VERSION 5.8 ;
BUSBITCHARS "[]" ;
DIVIDERCHAR "/" ;

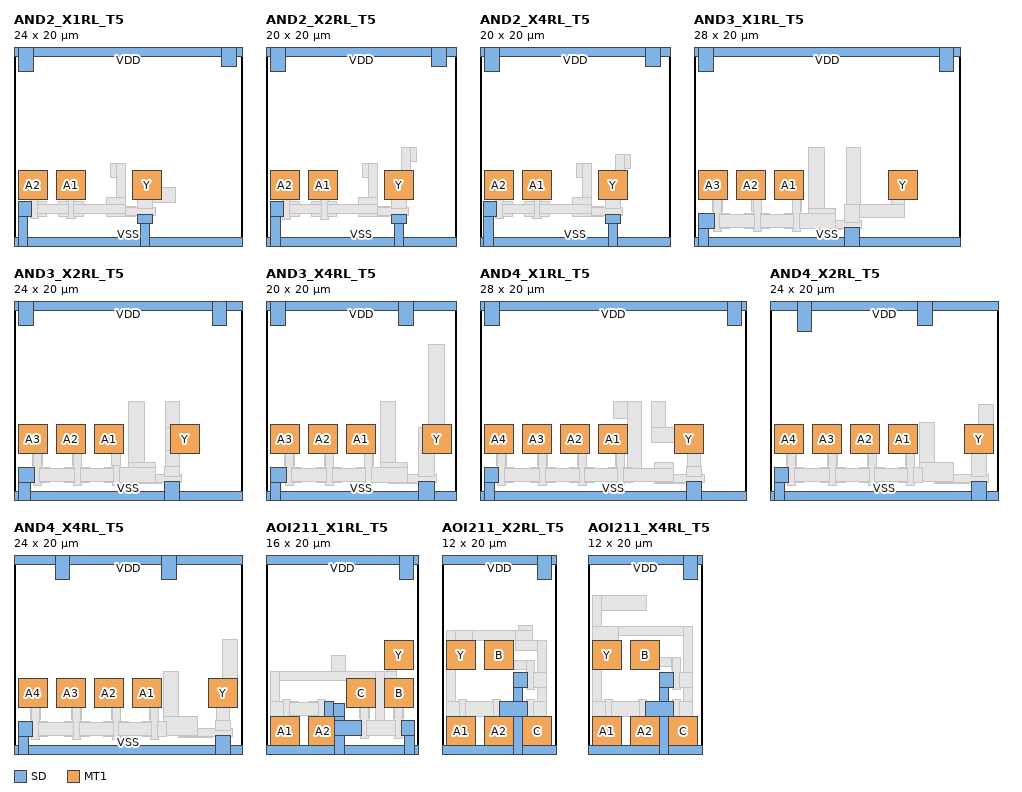
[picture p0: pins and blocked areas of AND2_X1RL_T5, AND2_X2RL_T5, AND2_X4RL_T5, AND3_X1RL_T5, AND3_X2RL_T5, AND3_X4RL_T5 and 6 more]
MACRO AND2_X1RL_T5
  CLASS CORE ;
  ORIGIN 0 0 ;
  FOREIGN AND2_X1RL_T5 0 0 ;
  SIZE 24 BY 20 ;
  SYMMETRY X Y ;
  SITE CoreSite_T5 ;
  PIN VDD
    DIRECTION INOUT ;
    USE POWER ;
    PORT
      LAYER SD ;
        RECT 0 19.5 24 20.5 ;
        RECT 21.8 18.5 23.4 20.5 ;
        RECT 0.5 17.9 2 20.5 ;
    END
  END VDD
  PIN VSS
    DIRECTION INOUT ;
    USE GROUND ;
    PORT
      LAYER SD ;
        RECT 0 -0.5 24 0.5 ;
        RECT 13 1.9 14.6 2.9 ;
        RECT 13.3 -0.5 14.3 2.9 ;
        RECT 0.45 2.7 1.825 4.3 ;
        RECT 0.45 -0.5 1.45 4.3 ;
    END
  END VSS
  PIN A1
    DIRECTION INPUT ;
    USE SIGNAL ;
    PORT
      LAYER MT1 ;
        RECT 4.5 4.5 7.5 7.5 ;
    END
  END A1
  PIN A2
    DIRECTION INPUT ;
    USE SIGNAL ;
    PORT
      LAYER MT1 ;
        RECT 0.5 4.5 3.5 7.5 ;
    END
  END A2
  PIN Y
    DIRECTION INPUT ;
    USE SIGNAL ;
    PORT
      LAYER MT1 ;
        RECT 12.5 4.5 15.5 7.5 ;
    END
  END Y
  OBS
    LAYER VIA1 ;
      RECT 13.25 5.25 14.75 6.75 ;
      RECT 5.25 5.25 6.75 6.75 ;
      RECT 1.25 5.25 2.75 6.75 ;
    LAYER GATE ;
      RECT 9.75 2.7 11.75 4.7 ;
      RECT 9.75 2.7 12.75 3.7 ;
      RECT 9.75 2.775 14.85 3.625 ;
      RECT 4.75 4.75 7.25 7.25 ;
      RECT 5.5 4.55 6.5 7.25 ;
      RECT 5.575 2.45 6.425 7.25 ;
      RECT 0.75 4.75 3.25 7.25 ;
      RECT 1.575 4.55 2.575 7.25 ;
      RECT 1.7 2.45 2.55 7.25 ;
      RECT 12.75 4.75 15.25 7.25 ;
    LAYER CONT ;
      RECT 13.5 5.5 14.5 6.5 ;
      RECT 10.25 3.2 11.25 4.2 ;
    LAYER SD ;
      RECT 12.75 4.75 15.25 7.25 ;
      RECT 13 4.2 17 5.7 ;
      RECT 13 3.5 14.6 7.25 ;
      RECT 10.15 6.75 11.75 8.25 ;
      RECT 10.75 2.7 11.75 8.25 ;
      RECT 9.75 2.7 11.75 4.7 ;
      RECT 6.3 2.7 7.3 4.3 ;
      RECT 6.3 3 11.75 4 ;
      RECT 4.7 2.7 5.7 4.3 ;
      RECT 2.425 2.7 3.425 4.3 ;
      RECT 2.425 3 5.7 4 ;
  END
END AND2_X1RL_T5

MACRO AND2_X2RL_T5
  CLASS CORE ;
  ORIGIN 0 0 ;
  FOREIGN AND2_X2RL_T5 0 0 ;
  SIZE 20 BY 20 ;
  SYMMETRY X Y ;
  SITE CoreSite_T5 ;
  PIN VDD
    DIRECTION INOUT ;
    USE POWER ;
    PORT
      LAYER SD ;
        RECT 0 19.5 20 20.5 ;
        RECT 17.45 18.5 19.05 20.5 ;
        RECT 0.5 17.9 2 20.5 ;
    END
  END VDD
  PIN VSS
    DIRECTION INOUT ;
    USE GROUND ;
    PORT
      LAYER SD ;
        RECT 0 -0.5 20 0.5 ;
        RECT 13.2 1.9 14.8 2.9 ;
        RECT 13.5 -0.5 14.5 2.9 ;
        RECT 0.5 2.65 1.875 4.25 ;
        RECT 0.5 -0.5 1.5 4.25 ;
    END
  END VSS
  PIN A1
    DIRECTION INPUT ;
    USE SIGNAL ;
    PORT
      LAYER MT1 ;
        RECT 4.5 4.5 7.5 7.5 ;
    END
  END A1
  PIN A2
    DIRECTION INPUT ;
    USE SIGNAL ;
    PORT
      LAYER MT1 ;
        RECT 0.5 4.5 3.5 7.5 ;
    END
  END A2
  PIN Y
    DIRECTION INPUT ;
    USE SIGNAL ;
    PORT
      LAYER MT1 ;
        RECT 12.5 4.5 15.5 7.5 ;
    END
  END Y
  OBS
    LAYER VIA1 ;
      RECT 13.25 5.25 14.75 6.75 ;
      RECT 5.25 5.25 6.75 6.75 ;
      RECT 1.25 5.25 2.75 6.75 ;
    LAYER GATE ;
      RECT 9.75 2.7 11.75 4.7 ;
      RECT 9.75 2.7 12.95 3.7 ;
      RECT 9.75 2.775 15.05 3.625 ;
      RECT 4.75 4.75 7.25 7.25 ;
      RECT 5.625 4.5 6.625 7.25 ;
      RECT 5.7 2.4 6.55 7.25 ;
      RECT 0.75 4.75 3.25 7.25 ;
      RECT 1.675 4.5 2.675 7.25 ;
      RECT 1.75 2.4 2.6 7.25 ;
      RECT 12.75 4.75 15.25 7.25 ;
    LAYER CONT ;
      RECT 13.5 5.5 14.5 6.5 ;
      RECT 10.25 3.2 11.25 4.2 ;
    LAYER SD ;
      RECT 14.25 8.5 15.85 10 ;
      RECT 14.25 4.75 15.25 10 ;
      RECT 12.75 4.75 15.25 7.25 ;
      RECT 13.2 3.5 14.8 7.25 ;
      RECT 10.15 6.75 11.75 8.25 ;
      RECT 10.75 2.7 11.75 8.25 ;
      RECT 9.75 2.7 11.75 4.7 ;
      RECT 6.425 2.65 7.425 4.25 ;
      RECT 6.425 3 11.75 4 ;
      RECT 4.825 2.65 5.825 4.25 ;
      RECT 2.475 2.65 3.475 4.25 ;
      RECT 2.475 2.95 5.825 3.95 ;
  END
END AND2_X2RL_T5

MACRO AND2_X4RL_T5
  CLASS CORE ;
  ORIGIN 0 0 ;
  FOREIGN AND2_X4RL_T5 0 0 ;
  SIZE 20 BY 20 ;
  SYMMETRY X Y ;
  SITE CoreSite_T5 ;
  PIN VDD
    DIRECTION INOUT ;
    USE POWER ;
    PORT
      LAYER SD ;
        RECT 0 19.5 20 20.5 ;
        RECT 17.45 18.5 19.05 20.5 ;
        RECT 0.5 17.9 2 20.5 ;
    END
  END VDD
  PIN VSS
    DIRECTION INOUT ;
    USE GROUND ;
    PORT
      LAYER SD ;
        RECT 0 -0.5 20 0.5 ;
        RECT 13.2 1.9 14.8 2.9 ;
        RECT 13.5 -0.5 14.5 2.9 ;
        RECT 0.4 2.7 1.775 4.3 ;
        RECT 0.4 -0.5 1.4 4.3 ;
    END
  END VSS
  PIN A1
    DIRECTION INPUT ;
    USE SIGNAL ;
    PORT
      LAYER MT1 ;
        RECT 4.5 4.5 7.5 7.5 ;
    END
  END A1
  PIN A2
    DIRECTION INPUT ;
    USE SIGNAL ;
    PORT
      LAYER MT1 ;
        RECT 0.5 4.5 3.5 7.5 ;
    END
  END A2
  PIN Y
    DIRECTION INPUT ;
    USE SIGNAL ;
    PORT
      LAYER MT1 ;
        RECT 12.5 4.5 15.5 7.5 ;
    END
  END Y
  OBS
    LAYER VIA1 ;
      RECT 13.25 5.25 14.75 6.75 ;
      RECT 5.25 5.25 6.75 6.75 ;
      RECT 1.25 5.25 2.75 6.75 ;
    LAYER GATE ;
      RECT 9.75 2.7 11.75 4.7 ;
      RECT 9.75 2.7 12.95 3.7 ;
      RECT 9.75 2.775 15.05 3.625 ;
      RECT 4.75 4.75 7.25 7.25 ;
      RECT 5.5 4.55 6.5 7.25 ;
      RECT 5.575 2.45 6.425 7.25 ;
      RECT 0.75 4.75 3.25 7.25 ;
      RECT 1.575 4.55 2.575 7.25 ;
      RECT 1.65 2.45 2.5 7.25 ;
      RECT 12.75 4.75 15.25 7.25 ;
    LAYER CONT ;
      RECT 13.5 5.5 14.5 6.5 ;
      RECT 10.25 3.2 11.25 4.2 ;
    LAYER SD ;
      RECT 14.25 7.75 15.85 9.25 ;
      RECT 14.25 4.75 15.25 9.25 ;
      RECT 12.75 4.75 15.25 7.25 ;
      RECT 13.2 3.5 14.8 7.25 ;
      RECT 10.15 6.75 11.75 8.25 ;
      RECT 10.75 2.7 11.75 8.25 ;
      RECT 9.75 2.7 11.75 4.7 ;
      RECT 6.3 2.7 7.3 4.3 ;
      RECT 6.3 3 11.75 4 ;
      RECT 4.7 2.7 5.7 4.3 ;
      RECT 2.375 2.7 3.375 4.3 ;
      RECT 2.375 3 5.7 4 ;
  END
END AND2_X4RL_T5

MACRO AND3_X1RL_T5
  CLASS CORE ;
  ORIGIN 0 0 ;
  FOREIGN AND3_X1RL_T5 0 0 ;
  SIZE 28 BY 20 ;
  SYMMETRY X Y ;
  SITE CoreSite_T5 ;
  PIN VDD
    DIRECTION INOUT ;
    USE POWER ;
    PORT
      LAYER SD ;
        RECT 0 19.5 28 20.5 ;
        RECT 25.85 17.9 27.35 20.5 ;
        RECT 0.5 17.9 2 20.5 ;
    END
  END VDD
  PIN VSS
    DIRECTION INOUT ;
    USE GROUND ;
    PORT
      LAYER SD ;
        RECT 0 -0.5 28 0.5 ;
        RECT 15.8 -0.5 17.4 1.5 ;
        RECT 0.5 1.4 2.125 3 ;
        RECT 0.5 -0.5 1.5 3 ;
    END
  END VSS
  PIN A1
    DIRECTION INPUT ;
    USE SIGNAL ;
    PORT
      LAYER MT1 ;
        RECT 8.5 4.5 11.5 7.5 ;
    END
  END A1
  PIN A2
    DIRECTION INPUT ;
    USE SIGNAL ;
    PORT
      LAYER MT1 ;
        RECT 4.5 4.5 7.5 7.5 ;
    END
  END A2
  PIN A3
    DIRECTION INPUT ;
    USE SIGNAL ;
    PORT
      LAYER MT1 ;
        RECT 0.5 4.5 3.5 7.5 ;
    END
  END A3
  PIN Y
    DIRECTION INPUT ;
    USE SIGNAL ;
    PORT
      LAYER MT1 ;
        RECT 20.5 4.5 23.5 7.5 ;
    END
  END Y
  OBS
    LAYER VIA1 ;
      RECT 21.25 5.25 22.75 6.75 ;
      RECT 9.25 5.25 10.75 6.75 ;
      RECT 5.25 5.25 6.75 6.75 ;
      RECT 1.25 5.25 2.75 6.75 ;
    LAYER GATE ;
      RECT 12.9 1.3 14.9 3.5 ;
      RECT 12.9 1.3 15.55 2.3 ;
      RECT 12.9 1.375 17.65 2.225 ;
      RECT 8.75 4.75 11.325 7.25 ;
      RECT 10.325 3.25 11.325 7.25 ;
      RECT 10.4 1.15 11.25 7.25 ;
      RECT 4.75 4.75 7.25 7.25 ;
      RECT 6.075 3.25 7.075 7.25 ;
      RECT 6.225 1.15 7.075 7.25 ;
      RECT 0.75 4.75 3.25 7.25 ;
      RECT 1.95 3.25 2.95 7.25 ;
      RECT 2 1.15 2.85 7.25 ;
      RECT 20.75 4.75 23.25 7.25 ;
    LAYER CONT ;
      RECT 21.5 5.5 22.5 6.5 ;
      RECT 13.4 2 14.4 3 ;
    LAYER SD ;
      RECT 16.05 2.6 17.55 9.9 ;
      RECT 20.75 4.75 23.25 7.25 ;
      RECT 20.75 2.6 22.15 7.25 ;
      RECT 15.8 2.6 22.15 4 ;
      RECT 15.8 2.1 17.4 4 ;
      RECT 12.1 1.4 13.7 9.9 ;
      RECT 12.1 1.4 14.9 3.5 ;
      RECT 11.125 1.4 14.9 3 ;
      RECT 9.525 1.4 10.525 3 ;
      RECT 6.95 1.4 7.95 3 ;
      RECT 6.95 1.5 10.525 2.9 ;
      RECT 5.35 1.4 6.35 3 ;
      RECT 2.725 1.4 3.725 3 ;
      RECT 2.725 1.5 6.35 2.9 ;
  END
END AND3_X1RL_T5

MACRO AND3_X2RL_T5
  CLASS CORE ;
  ORIGIN 0 0 ;
  FOREIGN AND3_X2RL_T5 0 0 ;
  SIZE 24 BY 20 ;
  SYMMETRY X Y ;
  SITE CoreSite_T5 ;
  PIN VDD
    DIRECTION INOUT ;
    USE POWER ;
    PORT
      LAYER SD ;
        RECT 0 19.5 24 20.5 ;
        RECT 20.9 17.9 22.4 20.5 ;
        RECT 0.5 17.9 2 20.5 ;
    END
  END VDD
  PIN VSS
    DIRECTION INOUT ;
    USE GROUND ;
    PORT
      LAYER SD ;
        RECT 0 -0.5 24 0.5 ;
        RECT 15.8 -0.5 17.4 1.5 ;
        RECT 0.45 1.4 2.125 3 ;
        RECT 0.45 -0.5 1.75 3 ;
    END
  END VSS
  PIN A1
    DIRECTION INPUT ;
    USE SIGNAL ;
    PORT
      LAYER MT1 ;
        RECT 8.5 4.5 11.5 7.5 ;
    END
  END A1
  PIN A2
    DIRECTION INPUT ;
    USE SIGNAL ;
    PORT
      LAYER MT1 ;
        RECT 4.5 4.5 7.5 7.5 ;
    END
  END A2
  PIN A3
    DIRECTION INPUT ;
    USE SIGNAL ;
    PORT
      LAYER MT1 ;
        RECT 0.5 4.5 3.5 7.5 ;
    END
  END A3
  PIN Y
    DIRECTION INPUT ;
    USE SIGNAL ;
    PORT
      LAYER MT1 ;
        RECT 16.5 4.5 19.5 7.5 ;
    END
  END Y
  OBS
    LAYER VIA1 ;
      RECT 17.25 5.25 18.75 6.75 ;
      RECT 9.25 5.25 10.75 6.75 ;
      RECT 5.25 5.25 6.75 6.75 ;
      RECT 1.25 5.25 2.75 6.75 ;
    LAYER GATE ;
      RECT 12.9 1.3 14.9 3.5 ;
      RECT 12.9 1.3 15.55 2.3 ;
      RECT 12.9 1.375 17.65 2.225 ;
      RECT 8.75 4.75 11.25 7.25 ;
      RECT 10.4 1.15 11.25 7.25 ;
      RECT 10.25 3.25 11.25 7.25 ;
      RECT 4.75 4.75 7.25 7.25 ;
      RECT 6.15 3.25 7.15 7.25 ;
      RECT 6.225 1.15 7.075 7.25 ;
      RECT 0.75 4.75 3.25 7.25 ;
      RECT 1.95 3.25 2.95 7.25 ;
      RECT 2 1.15 2.85 7.25 ;
      RECT 16.75 4.75 19.25 7.25 ;
    LAYER CONT ;
      RECT 17.5 5.5 18.5 6.5 ;
      RECT 13.4 2 14.4 3 ;
    LAYER SD ;
      RECT 15.9 2.1 17.4 9.9 ;
      RECT 15.9 4.75 19.25 7.25 ;
      RECT 15.8 2.1 17.4 3.1 ;
      RECT 12.1 1.4 13.7 9.9 ;
      RECT 12.1 1.4 14.9 3.5 ;
      RECT 11.125 1.4 14.9 3 ;
      RECT 9.525 1.4 10.525 3 ;
      RECT 6.95 1.4 7.95 3 ;
      RECT 6.95 1.5 10.525 2.9 ;
      RECT 5.35 1.4 6.35 3 ;
      RECT 2.725 1.4 3.725 3 ;
      RECT 2.725 1.5 6.35 2.9 ;
  END
END AND3_X2RL_T5

MACRO AND3_X4RL_T5
  CLASS CORE ;
  ORIGIN 0 0 ;
  FOREIGN AND3_X4RL_T5 0 0 ;
  SIZE 20 BY 20 ;
  SYMMETRY X Y ;
  SITE CoreSite_T5 ;
  PIN VDD
    DIRECTION INOUT ;
    USE POWER ;
    PORT
      LAYER SD ;
        RECT 0 19.5 20 20.5 ;
        RECT 13.95 18 15.55 20.5 ;
        RECT 0.5 17.9 2 20.5 ;
    END
  END VDD
  PIN VSS
    DIRECTION INOUT ;
    USE GROUND ;
    PORT
      LAYER SD ;
        RECT 0 -0.5 20 0.5 ;
        RECT 16.1 -0.5 17.7 1.5 ;
        RECT 0.5 1.4 2.125 3 ;
        RECT 0.5 -0.5 1.5 3 ;
    END
  END VSS
  PIN A1
    DIRECTION INPUT ;
    USE SIGNAL ;
    PORT
      LAYER MT1 ;
        RECT 8.5 4.5 11.5 7.5 ;
    END
  END A1
  PIN A2
    DIRECTION INPUT ;
    USE SIGNAL ;
    PORT
      LAYER MT1 ;
        RECT 4.5 4.5 7.5 7.5 ;
    END
  END A2
  PIN A3
    DIRECTION INPUT ;
    USE SIGNAL ;
    PORT
      LAYER MT1 ;
        RECT 0.5 4.5 3.5 7.5 ;
    END
  END A3
  PIN Y
    DIRECTION INPUT ;
    USE SIGNAL ;
    PORT
      LAYER MT1 ;
        RECT 16.5 4.5 19.5 7.5 ;
    END
  END Y
  OBS
    LAYER VIA1 ;
      RECT 17.25 5.25 18.75 6.75 ;
      RECT 9.25 5.25 10.75 6.75 ;
      RECT 5.25 5.25 6.75 6.75 ;
      RECT 1.25 5.25 2.75 6.75 ;
    LAYER GATE ;
      RECT 12.9 1.3 14.9 3.5 ;
      RECT 12.9 1.3 15.85 2.3 ;
      RECT 12.9 1.375 17.95 2.225 ;
      RECT 8.75 4.75 11.325 7.25 ;
      RECT 10.325 3.25 11.325 7.25 ;
      RECT 10.4 1.15 11.25 7.25 ;
      RECT 4.75 4.75 7.25 7.25 ;
      RECT 6.15 3.25 7.15 7.25 ;
      RECT 6.225 1.15 7.075 7.25 ;
      RECT 0.75 4.75 3.25 7.25 ;
      RECT 1.95 3.25 2.95 7.25 ;
      RECT 2 1.15 2.85 7.25 ;
      RECT 16.75 4.75 19.25 7.25 ;
    LAYER CONT ;
      RECT 17.5 5.5 18.5 6.5 ;
      RECT 13.4 2 14.4 3 ;
    LAYER SD ;
      RECT 17.15 4.75 18.75 16 ;
      RECT 16.1 4.75 19.25 7.25 ;
      RECT 16.1 2.1 17.7 7.25 ;
      RECT 12.1 1.4 13.6 9.9 ;
      RECT 12.1 1.4 14.9 3.5 ;
      RECT 11.125 1.4 14.9 3 ;
      RECT 9.525 1.4 10.525 3 ;
      RECT 6.95 1.4 7.95 3 ;
      RECT 6.95 1.5 10.525 2.9 ;
      RECT 5.35 1.4 6.35 3 ;
      RECT 2.725 1.4 3.725 3 ;
      RECT 2.725 1.5 6.35 2.9 ;
  END
END AND3_X4RL_T5

MACRO AND4_X1RL_T5
  CLASS CORE ;
  ORIGIN 0 0 ;
  FOREIGN AND4_X1RL_T5 0 0 ;
  SIZE 28 BY 20 ;
  SYMMETRY X Y ;
  SITE CoreSite_T5 ;
  PIN VDD
    DIRECTION INOUT ;
    USE POWER ;
    PORT
      LAYER SD ;
        RECT 0 19.5 28 20.5 ;
        RECT 26 17.9 27.5 20.5 ;
        RECT 0.5 17.9 2 20.5 ;
    END
  END VDD
  PIN VSS
    DIRECTION INOUT ;
    USE GROUND ;
    PORT
      LAYER SD ;
        RECT 0 -0.5 28 0.5 ;
        RECT 21.75 -0.5 23.35 1.5 ;
        RECT 0.5 1.4 1.95 3 ;
        RECT 0.5 -0.5 1.5 3 ;
    END
  END VSS
  PIN A1
    DIRECTION INPUT ;
    USE SIGNAL ;
    PORT
      LAYER MT1 ;
        RECT 12.5 4.5 15.5 7.5 ;
    END
  END A1
  PIN A2
    DIRECTION INPUT ;
    USE SIGNAL ;
    PORT
      LAYER MT1 ;
        RECT 8.5 4.5 11.5 7.5 ;
    END
  END A2
  PIN A3
    DIRECTION INPUT ;
    USE SIGNAL ;
    PORT
      LAYER MT1 ;
        RECT 4.5 4.5 7.5 7.5 ;
    END
  END A3
  PIN A4
    DIRECTION INPUT ;
    USE SIGNAL ;
    PORT
      LAYER MT1 ;
        RECT 0.5 4.5 3.5 7.5 ;
    END
  END A4
  PIN Y
    DIRECTION INPUT ;
    USE SIGNAL ;
    PORT
      LAYER MT1 ;
        RECT 20.5 4.5 23.5 7.5 ;
    END
  END Y
  OBS
    LAYER VIA1 ;
      RECT 21.25 5.25 22.75 6.75 ;
      RECT 13.25 5.25 14.75 6.75 ;
      RECT 9.25 5.25 10.75 6.75 ;
      RECT 5.25 5.25 6.75 6.75 ;
      RECT 1.25 5.25 2.75 6.75 ;
    LAYER GATE ;
      RECT 18.35 1.3 20.35 3.5 ;
      RECT 18.35 1.3 21.5 2.3 ;
      RECT 18.35 1.375 23.6 2.225 ;
      RECT 12.75 4.75 15.25 7.25 ;
      RECT 14.25 3.25 15.25 7.25 ;
      RECT 14.35 1.15 15.2 7.25 ;
      RECT 8.75 4.75 11.25 7.25 ;
      RECT 10.25 3.25 11.25 7.25 ;
      RECT 10.325 1.15 11.175 7.25 ;
      RECT 4.75 4.75 7.25 7.25 ;
      RECT 6.1 3.25 7.1 7.25 ;
      RECT 6.175 1.15 7.025 7.25 ;
      RECT 0.75 4.75 3.25 7.25 ;
      RECT 1.75 3.25 2.75 7.25 ;
      RECT 1.825 1.15 2.675 7.25 ;
      RECT 20.75 4.75 23.25 7.25 ;
    LAYER CONT ;
      RECT 21.5 5.5 22.5 6.5 ;
      RECT 18.85 2 19.85 3 ;
    LAYER SD ;
      RECT 18 5.65 19.5 9.9 ;
      RECT 18 5.65 23.25 7.25 ;
      RECT 21.85 2.1 23.25 7.25 ;
      RECT 20.75 4.75 23.25 7.25 ;
      RECT 21.75 2.1 23.35 3.1 ;
      RECT 14.1 8.15 17 9.9 ;
      RECT 15.5 1.5 17 9.9 ;
      RECT 18.35 1.5 20.35 3.5 ;
      RECT 15.075 1.4 16.075 3 ;
      RECT 15.075 1.5 20.35 2.9 ;
      RECT 13.475 1.4 14.475 3 ;
      RECT 11.05 1.4 12.05 3 ;
      RECT 11.05 1.5 14.475 2.9 ;
      RECT 9.45 1.4 10.45 3 ;
      RECT 6.9 1.4 7.9 3 ;
      RECT 6.9 1.5 10.45 2.9 ;
      RECT 5.3 1.4 6.3 3 ;
      RECT 2.55 1.4 3.55 3 ;
      RECT 2.55 1.5 6.3 2.9 ;
  END
END AND4_X1RL_T5

MACRO AND4_X2RL_T5
  CLASS CORE ;
  ORIGIN 0 0 ;
  FOREIGN AND4_X2RL_T5 0 0 ;
  SIZE 24 BY 20 ;
  SYMMETRY X Y ;
  SITE CoreSite_T5 ;
  PIN VDD
    DIRECTION INOUT ;
    USE POWER ;
    PORT
      LAYER SD ;
        RECT 0 19.5 24 20.5 ;
        RECT 15.5 18 17.1 20.5 ;
        RECT 2.85 17.35 4.35 20.5 ;
    END
  END VDD
  PIN VSS
    DIRECTION INOUT ;
    USE GROUND ;
    PORT
      LAYER SD ;
        RECT 0 -0.5 24 0.5 ;
        RECT 21.175 -0.5 22.775 1.5 ;
        RECT 0.5 1.4 1.95 3 ;
        RECT 0.5 -0.5 1.5 3 ;
    END
  END VSS
  PIN A1
    DIRECTION INPUT ;
    USE SIGNAL ;
    PORT
      LAYER MT1 ;
        RECT 12.5 4.5 15.5 7.5 ;
    END
  END A1
  PIN A2
    DIRECTION INPUT ;
    USE SIGNAL ;
    PORT
      LAYER MT1 ;
        RECT 8.5 4.5 11.5 7.5 ;
    END
  END A2
  PIN A3
    DIRECTION INPUT ;
    USE SIGNAL ;
    PORT
      LAYER MT1 ;
        RECT 4.5 4.5 7.5 7.5 ;
    END
  END A3
  PIN A4
    DIRECTION INPUT ;
    USE SIGNAL ;
    PORT
      LAYER MT1 ;
        RECT 0.5 4.5 3.5 7.5 ;
    END
  END A4
  PIN Y
    DIRECTION INPUT ;
    USE SIGNAL ;
    PORT
      LAYER MT1 ;
        RECT 20.5 4.5 23.5 7.5 ;
    END
  END Y
  OBS
    LAYER VIA1 ;
      RECT 21.25 5.25 22.75 6.75 ;
      RECT 13.25 5.25 14.75 6.75 ;
      RECT 9.25 5.25 10.75 6.75 ;
      RECT 5.25 5.25 6.75 6.75 ;
      RECT 1.25 5.25 2.75 6.75 ;
    LAYER GATE ;
      RECT 17.35 1.3 19.35 3.5 ;
      RECT 17.35 1.3 20.925 2.3 ;
      RECT 17.35 1.375 23.025 2.225 ;
      RECT 12.75 4.75 15.25 7.25 ;
      RECT 14.25 3.25 15.25 7.25 ;
      RECT 14.35 1.15 15.2 7.25 ;
      RECT 8.75 4.75 11.25 7.25 ;
      RECT 10.25 3.25 11.25 7.25 ;
      RECT 10.325 1.15 11.175 7.25 ;
      RECT 4.75 4.75 7.25 7.25 ;
      RECT 6.1 3.25 7.1 7.25 ;
      RECT 6.175 1.15 7.025 7.25 ;
      RECT 0.75 4.75 3.25 7.25 ;
      RECT 1.75 3.25 2.75 7.25 ;
      RECT 1.825 1.15 2.675 7.25 ;
      RECT 20.75 4.75 23.25 7.25 ;
    LAYER CONT ;
      RECT 21.5 5.5 22.5 6.5 ;
      RECT 17.85 2 18.85 3 ;
    LAYER SD ;
      RECT 21.9 5.3 23.5 9.6 ;
      RECT 21.175 2.1 22.775 7.25 ;
      RECT 20.75 4.75 23.25 7.25 ;
      RECT 15.75 1.5 17.35 7.75 ;
      RECT 15.75 1.5 19.35 3.5 ;
      RECT 15.075 1.4 16.075 3 ;
      RECT 13.475 1.4 14.475 3 ;
      RECT 11.05 1.4 12.05 3 ;
      RECT 11.05 1.5 14.475 2.9 ;
      RECT 9.45 1.4 10.45 3 ;
      RECT 6.9 1.4 7.9 3 ;
      RECT 6.9 1.5 10.45 2.9 ;
      RECT 5.3 1.4 6.3 3 ;
      RECT 2.55 1.4 3.55 3 ;
      RECT 2.55 1.5 6.3 2.9 ;
  END
END AND4_X2RL_T5

MACRO AND4_X4RL_T5
  CLASS CORE ;
  ORIGIN 0 0 ;
  FOREIGN AND4_X4RL_T5 0 0 ;
  SIZE 24 BY 20 ;
  SYMMETRY X Y ;
  SITE CoreSite_T5 ;
  PIN VDD
    DIRECTION INOUT ;
    USE POWER ;
    PORT
      LAYER SD ;
        RECT 0 19.5 24 20.5 ;
        RECT 15.5 18 17.1 20.5 ;
        RECT 4.35 17.9 5.85 20.5 ;
    END
  END VDD
  PIN VSS
    DIRECTION INOUT ;
    USE GROUND ;
    PORT
      LAYER SD ;
        RECT 0 -0.5 24 0.5 ;
        RECT 21.175 -0.5 22.775 1.5 ;
        RECT 0.5 1.4 1.95 3 ;
        RECT 0.5 -0.5 1.5 3 ;
    END
  END VSS
  PIN A1
    DIRECTION INPUT ;
    USE SIGNAL ;
    PORT
      LAYER MT1 ;
        RECT 12.5 4.5 15.5 7.5 ;
    END
  END A1
  PIN A2
    DIRECTION INPUT ;
    USE SIGNAL ;
    PORT
      LAYER MT1 ;
        RECT 8.5 4.5 11.5 7.5 ;
    END
  END A2
  PIN A3
    DIRECTION INPUT ;
    USE SIGNAL ;
    PORT
      LAYER MT1 ;
        RECT 4.5 4.5 7.5 7.5 ;
    END
  END A3
  PIN A4
    DIRECTION INPUT ;
    USE SIGNAL ;
    PORT
      LAYER MT1 ;
        RECT 0.5 4.5 3.5 7.5 ;
    END
  END A4
  PIN Y
    DIRECTION INPUT ;
    USE SIGNAL ;
    PORT
      LAYER MT1 ;
        RECT 20.5 4.5 23.5 7.5 ;
    END
  END Y
  OBS
    LAYER VIA1 ;
      RECT 21.25 5.25 22.75 6.75 ;
      RECT 13.25 5.25 14.75 6.75 ;
      RECT 9.25 5.25 10.75 6.75 ;
      RECT 5.25 5.25 6.75 6.75 ;
      RECT 1.25 5.25 2.75 6.75 ;
    LAYER GATE ;
      RECT 17.35 1.3 19.35 3.5 ;
      RECT 17.35 1.3 20.925 2.3 ;
      RECT 17.35 1.375 23.025 2.225 ;
      RECT 12.75 4.75 15.25 7.25 ;
      RECT 14.25 3.25 15.25 7.25 ;
      RECT 14.35 1.15 15.2 7.25 ;
      RECT 8.75 4.75 11.25 7.25 ;
      RECT 10.25 3.25 11.25 7.25 ;
      RECT 10.325 1.15 11.175 7.25 ;
      RECT 4.75 4.75 7.25 7.25 ;
      RECT 6.1 3.25 7.1 7.25 ;
      RECT 6.175 1.15 7.025 7.25 ;
      RECT 0.75 4.75 3.25 7.25 ;
      RECT 1.75 3.25 2.75 7.25 ;
      RECT 1.825 1.15 2.675 7.25 ;
      RECT 20.75 4.75 23.25 7.25 ;
    LAYER CONT ;
      RECT 21.5 5.5 22.5 6.5 ;
      RECT 17.85 2 18.85 3 ;
    LAYER SD ;
      RECT 21.9 4.75 23.5 11.6 ;
      RECT 20.75 4.75 23.5 7.25 ;
      RECT 21.275 2.1 22.675 7.25 ;
      RECT 21.175 2.1 22.775 3.1 ;
      RECT 15.75 1.5 17.35 8.3 ;
      RECT 15.75 1.5 19.35 3.5 ;
      RECT 15.075 1.4 16.075 3 ;
      RECT 13.475 1.4 14.475 3 ;
      RECT 11.05 1.4 12.05 3 ;
      RECT 11.05 1.5 14.475 2.9 ;
      RECT 9.45 1.4 10.45 3 ;
      RECT 6.9 1.4 7.9 3 ;
      RECT 6.9 1.5 10.45 2.9 ;
      RECT 5.3 1.4 6.3 3 ;
      RECT 2.55 1.4 3.55 3 ;
      RECT 2.55 1.5 6.3 2.9 ;
  END
END AND4_X4RL_T5

MACRO AOI211_X1RL_T5
  CLASS CORE ;
  ORIGIN 0 0 ;
  FOREIGN AOI211_X1RL_T5 0 0 ;
  SIZE 16 BY 20 ;
  SYMMETRY X Y ;
  SITE CoreSite_T5 ;
  PIN VDD
    DIRECTION INOUT ;
    USE POWER ;
    PORT
      LAYER SD ;
        RECT 0 19.5 16 20.5 ;
        RECT 14 17.9 15.5 20.5 ;
    END
  END VDD
  PIN VSS
    DIRECTION INOUT ;
    USE GROUND ;
    PORT
      LAYER SD ;
        RECT 0 -0.5 16 0.5 ;
        RECT 14.225 1.5 15.6 3.1 ;
        RECT 14.6 -0.5 15.6 3.1 ;
        RECT 7.25 1.5 10.025 3.1 ;
        RECT 6.125 3.5 8.25 4.9 ;
        RECT 7.25 -0.5 8.25 4.9 ;
        RECT 6.125 3.5 7.125 5.1 ;
    END
  END VSS
  PIN A1
    DIRECTION INPUT ;
    USE SIGNAL ;
    PORT
      LAYER MT1 ;
        RECT 0.5 0.5 3.5 3.5 ;
    END
  END A1
  PIN A2
    DIRECTION INPUT ;
    USE SIGNAL ;
    PORT
      LAYER MT1 ;
        RECT 4.5 0.5 7.5 3.5 ;
    END
  END A2
  PIN B
    DIRECTION INPUT ;
    USE SIGNAL ;
    PORT
      LAYER MT1 ;
        RECT 12.5 4.5 15.5 7.5 ;
    END
  END B
  PIN C
    DIRECTION INPUT ;
    USE SIGNAL ;
    PORT
      LAYER MT1 ;
        RECT 8.5 4.5 11.5 7.5 ;
    END
  END C
  PIN Y
    DIRECTION INPUT ;
    USE SIGNAL ;
    PORT
      LAYER MT1 ;
        RECT 12.5 8.5 15.5 11.5 ;
    END
  END Y
  OBS
    LAYER VIA1 ;
      RECT 13.25 5.05 14.75 6.55 ;
      RECT 13.25 9.25 14.75 10.75 ;
      RECT 9 5.05 10.5 6.55 ;
      RECT 5 1.25 6.5 2.75 ;
      RECT 1.25 1.25 2.75 2.75 ;
    LAYER GATE ;
      RECT 12.75 4.55 15.25 7.05 ;
      RECT 13.45 3.35 14.45 7.05 ;
      RECT 13.5 1.25 14.35 7.05 ;
      RECT 8.5 4.55 11 7.05 ;
      RECT 9.85 3.35 10.85 7.05 ;
      RECT 9.9 1.25 10.75 7.05 ;
      RECT 5.4 0.75 6.25 5.35 ;
      RECT 4.5 0.75 7 3.25 ;
      RECT 1.7 0.75 2.55 5.35 ;
      RECT 0.75 0.75 3.25 3.25 ;
      RECT 12.75 8.75 15.25 11.25 ;
    LAYER CONT ;
      RECT 13.5 9.5 14.5 10.5 ;
    LAYER SD ;
      RECT 12.75 8.75 15.25 11.25 ;
      RECT 6.9 7.3 8.4 9.9 ;
      RECT 12.75 7.3 13.75 11.25 ;
      RECT 0.45 7.3 13.75 8.3 ;
      RECT 11.5 1.5 12.5 8.3 ;
      RECT 0.45 3.5 1.45 8.3 ;
      RECT 0.45 3.5 1.825 5.1 ;
      RECT 10.625 1.5 13.625 3.1 ;
      RECT 4.525 3.5 5.525 5.1 ;
      RECT 2.425 3.5 3.425 5.1 ;
      RECT 2.425 3.6 5.525 5 ;
  END
END AOI211_X1RL_T5

MACRO AOI211_X2RL_T5
  CLASS CORE ;
  ORIGIN 0 0 ;
  FOREIGN AOI211_X2RL_T5 0 0 ;
  SIZE 12 BY 20 ;
  SYMMETRY X Y ;
  SITE CoreSite_T5 ;
  PIN VDD
    DIRECTION INOUT ;
    USE POWER ;
    PORT
      LAYER SD ;
        RECT 0 19.5 12 20.5 ;
        RECT 10 17.9 11.5 20.5 ;
    END
  END VDD
  PIN VSS
    DIRECTION INOUT ;
    USE GROUND ;
    PORT
      LAYER SD ;
        RECT 0 -0.5 12 0.5 ;
        RECT 6.025 3.5 9.025 5.1 ;
        RECT 7.5 6.6 9 8.2 ;
        RECT 7.5 -0.5 8.5 8.2 ;
    END
  END VSS
  PIN A1
    DIRECTION INPUT ;
    USE SIGNAL ;
    PORT
      LAYER MT1 ;
        RECT 0.5 0.5 3.5 3.5 ;
    END
  END A1
  PIN A2
    DIRECTION INPUT ;
    USE SIGNAL ;
    PORT
      LAYER MT1 ;
        RECT 4.5 0.5 7.5 3.5 ;
    END
  END A2
  PIN B
    DIRECTION INPUT ;
    USE SIGNAL ;
    PORT
      LAYER MT1 ;
        RECT 4.5 8.5 7.5 11.5 ;
    END
  END B
  PIN C
    DIRECTION INPUT ;
    USE SIGNAL ;
    PORT
      LAYER MT1 ;
        RECT 8.5 0.5 11.5 3.5 ;
    END
  END C
  PIN Y
    DIRECTION INPUT ;
    USE SIGNAL ;
    PORT
      LAYER MT1 ;
        RECT 0.5 8.5 3.5 11.5 ;
    END
  END Y
  OBS
    LAYER VIA1 ;
      RECT 9.25 1.25 10.75 2.75 ;
      RECT 5.25 1.25 6.75 2.75 ;
      RECT 5.25 9.25 6.75 10.75 ;
      RECT 1.25 1.25 2.75 2.75 ;
      RECT 1.25 9.25 2.75 10.75 ;
    LAYER GATE ;
      RECT 8.9 0.75 9.75 5.35 ;
      RECT 8.75 0.75 11.25 3.25 ;
      RECT 4.75 8.75 7.25 11.25 ;
      RECT 5.5 8.45 9.75 9.45 ;
      RECT 8.875 6.35 9.725 9.45 ;
      RECT 5.3 0.75 6.15 5.35 ;
      RECT 4.75 0.75 7.25 3.25 ;
      RECT 1.7 0.75 2.55 5.35 ;
      RECT 0.75 0.75 3.25 3.25 ;
      RECT 0.75 8.75 3.25 11.25 ;
    LAYER CONT ;
      RECT 1.5 9.5 2.5 10.5 ;
    LAYER SD ;
      RECT 8 10.5 9.5 13.1 ;
      RECT 0.45 11.55 9.5 12.55 ;
      RECT 7.75 10.5 9.5 12.55 ;
      RECT 0.45 8.75 3.25 12.55 ;
      RECT 7.75 10.5 11 11.5 ;
      RECT 10 3.5 11 11.5 ;
      RECT 0.45 3.5 1.45 12.55 ;
      RECT 9.6 6.6 11 8.2 ;
      RECT 9.625 3.5 11 5.1 ;
      RECT 0.45 3.5 1.825 5.1 ;
      RECT 2.425 3.5 5.425 5.1 ;
  END
END AOI211_X2RL_T5

MACRO AOI211_X4RL_T5
  CLASS CORE ;
  ORIGIN 0 0 ;
  FOREIGN AOI211_X4RL_T5 0 0 ;
  SIZE 12 BY 20 ;
  SYMMETRY X Y ;
  SITE CoreSite_T5 ;
  PIN VDD
    DIRECTION INOUT ;
    USE POWER ;
    PORT
      LAYER SD ;
        RECT 0 19.5 12 20.5 ;
        RECT 10 17.9 11.5 20.5 ;
    END
  END VDD
  PIN VSS
    DIRECTION INOUT ;
    USE GROUND ;
    PORT
      LAYER SD ;
        RECT 0 -0.5 12 0.5 ;
        RECT 6.025 3.5 9.025 5.1 ;
        RECT 7.5 6.6 9 8.2 ;
        RECT 7.5 -0.5 8.5 8.2 ;
    END
  END VSS
  PIN A1
    DIRECTION INPUT ;
    USE SIGNAL ;
    PORT
      LAYER MT1 ;
        RECT 0.5 0.5 3.5 3.5 ;
    END
  END A1
  PIN A2
    DIRECTION INPUT ;
    USE SIGNAL ;
    PORT
      LAYER MT1 ;
        RECT 4.5 0.5 7.5 3.5 ;
    END
  END A2
  PIN B
    DIRECTION INPUT ;
    USE SIGNAL ;
    PORT
      LAYER MT1 ;
        RECT 4.5 8.5 7.5 11.5 ;
    END
  END B
  PIN C
    DIRECTION INPUT ;
    USE SIGNAL ;
    PORT
      LAYER MT1 ;
        RECT 8.5 0.5 11.5 3.5 ;
    END
  END C
  PIN Y
    DIRECTION INPUT ;
    USE SIGNAL ;
    PORT
      LAYER MT1 ;
        RECT 0.5 8.5 3.5 11.5 ;
    END
  END Y
  OBS
    LAYER VIA1 ;
      RECT 9.25 1.25 10.75 2.75 ;
      RECT 5.25 1.25 6.75 2.75 ;
      RECT 5.25 9.25 6.75 10.75 ;
      RECT 1.25 1.25 2.75 2.75 ;
      RECT 1.25 9.25 2.75 10.75 ;
    LAYER GATE ;
      RECT 8.9 0.75 9.75 5.35 ;
      RECT 8.75 0.75 11.25 3.25 ;
      RECT 4.75 8.75 7.25 11.25 ;
      RECT 4.75 8.75 9.75 9.75 ;
      RECT 8.75 8.45 9.75 9.75 ;
      RECT 8.875 6.35 9.725 9.75 ;
      RECT 5.3 0.75 6.15 5.35 ;
      RECT 4.75 0.75 7.25 3.25 ;
      RECT 1.7 0.75 2.55 5.35 ;
      RECT 0.75 0.75 3.25 3.25 ;
      RECT 0.75 8.75 3.25 11.25 ;
    LAYER CONT ;
      RECT 1.5 9.5 2.5 10.5 ;
    LAYER SD ;
      RECT 0.45 14.7 6.15 16.3 ;
      RECT 0.45 3.5 1.45 16.3 ;
      RECT 0.45 12.05 11 13.05 ;
      RECT 10 3.5 11 13.05 ;
      RECT 0.45 8.75 3.25 13.05 ;
      RECT 9.6 6.6 11 8.2 ;
      RECT 9.625 3.5 11 5.1 ;
      RECT 0.45 3.5 1.825 5.1 ;
      RECT 2.425 3.5 5.425 5.1 ;
  END
END AOI211_X4RL_T5

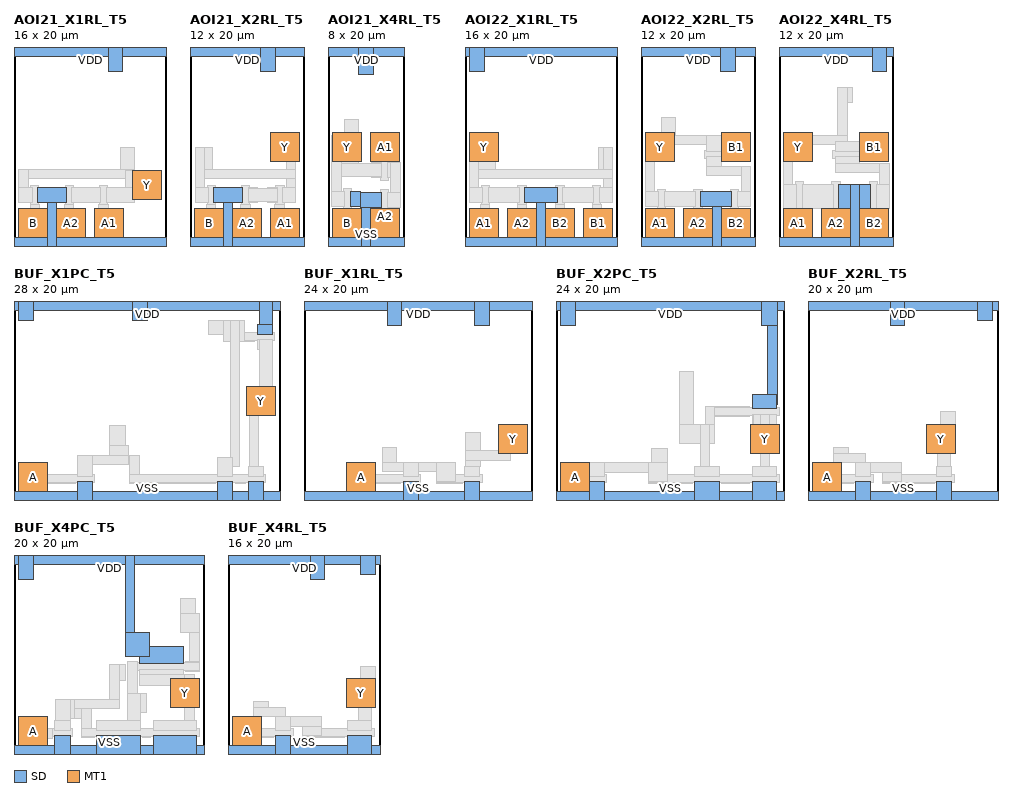
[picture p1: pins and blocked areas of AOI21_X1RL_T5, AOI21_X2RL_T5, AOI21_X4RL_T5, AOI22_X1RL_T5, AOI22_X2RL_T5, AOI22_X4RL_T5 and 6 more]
MACRO AOI21_X1RL_T5
  CLASS CORE ;
  ORIGIN 0 0 ;
  FOREIGN AOI21_X1RL_T5 0 0 ;
  SIZE 16 BY 20 ;
  SYMMETRY X Y ;
  SITE CoreSite_T5 ;
  PIN VDD
    DIRECTION INOUT ;
    USE POWER ;
    PORT
      LAYER SD ;
        RECT 0 19.5 16 20.5 ;
        RECT 9.9 17.9 11.45 20.5 ;
    END
  END VDD
  PIN VSS
    DIRECTION INOUT ;
    USE GROUND ;
    PORT
      LAYER SD ;
        RECT 0 -0.5 16 0.5 ;
        RECT 2.5 4.15 5.5 5.75 ;
        RECT 3.5 -0.5 4.5 5.75 ;
    END
  END VSS
  PIN A1
    DIRECTION INPUT ;
    USE SIGNAL ;
    PORT
      LAYER MT1 ;
        RECT 8.5 0.5 11.5 3.5 ;
    END
  END A1
  PIN A2
    DIRECTION INPUT ;
    USE SIGNAL ;
    PORT
      LAYER MT1 ;
        RECT 4.5 0.5 7.5 3.5 ;
    END
  END A2
  PIN B
    DIRECTION INPUT ;
    USE SIGNAL ;
    PORT
      LAYER MT1 ;
        RECT 0.5 0.5 3.5 3.5 ;
    END
  END B
  PIN Y
    DIRECTION INPUT ;
    USE SIGNAL ;
    PORT
      LAYER MT1 ;
        RECT 12.5 4.5 15.5 7.5 ;
    END
  END Y
  OBS
    LAYER VIA1 ;
      RECT 13.25 5.25 14.75 6.75 ;
      RECT 9.25 1.25 10.75 2.75 ;
      RECT 5.25 1.25 6.75 2.75 ;
      RECT 1.25 1.25 2.75 2.75 ;
    LAYER GATE ;
      RECT 8.975 0.75 9.825 6 ;
      RECT 8.9 0.75 9.9 3.9 ;
      RECT 8.75 0.75 11.25 3.25 ;
      RECT 5.375 0.75 6.225 6 ;
      RECT 5.3 0.75 6.3 3.9 ;
      RECT 4.75 0.75 7.25 3.25 ;
      RECT 1.775 0.75 2.625 6 ;
      RECT 1.7 0.75 2.7 3.9 ;
      RECT 0.75 0.75 3.25 3.25 ;
      RECT 12.75 4.75 15.25 7.25 ;
    LAYER CONT ;
      RECT 13.5 5.5 14.5 6.5 ;
    LAYER SD ;
      RECT 11.2 6.65 12.7 9.9 ;
      RECT 0.5 6.65 12.7 7.65 ;
      RECT 11.7 4.5 15.5 7.5 ;
      RECT 0.5 4.15 1.5 7.65 ;
      RECT 9.7 4.15 12.7 5.75 ;
      RECT 0.5 4.15 1.9 5.75 ;
      RECT 6.1 4.15 9.1 5.75 ;
  END
END AOI21_X1RL_T5

MACRO AOI21_X2RL_T5
  CLASS CORE ;
  ORIGIN 0 0 ;
  FOREIGN AOI21_X2RL_T5 0 0 ;
  SIZE 12 BY 20 ;
  SYMMETRY X Y ;
  SITE CoreSite_T5 ;
  PIN VDD
    DIRECTION INOUT ;
    USE POWER ;
    PORT
      LAYER SD ;
        RECT 0 19.5 12 20.5 ;
        RECT 7.4 17.9 8.95 20.5 ;
    END
  END VDD
  PIN VSS
    DIRECTION INOUT ;
    USE GROUND ;
    PORT
      LAYER SD ;
        RECT 0 -0.5 12 0.5 ;
        RECT 2.525 4.15 5.525 5.75 ;
        RECT 3.525 -0.5 4.525 5.75 ;
    END
  END VSS
  PIN A1
    DIRECTION INPUT ;
    USE SIGNAL ;
    PORT
      LAYER MT1 ;
        RECT 8.5 0.5 11.5 3.5 ;
    END
  END A1
  PIN A2
    DIRECTION INPUT ;
    USE SIGNAL ;
    PORT
      LAYER MT1 ;
        RECT 4.5 0.5 7.5 3.5 ;
    END
  END A2
  PIN B
    DIRECTION INPUT ;
    USE SIGNAL ;
    PORT
      LAYER MT1 ;
        RECT 0.5 0.5 3.5 3.5 ;
    END
  END B
  PIN Y
    DIRECTION INPUT ;
    USE SIGNAL ;
    PORT
      LAYER MT1 ;
        RECT 8.5 8.5 11.5 11.5 ;
    END
  END Y
  OBS
    LAYER VIA1 ;
      RECT 9.25 1.25 10.75 2.75 ;
      RECT 9.25 9.25 10.75 10.75 ;
      RECT 5.275 1.25 6.775 2.75 ;
      RECT 1.25 1.25 2.75 2.75 ;
    LAYER GATE ;
      RECT 9.05 0.75 9.9 6 ;
      RECT 8.9 0.75 9.9 3.9 ;
      RECT 8.75 0.75 11.25 3.25 ;
      RECT 5.4 0.75 6.25 6 ;
      RECT 5.325 0.75 6.325 3.9 ;
      RECT 4.775 0.75 7.275 3.25 ;
      RECT 1.8 0.75 2.65 6 ;
      RECT 1.7 0.75 2.7 3.9 ;
      RECT 0.75 0.75 3.25 3.25 ;
      RECT 8.75 8.75 11.25 11.25 ;
    LAYER CONT ;
      RECT 9.5 9.5 10.5 10.5 ;
    LAYER SD ;
      RECT 8.75 8.75 11.25 11.25 ;
      RECT 0.55 6.65 2.4 9.9 ;
      RECT 10.15 4.15 11.15 11.25 ;
      RECT 0.55 6.65 11.15 7.65 ;
      RECT 0.55 4.15 1.55 9.9 ;
      RECT 9.775 4.15 11.15 5.75 ;
      RECT 0.55 4.15 1.925 5.75 ;
      RECT 8.175 4.15 9.175 5.75 ;
      RECT 6.125 4.15 7.125 5.75 ;
      RECT 6.125 4.25 9.175 5.65 ;
  END
END AOI21_X2RL_T5

MACRO AOI21_X4RL_T5
  CLASS CORE ;
  ORIGIN 0 0 ;
  FOREIGN AOI21_X4RL_T5 0 0 ;
  SIZE 8 BY 20 ;
  SYMMETRY X Y ;
  SITE CoreSite_T5 ;
  PIN VDD
    DIRECTION INOUT ;
    USE POWER ;
    PORT
      LAYER SD ;
        RECT 0 19.5 8 20.5 ;
        RECT 3.25 17.65 4.75 20.5 ;
    END
  END VDD
  PIN VSS
    DIRECTION INOUT ;
    USE GROUND ;
    PORT
      LAYER SD ;
        RECT 0 -0.5 8 0.5 ;
        RECT 3.375 3.65 5.625 5.25 ;
        RECT 3.5 -0.5 4.5 5.25 ;
        RECT 2.375 3.75 3.375 5.35 ;
    END
  END VSS
  PIN A1
    DIRECTION INPUT ;
    USE SIGNAL ;
    PORT
      LAYER MT1 ;
        RECT 4.5 8.5 7.5 11.5 ;
    END
  END A1
  PIN A2
    DIRECTION INPUT ;
    USE SIGNAL ;
    PORT
      LAYER MT1 ;
        RECT 4.5 0.5 7.5 3.5 ;
    END
  END A2
  PIN B
    DIRECTION INPUT ;
    USE SIGNAL ;
    PORT
      LAYER MT1 ;
        RECT 0.5 0.5 3.5 3.5 ;
    END
  END B
  PIN Y
    DIRECTION INPUT ;
    USE SIGNAL ;
    PORT
      LAYER MT1 ;
        RECT 0.5 8.5 3.5 11.5 ;
    END
  END Y
  OBS
    LAYER VIA1 ;
      RECT 5.25 1.25 6.75 2.75 ;
      RECT 5.25 9.25 6.75 10.75 ;
      RECT 1.25 1.25 2.75 2.75 ;
      RECT 1.25 9.25 2.75 10.75 ;
    LAYER GATE ;
      RECT 5.5 0.75 6.35 5.5 ;
      RECT 5.425 0.75 6.425 3.4 ;
      RECT 4.75 0.75 7.25 3.25 ;
      RECT 4.75 8.75 7.25 11.25 ;
      RECT 5.425 8.6 6.425 11.25 ;
      RECT 5.5 6.5 6.35 11.25 ;
      RECT 1.65 0.75 2.5 5.6 ;
      RECT 1.65 0.75 2.65 3.5 ;
      RECT 0.75 0.75 3.25 3.25 ;
      RECT 0.75 8.75 3.25 11.25 ;
    LAYER CONT ;
      RECT 1.5 9.5 2.5 10.5 ;
    LAYER SD ;
      RECT 6.225 6.75 7.6 8.35 ;
      RECT 6.6 3.65 7.6 8.35 ;
      RECT 6.225 3.65 7.6 5.25 ;
      RECT 1.75 6.9 3.25 12.85 ;
      RECT 0.4 6.9 3.25 11.25 ;
      RECT 4.625 6.75 5.625 8.35 ;
      RECT 0.4 6.9 5.625 8.3 ;
      RECT 0.4 3.75 1.4 11.25 ;
      RECT 0.4 3.75 1.775 5.35 ;
  END
END AOI21_X4RL_T5

MACRO AOI22_X1RL_T5
  CLASS CORE ;
  ORIGIN 0 0 ;
  FOREIGN AOI22_X1RL_T5 0 0 ;
  SIZE 16 BY 20 ;
  SYMMETRY X Y ;
  SITE CoreSite_T5 ;
  PIN VDD
    DIRECTION INOUT ;
    USE POWER ;
    PORT
      LAYER SD ;
        RECT 0 19.5 16 20.5 ;
        RECT 0.5 17.9 2.05 20.5 ;
    END
  END VDD
  PIN VSS
    DIRECTION INOUT ;
    USE GROUND ;
    PORT
      LAYER SD ;
        RECT 0 -0.5 16 0.5 ;
        RECT 6.3 4.15 9.7 5.75 ;
        RECT 7.5 -0.5 8.5 5.75 ;
    END
  END VSS
  PIN A1
    DIRECTION INPUT ;
    USE SIGNAL ;
    PORT
      LAYER MT1 ;
        RECT 0.5 0.5 3.5 3.5 ;
    END
  END A1
  PIN A2
    DIRECTION INPUT ;
    USE SIGNAL ;
    PORT
      LAYER MT1 ;
        RECT 4.5 0.5 7.5 3.5 ;
    END
  END A2
  PIN B1
    DIRECTION INPUT ;
    USE SIGNAL ;
    PORT
      LAYER MT1 ;
        RECT 12.5 0.5 15.5 3.5 ;
    END
  END B1
  PIN B2
    DIRECTION INPUT ;
    USE SIGNAL ;
    PORT
      LAYER MT1 ;
        RECT 8.5 0.5 11.5 3.5 ;
    END
  END B2
  PIN Y
    DIRECTION INPUT ;
    USE SIGNAL ;
    PORT
      LAYER MT1 ;
        RECT 0.5 8.5 3.5 11.5 ;
    END
  END Y
  OBS
    LAYER VIA1 ;
      RECT 13.25 1.25 14.75 2.75 ;
      RECT 9.25 1.25 10.75 2.75 ;
      RECT 5.25 1.25 6.75 2.75 ;
      RECT 1.25 1.25 2.75 2.75 ;
      RECT 1.25 9.25 2.75 10.75 ;
    LAYER GATE ;
      RECT 13.45 0.75 14.3 6 ;
      RECT 13.375 0.75 14.375 3.9 ;
      RECT 12.75 0.75 15.25 3.25 ;
      RECT 9.575 0.75 10.425 6 ;
      RECT 9.5 0.75 10.5 3.9 ;
      RECT 8.75 0.75 11.25 3.25 ;
      RECT 5.575 0.75 6.425 6 ;
      RECT 5.5 0.75 6.5 3.9 ;
      RECT 4.75 0.75 7.25 3.25 ;
      RECT 1.7 0.75 2.55 6 ;
      RECT 1.625 0.75 2.625 3.9 ;
      RECT 0.75 0.75 3.25 3.25 ;
      RECT 0.75 8.75 3.25 11.25 ;
    LAYER CONT ;
      RECT 1.5 9.5 2.5 10.5 ;
    LAYER SD ;
      RECT 0.45 6.65 3.25 11.25 ;
      RECT 14 6.65 15.55 9.9 ;
      RECT 14.55 4.15 15.55 9.9 ;
      RECT 0.45 6.65 15.55 7.65 ;
      RECT 0.45 4.15 1.45 11.25 ;
      RECT 14.175 4.15 15.55 5.75 ;
      RECT 0.45 4.15 1.825 5.75 ;
      RECT 10.3 4.15 13.575 5.75 ;
      RECT 2.425 4.15 5.7 5.75 ;
  END
END AOI22_X1RL_T5

MACRO AOI22_X2RL_T5
  CLASS CORE ;
  ORIGIN 0 0 ;
  FOREIGN AOI22_X2RL_T5 0 0 ;
  SIZE 12 BY 20 ;
  SYMMETRY X Y ;
  SITE CoreSite_T5 ;
  PIN VDD
    DIRECTION INOUT ;
    USE POWER ;
    PORT
      LAYER SD ;
        RECT 0 19.5 12 20.5 ;
        RECT 8.35 17.9 9.9 20.5 ;
    END
  END VDD
  PIN VSS
    DIRECTION INOUT ;
    USE GROUND ;
    PORT
      LAYER SD ;
        RECT 0 -0.5 12 0.5 ;
        RECT 6.3 3.7 9.575 5.3 ;
        RECT 7.5 -0.5 8.5 5.3 ;
    END
  END VSS
  PIN A1
    DIRECTION INPUT ;
    USE SIGNAL ;
    PORT
      LAYER MT1 ;
        RECT 0.5 0.5 3.5 3.5 ;
    END
  END A1
  PIN A2
    DIRECTION INPUT ;
    USE SIGNAL ;
    PORT
      LAYER MT1 ;
        RECT 4.5 0.5 7.5 3.5 ;
    END
  END A2
  PIN B1
    DIRECTION INPUT ;
    USE SIGNAL ;
    PORT
      LAYER MT1 ;
        RECT 8.5 8.5 11.5 11.5 ;
    END
  END B1
  PIN B2
    DIRECTION INPUT ;
    USE SIGNAL ;
    PORT
      LAYER MT1 ;
        RECT 8.5 0.5 11.5 3.5 ;
    END
  END B2
  PIN Y
    DIRECTION INPUT ;
    USE SIGNAL ;
    PORT
      LAYER MT1 ;
        RECT 0.5 8.5 3.5 11.5 ;
    END
  END Y
  OBS
    LAYER VIA1 ;
      RECT 9.25 1.25 10.75 2.75 ;
      RECT 9.25 9.25 10.75 10.75 ;
      RECT 5.25 1.25 6.75 2.75 ;
      RECT 1.25 1.25 2.75 2.75 ;
      RECT 1.25 9.25 2.75 10.75 ;
    LAYER GATE ;
      RECT 9.45 0.75 10.3 5.55 ;
      RECT 9.425 0.75 10.425 3.45 ;
      RECT 8.75 0.75 11.25 3.25 ;
      RECT 8.75 8.75 11.25 11.25 ;
      RECT 6.65 8.825 11.25 9.675 ;
      RECT 5.575 0.75 6.425 5.55 ;
      RECT 5.5 0.75 6.5 3.45 ;
      RECT 4.75 0.75 7.25 3.25 ;
      RECT 1.7 0.75 2.55 5.55 ;
      RECT 1.55 0.75 2.55 3.45 ;
      RECT 0.75 0.75 3.25 3.25 ;
      RECT 0.75 8.75 3.25 11.25 ;
    LAYER CONT ;
      RECT 1.5 9.5 2.5 10.5 ;
    LAYER SD ;
      RECT 6.9 6.95 8.5 8.95 ;
      RECT 6.9 6.95 11.55 7.95 ;
      RECT 10.55 3.7 11.55 7.95 ;
      RECT 10.175 3.7 11.55 5.3 ;
      RECT 2.15 10.25 3.65 13.1 ;
      RECT 0.45 10.25 8.5 11.25 ;
      RECT 6.9 9.55 8.5 11.25 ;
      RECT 0.45 8.75 3.25 11.25 ;
      RECT 0.45 3.7 1.45 11.25 ;
      RECT 0.45 3.7 1.825 5.3 ;
      RECT 2.425 3.7 5.7 5.3 ;
  END
END AOI22_X2RL_T5

MACRO AOI22_X4RL_T5
  CLASS CORE ;
  ORIGIN 0 0 ;
  FOREIGN AOI22_X4RL_T5 0 0 ;
  SIZE 12 BY 20 ;
  SYMMETRY X Y ;
  SITE CoreSite_T5 ;
  PIN VDD
    DIRECTION INOUT ;
    USE POWER ;
    PORT
      LAYER SD ;
        RECT 0 19.5 12 20.5 ;
        RECT 9.8 17.9 11.3 20.5 ;
    END
  END VDD
  PIN VSS
    DIRECTION INOUT ;
    USE GROUND ;
    PORT
      LAYER SD ;
        RECT 0 -0.5 12 0.5 ;
        RECT 6.3 3.5 9.625 6.1 ;
        RECT 7.5 -0.5 8.5 6.1 ;
    END
  END VSS
  PIN A1
    DIRECTION INPUT ;
    USE SIGNAL ;
    PORT
      LAYER MT1 ;
        RECT 0.5 0.5 3.5 3.5 ;
    END
  END A1
  PIN A2
    DIRECTION INPUT ;
    USE SIGNAL ;
    PORT
      LAYER MT1 ;
        RECT 4.5 0.5 7.5 3.5 ;
    END
  END A2
  PIN B1
    DIRECTION INPUT ;
    USE SIGNAL ;
    PORT
      LAYER MT1 ;
        RECT 8.5 8.5 11.5 11.5 ;
    END
  END B1
  PIN B2
    DIRECTION INPUT ;
    USE SIGNAL ;
    PORT
      LAYER MT1 ;
        RECT 8.5 0.5 11.5 3.5 ;
    END
  END B2
  PIN Y
    DIRECTION INPUT ;
    USE SIGNAL ;
    PORT
      LAYER MT1 ;
        RECT 0.5 8.5 3.5 11.5 ;
    END
  END Y
  OBS
    LAYER VIA1 ;
      RECT 9.25 1.25 10.75 2.75 ;
      RECT 9.25 9.25 10.75 10.75 ;
      RECT 5.25 1.25 6.75 2.75 ;
      RECT 1.25 1.25 2.75 2.75 ;
      RECT 1.25 9.25 2.75 10.75 ;
    LAYER GATE ;
      RECT 9.5 0.75 10.35 6.35 ;
      RECT 8.75 0.75 11.25 3.25 ;
      RECT 8.75 8.75 11.25 11.25 ;
      RECT 5.65 8.825 11.25 9.675 ;
      RECT 5.575 0.75 6.425 6.35 ;
      RECT 4.75 0.75 7.25 3.25 ;
      RECT 1.7 0.75 2.55 6.35 ;
      RECT 0.75 0.75 3.25 3.25 ;
      RECT 0.75 8.75 3.25 11.25 ;
    LAYER CONT ;
      RECT 1.5 9.5 2.5 10.5 ;
    LAYER SD ;
      RECT 5.9 7.3 8.5 8.95 ;
      RECT 5.9 7.3 11.6 8.3 ;
      RECT 10.6 3.5 11.6 8.3 ;
      RECT 10.225 3.5 11.6 6.1 ;
      RECT 6.2 14.7 7.7 16.3 ;
      RECT 6.2 9.55 7.2 16.3 ;
      RECT 0.45 10.25 7.2 11.25 ;
      RECT 5.9 9.55 8.5 10.55 ;
      RECT 0.45 8.75 3.25 11.25 ;
      RECT 0.45 3.5 1.45 11.25 ;
      RECT 0.45 3.5 1.825 6.1 ;
      RECT 2.425 3.5 5.7 6.1 ;
  END
END AOI22_X4RL_T5

MACRO BUF_X1PC_T5
  CLASS CORE ;
  ORIGIN 0 0 ;
  FOREIGN BUF_X1PC_T5 0 0 ;
  SIZE 28 BY 20 ;
  SYMMETRY X Y ;
  SITE CoreSite_T5 ;
  PIN VDD
    DIRECTION INOUT ;
    USE POWER ;
    PORT
      LAYER SD ;
        RECT 0 19.5 28 20.5 ;
        RECT 25.8 17.05 27.2 20.5 ;
        RECT 25.6 17.05 27.2 18.05 ;
        RECT 12.5 18.5 14.1 20.5 ;
        RECT 0.5 18.5 2.1 20.5 ;
    END
  END VDD
  PIN VSS
    DIRECTION INOUT ;
    USE GROUND ;
    PORT
      LAYER SD ;
        RECT 0 -0.5 28 0.5 ;
        RECT 24.65 -0.5 26.25 1.5 ;
        RECT 21.45 -0.5 23.05 1.5 ;
        RECT 6.675 -0.5 8.275 1.5 ;
    END
  END VSS
  PIN A
    DIRECTION INPUT ;
    USE SIGNAL ;
    PORT
      LAYER MT1 ;
        RECT 0.5 0.5 3.5 3.5 ;
    END
  END A
  PIN Y
    DIRECTION INPUT ;
    USE SIGNAL ;
    PORT
      LAYER MT1 ;
        RECT 24.5 8.5 27.5 11.5 ;
    END
  END Y
  OBS
    LAYER VIA1 ;
      RECT 25.25 9.25 26.75 10.75 ;
      RECT 1.25 1.25 2.75 2.75 ;
    LAYER GATE ;
      RECT 22.25 16.25 24.25 18.25 ;
      RECT 22.25 16.25 25.35 17.25 ;
      RECT 22.25 16.325 27.45 17.175 ;
      RECT 10.1 3.3 12.1 5.3 ;
      RECT 10.1 3.3 13.2 4.3 ;
      RECT 12.2 1.3 13.2 4.3 ;
      RECT 23.3 1.3 24.4 2.3 ;
      RECT 12.2 1.3 21.2 2.3 ;
      RECT 12.2 1.375 26.5 2.225 ;
      RECT 0.75 0.75 3.25 3.25 ;
      RECT 0.75 1.3 6.425 2.3 ;
      RECT 0.75 1.375 8.525 2.225 ;
      RECT 24.75 8.75 27.25 11.25 ;
    LAYER CONT ;
      RECT 25.5 9.5 26.5 10.5 ;
      RECT 22.75 16.75 23.75 17.75 ;
      RECT 10.6 3.8 11.6 4.8 ;
    LAYER SD ;
      RECT 25.6 15.45 27.2 16.45 ;
      RECT 25.8 8.75 27.2 16.45 ;
      RECT 24.75 8.75 27.25 11.25 ;
      RECT 24.75 2.1 25.75 11.25 ;
      RECT 24.65 2.1 26.25 3.1 ;
      RECT 20.5 17 24.25 18.5 ;
      RECT 22.1 16.25 24.25 18.5 ;
      RECT 22.75 3.1 23.75 18.5 ;
      RECT 21.45 2.1 23.05 4.1 ;
      RECT 10.1 3.3 11.7 7.4 ;
      RECT 10.1 3.3 12.1 5.3 ;
      RECT 6.675 3.3 12.1 4.3 ;
      RECT 6.675 2.1 8.275 4.3 ;
  END
END BUF_X1PC_T5

MACRO BUF_X1RL_T5
  CLASS CORE ;
  ORIGIN 0 0 ;
  FOREIGN BUF_X1RL_T5 0 0 ;
  SIZE 24 BY 20 ;
  SYMMETRY X Y ;
  SITE CoreSite_T5 ;
  PIN VDD
    DIRECTION INOUT ;
    USE POWER ;
    PORT
      LAYER SD ;
        RECT 0 19.5 24 20.5 ;
        RECT 17.95 17.9 19.5 20.5 ;
        RECT 8.75 17.9 10.3 20.5 ;
    END
  END VDD
  PIN VSS
    DIRECTION INOUT ;
    USE GROUND ;
    PORT
      LAYER SD ;
        RECT 0 -0.5 24 0.5 ;
        RECT 16.9 -0.5 18.5 1.5 ;
        RECT 10.45 -0.5 12.05 1.5 ;
    END
  END VSS
  PIN A
    DIRECTION INPUT ;
    USE SIGNAL ;
    PORT
      LAYER MT1 ;
        RECT 4.5 0.5 7.5 3.5 ;
    END
  END A
  PIN Y
    DIRECTION INPUT ;
    USE SIGNAL ;
    PORT
      LAYER MT1 ;
        RECT 20.5 4.5 23.5 7.5 ;
    END
  END Y
  OBS
    LAYER VIA1 ;
      RECT 21.25 5.25 22.75 6.75 ;
      RECT 5.25 1.25 6.75 2.75 ;
    LAYER GATE ;
      RECT 13.95 1.3 15.95 3.5 ;
      RECT 13.95 1.3 16.65 2.3 ;
      RECT 13.95 1.375 18.75 2.225 ;
      RECT 4.75 0.75 7.25 3.25 ;
      RECT 4.75 1.3 10.2 2.3 ;
      RECT 4.75 1.375 12.3 2.225 ;
      RECT 20.75 4.75 23.25 7.25 ;
    LAYER CONT ;
      RECT 21.5 5.5 22.5 6.5 ;
      RECT 14.45 2 15.45 3 ;
    LAYER SD ;
      RECT 20.75 4.75 23.25 7.25 ;
      RECT 17 3.1 18.55 6.7 ;
      RECT 17 3.75 21.75 4.75 ;
      RECT 16.9 2.1 18.5 3.1 ;
      RECT 8.25 2.55 9.75 5.1 ;
      RECT 8.25 2.55 15.95 3.55 ;
      RECT 13.95 1.5 15.95 3.55 ;
      RECT 10.45 2.1 12.05 3.55 ;
  END
END BUF_X1RL_T5

MACRO BUF_X2PC_T5
  CLASS CORE ;
  ORIGIN 0 0 ;
  FOREIGN BUF_X2PC_T5 0 0 ;
  SIZE 24 BY 20 ;
  SYMMETRY X Y ;
  SITE CoreSite_T5 ;
  PIN VDD
    DIRECTION INOUT ;
    USE POWER ;
    PORT
      LAYER SD ;
        RECT 0 19.5 24 20.5 ;
        RECT 21.6 17.9 23.3 20.5 ;
        RECT 22.3 9.65 23.3 20.5 ;
        RECT 20.65 9.2 23.25 10.65 ;
        RECT 0.5 17.9 2.1 20.5 ;
    END
  END VDD
  PIN VSS
    DIRECTION INOUT ;
    USE GROUND ;
    PORT
      LAYER SD ;
        RECT 0 -0.5 24 0.5 ;
        RECT 20.65 -0.5 23.25 1.5 ;
        RECT 14.6 -0.5 17.2 1.5 ;
        RECT 3.5 -0.5 5.1 1.5 ;
    END
  END VSS
  PIN A
    DIRECTION INPUT ;
    USE SIGNAL ;
    PORT
      LAYER MT1 ;
        RECT 0.5 0.5 3.5 3.5 ;
    END
  END A
  PIN Y
    DIRECTION INPUT ;
    USE SIGNAL ;
    PORT
      LAYER MT1 ;
        RECT 20.5 4.5 23.5 7.5 ;
    END
  END Y
  OBS
    LAYER VIA1 ;
      RECT 21.25 5.25 22.75 6.75 ;
      RECT 1.25 1.25 2.75 2.75 ;
    LAYER GATE ;
      RECT 9.7 1.3 11.7 3.5 ;
      RECT 17.45 1.3 20.4 2.3 ;
      RECT 9.7 1.3 14.35 2.3 ;
      RECT 9.7 1.375 23.5 2.225 ;
      RECT 15.7 8.4 20.4 9.4 ;
      RECT 15.7 8.475 23.5 9.325 ;
      RECT 15.7 5.5 16.7 9.4 ;
      RECT 14.2 5.5 16.7 7.5 ;
      RECT 0.75 0.75 3.25 3.25 ;
      RECT 0.75 1.375 5.35 2.225 ;
      RECT 20.75 4.75 23.25 7.25 ;
    LAYER CONT ;
      RECT 21.5 5.5 22.5 6.5 ;
      RECT 14.7 6 15.7 7 ;
      RECT 10.2 2 11.2 3 ;
    LAYER SD ;
      RECT 20.65 7.6 23.25 8.6 ;
      RECT 20.75 4.75 23.25 8.6 ;
      RECT 21.5 2.1 22.5 8.6 ;
      RECT 20.65 2.1 23.25 3.1 ;
      RECT 13 5.5 14.5 13.1 ;
      RECT 13 5.5 16.2 7.5 ;
      RECT 15.2 2.1 16.2 7.5 ;
      RECT 14.6 2.1 17.2 3.1 ;
      RECT 10.1 1.5 11.7 5 ;
      RECT 3.5 2.5 11.7 3.5 ;
      RECT 9.7 1.5 11.7 3.5 ;
      RECT 3.5 2.1 5.1 3.5 ;
  END
END BUF_X2PC_T5

MACRO BUF_X2RL_T5
  CLASS CORE ;
  ORIGIN 0 0 ;
  FOREIGN BUF_X2RL_T5 0 0 ;
  SIZE 20 BY 20 ;
  SYMMETRY X Y ;
  SITE CoreSite_T5 ;
  PIN VDD
    DIRECTION INOUT ;
    USE POWER ;
    PORT
      LAYER SD ;
        RECT 0 19.5 20 20.5 ;
        RECT 17.85 18.5 19.45 20.5 ;
        RECT 8.7 17.9 10.2 20.5 ;
    END
  END VDD
  PIN VSS
    DIRECTION INOUT ;
    USE GROUND ;
    PORT
      LAYER SD ;
        RECT 0 -0.5 20 0.5 ;
        RECT 13.55 -0.5 15.15 1.5 ;
        RECT 5 -0.5 6.6 1.5 ;
    END
  END VSS
  PIN A
    DIRECTION INPUT ;
    USE SIGNAL ;
    PORT
      LAYER MT1 ;
        RECT 0.5 0.5 3.5 3.5 ;
    END
  END A
  PIN Y
    DIRECTION INPUT ;
    USE SIGNAL ;
    PORT
      LAYER MT1 ;
        RECT 12.5 4.5 15.5 7.5 ;
    END
  END Y
  OBS
    LAYER VIA1 ;
      RECT 13.25 5.25 14.75 6.75 ;
      RECT 1.25 1.25 2.75 2.75 ;
    LAYER GATE ;
      RECT 7.85 1.3 9.85 3.5 ;
      RECT 7.85 1.3 13.3 2.3 ;
      RECT 7.85 1.375 15.4 2.225 ;
      RECT 0.75 0.75 3.25 3.25 ;
      RECT 0.75 1.3 4.75 2.3 ;
      RECT 0.75 1.375 6.85 2.225 ;
      RECT 12.75 4.75 15.25 7.25 ;
    LAYER CONT ;
      RECT 13.5 5.5 14.5 6.5 ;
      RECT 8.35 2 9.35 3 ;
    LAYER SD ;
      RECT 13.9 7.25 15.5 8.85 ;
      RECT 13.65 2.1 15.05 7.25 ;
      RECT 12.75 4.75 15.25 7.25 ;
      RECT 13.55 2.1 15.15 3.1 ;
      RECT 2.7 3.5 4.3 5.1 ;
      RECT 2.7 3.5 6 4.5 ;
      RECT 7.85 1.5 9.85 3.5 ;
      RECT 5 2.5 9.85 3.5 ;
      RECT 5 2.1 6.6 3.5 ;
  END
END BUF_X2RL_T5

MACRO BUF_X4PC_T5
  CLASS CORE ;
  ORIGIN 0 0 ;
  FOREIGN BUF_X4PC_T5 0 0 ;
  SIZE 20 BY 20 ;
  SYMMETRY X Y ;
  SITE CoreSite_T5 ;
  PIN VDD
    DIRECTION INOUT ;
    USE POWER ;
    PORT
      LAYER SD ;
        RECT 0 19.5 20 20.5 ;
        RECT 13.25 9.1 17.85 10.85 ;
        RECT 11.7 9.85 14.3 12.4 ;
        RECT 11.7 9.85 12.7 20.5 ;
        RECT 0.5 18 2.1 20.5 ;
    END
  END VDD
  PIN VSS
    DIRECTION INOUT ;
    USE GROUND ;
    PORT
      LAYER SD ;
        RECT 0 -0.5 20 0.5 ;
        RECT 14.65 -0.5 19.25 1.5 ;
        RECT 8.7 -0.5 13.3 1.5 ;
        RECT 4.3 -0.5 5.9 1.5 ;
    END
  END VSS
  PIN A
    DIRECTION INPUT ;
    USE SIGNAL ;
    PORT
      LAYER MT1 ;
        RECT 0.5 0.5 3.5 3.5 ;
    END
  END A
  PIN Y
    DIRECTION INPUT ;
    USE SIGNAL ;
    PORT
      LAYER MT1 ;
        RECT 16.5 4.5 19.5 7.5 ;
    END
  END Y
  OBS
    LAYER VIA1 ;
      RECT 17.25 5.25 18.75 6.75 ;
      RECT 1.25 1.25 2.75 2.75 ;
    LAYER GATE ;
      RECT 4.4 3.35 8.15 5.35 ;
      RECT 7.15 1.3 8.15 5.35 ;
      RECT 13.55 1.3 14.4 2.3 ;
      RECT 7.15 1.3 8.45 2.3 ;
      RECT 7.15 1.375 19.5 2.225 ;
      RECT 17.5 12.4 19.5 14.4 ;
      RECT 18.5 8.3 19.5 14.4 ;
      RECT 18.1 8.3 19.5 9.3 ;
      RECT 11.95 8.275 13 9.275 ;
      RECT 11.95 8.375 19.5 9.225 ;
      RECT 11.95 3.9 12.95 9.275 ;
      RECT 11.9 3.9 13.9 5.9 ;
      RECT 0.75 0.75 3.25 3.25 ;
      RECT 0.75 1.375 6.15 2.225 ;
      RECT 0.75 1.225 4.05 2.225 ;
      RECT 16.75 4.75 19.25 7.25 ;
    LAYER CONT ;
      RECT 18 12.9 19 13.9 ;
      RECT 17.5 5.5 18.5 6.5 ;
      RECT 12.4 4.4 13.4 5.4 ;
      RECT 4.9 3.85 5.9 4.85 ;
    LAYER SD ;
      RECT 17.5 12.4 19.1 15.9 ;
      RECT 17.5 12.4 19.5 14.4 ;
      RECT 13.25 6.8 17.85 8.5 ;
      RECT 13.25 6.8 19 7.9 ;
      RECT 17.9 2.1 19 7.9 ;
      RECT 16.75 4.75 19.25 7.25 ;
      RECT 14.65 2.1 19.25 3.1 ;
      RECT 11.9 3.9 13.9 5.9 ;
      RECT 11.9 2.1 13.3 5.9 ;
      RECT 8.7 2.1 13.3 3.1 ;
      RECT 10.1 7.35 11.7 8.95 ;
      RECT 10.1 4.35 11.1 8.95 ;
      RECT 4.4 4.35 11.1 5.35 ;
      RECT 4.4 3.3 6.4 5.35 ;
      RECT 4.4 2.1 5.9 5.35 ;
      RECT 4.3 2.1 5.9 3.1 ;
  END
END BUF_X4PC_T5

MACRO BUF_X4RL_T5
  CLASS CORE ;
  ORIGIN 0 0 ;
  FOREIGN BUF_X4RL_T5 0 0 ;
  SIZE 16 BY 20 ;
  SYMMETRY X Y ;
  SITE CoreSite_T5 ;
  PIN VDD
    DIRECTION INOUT ;
    USE POWER ;
    PORT
      LAYER SD ;
        RECT 0 19.5 16 20.5 ;
        RECT 13.9 18.5 15.5 20.5 ;
        RECT 8.7 17.9 10.2 20.5 ;
    END
  END VDD
  PIN VSS
    DIRECTION INOUT ;
    USE GROUND ;
    PORT
      LAYER SD ;
        RECT 0 -0.5 16 0.5 ;
        RECT 12.55 -0.5 15.15 1.5 ;
        RECT 5 -0.5 6.6 1.5 ;
    END
  END VSS
  PIN A
    DIRECTION INPUT ;
    USE SIGNAL ;
    PORT
      LAYER MT1 ;
        RECT 0.5 0.5 3.5 3.5 ;
    END
  END A
  PIN Y
    DIRECTION INPUT ;
    USE SIGNAL ;
    PORT
      LAYER MT1 ;
        RECT 12.5 4.5 15.5 7.5 ;
    END
  END Y
  OBS
    LAYER VIA1 ;
      RECT 13.25 5.25 14.75 6.75 ;
      RECT 1.25 1.25 2.75 2.75 ;
    LAYER GATE ;
      RECT 7.85 1.3 9.85 3.5 ;
      RECT 7.85 1.3 12.3 2.3 ;
      RECT 7.85 1.375 15.4 2.225 ;
      RECT 0.75 0.75 3.25 3.25 ;
      RECT 0.75 1.3 4.75 2.3 ;
      RECT 0.75 1.375 6.85 2.225 ;
      RECT 12.75 4.75 15.25 7.25 ;
    LAYER CONT ;
      RECT 13.5 5.5 14.5 6.5 ;
      RECT 8.35 2 9.35 3 ;
    LAYER SD ;
      RECT 13.9 7.25 15.5 8.8 ;
      RECT 13.75 2.1 15.15 7.25 ;
      RECT 12.75 4.75 15.25 7.25 ;
      RECT 12.55 2.1 15.15 3.1 ;
      RECT 2.7 3.5 4.3 5.1 ;
      RECT 2.7 3.5 6 4.5 ;
      RECT 7.85 1.5 9.85 3.5 ;
      RECT 5 2.5 9.85 3.5 ;
      RECT 5 2.1 6.6 3.5 ;
  END
END BUF_X4RL_T5

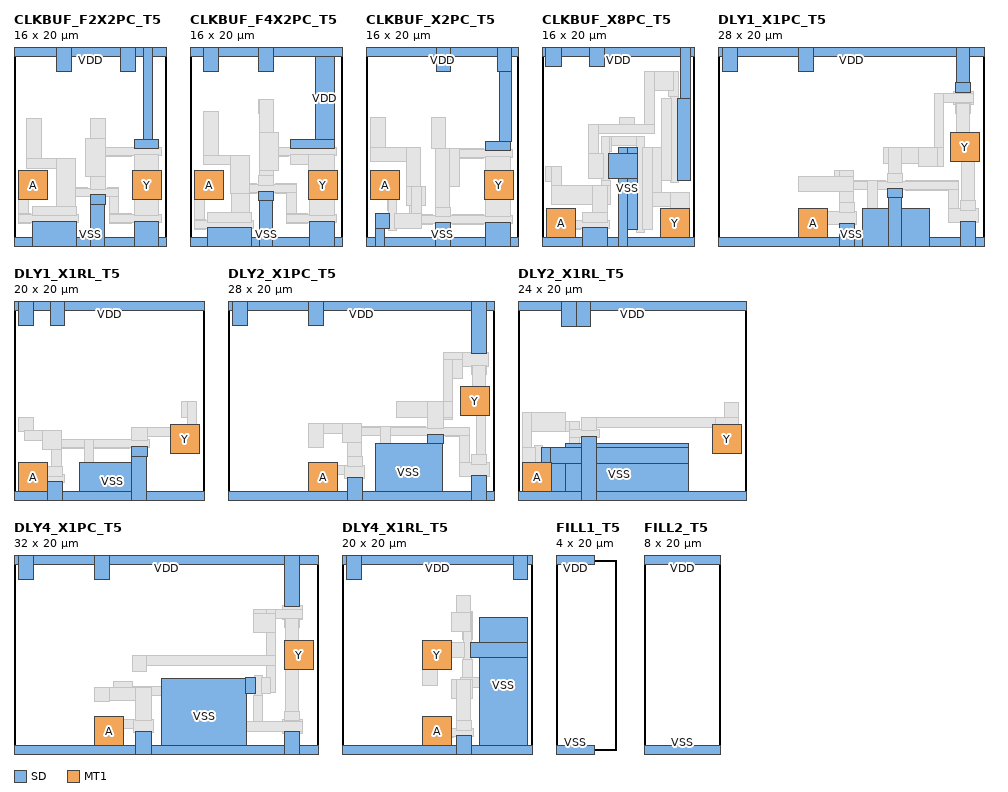
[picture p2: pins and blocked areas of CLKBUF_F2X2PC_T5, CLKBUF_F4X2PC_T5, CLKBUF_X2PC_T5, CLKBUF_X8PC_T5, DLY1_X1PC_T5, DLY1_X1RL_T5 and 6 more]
MACRO CLKBUF_F2X2PC_T5
  CLASS CORE ;
  ORIGIN 0 0 ;
  FOREIGN CLKBUF_F2X2PC_T5 0 0 ;
  SIZE 16 BY 20 ;
  SYMMETRY X Y ;
  SITE CoreSite_T5 ;
  PIN VDD
    DIRECTION INOUT ;
    USE POWER ;
    PORT
      LAYER SD ;
        RECT 0 19.5 16 20.5 ;
        RECT 12.65 9.8 15.25 10.8 ;
        RECT 13.6 9.8 14.6 20.5 ;
        RECT 11.2 18 12.8 20.5 ;
        RECT 4.5 18 6.1 20.5 ;
    END
  END VDD
  PIN VSS
    DIRECTION INOUT ;
    USE GROUND ;
    PORT
      LAYER SD ;
        RECT 0 -0.5 16 0.5 ;
        RECT 12.65 -0.5 15.25 2.2 ;
        RECT 8 3.95 9.6 4.95 ;
        RECT 8.1 -0.5 9.5 4.95 ;
        RECT 1.95 -0.5 6.55 2.15 ;
    END
  END VSS
  PIN A
    DIRECTION INPUT ;
    USE SIGNAL ;
    PORT
      LAYER MT1 ;
        RECT 0.5 4.5 3.5 7.5 ;
    END
  END A
  PIN Y
    DIRECTION INPUT ;
    USE SIGNAL ;
    PORT
      LAYER MT1 ;
        RECT 12.5 4.5 15.5 7.5 ;
    END
  END Y
  OBS
    LAYER VIA1 ;
      RECT 13.25 5.25 14.75 6.75 ;
      RECT 1.25 5.25 2.75 6.75 ;
    LAYER GATE ;
      RECT 4.45 4.75 6.45 8.75 ;
      RECT 9.85 4.75 11 5.75 ;
      RECT 10 2 11 5.75 ;
      RECT 4.45 4.75 7.75 5.75 ;
      RECT 4.45 4.825 11 5.675 ;
      RECT 10 2 12.4 3 ;
      RECT 10 2.075 15.5 2.925 ;
      RECT 7.5 6.9 9.5 10.9 ;
      RECT 7.5 9 12.4 10 ;
      RECT 7.5 9.075 15.5 9.925 ;
      RECT 0.5 4.75 3.25 7.25 ;
      RECT 0.5 1.975 1.5 7.25 ;
      RECT 0.5 1.975 1.7 2.975 ;
      RECT 0.5 2.025 6.8 2.875 ;
      RECT 12.75 4.75 15.25 7.25 ;
    LAYER CONT ;
      RECT 13.5 5.5 14.5 6.5 ;
      RECT 8 7.4 9 8.4 ;
      RECT 8 9.4 9 10.4 ;
      RECT 4.95 5.25 5.95 6.25 ;
      RECT 4.95 7.25 5.95 8.25 ;
    LAYER SD ;
      RECT 12.65 2.8 15.25 9.2 ;
      RECT 12.5 4.5 15.5 7.5 ;
      RECT 8 5.55 9.6 13 ;
      RECT 7.5 6.9 9.6 10.9 ;
      RECT 1.3 7.75 2.9 13 ;
      RECT 1.3 7.75 6.45 8.75 ;
      RECT 4.45 2.75 6.45 8.75 ;
      RECT 1.95 2.75 6.55 3.75 ;
  END
END CLKBUF_F2X2PC_T5

MACRO CLKBUF_F4X2PC_T5
  CLASS CORE ;
  ORIGIN 0 0 ;
  FOREIGN CLKBUF_F4X2PC_T5 0 0 ;
  SIZE 16 BY 20 ;
  SYMMETRY X Y ;
  SITE CoreSite_T5 ;
  PIN VDD
    DIRECTION INOUT ;
    USE POWER ;
    PORT
      LAYER SD ;
        RECT 0 19.5 16 20.5 ;
        RECT 13.2 9.8 15.2 20.5 ;
        RECT 10.6 9.8 15.2 10.8 ;
        RECT 7.2 18 8.8 20.5 ;
        RECT 1.45 18 3.05 20.5 ;
    END
  END VDD
  PIN VSS
    DIRECTION INOUT ;
    USE GROUND ;
    PORT
      LAYER SD ;
        RECT 0 -0.5 16 0.5 ;
        RECT 12.6 -0.5 15.2 2.2 ;
        RECT 7.2 4.35 8.8 5.35 ;
        RECT 7.3 -0.5 8.7 5.35 ;
        RECT 1.85 -0.5 6.45 1.5 ;
    END
  END VSS
  PIN A
    DIRECTION INPUT ;
    USE SIGNAL ;
    PORT
      LAYER MT1 ;
        RECT 0.5 4.5 3.5 7.5 ;
    END
  END A
  PIN Y
    DIRECTION INPUT ;
    USE SIGNAL ;
    PORT
      LAYER MT1 ;
        RECT 12.5 4.5 15.5 7.5 ;
    END
  END Y
  OBS
    LAYER VIA1 ;
      RECT 13.25 5.25 14.75 6.75 ;
      RECT 1.25 5.25 2.75 6.75 ;
    LAYER GATE ;
      RECT 4.3 5.15 6.3 9.15 ;
      RECT 9.05 5.15 11.2 6.15 ;
      RECT 10.2 2 11.2 6.15 ;
      RECT 4.3 5.15 6.95 6.15 ;
      RECT 4.3 5.225 11.2 6.075 ;
      RECT 10.2 2 12.35 3 ;
      RECT 10.2 2.075 15.45 2.925 ;
      RECT 7.3 7.5 9.3 11.5 ;
      RECT 7.3 9 10.35 10 ;
      RECT 7.3 9.075 15.45 9.925 ;
      RECT 0.5 4.75 3.25 7.25 ;
      RECT 0.5 1.325 1.5 7.25 ;
      RECT 0.5 1.325 1.6 2.325 ;
      RECT 0.5 1.375 6.7 2.225 ;
      RECT 12.75 4.75 15.25 7.25 ;
    LAYER CONT ;
      RECT 13.5 5.5 14.5 6.5 ;
      RECT 7.8 8 8.8 9 ;
      RECT 7.8 10 8.8 11 ;
      RECT 4.8 5.65 5.8 6.65 ;
      RECT 4.8 7.65 5.8 8.65 ;
    LAYER SD ;
      RECT 10.6 8.2 15.2 9.2 ;
      RECT 12.6 2.8 15.2 9.2 ;
      RECT 12.5 4.5 15.2 9.2 ;
      RECT 12.5 4.5 15.5 7.5 ;
      RECT 7.2 13.5 8.8 15 ;
      RECT 7.3 5.95 8.8 15 ;
      RECT 7.3 7.5 9.3 11.5 ;
      RECT 7.2 5.95 8.8 6.95 ;
      RECT 1.45 8.15 3.05 13.7 ;
      RECT 1.45 8.15 6.3 9.15 ;
      RECT 4.35 2.1 6.3 9.15 ;
      RECT 4.3 5.15 6.3 9.15 ;
      RECT 1.85 2.1 6.45 3.1 ;
  END
END CLKBUF_F4X2PC_T5

MACRO CLKBUF_X2PC_T5
  CLASS CORE ;
  ORIGIN 0 0 ;
  FOREIGN CLKBUF_X2PC_T5 0 0 ;
  SIZE 16 BY 20 ;
  SYMMETRY X Y ;
  SITE CoreSite_T5 ;
  PIN VDD
    DIRECTION INOUT ;
    USE POWER ;
    PORT
      LAYER SD ;
        RECT 0 19.5 16 20.5 ;
        RECT 13.8 17.9 15.3 20.5 ;
        RECT 14.1 10.6 15.3 20.5 ;
        RECT 12.6 9.6 15.2 10.6 ;
        RECT 7.4 17.9 8.9 20.5 ;
    END
  END VDD
  PIN VSS
    DIRECTION INOUT ;
    USE GROUND ;
    PORT
      LAYER SD ;
        RECT 0 -0.5 16 0.5 ;
        RECT 12.6 -0.5 15.2 2.05 ;
        RECT 7.3 -0.5 8.9 2.05 ;
        RECT 0.95 1.45 2.45 3.05 ;
        RECT 0.95 -0.5 1.95 3.05 ;
    END
  END VSS
  PIN A
    DIRECTION INPUT ;
    USE SIGNAL ;
    PORT
      LAYER MT1 ;
        RECT 0.5 4.5 3.5 7.5 ;
    END
  END A
  PIN Y
    DIRECTION INPUT ;
    USE SIGNAL ;
    PORT
      LAYER MT1 ;
        RECT 12.5 4.5 15.5 7.5 ;
    END
  END Y
  OBS
    LAYER VIA1 ;
      RECT 13.25 5.25 14.75 6.75 ;
      RECT 1.25 5.25 2.75 6.75 ;
    LAYER GATE ;
      RECT 4.25 3.85 6.25 5.85 ;
      RECT 4.55 1.85 5.8 5.85 ;
      RECT 9.15 1.85 12.35 2.85 ;
      RECT 4.55 1.85 7.05 2.85 ;
      RECT 4.55 1.925 15.45 2.775 ;
      RECT 7.8 8.8 12.35 9.8 ;
      RECT 7.8 8.875 15.45 9.725 ;
      RECT 7.8 5.8 9.8 9.8 ;
      RECT 0.75 4.75 3.25 7.25 ;
      RECT 2.25 3.3 3.25 7.25 ;
      RECT 2.325 1.2 3.175 7.25 ;
      RECT 12.75 4.75 15.25 7.25 ;
    LAYER CONT ;
      RECT 13.5 5.5 14.5 6.5 ;
      RECT 8.3 6.3 9.3 7.3 ;
      RECT 8.3 8.3 9.3 9.3 ;
      RECT 4.75 4.35 5.75 5.35 ;
    LAYER SD ;
      RECT 12.6 2.65 15.2 9 ;
      RECT 12.5 4.5 15.5 7.5 ;
      RECT 6.9 9.8 8.4 13.1 ;
      RECT 7.3 5.8 9.8 9.8 ;
      RECT 7.3 2.65 8.8 9.8 ;
      RECT 7.3 2.65 8.9 3.65 ;
      RECT 0.5 8.45 2 13.1 ;
      RECT 0.5 8.45 5.75 9.95 ;
      RECT 4.25 3.85 5.75 9.95 ;
      RECT 4.25 3.85 6.25 5.85 ;
      RECT 4.8 1.45 5.8 5.85 ;
      RECT 3.05 1.45 5.8 3.05 ;
  END
END CLKBUF_X2PC_T5

MACRO CLKBUF_X8PC_T5
  CLASS CORE ;
  ORIGIN 0 0 ;
  FOREIGN CLKBUF_X8PC_T5 0 0 ;
  SIZE 16 BY 20 ;
  SYMMETRY X Y ;
  SITE CoreSite_T5 ;
  PIN VDD
    DIRECTION INOUT ;
    USE POWER ;
    PORT
      LAYER SD ;
        RECT 0 19.5 16 20.5 ;
        RECT 14.6 6.5 15.6 20.5 ;
        RECT 14.225 6.5 15.6 15.1 ;
        RECT 4.95 18.5 6.55 20.5 ;
        RECT 0.4 18.5 2 20.5 ;
    END
  END VDD
  PIN VSS
    DIRECTION INOUT ;
    USE GROUND ;
    PORT
      LAYER SD ;
        RECT 0 -0.5 16 0.5 ;
        RECT 8.025 1.3 10.025 9.9 ;
        RECT 8.025 -0.5 9.025 9.9 ;
        RECT 7.025 6.7 10.025 9.3 ;
        RECT 4.25 -0.5 6.85 1.5 ;
    END
  END VSS
  PIN A
    DIRECTION INPUT ;
    USE SIGNAL ;
    PORT
      LAYER MT1 ;
        RECT 0.5 0.5 3.5 3.5 ;
    END
  END A
  PIN Y
    DIRECTION INPUT ;
    USE SIGNAL ;
    PORT
      LAYER MT1 ;
        RECT 12.5 0.5 15.5 3.5 ;
    END
  END Y
  OBS
    LAYER VIA1 ;
      RECT 13.25 1.25 14.75 2.75 ;
      RECT 1.25 1.25 2.75 2.75 ;
    LAYER GATE ;
      RECT 13.5 3.25 15.5 5.25 ;
      RECT 12.75 0.75 15.25 3.25 ;
      RECT 11.8 15.9 14.35 17.9 ;
      RECT 13.5 6.25 14.35 17.9 ;
      RECT 13.35 15.35 14.35 17.9 ;
      RECT 6.3 10.15 10.75 11.15 ;
      RECT 9.9 1.05 10.75 11.15 ;
      RECT 6.3 9.55 7.3 11.15 ;
      RECT 6.3 3.9 7.15 11.15 ;
      RECT 6.225 3.9 7.225 6.45 ;
      RECT 5.225 3.9 7.225 5.9 ;
      RECT 0.75 0.75 3.25 3.25 ;
      RECT 0.75 1.3 4 2.3 ;
      RECT 0.75 1.375 7.1 2.225 ;
    LAYER CONT ;
      RECT 14 3.75 15 4.75 ;
      RECT 12.3 16.4 13.3 17.4 ;
      RECT 5.725 4.4 6.725 5.4 ;
    LAYER SD ;
      RECT 12.625 6.5 13.625 15.1 ;
      RECT 10.625 3.75 12.625 9.9 ;
      RECT 10.625 3.75 15.5 5.25 ;
      RECT 13.5 3.25 15.5 5.25 ;
      RECT 10.625 1.3 11.625 9.9 ;
      RECT 10.825 15.9 13.8 17.9 ;
      RECT 10.825 11.4 11.825 17.9 ;
      RECT 8.15 11.4 9.75 13.1 ;
      RECT 4.9 11.4 11.825 12.4 ;
      RECT 4.9 6.7 5.9 12.4 ;
      RECT 4.9 6.7 6.425 9.3 ;
      RECT 0.4 6.4 2.025 7.9 ;
      RECT 1.025 3.9 2.025 7.9 ;
      RECT 1.025 3.9 7.225 5.9 ;
      RECT 5.325 2.1 6.85 5.9 ;
      RECT 4.25 2.1 6.85 3.1 ;
  END
END CLKBUF_X8PC_T5

MACRO DLY1_X1PC_T5
  CLASS CORE ;
  ORIGIN 0 0 ;
  FOREIGN DLY1_X1PC_T5 0 0 ;
  SIZE 28 BY 20 ;
  SYMMETRY X Y ;
  SITE CoreSite_T5 ;
  PIN VDD
    DIRECTION INOUT ;
    USE POWER ;
    PORT
      LAYER SD ;
        RECT 0 19.5 28 20.5 ;
        RECT 25 15.75 26.6 16.75 ;
        RECT 25.1 15.75 26.5 20.5 ;
        RECT 8.5 17.9 10 20.5 ;
        RECT 0.5 18 2.1 20.5 ;
    END
  END VDD
  PIN VSS
    DIRECTION INOUT ;
    USE GROUND ;
    PORT
      LAYER SD ;
        RECT 0 -0.5 28 0.5 ;
        RECT 25.525 -0.5 27.125 2.15 ;
        RECT 15.25 -0.5 22.25 3.5 ;
        RECT 17.85 4.65 19.45 5.65 ;
        RECT 17.95 -0.5 19.35 5.65 ;
        RECT 12.75 -0.5 14.35 1.925 ;
    END
  END VSS
  PIN A
    DIRECTION INPUT ;
    USE SIGNAL ;
    PORT
      LAYER MT1 ;
        RECT 8.5 0.5 11.5 3.5 ;
    END
  END A
  PIN Y
    DIRECTION INPUT ;
    USE SIGNAL ;
    PORT
      LAYER MT1 ;
        RECT 24.5 8.5 27.5 11.5 ;
    END
  END Y
  OBS
    LAYER VIA1 ;
      RECT 25.25 9.25 26.75 10.75 ;
      RECT 9.25 1.25 10.75 2.75 ;
    LAYER GATE ;
      RECT 12.25 5.5 14.25 7.5 ;
      RECT 12.25 5.5 17.6 6.5 ;
      RECT 19.7 5.45 25.275 6.45 ;
      RECT 24.275 2.025 25.275 6.45 ;
      RECT 12.25 5.525 25.275 6.375 ;
      RECT 15.75 1 16.75 6.5 ;
      RECT 24.275 2.025 27.375 3.475 ;
      RECT 15.75 1 21.75 3 ;
      RECT 24.75 14.425 26.85 15.875 ;
      RECT 22.75 14.65 26.85 15.65 ;
      RECT 22.75 7.9 23.75 15.65 ;
      RECT 21.1 7.9 23.75 9.9 ;
      RECT 8.75 1.8 14.6 3.25 ;
      RECT 8.75 0.75 11.25 3.25 ;
      RECT 24.75 8.75 27.25 11.25 ;
    LAYER CONT ;
      RECT 25.5 9.5 26.5 10.5 ;
      RECT 21.6 8.4 22.6 9.4 ;
      RECT 12.75 6 13.75 7 ;
    LAYER SD ;
      RECT 25 13.55 26.6 14.55 ;
      RECT 25.1 8.75 26.5 14.55 ;
      RECT 24.75 8.75 27.25 11.25 ;
      RECT 25.625 3.35 27.025 11.25 ;
      RECT 25.525 3.35 27.125 4.35 ;
      RECT 17.45 8.3 23.1 9.9 ;
      RECT 21.1 7.9 23.1 9.9 ;
      RECT 17.95 6.25 19.35 9.9 ;
      RECT 17.85 6.25 19.45 7.25 ;
      RECT 12.25 5.35 14.25 7.5 ;
      RECT 12.75 3.125 14.25 7.5 ;
      RECT 8.5 5.35 14.25 6.85 ;
      RECT 12.75 3.125 14.35 4.125 ;
  END
END DLY1_X1PC_T5

MACRO DLY1_X1RL_T5
  CLASS CORE ;
  ORIGIN 0 0 ;
  FOREIGN DLY1_X1RL_T5 0 0 ;
  SIZE 20 BY 20 ;
  SYMMETRY X Y ;
  SITE CoreSite_T5 ;
  PIN VDD
    DIRECTION INOUT ;
    USE POWER ;
    PORT
      LAYER SD ;
        RECT 0 19.5 20 20.5 ;
        RECT 3.8 17.9 5.3 20.5 ;
        RECT 0.5 17.9 2.1 20.5 ;
    END
  END VDD
  PIN VSS
    DIRECTION INOUT ;
    USE GROUND ;
    PORT
      LAYER SD ;
        RECT 0 -0.5 20 0.5 ;
        RECT 12.4 4.2 14 5.2 ;
        RECT 12.4 -0.5 13.9 5.2 ;
        RECT 6.9 -0.5 13.9 3.5 ;
        RECT 3.5 -0.5 5.1 1.5 ;
    END
  END VSS
  PIN A
    DIRECTION INPUT ;
    USE SIGNAL ;
    PORT
      LAYER MT1 ;
        RECT 0.5 0.5 3.5 3.5 ;
    END
  END A
  PIN Y
    DIRECTION INPUT ;
    USE SIGNAL ;
    PORT
      LAYER MT1 ;
        RECT 16.5 4.5 19.5 7.5 ;
    END
  END Y
  OBS
    LAYER VIA1 ;
      RECT 17.25 5.25 18.75 6.75 ;
      RECT 1.25 1.25 2.75 2.75 ;
    LAYER GATE ;
      RECT 2.95 4.85 4.95 6.85 ;
      RECT 2.95 5 12.15 6 ;
      RECT 2.95 5.075 14.25 5.925 ;
      RECT 7.4 1 8.4 6 ;
      RECT 7.4 1 13.4 3 ;
      RECT 0.75 0.75 3.25 3.25 ;
      RECT 0.75 1.375 5.35 2.225 ;
      RECT 16.75 4.75 19.25 7.25 ;
    LAYER CONT ;
      RECT 17.5 5.5 18.5 6.5 ;
      RECT 3.45 5.35 4.45 6.35 ;
    LAYER SD ;
      RECT 17.6 8.3 19.25 9.9 ;
      RECT 18.25 4.75 19.25 9.9 ;
      RECT 12.4 6.25 19.25 7.25 ;
      RECT 16.75 4.75 19.25 7.25 ;
      RECT 12.4 5.8 14 7.25 ;
      RECT 0.5 6.8 2.1 8.3 ;
      RECT 3.95 2.1 4.95 6.85 ;
      RECT 1.1 5.85 4.95 6.85 ;
      RECT 2.95 4.85 4.95 6.85 ;
      RECT 3.5 2.1 5.1 3.1 ;
  END
END DLY1_X1RL_T5

MACRO DLY2_X1PC_T5
  CLASS CORE ;
  ORIGIN 0 0 ;
  FOREIGN DLY2_X1PC_T5 0 0 ;
  SIZE 28 BY 20 ;
  SYMMETRY X Y ;
  SITE CoreSite_T5 ;
  PIN VDD
    DIRECTION INOUT ;
    USE POWER ;
    PORT
      LAYER SD ;
        RECT 0 19.5 28 20.5 ;
        RECT 25.6 14.975 27.2 20.5 ;
        RECT 8.5 17.9 10 20.5 ;
        RECT 0.5 18 2.1 20.5 ;
    END
  END VDD
  PIN VSS
    DIRECTION INOUT ;
    USE GROUND ;
    PORT
      LAYER SD ;
        RECT 0 -0.5 28 0.5 ;
        RECT 25.625 -0.5 27.225 2.15 ;
        RECT 21.05 5.5 22.65 6.5 ;
        RECT 15.55 -0.5 22.55 5.5 ;
        RECT 12.55 -0.5 14.15 1.925 ;
    END
  END VSS
  PIN A
    DIRECTION INPUT ;
    USE SIGNAL ;
    PORT
      LAYER MT1 ;
        RECT 8.5 0.5 11.5 3.5 ;
    END
  END A
  PIN Y
    DIRECTION INPUT ;
    USE SIGNAL ;
    PORT
      LAYER MT1 ;
        RECT 24.5 8.5 27.5 11.5 ;
    END
  END Y
  OBS
    LAYER VIA1 ;
      RECT 25.25 9.25 26.75 10.75 ;
      RECT 9.25 1.25 10.75 2.75 ;
    LAYER GATE ;
      RECT 12.05 5.6 14.05 7.6 ;
      RECT 12.05 6.35 20.8 7.35 ;
      RECT 22.9 6.25 25.375 7.25 ;
      RECT 24.375 2.025 25.375 7.25 ;
      RECT 12.05 6.375 25.375 7.225 ;
      RECT 16.1 1 17.1 7.35 ;
      RECT 16.05 1 22.05 5 ;
      RECT 24.375 2.025 27.475 3.475 ;
      RECT 22.65 13.65 27.45 15.1 ;
      RECT 22.65 12.4 24.65 15.1 ;
      RECT 8.75 2.25 14.4 3.25 ;
      RECT 12.3 1.8 14.4 3.25 ;
      RECT 8.75 0.75 11.25 3.25 ;
      RECT 24.75 8.75 27.25 11.25 ;
    LAYER CONT ;
      RECT 25.5 9.5 26.5 10.5 ;
      RECT 23.15 12.9 24.15 13.9 ;
      RECT 12.55 6.1 13.55 7.1 ;
    LAYER SD ;
      RECT 25.6 12.775 27.2 13.775 ;
      RECT 25.7 8.75 27.1 13.775 ;
      RECT 24.75 8.75 27.25 11.25 ;
      RECT 26.125 3.35 27.125 11.25 ;
      RECT 25.625 3.35 27.225 4.35 ;
      RECT 22.65 12.4 24.65 14.4 ;
      RECT 22.65 8.1 23.65 14.4 ;
      RECT 17.7 8.3 23.65 9.9 ;
      RECT 21.05 7.1 22.65 9.9 ;
      RECT 8.5 6.6 14.05 7.6 ;
      RECT 12.55 3.125 14.05 7.6 ;
      RECT 12.05 5.6 14.05 7.6 ;
      RECT 8.5 5.1 10.1 7.6 ;
      RECT 12.55 3.125 14.15 4.125 ;
  END
END DLY2_X1PC_T5

MACRO DLY2_X1RL_T5
  CLASS CORE ;
  ORIGIN 0 0 ;
  FOREIGN DLY2_X1RL_T5 0 0 ;
  SIZE 24 BY 20 ;
  SYMMETRY X Y ;
  SITE CoreSite_T5 ;
  PIN VDD
    DIRECTION INOUT ;
    USE POWER ;
    PORT
      LAYER SD ;
        RECT 0 19.5 24 20.5 ;
        RECT 4.55 17.85 7.65 20.5 ;
        RECT 4.55 17.8 6.15 20.5 ;
    END
  END VDD
  PIN VSS
    DIRECTION INOUT ;
    USE GROUND ;
    PORT
      LAYER SD ;
        RECT 0 -0.5 24 0.5 ;
        RECT 4.95 -0.5 17.95 5.5 ;
        RECT 6.7 -0.5 8.3 6.25 ;
        RECT 2.425 3.5 17.95 5.1 ;
        RECT 3.5 -0.5 17.95 5.1 ;
        RECT 3.425 3.45 17.95 5.1 ;
    END
  END VSS
  PIN A
    DIRECTION INPUT ;
    USE SIGNAL ;
    PORT
      LAYER MT1 ;
        RECT 0.5 0.5 3.5 3.5 ;
    END
  END A
  PIN Y
    DIRECTION INPUT ;
    USE SIGNAL ;
    PORT
      LAYER MT1 ;
        RECT 20.5 4.5 23.5 7.5 ;
    END
  END Y
  OBS
    LAYER VIA1 ;
      RECT 21.25 5.25 22.75 6.75 ;
      RECT 1.25 1.25 2.75 2.75 ;
    LAYER GATE ;
      RECT 2.95 6.8 4.95 8.8 ;
      RECT 2.95 6.8 6.45 7.8 ;
      RECT 5.45 1 6.45 7.8 ;
      RECT 5.45 6.125 8.55 6.975 ;
      RECT 5.45 1 17.45 5 ;
      RECT 1.7 0.75 2.55 5.35 ;
      RECT 0.75 0.75 3.25 3.25 ;
      RECT 20.75 4.75 23.25 7.25 ;
    LAYER CONT ;
      RECT 21.5 5.5 22.5 6.5 ;
      RECT 3.45 7.3 4.45 8.3 ;
    LAYER SD ;
      RECT 21.75 4.75 23.25 9.85 ;
      RECT 6.7 7.25 23.25 8.25 ;
      RECT 20.75 4.75 23.25 8.25 ;
      RECT 6.7 6.85 8.3 8.25 ;
      RECT 0.45 6.8 4.95 8.8 ;
      RECT 0.45 3.5 1.45 8.8 ;
      RECT 0.45 3.5 1.825 5.1 ;
  END
END DLY2_X1RL_T5

MACRO DLY4_X1PC_T5
  CLASS CORE ;
  ORIGIN 0 0 ;
  FOREIGN DLY4_X1PC_T5 0 0 ;
  SIZE 32 BY 20 ;
  SYMMETRY X Y ;
  SITE CoreSite_T5 ;
  PIN VDD
    DIRECTION INOUT ;
    USE POWER ;
    PORT
      LAYER SD ;
        RECT 0 19.5 32 20.5 ;
        RECT 28.475 15.075 30.075 20.5 ;
        RECT 8.5 17.9 10 20.5 ;
        RECT 0.5 18 2.1 20.5 ;
    END
  END VDD
  PIN VSS
    DIRECTION INOUT ;
    USE GROUND ;
    PORT
      LAYER SD ;
        RECT 0 -0.5 32 0.5 ;
        RECT 28.475 -0.5 30.075 1.9 ;
        RECT 24.4 6 25.4 7.6 ;
        RECT 15.5 -0.5 24.5 7.5 ;
        RECT 12.825 -0.5 14.425 1.925 ;
    END
  END VSS
  PIN A
    DIRECTION INPUT ;
    USE SIGNAL ;
    PORT
      LAYER MT1 ;
        RECT 8.5 0.5 11.5 3.5 ;
    END
  END A
  PIN Y
    DIRECTION INPUT ;
    USE SIGNAL ;
    PORT
      LAYER MT1 ;
        RECT 28.5 8.5 31.5 11.5 ;
    END
  END Y
  OBS
    LAYER VIA1 ;
      RECT 29.25 9.25 30.75 10.75 ;
      RECT 9.25 1.25 10.75 2.75 ;
    LAYER GATE ;
      RECT 25.275 2 26.125 7.85 ;
      RECT 10.45 5.2 12.45 7.2 ;
      RECT 16 1 24 7 ;
      RECT 10.45 5.7 24 6.7 ;
      RECT 25.2 2 26.2 5.75 ;
      RECT 28.225 1.775 30.325 3.225 ;
      RECT 16 2 30.325 3 ;
      RECT 28.225 13.75 30.325 15.2 ;
      RECT 25.2 13.8 30.325 14.8 ;
      RECT 25.2 12.4 27.2 14.8 ;
      RECT 8.75 2.25 14.675 3.25 ;
      RECT 12.575 1.8 14.675 3.25 ;
      RECT 8.75 0.75 11.25 3.25 ;
      RECT 28.75 8.75 31.25 11.25 ;
    LAYER CONT ;
      RECT 29.5 9.5 30.5 10.5 ;
      RECT 25.7 12.9 26.7 13.9 ;
      RECT 10.95 5.7 11.95 6.7 ;
    LAYER SD ;
      RECT 28.475 12.875 30.075 13.875 ;
      RECT 28.575 3.1 29.975 13.875 ;
      RECT 28.575 8.75 31.25 11.25 ;
      RECT 28.475 3.1 30.075 4.1 ;
      RECT 26.575 6.1 27.575 14.8 ;
      RECT 25.2 12.4 27.575 14.4 ;
      RECT 12.475 8.9 27.575 9.9 ;
      RECT 12.475 8.3 13.975 9.9 ;
      RECT 26 6 27 7.6 ;
      RECT 10.45 5.2 12.45 7.2 ;
      RECT 8.5 5.2 14.425 6.6 ;
      RECT 12.825 3.125 14.425 6.6 ;
      RECT 8.5 5.1 10.1 6.6 ;
  END
END DLY4_X1PC_T5

MACRO DLY4_X1RL_T5
  CLASS CORE ;
  ORIGIN 0 0 ;
  FOREIGN DLY4_X1RL_T5 0 0 ;
  SIZE 20 BY 20 ;
  SYMMETRY X Y ;
  SITE CoreSite_T5 ;
  PIN VDD
    DIRECTION INOUT ;
    USE POWER ;
    PORT
      LAYER SD ;
        RECT 0 19.5 20 20.5 ;
        RECT 18 17.9 19.5 20.5 ;
        RECT 0.5 18 2.1 20.5 ;
    END
  END VDD
  PIN VSS
    DIRECTION INOUT ;
    USE GROUND ;
    PORT
      LAYER SD ;
        RECT 0 -0.5 20 0.5 ;
        RECT 14.5 -0.5 19.5 13.975 ;
        RECT 13.5 9.75 19.5 11.35 ;
        RECT 12 -0.5 13.6 1.5 ;
    END
  END VSS
  PIN A
    DIRECTION INPUT ;
    USE SIGNAL ;
    PORT
      LAYER MT1 ;
        RECT 8.5 0.5 11.5 3.5 ;
    END
  END A
  PIN Y
    DIRECTION INPUT ;
    USE SIGNAL ;
    PORT
      LAYER MT1 ;
        RECT 8.5 8.5 11.5 11.5 ;
    END
  END Y
  OBS
    LAYER VIA1 ;
      RECT 9.25 1.25 10.75 2.75 ;
      RECT 9.25 9.25 10.75 10.75 ;
    LAYER GATE ;
      RECT 12.7 11.6 13.7 14.55 ;
      RECT 11.5 12.5 13.7 14.5 ;
      RECT 15 1.475 19 13.475 ;
      RECT 12.775 5.45 13.625 14.55 ;
      RECT 12.7 5.45 13.7 9.5 ;
      RECT 12.425 6.625 19 7.625 ;
      RECT 11.5 5.45 13.7 7.45 ;
      RECT 8.75 0.75 11.25 3.25 ;
      RECT 8.75 1.3 11.75 2.3 ;
      RECT 8.75 1.375 13.85 2.225 ;
      RECT 8.75 8.75 11.25 11.25 ;
    LAYER CONT ;
      RECT 12 5.95 13 6.95 ;
      RECT 12 13 13 14 ;
      RECT 9.5 9.5 10.5 10.5 ;
    LAYER SD ;
      RECT 11.5 5.45 13.5 7.45 ;
      RECT 12.1 2.1 13.5 7.45 ;
      RECT 12 2.1 13.6 3.1 ;
      RECT 12 12.5 13.5 16.3 ;
      RECT 11.5 12.5 13.5 14.5 ;
      RECT 8.5 9.75 12.9 11.35 ;
      RECT 8.5 8.75 11.25 11.35 ;
      RECT 8.5 6.8 10.1 11.35 ;
  END
END DLY4_X1RL_T5

MACRO FILL1_T5
  CLASS CORE ;
  ORIGIN 0 0 ;
  FOREIGN FILL1_T5 0 0 ;
  SIZE 4 BY 20 ;
  SYMMETRY X Y ;
  SITE CoreSite_T5 ;
  PIN VDD
    DIRECTION INOUT ;
    USE POWER ;
    PORT
      LAYER SD ;
        RECT 0 19.5 4 20.5 ;
    END
  END VDD
  PIN VSS
    DIRECTION INOUT ;
    USE GROUND ;
    PORT
      LAYER SD ;
        RECT 0 -0.5 4 0.5 ;
    END
  END VSS
END FILL1_T5

MACRO FILL2_T5
  CLASS CORE ;
  ORIGIN 0 0 ;
  FOREIGN FILL2_T5 0 0 ;
  SIZE 8 BY 20 ;
  SYMMETRY X Y ;
  SITE CoreSite_T5 ;
  PIN VDD
    DIRECTION INOUT ;
    USE POWER ;
    PORT
      LAYER SD ;
        RECT 0 19.5 8 20.5 ;
    END
  END VDD
  PIN VSS
    DIRECTION INOUT ;
    USE GROUND ;
    PORT
      LAYER SD ;
        RECT 0 -0.5 8 0.5 ;
    END
  END VSS
END FILL2_T5

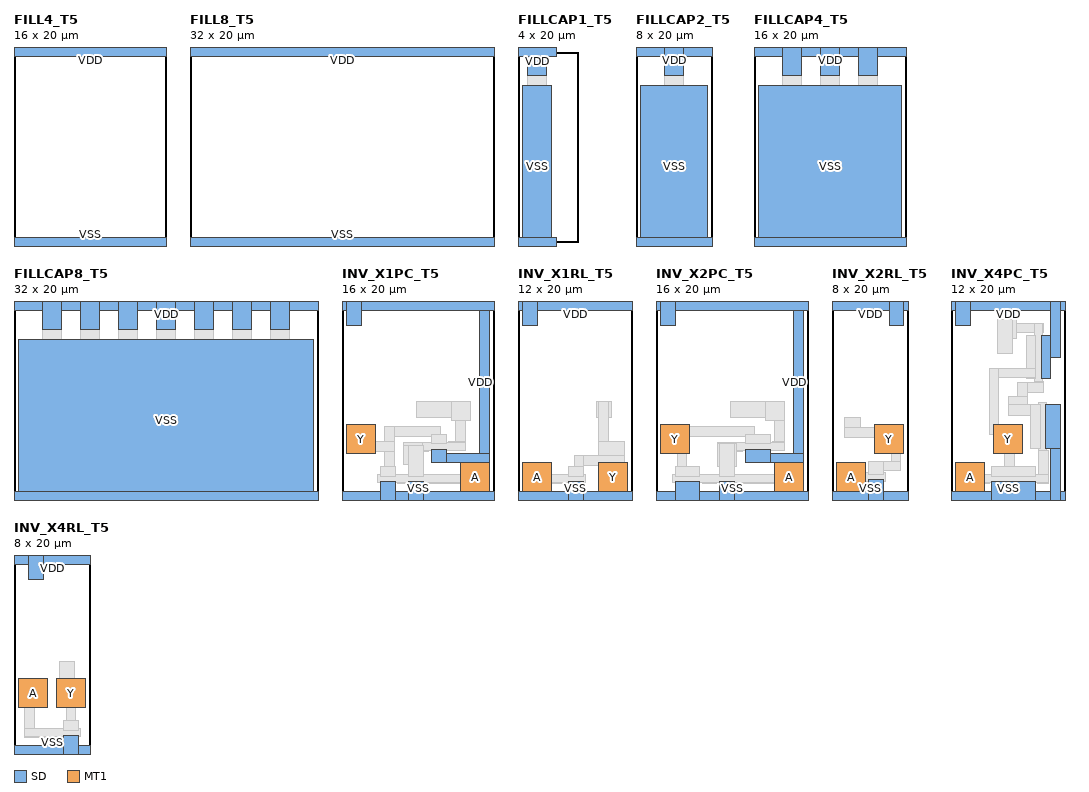
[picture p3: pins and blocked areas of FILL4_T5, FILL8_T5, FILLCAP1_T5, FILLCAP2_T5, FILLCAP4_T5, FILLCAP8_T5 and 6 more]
MACRO FILL4_T5
  CLASS CORE ;
  ORIGIN 0 0 ;
  FOREIGN FILL4_T5 0 0 ;
  SIZE 16 BY 20 ;
  SYMMETRY X Y ;
  SITE CoreSite_T5 ;
  PIN VDD
    DIRECTION INOUT ;
    USE POWER ;
    PORT
      LAYER SD ;
        RECT 0 19.5 16 20.5 ;
    END
  END VDD
  PIN VSS
    DIRECTION INOUT ;
    USE GROUND ;
    PORT
      LAYER SD ;
        RECT 0 -0.5 16 0.5 ;
    END
  END VSS
END FILL4_T5

MACRO FILL8_T5
  CLASS CORE ;
  ORIGIN 0 0 ;
  FOREIGN FILL8_T5 0 0 ;
  SIZE 32 BY 20 ;
  SYMMETRY X Y ;
  SITE CoreSite_T5 ;
  PIN VDD
    DIRECTION INOUT ;
    USE POWER ;
    PORT
      LAYER SD ;
        RECT 0 19.5 32 20.5 ;
    END
  END VDD
  PIN VSS
    DIRECTION INOUT ;
    USE GROUND ;
    PORT
      LAYER SD ;
        RECT 0 -0.5 32 0.5 ;
    END
  END VSS
END FILL8_T5

MACRO FILLCAP1_T5
  CLASS CORE ;
  ORIGIN 0 0 ;
  FOREIGN FILLCAP1_T5 0 0 ;
  SIZE 4 BY 20 ;
  SYMMETRY X Y ;
  SITE CoreSite_T5 ;
  PIN VDD
    DIRECTION INOUT ;
    USE POWER ;
    PORT
      LAYER SD ;
        RECT 0 19.5 4 20.5 ;
        RECT 1 17.5 3 20.5 ;
    END
  END VDD
  PIN VSS
    DIRECTION INOUT ;
    USE GROUND ;
    PORT
      LAYER SD ;
        RECT 0 -0.5 4 0.5 ;
        RECT 0.5 -0.5 3.5 16.5 ;
    END
  END VSS
  OBS
    LAYER GATE ;
      RECT 1 0.5 3 19.5 ;
    LAYER CONT ;
      RECT 1.5 18 2.5 19 ;
  END
END FILLCAP1_T5

MACRO FILLCAP2_T5
  CLASS CORE ;
  ORIGIN 0 0 ;
  FOREIGN FILLCAP2_T5 0 0 ;
  SIZE 8 BY 20 ;
  SYMMETRY X Y ;
  SITE CoreSite_T5 ;
  PIN VDD
    DIRECTION INOUT ;
    USE POWER ;
    PORT
      LAYER SD ;
        RECT 0 19.5 8 20.5 ;
        RECT 3 17.5 5 20.5 ;
    END
  END VDD
  PIN VSS
    DIRECTION INOUT ;
    USE GROUND ;
    PORT
      LAYER SD ;
        RECT 0 -0.5 8 0.5 ;
        RECT 0.5 -0.5 7.5 16.5 ;
    END
  END VSS
  OBS
    LAYER GATE ;
      RECT 3 0.5 5 19.5 ;
      RECT 1 0.5 7 16 ;
    LAYER CONT ;
      RECT 3.5 18 4.5 19 ;
  END
END FILLCAP2_T5

MACRO FILLCAP4_T5
  CLASS CORE ;
  ORIGIN 0 0 ;
  FOREIGN FILLCAP4_T5 0 0 ;
  SIZE 16 BY 20 ;
  SYMMETRY X Y ;
  SITE CoreSite_T5 ;
  PIN VDD
    DIRECTION INOUT ;
    USE POWER ;
    PORT
      LAYER SD ;
        RECT 0 19.5 16 20.5 ;
        RECT 11 17.5 13 20.5 ;
        RECT 7 17.5 9 20.5 ;
        RECT 3 17.5 5 20.5 ;
    END
  END VDD
  PIN VSS
    DIRECTION INOUT ;
    USE GROUND ;
    PORT
      LAYER SD ;
        RECT 0 -0.5 16 0.5 ;
        RECT 0.5 -0.5 15.5 16.5 ;
    END
  END VSS
  OBS
    LAYER GATE ;
      RECT 11 0.5 13 19.5 ;
      RECT 7 0.5 9 19.5 ;
      RECT 3 0.5 5 19.5 ;
      RECT 1 0.5 15 16 ;
    LAYER CONT ;
      RECT 11.5 18 12.5 19 ;
      RECT 7.5 18 8.5 19 ;
      RECT 3.5 18 4.5 19 ;
  END
END FILLCAP4_T5

MACRO FILLCAP8_T5
  CLASS CORE ;
  ORIGIN 0 0 ;
  FOREIGN FILLCAP8_T5 0 0 ;
  SIZE 32 BY 20 ;
  SYMMETRY X Y ;
  SITE CoreSite_T5 ;
  PIN VDD
    DIRECTION INOUT ;
    USE POWER ;
    PORT
      LAYER SD ;
        RECT 0 19.5 32 20.5 ;
        RECT 27 17.5 29 20.5 ;
        RECT 23 17.5 25 20.5 ;
        RECT 19 17.5 21 20.5 ;
        RECT 15 17.5 17 20.5 ;
        RECT 11 17.5 13 20.5 ;
        RECT 7 17.5 9 20.5 ;
        RECT 3 17.5 5 20.5 ;
    END
  END VDD
  PIN VSS
    DIRECTION INOUT ;
    USE GROUND ;
    PORT
      LAYER SD ;
        RECT 0 -0.5 32 0.5 ;
        RECT 0.5 -0.5 31.5 16.5 ;
    END
  END VSS
  OBS
    LAYER GATE ;
      RECT 27 0.5 29 19.5 ;
      RECT 23 0.5 25 19.5 ;
      RECT 19 0.5 21 19.5 ;
      RECT 15 0.5 17 19.5 ;
      RECT 11 0.5 13 19.5 ;
      RECT 7 0.5 9 19.5 ;
      RECT 3 0.5 5 19.5 ;
      RECT 1 0.5 31 16 ;
    LAYER CONT ;
      RECT 27.5 18 28.5 19 ;
      RECT 23.5 18 24.5 19 ;
      RECT 19.5 18 20.5 19 ;
      RECT 15.5 18 16.5 19 ;
      RECT 11.5 18 12.5 19 ;
      RECT 7.5 18 8.5 19 ;
      RECT 3.5 18 4.5 19 ;
  END
END FILLCAP8_T5

MACRO INV_X1PC_T5
  CLASS CORE ;
  ORIGIN 0 0 ;
  FOREIGN INV_X1PC_T5 0 0 ;
  SIZE 16 BY 20 ;
  SYMMETRY X Y ;
  SITE CoreSite_T5 ;
  PIN VDD
    DIRECTION INOUT ;
    USE POWER ;
    PORT
      LAYER SD ;
        RECT 0 19.5 16 20.5 ;
        RECT 14.5 3.5 15.5 20.5 ;
        RECT 9.4 3.5 15.5 4.5 ;
        RECT 9.4 3.5 11 4.875 ;
        RECT 0.5 17.9 2 20.5 ;
    END
  END VDD
  PIN VSS
    DIRECTION INOUT ;
    USE GROUND ;
    PORT
      LAYER SD ;
        RECT 0 -0.5 16 0.5 ;
        RECT 7 -0.5 8.6 1.5 ;
        RECT 4 -0.5 5.6 1.5 ;
    END
  END VSS
  PIN A
    DIRECTION INPUT ;
    USE SIGNAL ;
    PORT
      LAYER MT1 ;
        RECT 12.5 0.5 15.5 3.5 ;
    END
  END A
  PIN Y
    DIRECTION INPUT ;
    USE SIGNAL ;
    PORT
      LAYER MT1 ;
        RECT 0.5 4.5 3.5 7.5 ;
    END
  END Y
  OBS
    LAYER VIA1 ;
      RECT 13.25 1.25 14.75 2.75 ;
      RECT 1.25 5.25 2.75 6.75 ;
    LAYER GATE ;
      RECT 12.75 0.75 15.25 3.25 ;
      RECT 8.85 1.3 15.25 2.3 ;
      RECT 5.85 1.3 6.75 2.3 ;
      RECT 3.75 1.375 15.25 2.225 ;
      RECT 11.5 7.9 13.5 9.9 ;
      RECT 11.975 4.75 12.975 9.9 ;
      RECT 11.25 4.75 12.975 5.75 ;
      RECT 6.5 4.675 9.15 5.675 ;
      RECT 6.5 4.75 12.975 5.6 ;
      RECT 6.5 3.35 8.5 5.675 ;
      RECT 0.75 4.75 3.25 7.25 ;
    LAYER CONT ;
      RECT 12 8.4 13 9.4 ;
      RECT 7 3.85 8 4.85 ;
      RECT 1.5 5.5 2.5 6.5 ;
    LAYER SD ;
      RECT 7.8 8.3 13.5 9.9 ;
      RECT 11.5 7.9 13.5 9.9 ;
      RECT 4.5 6.3 10.4 7.3 ;
      RECT 0.75 4.7 3.25 7.25 ;
      RECT 9.4 5.475 11 6.475 ;
      RECT 4.5 2.1 5.5 7.3 ;
      RECT 0.75 4.7 5.5 5.7 ;
      RECT 4 2.1 5.6 3.1 ;
      RECT 6.5 3.35 8.6 5.35 ;
      RECT 7 2.1 8.6 5.35 ;
  END
END INV_X1PC_T5

MACRO INV_X1RL_T5
  CLASS CORE ;
  ORIGIN 0 0 ;
  FOREIGN INV_X1RL_T5 0 0 ;
  SIZE 12 BY 20 ;
  SYMMETRY X Y ;
  SITE CoreSite_T5 ;
  PIN VDD
    DIRECTION INOUT ;
    USE POWER ;
    PORT
      LAYER SD ;
        RECT 0 19.5 12 20.5 ;
        RECT 0.5 18 2.1 20.5 ;
    END
  END VDD
  PIN VSS
    DIRECTION INOUT ;
    USE GROUND ;
    PORT
      LAYER SD ;
        RECT 0 -0.5 12 0.5 ;
        RECT 5.3 -0.5 6.9 1.5 ;
    END
  END VSS
  PIN A
    DIRECTION INPUT ;
    USE SIGNAL ;
    PORT
      LAYER MT1 ;
        RECT 0.5 0.5 3.5 3.5 ;
    END
  END A
  PIN Y
    DIRECTION INPUT ;
    USE SIGNAL ;
    PORT
      LAYER MT1 ;
        RECT 8.5 0.5 11.5 3.5 ;
    END
  END Y
  OBS
    LAYER VIA1 ;
      RECT 9.25 1.25 10.75 2.75 ;
      RECT 1.25 1.25 2.75 2.75 ;
    LAYER GATE ;
      RECT 0.75 0.75 3.25 3.25 ;
      RECT 0.75 1.3 5.05 2.3 ;
      RECT 0.75 1.375 7.15 2.225 ;
      RECT 8.75 0.75 11.25 5.75 ;
    LAYER CONT ;
      RECT 9.5 4 10.5 5 ;
    LAYER SD ;
      RECT 8.3 8.3 9.8 9.9 ;
      RECT 8.525 3.25 9.525 9.9 ;
      RECT 8.525 3.25 11.25 5.75 ;
      RECT 5.9 3.25 11.25 4.25 ;
      RECT 5.9 2.1 6.9 4.25 ;
      RECT 5.3 2.1 6.9 3.1 ;
  END
END INV_X1RL_T5

MACRO INV_X2PC_T5
  CLASS CORE ;
  ORIGIN 0 0 ;
  FOREIGN INV_X2PC_T5 0 0 ;
  SIZE 16 BY 20 ;
  SYMMETRY X Y ;
  SITE CoreSite_T5 ;
  PIN VDD
    DIRECTION INOUT ;
    USE POWER ;
    PORT
      LAYER SD ;
        RECT 0 19.5 16 20.5 ;
        RECT 14.5 3.5 15.5 20.5 ;
        RECT 9.4 3.5 15.5 4.5 ;
        RECT 9.4 3.5 12 4.875 ;
        RECT 0.5 17.9 2 20.5 ;
    END
  END VDD
  PIN VSS
    DIRECTION INOUT ;
    USE GROUND ;
    PORT
      LAYER SD ;
        RECT 0 -0.5 16 0.5 ;
        RECT 6.65 -0.5 8.25 1.5 ;
        RECT 2 -0.5 4.6 1.5 ;
    END
  END VSS
  PIN A
    DIRECTION INPUT ;
    USE SIGNAL ;
    PORT
      LAYER MT1 ;
        RECT 12.5 0.5 15.5 3.5 ;
    END
  END A
  PIN Y
    DIRECTION INPUT ;
    USE SIGNAL ;
    PORT
      LAYER MT1 ;
        RECT 0.5 4.5 3.5 7.5 ;
    END
  END Y
  OBS
    LAYER VIA1 ;
      RECT 13.25 1.25 14.75 2.75 ;
      RECT 1.25 5.25 2.75 6.75 ;
    LAYER GATE ;
      RECT 12.75 0.75 15.25 3.25 ;
      RECT 8.5 1.3 15.25 2.3 ;
      RECT 4.85 1.3 6.4 2.3 ;
      RECT 1.75 1.375 15.25 2.225 ;
      RECT 11.5 7.9 13.5 9.9 ;
      RECT 12.5 4.75 13.5 9.9 ;
      RECT 12.25 4.75 13.5 5.75 ;
      RECT 6.5 4.675 9.15 5.675 ;
      RECT 6.5 4.75 13.5 5.6 ;
      RECT 6.5 3.35 8.5 5.675 ;
      RECT 0.75 4.75 3.25 7.25 ;
    LAYER CONT ;
      RECT 12 8.4 13 9.4 ;
      RECT 7 3.85 8 4.85 ;
      RECT 1.5 5.5 2.5 6.5 ;
    LAYER SD ;
      RECT 7.8 8.3 13.5 9.9 ;
      RECT 11.5 7.9 13.5 9.9 ;
      RECT 0.75 6.3 10.4 7.3 ;
      RECT 9.4 5.475 12 6.475 ;
      RECT 0.75 4.75 3.25 7.3 ;
      RECT 2.25 2.1 3.25 7.3 ;
      RECT 2 2.1 4.6 3.1 ;
      RECT 6.5 3.1 8.5 5.475 ;
      RECT 6.65 2.1 8.25 5.475 ;
  END
END INV_X2PC_T5

MACRO INV_X2RL_T5
  CLASS CORE ;
  ORIGIN 0 0 ;
  FOREIGN INV_X2RL_T5 0 0 ;
  SIZE 8 BY 20 ;
  SYMMETRY X Y ;
  SITE CoreSite_T5 ;
  PIN VDD
    DIRECTION INOUT ;
    USE POWER ;
    PORT
      LAYER SD ;
        RECT 0 19.5 8 20.5 ;
        RECT 6 17.9 7.5 20.5 ;
    END
  END VDD
  PIN VSS
    DIRECTION INOUT ;
    USE GROUND ;
    PORT
      LAYER SD ;
        RECT 0 -0.5 8 0.5 ;
        RECT 3.8 -0.5 5.4 1.7 ;
    END
  END VSS
  PIN A
    DIRECTION INPUT ;
    USE SIGNAL ;
    PORT
      LAYER MT1 ;
        RECT 0.5 0.5 3.5 3.5 ;
    END
  END A
  PIN Y
    DIRECTION INPUT ;
    USE SIGNAL ;
    PORT
      LAYER MT1 ;
        RECT 4.5 4.5 7.5 7.5 ;
    END
  END Y
  OBS
    LAYER VIA1 ;
      RECT 5.25 5.25 6.75 6.75 ;
      RECT 1.25 1.25 2.75 2.75 ;
    LAYER GATE ;
      RECT 0.75 0.75 3.25 3.25 ;
      RECT 0.75 1.5 3.55 2.5 ;
      RECT 0.75 1.575 5.65 2.425 ;
      RECT 4.75 4.75 7.25 7.25 ;
    LAYER CONT ;
      RECT 5.5 5.5 6.5 6.5 ;
    LAYER SD ;
      RECT 1.35 6.2 2.95 8.3 ;
      RECT 4.75 4.75 7.25 7.25 ;
      RECT 6.25 2.675 7.25 7.25 ;
      RECT 1.35 6.2 7.25 7.2 ;
      RECT 3.8 2.675 7.25 3.675 ;
      RECT 3.8 2.3 5.4 3.675 ;
  END
END INV_X2RL_T5

MACRO INV_X4PC_T5
  CLASS CORE ;
  ORIGIN 0 0 ;
  FOREIGN INV_X4PC_T5 0 0 ;
  SIZE 12 BY 20 ;
  SYMMETRY X Y ;
  SITE CoreSite_T5 ;
  PIN VDD
    DIRECTION INOUT ;
    USE POWER ;
    PORT
      LAYER SD ;
        RECT 0 19.5 12 20.5 ;
        RECT 10.5 14.625 11.5 20.5 ;
        RECT 9.525 12.325 10.525 16.925 ;
        RECT 0.5 17.9 2.1 20.5 ;
    END
  END VDD
  PIN VSS
    DIRECTION INOUT ;
    USE GROUND ;
    PORT
      LAYER SD ;
        RECT 0 -0.5 12 0.5 ;
        RECT 9.975 5 11.5 9.6 ;
        RECT 10.5 -0.5 11.5 9.6 ;
        RECT 4.3 -0.5 8.9 1.5 ;
    END
  END VSS
  PIN A
    DIRECTION INPUT ;
    USE SIGNAL ;
    PORT
      LAYER MT1 ;
        RECT 0.5 0.5 3.5 3.5 ;
    END
  END A
  PIN Y
    DIRECTION INPUT ;
    USE SIGNAL ;
    PORT
      LAYER MT1 ;
        RECT 4.5 4.5 7.5 7.5 ;
    END
  END Y
  OBS
    LAYER VIA1 ;
      RECT 5.25 5.25 6.75 6.75 ;
      RECT 1.25 1.25 2.75 2.75 ;
    LAYER GATE ;
      RECT 9.25 1.3 10.1 9.85 ;
      RECT 9.25 1.3 10.25 4.75 ;
      RECT 0.75 0.75 3.25 3.25 ;
      RECT 9.15 1.3 10.25 2.3 ;
      RECT 0.75 1.3 4.05 2.3 ;
      RECT 0.75 1.375 10.25 2.225 ;
      RECT 4.9 16.6 6.9 18.6 ;
      RECT 4.9 17.175 9.75 18.175 ;
      RECT 8.8 10.925 9.65 18.175 ;
      RECT 8.75 10.925 9.75 12.075 ;
      RECT 7.05 10.925 9.75 11.975 ;
      RECT 7.05 8.5 8.05 11.975 ;
      RECT 6.05 8.5 8.05 10.5 ;
      RECT 4.75 4.75 7.25 7.25 ;
    LAYER CONT ;
      RECT 6.55 9 7.55 10 ;
      RECT 5.5 5.5 6.5 6.5 ;
      RECT 5.4 17.1 6.4 18.1 ;
    LAYER SD ;
      RECT 6.05 8.5 8.05 10.5 ;
      RECT 6.05 8.5 9.375 9.6 ;
      RECT 8.375 5 9.375 9.6 ;
      RECT 7.925 12.325 8.925 16.925 ;
      RECT 4.05 12.425 8.925 13.425 ;
      RECT 4.05 6.475 5.05 13.425 ;
      RECT 4.75 4.75 7.25 7.5 ;
      RECT 5.675 2.1 6.675 7.5 ;
      RECT 4.3 2.1 8.9 3.1 ;
      RECT 4.9 16.6 6.9 18.6 ;
      RECT 4.9 15 6.5 18.6 ;
  END
END INV_X4PC_T5

MACRO INV_X4RL_T5
  CLASS CORE ;
  ORIGIN 0 0 ;
  FOREIGN INV_X4RL_T5 0 0 ;
  SIZE 8 BY 20 ;
  SYMMETRY X Y ;
  SITE CoreSite_T5 ;
  PIN VDD
    DIRECTION INOUT ;
    USE POWER ;
    PORT
      LAYER SD ;
        RECT 0 19.5 8 20.5 ;
        RECT 1.55 18 3.15 20.5 ;
    END
  END VDD
  PIN VSS
    DIRECTION INOUT ;
    USE GROUND ;
    PORT
      LAYER SD ;
        RECT 0 -0.5 8 0.5 ;
        RECT 5.2 -0.5 6.8 1.5 ;
    END
  END VSS
  PIN A
    DIRECTION INPUT ;
    USE SIGNAL ;
    PORT
      LAYER MT1 ;
        RECT 0.5 4.5 3.5 7.5 ;
    END
  END A
  PIN Y
    DIRECTION INPUT ;
    USE SIGNAL ;
    PORT
      LAYER MT1 ;
        RECT 4.5 4.5 7.5 7.5 ;
    END
  END Y
  OBS
    LAYER VIA1 ;
      RECT 5.25 5.25 6.75 6.75 ;
      RECT 1.25 5.25 2.75 6.75 ;
    LAYER GATE ;
      RECT 0.75 4.75 3.25 7.25 ;
      RECT 1.15 1.3 2.15 7.25 ;
      RECT 1.15 1.3 4.95 2.3 ;
      RECT 1.15 1.375 7.05 2.225 ;
      RECT 4.75 4.75 7.25 7.25 ;
    LAYER CONT ;
      RECT 5.5 5.5 6.5 6.5 ;
    LAYER SD ;
      RECT 4.75 4.75 6.35 9.3 ;
      RECT 4.75 4.75 7.25 7.25 ;
      RECT 5.5 2.1 6.5 7.25 ;
      RECT 5.2 2.1 6.8 3.1 ;
  END
END INV_X4RL_T5

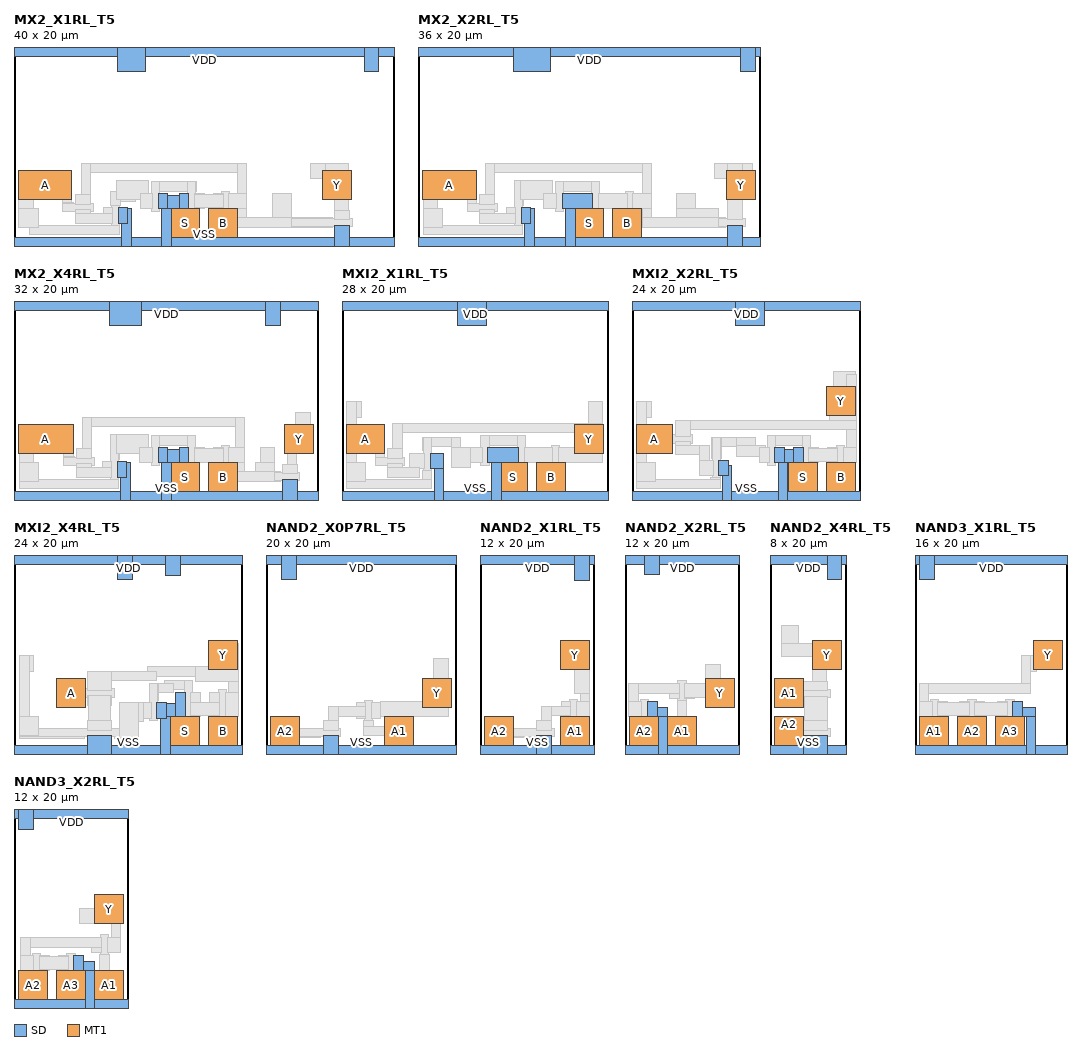
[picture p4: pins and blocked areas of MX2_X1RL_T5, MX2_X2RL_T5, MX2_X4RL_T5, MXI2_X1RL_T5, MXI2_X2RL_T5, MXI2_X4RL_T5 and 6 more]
MACRO MX2_X1RL_T5
  CLASS CORE ;
  ORIGIN 0 0 ;
  FOREIGN MX2_X1RL_T5 0 0 ;
  SIZE 40 BY 20 ;
  SYMMETRY X Y ;
  SITE CoreSite_T5 ;
  PIN VDD
    DIRECTION INOUT ;
    USE POWER ;
    PORT
      LAYER SD ;
        RECT 0 19.5 40 20.5 ;
        RECT 36.85 17.9 38.35 20.5 ;
        RECT 10.85 17.9 13.85 20.5 ;
    END
  END VDD
  PIN VSS
    DIRECTION INOUT ;
    USE GROUND ;
    PORT
      LAYER SD ;
        RECT 0 -0.5 40 0.5 ;
        RECT 33.75 -0.5 35.35 1.75 ;
        RECT 17.4 3.5 18.4 5.1 ;
        RECT 15.175 3.5 18.4 4.9 ;
        RECT 15.55 -0.5 16.55 4.9 ;
        RECT 15.175 3.5 16.175 5.1 ;
        RECT 11.35 -0.5 12.35 3.5 ;
        RECT 10.975 2 11.975 3.6 ;
    END
  END VSS
  PIN A
    DIRECTION INPUT ;
    USE SIGNAL ;
    PORT
      LAYER MT1 ;
        RECT 0.5 4.5 6.1 7.5 ;
    END
  END A
  PIN B
    DIRECTION INPUT ;
    USE SIGNAL ;
    PORT
      LAYER MT1 ;
        RECT 20.5 0.5 23.5 3.5 ;
    END
  END B
  PIN S
    DIRECTION INPUT ;
    USE SIGNAL ;
    PORT
      LAYER MT1 ;
        RECT 16.5 0.5 19.5 3.5 ;
    END
  END S
  PIN Y
    DIRECTION INPUT ;
    USE SIGNAL ;
    PORT
      LAYER MT1 ;
        RECT 32.5 4.5 35.5 7.5 ;
    END
  END Y
  OBS
    LAYER VIA1 ;
      RECT 33.25 5.25 34.75 6.75 ;
      RECT 21.25 1.25 22.75 2.75 ;
      RECT 17.5 1.25 19 2.75 ;
      RECT 4.1 5.2 5.6 6.7 ;
    LAYER GATE ;
      RECT 27.2 1.55 29.2 3.55 ;
      RECT 27.2 1.55 33.5 2.55 ;
      RECT 27.2 1.625 35.6 2.475 ;
      RECT 21.875 0.75 22.725 5.35 ;
      RECT 20.75 0.75 23.25 3.25 ;
      RECT 14.45 5.35 19.225 6.35 ;
      RECT 18.275 0.75 19.125 6.35 ;
      RECT 14.45 3.25 15.3 6.35 ;
      RECT 17 0.75 19.5 3.25 ;
      RECT 10.825 4.3 12.825 6.5 ;
      RECT 10.25 0.75 11.1 5.3 ;
      RECT 10.2 3.85 11.2 5.3 ;
      RECT 0.6 1.5 2.6 3.5 ;
      RECT 1.6 0.75 11.1 1.75 ;
      RECT 3.6 4.7 6.1 7.2 ;
      RECT 5.1 3.2 6.1 7.2 ;
      RECT 5.1 3.2 6.225 4.2 ;
      RECT 5.1 3.25 8.325 4.1 ;
      RECT 32.75 4.75 35.25 7.25 ;
    LAYER CONT ;
      RECT 33.5 5.5 34.5 6.5 ;
      RECT 27.7 2.05 28.7 3.05 ;
      RECT 11.325 5 12.325 6 ;
      RECT 1.1 2 2.1 3 ;
    LAYER SD ;
      RECT 31.2 6.7 35.25 8.3 ;
      RECT 33.75 2.35 35.25 8.3 ;
      RECT 32.75 4.75 35.25 8.3 ;
      RECT 33.75 2.35 35.35 3.35 ;
      RECT 7.075 7.3 24.5 8.3 ;
      RECT 23.5 1.55 24.5 8.3 ;
      RECT 7.075 3.975 8.075 8.3 ;
      RECT 27.2 1.55 29.2 5.15 ;
      RECT 22.6 3.5 24.5 5.1 ;
      RECT 6.475 3.975 8.075 4.975 ;
      RECT 23.5 1.55 29.2 2.55 ;
      RECT 21 3.5 22 5.1 ;
      RECT 19 3.5 20 5.1 ;
      RECT 19 3.6 22 5 ;
      RECT 10.825 4.5 14.2 6.5 ;
      RECT 13.35 3.5 14.575 5.1 ;
      RECT 9.375 2 10.375 3.6 ;
      RECT 6.475 2 8.075 3.375 ;
      RECT 6.475 2 10.375 3 ;
      RECT 0.5 1.5 2 6.7 ;
      RECT 0.5 1.5 2.6 3.5 ;
  END
END MX2_X1RL_T5

MACRO MX2_X2RL_T5
  CLASS CORE ;
  ORIGIN 0 0 ;
  FOREIGN MX2_X2RL_T5 0 0 ;
  SIZE 36 BY 20 ;
  SYMMETRY X Y ;
  SITE CoreSite_T5 ;
  PIN VDD
    DIRECTION INOUT ;
    USE POWER ;
    PORT
      LAYER SD ;
        RECT 0 19.5 36 20.5 ;
        RECT 33.95 17.9 35.5 20.5 ;
        RECT 10.1 17.9 13.9 20.5 ;
    END
  END VDD
  PIN VSS
    DIRECTION INOUT ;
    USE GROUND ;
    PORT
      LAYER SD ;
        RECT 0 -0.5 36 0.5 ;
        RECT 32.6 -0.5 34.2 1.75 ;
        RECT 15.175 3.5 18.4 5.1 ;
        RECT 15.55 -0.5 16.55 5.1 ;
        RECT 11.25 -0.5 12.25 3.5 ;
        RECT 10.875 2 11.875 3.6 ;
    END
  END VSS
  PIN A
    DIRECTION INPUT ;
    USE SIGNAL ;
    PORT
      LAYER MT1 ;
        RECT 0.5 4.5 6.2 7.5 ;
    END
  END A
  PIN B
    DIRECTION INPUT ;
    USE SIGNAL ;
    PORT
      LAYER MT1 ;
        RECT 20.5 0.5 23.5 3.5 ;
    END
  END B
  PIN S
    DIRECTION INPUT ;
    USE SIGNAL ;
    PORT
      LAYER MT1 ;
        RECT 16.5 0.5 19.5 3.5 ;
    END
  END S
  PIN Y
    DIRECTION INPUT ;
    USE SIGNAL ;
    PORT
      LAYER MT1 ;
        RECT 32.5 4.5 35.5 7.5 ;
    END
  END Y
  OBS
    LAYER VIA1 ;
      RECT 33.25 5.25 34.75 6.75 ;
      RECT 21.25 1.25 22.75 2.75 ;
      RECT 17.5 1.25 19 2.75 ;
      RECT 4.2 5.25 5.7 6.75 ;
    LAYER GATE ;
      RECT 29.6 1.55 31.6 3.55 ;
      RECT 29.6 1.55 32.35 2.55 ;
      RECT 29.6 1.625 34.45 2.475 ;
      RECT 21.875 0.75 22.725 5.35 ;
      RECT 20.75 0.75 23.25 3.25 ;
      RECT 14.45 5.35 19.125 6.35 ;
      RECT 18.275 0.75 19.125 6.35 ;
      RECT 14.45 3.25 15.3 6.35 ;
      RECT 17 0.75 19.5 3.25 ;
      RECT 10.15 4.5 12.825 6.5 ;
      RECT 10.15 3.85 11.15 6.5 ;
      RECT 10.15 0.75 11 6.5 ;
      RECT 0.6 0.75 2.6 3.5 ;
      RECT 0.6 0.75 11 1.75 ;
      RECT 3.7 4.75 6.2 7.25 ;
      RECT 5.2 3.25 6.2 7.25 ;
      RECT 5.2 3.25 8.35 4.1 ;
      RECT 32.75 4.75 35.25 7.25 ;
    LAYER CONT ;
      RECT 33.5 5.5 34.5 6.5 ;
      RECT 30.1 2.05 31.1 3.05 ;
      RECT 11.325 5 12.325 6 ;
      RECT 1.1 2 2.1 3 ;
    LAYER SD ;
      RECT 31.25 6.7 35.25 8.3 ;
      RECT 32.6 4.75 35.25 8.3 ;
      RECT 32.6 2.35 34.2 8.3 ;
      RECT 7.1 7.3 24.6 8.3 ;
      RECT 23.6 1.55 24.6 8.3 ;
      RECT 7.1 3.975 8.1 8.3 ;
      RECT 27.25 1.55 29.25 5.15 ;
      RECT 22.6 3.5 24.6 5.1 ;
      RECT 6.5 3.975 8.1 4.975 ;
      RECT 27.25 1.55 31.6 3.55 ;
      RECT 23.6 1.55 31.6 2.55 ;
      RECT 10.825 4.5 14.2 6.5 ;
      RECT 13.2 3.5 14.575 5.1 ;
      RECT 9.275 2 10.275 3.6 ;
      RECT 6.5 2 8.1 3.375 ;
      RECT 6.5 2 10.275 3 ;
      RECT 0.6 1.5 2.1 6.7 ;
      RECT 0.6 1.5 2.6 3.5 ;
      RECT 19 3.5 22 5.1 ;
  END
END MX2_X2RL_T5

MACRO MX2_X4RL_T5
  CLASS CORE ;
  ORIGIN 0 0 ;
  FOREIGN MX2_X4RL_T5 0 0 ;
  SIZE 32 BY 20 ;
  SYMMETRY X Y ;
  SITE CoreSite_T5 ;
  PIN VDD
    DIRECTION INOUT ;
    USE POWER ;
    PORT
      LAYER SD ;
        RECT 0 19.5 32 20.5 ;
        RECT 26.45 18 28.05 20.5 ;
        RECT 10.1 17.9 13.4 20.5 ;
    END
  END VDD
  PIN VSS
    DIRECTION INOUT ;
    USE GROUND ;
    PORT
      LAYER SD ;
        RECT 0 -0.5 32 0.5 ;
        RECT 28.25 -0.5 29.85 1.75 ;
        RECT 17.4 3.5 18.4 5.1 ;
        RECT 15.175 3.5 18.4 4.9 ;
        RECT 15.55 -0.5 16.55 4.9 ;
        RECT 15.175 3.5 16.175 5.1 ;
        RECT 11.25 -0.5 12.25 3.475 ;
        RECT 10.875 2 11.875 3.6 ;
    END
  END VSS
  PIN A
    DIRECTION INPUT ;
    USE SIGNAL ;
    PORT
      LAYER MT1 ;
        RECT 0.5 4.5 6.225 7.5 ;
    END
  END A
  PIN B
    DIRECTION INPUT ;
    USE SIGNAL ;
    PORT
      LAYER MT1 ;
        RECT 20.5 0.5 23.5 3.5 ;
    END
  END B
  PIN S
    DIRECTION INPUT ;
    USE SIGNAL ;
    PORT
      LAYER MT1 ;
        RECT 16.5 0.5 19.5 3.5 ;
    END
  END S
  PIN Y
    DIRECTION INPUT ;
    USE SIGNAL ;
    PORT
      LAYER MT1 ;
        RECT 28.5 4.5 31.5 7.5 ;
    END
  END Y
  OBS
    LAYER VIA1 ;
      RECT 29.25 5.25 30.75 6.75 ;
      RECT 21.05 1.25 22.55 2.75 ;
      RECT 17.5 1.25 19 2.75 ;
      RECT 4.225 5.05 5.725 6.55 ;
    LAYER GATE ;
      RECT 25.45 1.55 27.45 3.55 ;
      RECT 25.45 1.55 28 2.55 ;
      RECT 25.45 1.625 30.1 2.475 ;
      RECT 21.875 0.75 22.725 5.35 ;
      RECT 20.55 0.75 23.05 3.25 ;
      RECT 14.45 5.35 19.125 6.35 ;
      RECT 18.275 0.75 19.125 6.35 ;
      RECT 14.45 3.25 15.3 6.35 ;
      RECT 17 0.75 19.5 3.25 ;
      RECT 10.15 4.5 12.825 6.5 ;
      RECT 10.15 3.85 11.15 6.5 ;
      RECT 10.15 0.75 11 6.5 ;
      RECT 0.6 0.75 2.6 3.5 ;
      RECT 0.6 0.75 11 1.75 ;
      RECT 3.725 4.55 6.225 7.05 ;
      RECT 5.225 3.2 6.225 7.05 ;
      RECT 5.225 3.2 6.325 4.2 ;
      RECT 5.225 3.25 8.425 4.1 ;
      RECT 28.75 4.75 31.25 7.25 ;
    LAYER CONT ;
      RECT 29.5 5.5 30.5 6.5 ;
      RECT 25.95 2.05 26.95 3.05 ;
      RECT 11.325 5 12.325 6 ;
      RECT 1.1 2 2.1 3 ;
    LAYER SD ;
      RECT 29.65 4.75 31.25 8.8 ;
      RECT 28.75 2.35 29.75 7.25 ;
      RECT 28.25 2.35 29.85 3.35 ;
      RECT 7.175 7.3 24.3 8.3 ;
      RECT 23.3 1.55 24.3 8.3 ;
      RECT 7.175 3.975 8.175 8.3 ;
      RECT 25.95 1.55 27.45 5.15 ;
      RECT 22.6 3.5 24.3 5.1 ;
      RECT 6.575 3.975 8.175 4.975 ;
      RECT 25.45 1.55 27.45 3.55 ;
      RECT 23.3 1.55 27.45 2.55 ;
      RECT 21 3.5 22 5.1 ;
      RECT 19 3.5 20 5.1 ;
      RECT 19 3.55 22 4.95 ;
      RECT 10.825 4.5 14.2 6.5 ;
      RECT 13.2 3.5 14.575 5.1 ;
      RECT 9.275 2 10.275 3.6 ;
      RECT 6.575 2 8.175 3.375 ;
      RECT 6.575 2 10.275 3 ;
      RECT 0.6 1.5 2.1 6.7 ;
      RECT 0.6 1.5 2.6 3.5 ;
  END
END MX2_X4RL_T5

MACRO MXI2_X1RL_T5
  CLASS CORE ;
  ORIGIN 0 0 ;
  FOREIGN MXI2_X1RL_T5 0 0 ;
  SIZE 28 BY 20 ;
  SYMMETRY X Y ;
  SITE CoreSite_T5 ;
  PIN VDD
    DIRECTION INOUT ;
    USE POWER ;
    PORT
      LAYER SD ;
        RECT 0 19.5 28 20.5 ;
        RECT 12.2 17.9 15.2 20.5 ;
    END
  END VDD
  PIN VSS
    DIRECTION INOUT ;
    USE GROUND ;
    PORT
      LAYER SD ;
        RECT 0 -0.5 28 0.5 ;
        RECT 15.35 3.5 18.575 5.1 ;
        RECT 15.75 -0.5 16.75 5.1 ;
        RECT 9.325 2.9 10.7 4.5 ;
        RECT 9.7 -0.5 10.7 4.5 ;
    END
  END VSS
  PIN A
    DIRECTION INPUT ;
    USE SIGNAL ;
    PORT
      LAYER MT1 ;
        RECT 0.5 4.5 4.5 7.5 ;
    END
  END A
  PIN B
    DIRECTION INPUT ;
    USE SIGNAL ;
    PORT
      LAYER MT1 ;
        RECT 20.5 0.5 23.5 3.5 ;
    END
  END B
  PIN S
    DIRECTION INPUT ;
    USE SIGNAL ;
    PORT
      LAYER MT1 ;
        RECT 16.5 0.5 19.5 3.5 ;
    END
  END S
  PIN Y
    DIRECTION INPUT ;
    USE SIGNAL ;
    PORT
      LAYER MT1 ;
        RECT 24.5 4.5 27.5 7.5 ;
    END
  END Y
  OBS
    LAYER VIA1 ;
      RECT 25.25 5.25 26.75 6.75 ;
      RECT 21.25 1.25 22.75 2.75 ;
      RECT 17.5 1.25 19 2.75 ;
      RECT 2.5 5.25 4 6.75 ;
    LAYER GATE ;
      RECT 22.05 0.75 22.9 5.35 ;
      RECT 20.75 0.75 23.25 3.25 ;
      RECT 14.625 5.35 19.3 6.35 ;
      RECT 18.45 0.75 19.3 6.35 ;
      RECT 14.625 3.25 15.475 6.35 ;
      RECT 17 0.75 19.5 3.25 ;
      RECT 8.45 5.2 12.5 6.2 ;
      RECT 11.5 2.95 12.5 6.2 ;
      RECT 8.45 4.75 9.45 6.2 ;
      RECT 8.6 0.75 9.45 6.2 ;
      RECT 11.5 2.95 13.5 4.95 ;
      RECT 0.5 0.75 2.5 3.5 ;
      RECT 8.45 0.75 9.45 2.65 ;
      RECT 0.5 0.75 9.45 1.75 ;
      RECT 2 4.75 4.5 7.25 ;
      RECT 3.5 3.2 4.5 7.25 ;
      RECT 3.5 3.25 6.6 4.1 ;
      RECT 24.75 4.75 27.25 7.25 ;
    LAYER CONT ;
      RECT 25.5 5.5 26.5 6.5 ;
      RECT 12 3.45 13 4.45 ;
      RECT 1 2 2 3 ;
    LAYER SD ;
      RECT 25.9 3.5 27.4 9.9 ;
      RECT 5.35 6.65 27.4 7.65 ;
      RECT 24.75 3.5 27.4 7.65 ;
      RECT 5.35 3.975 6.35 7.65 ;
      RECT 22.775 3.5 27.4 5.1 ;
      RECT 4.75 3.975 6.35 4.975 ;
      RECT 11.5 3.5 14.75 5.1 ;
      RECT 11.5 2.95 13.5 5.1 ;
      RECT 7.15 2.9 8.725 4.5 ;
      RECT 4.75 2 6.35 3.375 ;
      RECT 4.75 2 8.15 3 ;
      RECT 0.5 8.3 2 9.9 ;
      RECT 0.5 1.5 1.5 9.9 ;
      RECT 0.5 1.5 2.5 3.5 ;
      RECT 19.175 3.5 22.175 5.1 ;
  END
END MXI2_X1RL_T5

MACRO MXI2_X2RL_T5
  CLASS CORE ;
  ORIGIN 0 0 ;
  FOREIGN MXI2_X2RL_T5 0 0 ;
  SIZE 24 BY 20 ;
  SYMMETRY X Y ;
  SITE CoreSite_T5 ;
  PIN VDD
    DIRECTION INOUT ;
    USE POWER ;
    PORT
      LAYER SD ;
        RECT 0 19.5 24 20.5 ;
        RECT 10.9 17.9 13.9 20.5 ;
    END
  END VDD
  PIN VSS
    DIRECTION INOUT ;
    USE GROUND ;
    PORT
      LAYER SD ;
        RECT 0 -0.5 24 0.5 ;
        RECT 17.025 3.5 18.025 5.1 ;
        RECT 15.025 3.5 18.025 4.9 ;
        RECT 15.4 -0.5 16.4 4.9 ;
        RECT 15.025 3.5 16.025 5.1 ;
        RECT 9.525 -0.5 10.525 3.25 ;
        RECT 9.15 2.15 10.15 3.75 ;
    END
  END VSS
  PIN A
    DIRECTION INPUT ;
    USE SIGNAL ;
    PORT
      LAYER MT1 ;
        RECT 0.5 4.5 4.25 7.5 ;
    END
  END A
  PIN B
    DIRECTION INPUT ;
    USE SIGNAL ;
    PORT
      LAYER MT1 ;
        RECT 20.5 0.5 23.5 3.5 ;
    END
  END B
  PIN S
    DIRECTION INPUT ;
    USE SIGNAL ;
    PORT
      LAYER MT1 ;
        RECT 16.5 0.5 19.5 3.5 ;
    END
  END S
  PIN Y
    DIRECTION INPUT ;
    USE SIGNAL ;
    PORT
      LAYER MT1 ;
        RECT 20.5 8.5 23.5 11.5 ;
    END
  END Y
  OBS
    LAYER VIA1 ;
      RECT 21.25 1.25 22.75 2.75 ;
      RECT 21.25 9.25 22.75 10.75 ;
      RECT 17.5 1.25 19 2.75 ;
      RECT 2.25 5.25 3.75 6.75 ;
    LAYER GATE ;
      RECT 21.5 0.75 22.35 5.35 ;
      RECT 20.75 0.75 23.25 3.25 ;
      RECT 14.3 5.35 18.75 6.35 ;
      RECT 17.9 0.75 18.75 6.35 ;
      RECT 14.3 3.25 15.15 6.35 ;
      RECT 17 0.75 19.5 3.25 ;
      RECT 8.375 5.2 12.95 6.2 ;
      RECT 10.95 4.2 12.95 6.2 ;
      RECT 8.375 4 9.375 6.2 ;
      RECT 8.425 0.75 9.275 6.2 ;
      RECT 0.5 0.75 2.5 3.5 ;
      RECT 8.275 0.75 9.275 1.9 ;
      RECT 0.5 0.75 9.275 1.75 ;
      RECT 1.75 4.75 4.25 7.25 ;
      RECT 1.75 5.575 6.4 6.425 ;
      RECT 20.75 8.75 23.25 11.25 ;
    LAYER CONT ;
      RECT 21.5 9.5 22.5 10.5 ;
      RECT 11.45 4.7 12.45 5.7 ;
      RECT 1 2 2 3 ;
    LAYER SD ;
      RECT 21.2 7 23.55 13.1 ;
      RECT 22.6 3.5 23.6 12.8 ;
      RECT 20.75 7 23.6 11.25 ;
      RECT 4.55 7 23.6 8 ;
      RECT 4.55 6.3 6.15 8 ;
      RECT 22.225 3.5 23.6 5.1 ;
      RECT 20.625 3.5 21.625 5.1 ;
      RECT 18.625 3.5 19.625 5.1 ;
      RECT 18.625 3.6 21.625 5 ;
      RECT 10.95 4.2 12.95 6.2 ;
      RECT 10.95 4.2 14.05 5.3 ;
      RECT 13.425 3.5 14.425 5.1 ;
      RECT 4.55 4.325 6.15 5.7 ;
      RECT 4.55 4.325 8.125 5.325 ;
      RECT 7.125 2.15 8.125 5.325 ;
      RECT 7.125 2.15 8.55 3.75 ;
      RECT 0.5 8.3 2 9.9 ;
      RECT 0.5 1.5 1.5 9.9 ;
      RECT 0.5 1.5 2.5 3.5 ;
  END
END MXI2_X2RL_T5

MACRO MXI2_X4RL_T5
  CLASS CORE ;
  ORIGIN 0 0 ;
  FOREIGN MXI2_X4RL_T5 0 0 ;
  SIZE 24 BY 20 ;
  SYMMETRY X Y ;
  SITE CoreSite_T5 ;
  PIN VDD
    DIRECTION INOUT ;
    USE POWER ;
    PORT
      LAYER SD ;
        RECT 0 19.5 24 20.5 ;
        RECT 15.95 18.35 17.55 20.5 ;
        RECT 10.9 17.9 12.5 20.5 ;
    END
  END VDD
  PIN VSS
    DIRECTION INOUT ;
    USE GROUND ;
    PORT
      LAYER SD ;
        RECT 0 -0.5 24 0.5 ;
        RECT 17.025 3.5 18.025 6.1 ;
        RECT 15.025 3.5 18.025 4.9 ;
        RECT 15.425 -0.5 16.425 4.9 ;
        RECT 15.025 3.35 16.025 4.95 ;
        RECT 7.7 -0.5 10.3 1.5 ;
    END
  END VSS
  PIN A
    DIRECTION INPUT ;
    USE SIGNAL ;
    PORT
      LAYER MT1 ;
        RECT 4.5 4.5 7.5 7.5 ;
    END
  END A
  PIN B
    DIRECTION INPUT ;
    USE SIGNAL ;
    PORT
      LAYER MT1 ;
        RECT 20.5 0.5 23.5 3.5 ;
    END
  END B
  PIN S
    DIRECTION INPUT ;
    USE SIGNAL ;
    PORT
      LAYER MT1 ;
        RECT 16.5 0.5 19.5 3.5 ;
    END
  END S
  PIN Y
    DIRECTION INPUT ;
    USE SIGNAL ;
    PORT
      LAYER MT1 ;
        RECT 20.5 8.5 23.5 11.5 ;
    END
  END Y
  OBS
    LAYER VIA1 ;
      RECT 21.25 1.25 22.75 2.75 ;
      RECT 21.25 9.25 22.75 10.75 ;
      RECT 17.25 1.25 18.75 2.75 ;
      RECT 5.25 5.25 6.75 6.75 ;
    LAYER GATE ;
      RECT 21.5 0.75 22.35 6.35 ;
      RECT 20.75 0.75 23.25 3.25 ;
      RECT 15.85 6.35 18.75 7.35 ;
      RECT 17.9 0.75 18.75 7.35 ;
      RECT 14.25 6.05 16.75 7.05 ;
      RECT 14.25 5.2 15.25 7.05 ;
      RECT 14.3 3.1 15.15 7.05 ;
      RECT 16.75 0.75 19.25 3.25 ;
      RECT 0.6 1.25 2.6 3.5 ;
      RECT 11.1 1.25 13.1 3.3 ;
      RECT 10.55 1.25 13.1 2.25 ;
      RECT 0.6 1.25 7.45 2.25 ;
      RECT 0.6 1.375 13.1 2.225 ;
      RECT 4.75 4.75 7.25 7.25 ;
      RECT 4.75 5.5 7.45 6.5 ;
      RECT 4.75 5.575 10.55 6.425 ;
      RECT 20.75 8.75 23.25 11.25 ;
    LAYER CONT ;
      RECT 21.5 9.5 22.5 10.5 ;
      RECT 11.6 1.8 12.6 2.8 ;
      RECT 1.1 2 2.1 3 ;
    LAYER SD ;
      RECT 20.75 7.25 23.6 11.25 ;
      RECT 22.6 3.5 23.6 11.25 ;
      RECT 14.05 7.75 23.6 8.75 ;
      RECT 19.15 7.25 23.6 8.75 ;
      RECT 7.7 7.3 15.05 8.3 ;
      RECT 7.7 6.3 10.3 8.3 ;
      RECT 22.225 3.5 23.6 6.1 ;
      RECT 20.625 3.5 21.625 6.1 ;
      RECT 18.625 3.5 19.625 6.1 ;
      RECT 18.625 3.6 21.625 5 ;
      RECT 11.1 3.35 14.425 4.95 ;
      RECT 11.1 3.05 13.625 4.95 ;
      RECT 11.1 1.3 13.1 4.95 ;
      RECT 7.7 4.7 10.3 5.7 ;
      RECT 7.8 2.1 10.2 5.7 ;
      RECT 7.7 2.1 10.3 3.1 ;
      RECT 0.6 8.3 2.1 9.9 ;
      RECT 0.6 1.5 1.6 9.9 ;
      RECT 0.6 1.5 2.6 3.5 ;
  END
END MXI2_X4RL_T5

MACRO NAND2_X0P7RL_T5
  CLASS CORE ;
  ORIGIN 0 0 ;
  FOREIGN NAND2_X0P7RL_T5 0 0 ;
  SIZE 20 BY 20 ;
  SYMMETRY X Y ;
  SITE CoreSite_T5 ;
  PIN VDD
    DIRECTION INOUT ;
    USE POWER ;
    PORT
      LAYER SD ;
        RECT 0 19.5 20 20.5 ;
        RECT 1.65 18 3.25 20.5 ;
    END
  END VDD
  PIN VSS
    DIRECTION INOUT ;
    USE GROUND ;
    PORT
      LAYER SD ;
        RECT 0 -0.5 20 0.5 ;
        RECT 6.025 -0.5 7.625 1.5 ;
    END
  END VSS
  PIN A1
    DIRECTION INPUT ;
    USE SIGNAL ;
    PORT
      LAYER MT1 ;
        RECT 12.5 0.5 15.5 3.5 ;
    END
  END A1
  PIN A2
    DIRECTION INPUT ;
    USE SIGNAL ;
    PORT
      LAYER MT1 ;
        RECT 0.5 0.5 3.5 3.5 ;
    END
  END A2
  PIN Y
    DIRECTION INPUT ;
    USE SIGNAL ;
    PORT
      LAYER MT1 ;
        RECT 16.5 4.5 19.5 7.5 ;
    END
  END Y
  OBS
    LAYER VIA1 ;
      RECT 17.25 5.25 18.75 6.75 ;
      RECT 13.25 1.25 14.75 2.75 ;
      RECT 1.25 1.25 2.75 2.75 ;
    LAYER GATE ;
      RECT 10.375 1.475 11.225 5.2 ;
      RECT 12.75 0.75 15.25 3.25 ;
      RECT 10.275 1.475 11.275 3.1 ;
      RECT 10.275 1.475 15.25 2.475 ;
      RECT 0.75 0.75 3.25 3.25 ;
      RECT 0.75 1.3 5.775 2.3 ;
      RECT 0.75 1.375 7.875 2.225 ;
      RECT 16.75 4.75 19.25 7.25 ;
    LAYER CONT ;
      RECT 17.5 5.5 18.5 6.5 ;
    LAYER SD ;
      RECT 17.65 3.5 19.25 9.6 ;
      RECT 16.75 3.5 19.25 7.25 ;
      RECT 12.1 3.5 19.25 5.1 ;
      RECT 11.1 3.35 12.1 4.95 ;
      RECT 9.5 3.35 10.5 4.95 ;
      RECT 6.575 3.575 10.5 4.575 ;
      RECT 6.575 2.1 7.625 4.575 ;
      RECT 6.025 2.1 7.625 3.1 ;
  END
END NAND2_X0P7RL_T5

MACRO NAND2_X1RL_T5
  CLASS CORE ;
  ORIGIN 0 0 ;
  FOREIGN NAND2_X1RL_T5 0 0 ;
  SIZE 12 BY 20 ;
  SYMMETRY X Y ;
  SITE CoreSite_T5 ;
  PIN VDD
    DIRECTION INOUT ;
    USE POWER ;
    PORT
      LAYER SD ;
        RECT 0 19.5 12 20.5 ;
        RECT 9.9 17.85 11.5 20.5 ;
    END
  END VDD
  PIN VSS
    DIRECTION INOUT ;
    USE GROUND ;
    PORT
      LAYER SD ;
        RECT 0 -0.5 12 0.5 ;
        RECT 5.95 -0.5 7.55 1.5 ;
    END
  END VSS
  PIN A1
    DIRECTION INPUT ;
    USE SIGNAL ;
    PORT
      LAYER MT1 ;
        RECT 8.5 0.5 11.5 3.5 ;
    END
  END A1
  PIN A2
    DIRECTION INPUT ;
    USE SIGNAL ;
    PORT
      LAYER MT1 ;
        RECT 0.5 0.5 3.5 3.5 ;
    END
  END A2
  PIN Y
    DIRECTION INPUT ;
    USE SIGNAL ;
    PORT
      LAYER MT1 ;
        RECT 8.5 8.5 11.5 11.5 ;
    END
  END Y
  OBS
    LAYER VIA1 ;
      RECT 9.3 1.25 10.8 2.75 ;
      RECT 9.25 9.25 10.75 10.75 ;
      RECT 1.25 1.25 2.75 2.75 ;
    LAYER GATE ;
      RECT 9.45 0.75 10.3 5.35 ;
      RECT 8.8 0.75 11.3 3.25 ;
      RECT 0.75 0.75 3.25 3.25 ;
      RECT 0.75 1.3 5.7 2.3 ;
      RECT 0.75 1.375 7.8 2.225 ;
      RECT 8.75 8.75 11.25 11.25 ;
    LAYER CONT ;
      RECT 9.5 9.5 10.5 10.5 ;
    LAYER SD ;
      RECT 8.75 8.75 11.55 11.25 ;
      RECT 10.55 3.5 11.55 11.25 ;
      RECT 9.95 5.95 11.55 11.25 ;
      RECT 10.175 3.5 11.55 5.1 ;
      RECT 8.575 3.5 9.575 5.1 ;
      RECT 6.825 3.6 9.575 4.6 ;
      RECT 6.5 2.1 7.55 4.55 ;
      RECT 5.95 2.1 7.55 3.1 ;
  END
END NAND2_X1RL_T5

MACRO NAND2_X2RL_T5
  CLASS CORE ;
  ORIGIN 0 0 ;
  FOREIGN NAND2_X2RL_T5 0 0 ;
  SIZE 12 BY 20 ;
  SYMMETRY X Y ;
  SITE CoreSite_T5 ;
  PIN VDD
    DIRECTION INOUT ;
    USE POWER ;
    PORT
      LAYER SD ;
        RECT 0 19.5 12 20.5 ;
        RECT 2.05 18.5 3.65 20.5 ;
    END
  END VDD
  PIN VSS
    DIRECTION INOUT ;
    USE GROUND ;
    PORT
      LAYER SD ;
        RECT 0 -0.5 12 0.5 ;
        RECT 2.375 3.5 4.5 4.5 ;
        RECT 3.5 -0.5 4.5 4.5 ;
        RECT 2.375 3.5 3.375 5.1 ;
    END
  END VSS
  PIN A1
    DIRECTION INPUT ;
    USE SIGNAL ;
    PORT
      LAYER MT1 ;
        RECT 4.5 0.5 7.5 3.5 ;
    END
  END A1
  PIN A2
    DIRECTION INPUT ;
    USE SIGNAL ;
    PORT
      LAYER MT1 ;
        RECT 0.5 0.5 3.5 3.5 ;
    END
  END A2
  PIN Y
    DIRECTION INPUT ;
    USE SIGNAL ;
    PORT
      LAYER MT1 ;
        RECT 8.5 4.5 11.5 7.5 ;
    END
  END Y
  OBS
    LAYER VIA1 ;
      RECT 9.25 5.25 10.75 6.75 ;
      RECT 5.25 1.25 6.75 2.75 ;
      RECT 1.25 1.25 2.75 2.75 ;
    LAYER GATE ;
      RECT 5.575 0.75 6.425 7.3 ;
      RECT 5.5 0.75 6.5 5.2 ;
      RECT 4.75 0.75 7.25 3.25 ;
      RECT 1.65 0.75 2.5 5.35 ;
      RECT 0.75 0.75 3.25 3.25 ;
      RECT 8.75 4.75 11.25 7.25 ;
    LAYER CONT ;
      RECT 9.5 5.5 10.5 6.5 ;
    LAYER SD ;
      RECT 8.45 5.55 10.05 9 ;
      RECT 8.75 4.75 11.25 7.25 ;
      RECT 6.3 5.45 7.3 7.05 ;
      RECT 6.3 5.55 11.25 6.95 ;
      RECT 4.7 5.45 5.7 7.05 ;
      RECT 0.4 5.95 5.7 6.95 ;
      RECT 0.4 3.5 1.4 6.95 ;
      RECT 0.4 3.5 1.775 5.1 ;
  END
END NAND2_X2RL_T5

MACRO NAND2_X4RL_T5
  CLASS CORE ;
  ORIGIN 0 0 ;
  FOREIGN NAND2_X4RL_T5 0 0 ;
  SIZE 8 BY 20 ;
  SYMMETRY X Y ;
  SITE CoreSite_T5 ;
  PIN VDD
    DIRECTION INOUT ;
    USE POWER ;
    PORT
      LAYER SD ;
        RECT 0 19.5 8 20.5 ;
        RECT 6 17.9 7.5 20.5 ;
    END
  END VDD
  PIN VSS
    DIRECTION INOUT ;
    USE GROUND ;
    PORT
      LAYER SD ;
        RECT 0 -0.5 8 0.5 ;
        RECT 3.5 -0.5 6.1 1.5 ;
    END
  END VSS
  PIN A1
    DIRECTION INPUT ;
    USE SIGNAL ;
    PORT
      LAYER MT1 ;
        RECT 0.5 4.5 3.5 7.5 ;
    END
  END A1
  PIN A2
    DIRECTION INPUT ;
    USE SIGNAL ;
    PORT
      LAYER MT1 ;
        RECT 0.5 0.5 3.5 3.5 ;
    END
  END A2
  PIN Y
    DIRECTION INPUT ;
    USE SIGNAL ;
    PORT
      LAYER MT1 ;
        RECT 4.5 8.5 7.5 11.5 ;
    END
  END Y
  OBS
    LAYER VIA1 ;
      RECT 5.25 9.25 6.75 10.75 ;
      RECT 1.25 1.25 2.75 2.75 ;
      RECT 1.25 5.25 2.75 6.75 ;
    LAYER GATE ;
      RECT 0.75 0.75 3.25 3.25 ;
      RECT 0.75 1.375 6.35 2.225 ;
      RECT 0.75 4.75 3.25 7.25 ;
      RECT 0.75 5.525 6.35 6.375 ;
      RECT 4.75 8.75 7.25 11.25 ;
    LAYER CONT ;
      RECT 5.5 9.5 6.5 10.5 ;
    LAYER SD ;
      RECT 1.25 9.8 3 13.1 ;
      RECT 1.25 9.8 7.25 11.25 ;
      RECT 4.5 8.75 7.25 11.25 ;
      RECT 4.5 6.25 5.95 11.25 ;
      RECT 3.5 6.25 6.1 7.25 ;
      RECT 3.5 4.65 6.1 5.65 ;
      RECT 3.6 2.1 6 5.65 ;
      RECT 3.5 2.1 6.1 3.1 ;
  END
END NAND2_X4RL_T5

MACRO NAND3_X1RL_T5
  CLASS CORE ;
  ORIGIN 0 0 ;
  FOREIGN NAND3_X1RL_T5 0 0 ;
  SIZE 16 BY 20 ;
  SYMMETRY X Y ;
  SITE CoreSite_T5 ;
  PIN VDD
    DIRECTION INOUT ;
    USE POWER ;
    PORT
      LAYER SD ;
        RECT 0 19.5 16 20.5 ;
        RECT 0.5 17.9 2 20.5 ;
    END
  END VDD
  PIN VSS
    DIRECTION INOUT ;
    USE GROUND ;
    PORT
      LAYER SD ;
        RECT 0 -0.5 16 0.5 ;
        RECT 10.3 3.5 12.7 4.5 ;
        RECT 11.7 -0.5 12.7 4.5 ;
        RECT 10.3 3.5 11.3 5.1 ;
    END
  END VSS
  PIN A1
    DIRECTION INPUT ;
    USE SIGNAL ;
    PORT
      LAYER MT1 ;
        RECT 0.5 0.5 3.5 3.5 ;
    END
  END A1
  PIN A2
    DIRECTION INPUT ;
    USE SIGNAL ;
    PORT
      LAYER MT1 ;
        RECT 4.5 0.5 7.5 3.5 ;
    END
  END A2
  PIN A3
    DIRECTION INPUT ;
    USE SIGNAL ;
    PORT
      LAYER MT1 ;
        RECT 8.5 0.5 11.5 3.5 ;
    END
  END A3
  PIN Y
    DIRECTION INPUT ;
    USE SIGNAL ;
    PORT
      LAYER MT1 ;
        RECT 12.5 8.5 15.5 11.5 ;
    END
  END Y
  OBS
    LAYER VIA1 ;
      RECT 13.25 9.25 14.75 10.75 ;
      RECT 9.25 1.25 10.75 2.75 ;
      RECT 5.25 1.25 6.75 2.75 ;
      RECT 1.25 1.25 2.75 2.75 ;
    LAYER GATE ;
      RECT 9.575 0.75 10.425 5.35 ;
      RECT 8.75 0.75 11.25 3.25 ;
      RECT 5.575 0.75 6.425 5.35 ;
      RECT 4.75 0.75 7.25 3.25 ;
      RECT 1.675 0.75 2.525 5.35 ;
      RECT 0.75 0.75 3.25 3.25 ;
      RECT 12.75 8.75 15.25 11.25 ;
    LAYER CONT ;
      RECT 13.5 9.5 14.5 10.5 ;
    LAYER SD ;
      RECT 12.75 8.75 15.25 11.25 ;
      RECT 11.2 8.3 12.75 9.9 ;
      RECT 11.2 5.95 12.2 9.9 ;
      RECT 0.425 5.95 12.2 6.95 ;
      RECT 0.425 3.5 1.425 6.95 ;
      RECT 0.425 3.5 1.8 5.1 ;
      RECT 8.7 3.5 9.7 5.1 ;
      RECT 6.3 3.5 7.3 5.1 ;
      RECT 6.3 3.6 9.7 5 ;
      RECT 4.7 3.5 5.7 5.1 ;
      RECT 2.4 3.5 3.4 5.1 ;
      RECT 2.4 3.6 5.7 5 ;
  END
END NAND3_X1RL_T5

MACRO NAND3_X2RL_T5
  CLASS CORE ;
  ORIGIN 0 0 ;
  FOREIGN NAND3_X2RL_T5 0 0 ;
  SIZE 12 BY 20 ;
  SYMMETRY X Y ;
  SITE CoreSite_T5 ;
  PIN VDD
    DIRECTION INOUT ;
    USE POWER ;
    PORT
      LAYER SD ;
        RECT 0 19.5 12 20.5 ;
        RECT 0.5 18.35 2.1 20.5 ;
    END
  END VDD
  PIN VSS
    DIRECTION INOUT ;
    USE GROUND ;
    PORT
      LAYER SD ;
        RECT 0 -0.5 12 0.5 ;
        RECT 6.3 3.5 8.5 4.5 ;
        RECT 7.5 -0.5 8.5 4.5 ;
        RECT 6.3 3.5 7.3 5.1 ;
    END
  END VSS
  PIN A1
    DIRECTION INPUT ;
    USE SIGNAL ;
    PORT
      LAYER MT1 ;
        RECT 8.5 0.5 11.5 3.5 ;
    END
  END A1
  PIN A2
    DIRECTION INPUT ;
    USE SIGNAL ;
    PORT
      LAYER MT1 ;
        RECT 0.5 0.5 3.5 3.5 ;
    END
  END A2
  PIN A3
    DIRECTION INPUT ;
    USE SIGNAL ;
    PORT
      LAYER MT1 ;
        RECT 4.5 0.5 7.5 3.5 ;
    END
  END A3
  PIN Y
    DIRECTION INPUT ;
    USE SIGNAL ;
    PORT
      LAYER MT1 ;
        RECT 8.5 8.5 11.5 11.5 ;
    END
  END Y
  OBS
    LAYER VIA1 ;
      RECT 9.25 1.25 10.75 2.75 ;
      RECT 9.25 9.25 10.75 10.75 ;
      RECT 5.25 1.25 6.75 2.75 ;
      RECT 1.25 1.25 2.75 2.75 ;
    LAYER GATE ;
      RECT 9.075 0.75 9.925 7.3 ;
      RECT 9 0.75 10 5.2 ;
      RECT 8.75 0.75 11.25 3.25 ;
      RECT 5.575 0.75 6.425 5.35 ;
      RECT 4.75 0.75 7.25 3.25 ;
      RECT 1.975 0.75 2.825 5.35 ;
      RECT 0.75 0.75 3.25 3.25 ;
      RECT 8.75 8.75 11.25 11.25 ;
    LAYER CONT ;
      RECT 9.5 9.5 10.5 10.5 ;
    LAYER SD ;
      RECT 8.75 8.5 11.25 11.25 ;
      RECT 10.25 5.45 11.25 11.25 ;
      RECT 6.9 8.5 11.25 10.05 ;
      RECT 9.8 5.45 11.25 7.05 ;
      RECT 8.2 5.45 9.2 7.05 ;
      RECT 0.7 5.95 9.2 6.95 ;
      RECT 0.7 3.5 1.7 6.95 ;
      RECT 0.7 3.5 2.1 5.1 ;
      RECT 4.7 3.5 5.7 5.1 ;
      RECT 2.7 3.5 3.7 5.1 ;
      RECT 2.7 3.6 5.7 5 ;
  END
END NAND3_X2RL_T5

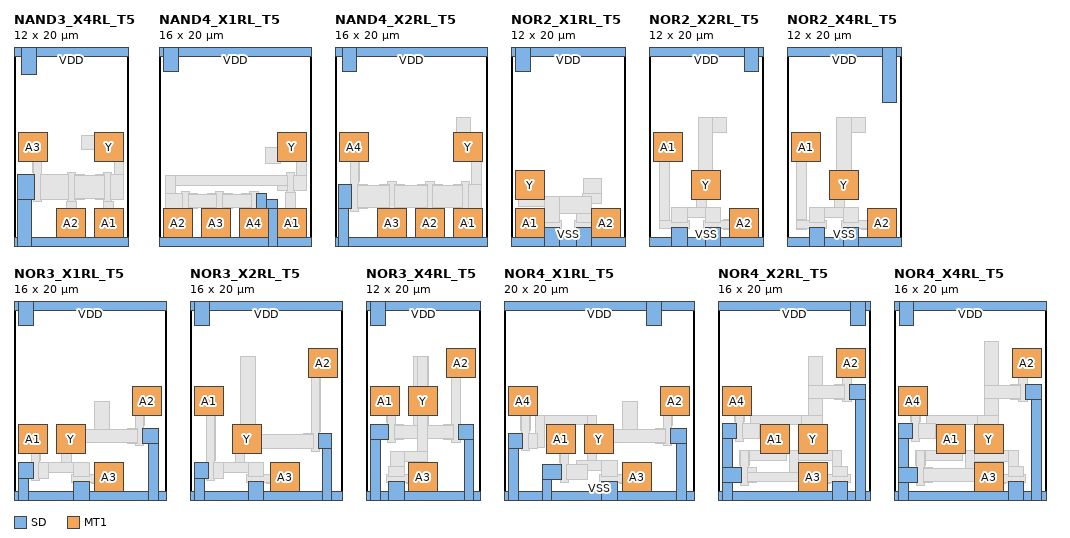
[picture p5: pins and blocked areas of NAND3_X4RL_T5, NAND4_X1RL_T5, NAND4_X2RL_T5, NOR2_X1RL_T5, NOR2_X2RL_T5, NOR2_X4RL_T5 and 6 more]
MACRO NAND3_X4RL_T5
  CLASS CORE ;
  ORIGIN 0 0 ;
  FOREIGN NAND3_X4RL_T5 0 0 ;
  SIZE 12 BY 20 ;
  SYMMETRY X Y ;
  SITE CoreSite_T5 ;
  PIN VDD
    DIRECTION INOUT ;
    USE POWER ;
    PORT
      LAYER SD ;
        RECT 0 19.5 12 20.5 ;
        RECT 0.75 17.65 2.35 20.5 ;
    END
  END VDD
  PIN VSS
    DIRECTION INOUT ;
    USE GROUND ;
    PORT
      LAYER SD ;
        RECT 0 -0.5 12 0.5 ;
        RECT 0.4 4.5 2.175 7.1 ;
        RECT 0.4 -0.5 1.8 7.1 ;
    END
  END VSS
  PIN A1
    DIRECTION INPUT ;
    USE SIGNAL ;
    PORT
      LAYER MT1 ;
        RECT 8.5 0.5 11.5 3.5 ;
    END
  END A1
  PIN A2
    DIRECTION INPUT ;
    USE SIGNAL ;
    PORT
      LAYER MT1 ;
        RECT 4.5 0.5 7.5 3.5 ;
    END
  END A2
  PIN A3
    DIRECTION INPUT ;
    USE SIGNAL ;
    PORT
      LAYER MT1 ;
        RECT 0.5 8.5 3.5 11.5 ;
    END
  END A3
  PIN Y
    DIRECTION INPUT ;
    USE SIGNAL ;
    PORT
      LAYER MT1 ;
        RECT 8.5 8.5 11.5 11.5 ;
    END
  END Y
  OBS
    LAYER VIA1 ;
      RECT 9.25 1.25 10.75 2.75 ;
      RECT 9.25 9.25 10.75 10.75 ;
      RECT 5.25 1.25 6.75 2.75 ;
      RECT 1.25 9.25 2.75 10.75 ;
    LAYER GATE ;
      RECT 9.45 0.75 10.3 7.35 ;
      RECT 9.425 0.75 10.425 4.25 ;
      RECT 8.75 0.75 11.25 3.25 ;
      RECT 5.65 0.75 6.5 7.35 ;
      RECT 5.575 0.75 6.575 4.25 ;
      RECT 4.75 0.75 7.25 3.25 ;
      RECT 0.75 8.75 3.25 11.25 ;
      RECT 1.9 7.35 2.9 11.25 ;
      RECT 2.05 4.25 2.9 11.25 ;
      RECT 8.75 8.75 11.25 11.25 ;
    LAYER CONT ;
      RECT 9.5 9.5 10.5 10.5 ;
    LAYER SD ;
      RECT 7.15 9.75 11.55 11.25 ;
      RECT 10.55 4.5 11.55 11.25 ;
      RECT 8.75 8.75 11.55 11.25 ;
      RECT 10.175 4.5 11.55 7.1 ;
      RECT 8.575 4.5 9.575 7.1 ;
      RECT 6.375 4.5 7.375 7.1 ;
      RECT 6.375 4.6 9.575 7 ;
      RECT 2.775 4.5 5.775 7.1 ;
  END
END NAND3_X4RL_T5

MACRO NAND4_X1RL_T5
  CLASS CORE ;
  ORIGIN 0 0 ;
  FOREIGN NAND4_X1RL_T5 0 0 ;
  SIZE 16 BY 20 ;
  SYMMETRY X Y ;
  SITE CoreSite_T5 ;
  PIN VDD
    DIRECTION INOUT ;
    USE POWER ;
    PORT
      LAYER SD ;
        RECT 0 19.5 16 20.5 ;
        RECT 0.5 17.9 2 20.5 ;
    END
  END VDD
  PIN VSS
    DIRECTION INOUT ;
    USE GROUND ;
    PORT
      LAYER SD ;
        RECT 0 -0.5 16 0.5 ;
        RECT 10.3 3.5 12.5 4.5 ;
        RECT 11.5 -0.5 12.5 4.5 ;
        RECT 10.3 3.5 11.3 5.1 ;
    END
  END VSS
  PIN A1
    DIRECTION INPUT ;
    USE SIGNAL ;
    PORT
      LAYER MT1 ;
        RECT 12.5 0.5 15.5 3.5 ;
    END
  END A1
  PIN A2
    DIRECTION INPUT ;
    USE SIGNAL ;
    PORT
      LAYER MT1 ;
        RECT 0.5 0.5 3.5 3.5 ;
    END
  END A2
  PIN A3
    DIRECTION INPUT ;
    USE SIGNAL ;
    PORT
      LAYER MT1 ;
        RECT 4.5 0.5 7.5 3.5 ;
    END
  END A3
  PIN A4
    DIRECTION INPUT ;
    USE SIGNAL ;
    PORT
      LAYER MT1 ;
        RECT 8.5 0.5 11.5 3.5 ;
    END
  END A4
  PIN Y
    DIRECTION INPUT ;
    USE SIGNAL ;
    PORT
      LAYER MT1 ;
        RECT 12.5 8.5 15.5 11.5 ;
    END
  END Y
  OBS
    LAYER VIA1 ;
      RECT 13.25 1.25 14.75 2.75 ;
      RECT 13.25 9.25 14.75 10.75 ;
      RECT 9.25 1.25 10.75 2.75 ;
      RECT 5.25 1.25 6.75 2.75 ;
      RECT 1.25 1.25 2.75 2.75 ;
    LAYER GATE ;
      RECT 13.4 0.75 14.25 7.3 ;
      RECT 13.325 0.75 14.325 5.2 ;
      RECT 12.75 0.75 15.25 3.25 ;
      RECT 9.575 0.75 10.425 5.35 ;
      RECT 8.75 0.75 11.25 3.25 ;
      RECT 5.975 0.75 6.825 5.35 ;
      RECT 4.75 0.75 7.25 3.25 ;
      RECT 2.375 0.75 3.225 5.35 ;
      RECT 0.75 0.75 3.25 3.25 ;
      RECT 12.75 8.75 15.25 11.25 ;
    LAYER CONT ;
      RECT 13.5 9.5 14.5 10.5 ;
    LAYER SD ;
      RECT 12.75 8.75 15.5 11.25 ;
      RECT 14.5 5.45 15.5 11.25 ;
      RECT 11.2 8.3 12.75 9.9 ;
      RECT 14.125 5.45 15.5 7.05 ;
      RECT 12.525 5.45 13.525 7.05 ;
      RECT 0.7 5.95 13.525 6.95 ;
      RECT 0.7 3.5 1.7 6.95 ;
      RECT 0.7 3.5 2.5 5.1 ;
      RECT 8.7 3.5 9.7 5.1 ;
      RECT 6.7 3.5 7.7 5.1 ;
      RECT 6.7 3.6 9.7 5 ;
      RECT 5.1 3.5 6.1 5.1 ;
      RECT 3.1 3.5 4.1 5.1 ;
      RECT 3.1 3.6 6.1 5 ;
  END
END NAND4_X1RL_T5

MACRO NAND4_X2RL_T5
  CLASS CORE ;
  ORIGIN 0 0 ;
  FOREIGN NAND4_X2RL_T5 0 0 ;
  SIZE 16 BY 20 ;
  SYMMETRY X Y ;
  SITE CoreSite_T5 ;
  PIN VDD
    DIRECTION INOUT ;
    USE POWER ;
    PORT
      LAYER SD ;
        RECT 0 19.5 16 20.5 ;
        RECT 0.75 17.9 2.25 20.5 ;
    END
  END VDD
  PIN VSS
    DIRECTION INOUT ;
    USE GROUND ;
    PORT
      LAYER SD ;
        RECT 0 -0.5 16 0.5 ;
        RECT 0.4 3.5 1.775 6.1 ;
        RECT 0.4 -0.5 1.4 6.1 ;
    END
  END VSS
  PIN A1
    DIRECTION INPUT ;
    USE SIGNAL ;
    PORT
      LAYER MT1 ;
        RECT 12.5 0.5 15.5 3.5 ;
    END
  END A1
  PIN A2
    DIRECTION INPUT ;
    USE SIGNAL ;
    PORT
      LAYER MT1 ;
        RECT 8.5 0.5 11.5 3.5 ;
    END
  END A2
  PIN A3
    DIRECTION INPUT ;
    USE SIGNAL ;
    PORT
      LAYER MT1 ;
        RECT 4.5 0.5 7.5 3.5 ;
    END
  END A3
  PIN A4
    DIRECTION INPUT ;
    USE SIGNAL ;
    PORT
      LAYER MT1 ;
        RECT 0.5 8.5 3.5 11.5 ;
    END
  END A4
  PIN Y
    DIRECTION INPUT ;
    USE SIGNAL ;
    PORT
      LAYER MT1 ;
        RECT 12.5 8.5 15.5 11.5 ;
    END
  END Y
  OBS
    LAYER VIA1 ;
      RECT 13.25 1.25 14.75 2.75 ;
      RECT 13.25 9.25 14.75 10.75 ;
      RECT 9.25 1.25 10.75 2.75 ;
      RECT 5.25 1.25 6.75 2.75 ;
      RECT 1.25 9.25 2.75 10.75 ;
    LAYER GATE ;
      RECT 13.3 0.75 14.15 6.35 ;
      RECT 12.75 0.75 15.25 3.25 ;
      RECT 9.575 0.75 10.425 6.35 ;
      RECT 8.75 0.75 11.25 3.25 ;
      RECT 5.575 0.75 6.425 6.35 ;
      RECT 4.75 0.75 7.25 3.25 ;
      RECT 0.75 8.75 3.25 11.25 ;
      RECT 1.6 6.35 2.6 11.25 ;
      RECT 1.65 3.25 2.5 11.25 ;
      RECT 12.75 8.75 15.25 11.25 ;
    LAYER CONT ;
      RECT 13.5 9.5 14.5 10.5 ;
    LAYER SD ;
      RECT 12.75 8.75 14.25 13.1 ;
      RECT 12.75 8.75 15.4 11.5 ;
      RECT 14.4 3.5 15.4 11.5 ;
      RECT 14.025 3.5 15.4 6.1 ;
      RECT 12.425 3.5 13.425 6.1 ;
      RECT 10.3 3.5 11.3 6.1 ;
      RECT 10.3 3.6 13.425 6 ;
      RECT 8.7 3.5 9.7 6.1 ;
      RECT 6.3 3.5 7.3 6.1 ;
      RECT 6.3 3.6 9.7 6 ;
      RECT 4.7 3.5 5.7 6.1 ;
      RECT 2.375 3.5 3.375 6.1 ;
      RECT 2.375 3.6 5.7 6 ;
  END
END NAND4_X2RL_T5

MACRO NOR2_X1RL_T5
  CLASS CORE ;
  ORIGIN 0 0 ;
  FOREIGN NOR2_X1RL_T5 0 0 ;
  SIZE 12 BY 20 ;
  SYMMETRY X Y ;
  SITE CoreSite_T5 ;
  PIN VDD
    DIRECTION INOUT ;
    USE POWER ;
    PORT
      LAYER SD ;
        RECT 0 19.5 12 20.5 ;
        RECT 0.5 17.9 2.1 20.5 ;
    END
  END VDD
  PIN VSS
    DIRECTION INOUT ;
    USE GROUND ;
    PORT
      LAYER SD ;
        RECT 0 -0.5 12 0.5 ;
        RECT 6.9 -0.5 8.5 1.5 ;
        RECT 3.5 -0.5 5.1 1.5 ;
    END
  END VSS
  PIN A1
    DIRECTION INPUT ;
    USE SIGNAL ;
    PORT
      LAYER MT1 ;
        RECT 0.5 0.5 3.5 3.5 ;
    END
  END A1
  PIN A2
    DIRECTION INPUT ;
    USE SIGNAL ;
    PORT
      LAYER MT1 ;
        RECT 8.5 0.5 11.5 3.5 ;
    END
  END A2
  PIN Y
    DIRECTION INPUT ;
    USE SIGNAL ;
    PORT
      LAYER MT1 ;
        RECT 0.5 4.5 3.5 7.5 ;
    END
  END Y
  OBS
    LAYER VIA1 ;
      RECT 9.25 1.25 10.75 2.75 ;
      RECT 1.25 1.25 2.75 2.75 ;
      RECT 1.25 5.25 2.75 6.75 ;
    LAYER GATE ;
      RECT 8.75 0.75 11.25 3.25 ;
      RECT 6.65 1.375 11.25 2.225 ;
      RECT 0.75 0.75 3.25 3.25 ;
      RECT 0.75 1.375 5.35 2.225 ;
      RECT 0.75 4.75 3.25 7.25 ;
    LAYER CONT ;
      RECT 1.5 5.5 2.5 6.5 ;
    LAYER SD ;
      RECT 0.75 3.75 3.25 7.25 ;
      RECT 7.6 4.1 9.55 6.7 ;
      RECT 7.5 4.1 9.55 5.1 ;
      RECT 6.9 2.1 8.5 4.75 ;
      RECT 0.75 3.75 8.5 4.75 ;
      RECT 3.5 3 8.5 4.75 ;
      RECT 3.5 2.1 5.1 4.75 ;
  END
END NOR2_X1RL_T5

MACRO NOR2_X2RL_T5
  CLASS CORE ;
  ORIGIN 0 0 ;
  FOREIGN NOR2_X2RL_T5 0 0 ;
  SIZE 12 BY 20 ;
  SYMMETRY X Y ;
  SITE CoreSite_T5 ;
  PIN VDD
    DIRECTION INOUT ;
    USE POWER ;
    PORT
      LAYER SD ;
        RECT 0 19.5 12 20.5 ;
        RECT 10 17.9 11.5 20.5 ;
    END
  END VDD
  PIN VSS
    DIRECTION INOUT ;
    USE GROUND ;
    PORT
      LAYER SD ;
        RECT 0 -0.5 12 0.5 ;
        RECT 5.95 -0.5 7.55 1.5 ;
        RECT 2.4 -0.5 4 1.5 ;
    END
  END VSS
  PIN A1
    DIRECTION INPUT ;
    USE SIGNAL ;
    PORT
      LAYER MT1 ;
        RECT 0.5 8.5 3.5 11.5 ;
    END
  END A1
  PIN A2
    DIRECTION INPUT ;
    USE SIGNAL ;
    PORT
      LAYER MT1 ;
        RECT 8.5 0.5 11.5 3.5 ;
    END
  END A2
  PIN Y
    DIRECTION INPUT ;
    USE SIGNAL ;
    PORT
      LAYER MT1 ;
        RECT 4.5 4.5 7.5 7.5 ;
    END
  END Y
  OBS
    LAYER VIA1 ;
      RECT 9.25 1.25 10.75 2.75 ;
      RECT 5.25 5.25 6.75 6.75 ;
      RECT 1.25 9.25 2.75 10.75 ;
    LAYER GATE ;
      RECT 8.75 0.75 11.25 3.25 ;
      RECT 7.8 1.325 11.25 2.325 ;
      RECT 5.7 1.375 11.25 2.225 ;
      RECT 0.75 8.75 3.25 11.25 ;
      RECT 1.15 1.375 2.15 11.25 ;
      RECT 1.15 1.375 4.25 2.225 ;
      RECT 4.75 4.75 7.25 7.25 ;
    LAYER CONT ;
      RECT 5.5 5.5 6.5 6.5 ;
    LAYER SD ;
      RECT 5.2 11.5 8.2 13.1 ;
      RECT 5.2 4.75 6.7 13.1 ;
      RECT 4.75 4.75 7.25 7.25 ;
      RECT 5.05 2.6 6.05 7.25 ;
      RECT 2.4 2.6 7.55 3.6 ;
      RECT 5.95 2.1 7.55 3.6 ;
      RECT 2.4 2.1 4 3.6 ;
  END
END NOR2_X2RL_T5

MACRO NOR2_X4RL_T5
  CLASS CORE ;
  ORIGIN 0 0 ;
  FOREIGN NOR2_X4RL_T5 0 0 ;
  SIZE 12 BY 20 ;
  SYMMETRY X Y ;
  SITE CoreSite_T5 ;
  PIN VDD
    DIRECTION INOUT ;
    USE POWER ;
    PORT
      LAYER SD ;
        RECT 0 19.5 12 20.5 ;
        RECT 10 14.7 11.5 20.5 ;
    END
  END VDD
  PIN VSS
    DIRECTION INOUT ;
    USE GROUND ;
    PORT
      LAYER SD ;
        RECT 0 -0.5 12 0.5 ;
        RECT 5.95 -0.5 7.55 1.5 ;
        RECT 2.35 -0.5 3.95 1.5 ;
    END
  END VSS
  PIN A1
    DIRECTION INPUT ;
    USE SIGNAL ;
    PORT
      LAYER MT1 ;
        RECT 0.5 8.5 3.5 11.5 ;
    END
  END A1
  PIN A2
    DIRECTION INPUT ;
    USE SIGNAL ;
    PORT
      LAYER MT1 ;
        RECT 8.5 0.5 11.5 3.5 ;
    END
  END A2
  PIN Y
    DIRECTION INPUT ;
    USE SIGNAL ;
    PORT
      LAYER MT1 ;
        RECT 4.5 4.5 7.5 7.5 ;
    END
  END Y
  OBS
    LAYER VIA1 ;
      RECT 9.25 1.25 10.75 2.75 ;
      RECT 5.25 5.25 6.75 6.75 ;
      RECT 1.25 9.25 2.75 10.75 ;
    LAYER GATE ;
      RECT 8.75 0.75 11.25 3.25 ;
      RECT 7.8 1.3 11.25 2.3 ;
      RECT 5.7 1.375 11.25 2.225 ;
      RECT 0.75 8.75 3.25 11.25 ;
      RECT 1 1.325 2 11.25 ;
      RECT 1 1.325 2.1 2.325 ;
      RECT 1 1.375 4.2 2.225 ;
      RECT 4.75 4.75 7.25 7.25 ;
    LAYER CONT ;
      RECT 5.5 5.5 6.5 6.5 ;
    LAYER SD ;
      RECT 5.2 11.5 8.25 13.1 ;
      RECT 5.2 4.75 6.75 13.1 ;
      RECT 4.75 4.75 7.25 7.25 ;
      RECT 5.05 2.6 6.05 7.25 ;
      RECT 2.35 2.6 7.55 3.6 ;
      RECT 5.95 2.1 7.55 3.6 ;
      RECT 2.35 2.1 3.95 3.6 ;
  END
END NOR2_X4RL_T5

MACRO NOR3_X1RL_T5
  CLASS CORE ;
  ORIGIN 0 0 ;
  FOREIGN NOR3_X1RL_T5 0 0 ;
  SIZE 16 BY 20 ;
  SYMMETRY X Y ;
  SITE CoreSite_T5 ;
  PIN VDD
    DIRECTION INOUT ;
    USE POWER ;
    PORT
      LAYER SD ;
        RECT 0 19.5 16 20.5 ;
        RECT 0.5 17.9 2.1 20.5 ;
    END
  END VDD
  PIN VSS
    DIRECTION INOUT ;
    USE GROUND ;
    PORT
      LAYER SD ;
        RECT 0 -0.5 16 0.5 ;
        RECT 13.55 5.55 15.175 7.15 ;
        RECT 14.175 -0.5 15.175 7.15 ;
        RECT 6.3 -0.5 7.9 1.5 ;
        RECT 0.5 1.875 2 3.475 ;
        RECT 0.5 -0.5 1.5 3.475 ;
    END
  END VSS
  PIN A1
    DIRECTION INPUT ;
    USE SIGNAL ;
    PORT
      LAYER MT1 ;
        RECT 0.5 4.5 3.5 7.5 ;
    END
  END A1
  PIN A2
    DIRECTION INPUT ;
    USE SIGNAL ;
    PORT
      LAYER MT1 ;
        RECT 12.5 8.5 15.5 11.5 ;
    END
  END A2
  PIN A3
    DIRECTION INPUT ;
    USE SIGNAL ;
    PORT
      LAYER MT1 ;
        RECT 8.5 0.5 11.5 3.5 ;
    END
  END A3
  PIN Y
    DIRECTION INPUT ;
    USE SIGNAL ;
    PORT
      LAYER MT1 ;
        RECT 4.5 4.5 7.5 7.5 ;
    END
  END Y
  OBS
    LAYER VIA1 ;
      RECT 13.25 9.25 14.75 10.75 ;
      RECT 9.25 1.25 10.75 2.75 ;
      RECT 5.25 5.25 6.75 6.75 ;
      RECT 1.25 5.25 2.75 6.75 ;
    LAYER GATE ;
      RECT 12.75 8.75 15.25 11.25 ;
      RECT 12.75 7.4 13.75 11.25 ;
      RECT 12.825 5.3 13.675 11.25 ;
      RECT 8.75 0.75 11.25 3.25 ;
      RECT 8.15 1.3 11.25 2.3 ;
      RECT 6.05 1.375 11.25 2.225 ;
      RECT 0.75 4.75 3.25 7.25 ;
      RECT 1.8 3.725 2.8 7.25 ;
      RECT 1.875 1.625 2.725 7.25 ;
      RECT 4.75 4.75 7.25 7.25 ;
    LAYER CONT ;
      RECT 5.5 5.5 6.5 6.5 ;
    LAYER SD ;
      RECT 8.475 5.65 10.075 9.9 ;
      RECT 4.75 4.75 7.25 7.25 ;
      RECT 11.95 5.55 12.95 7.15 ;
      RECT 4.75 5.65 12.95 7.05 ;
      RECT 5.025 2.475 6.025 7.25 ;
      RECT 2.6 2.475 7.9 3.475 ;
      RECT 6.3 2.1 7.9 3.475 ;
      RECT 2.6 1.875 3.6 3.475 ;
  END
END NOR3_X1RL_T5

MACRO NOR3_X2RL_T5
  CLASS CORE ;
  ORIGIN 0 0 ;
  FOREIGN NOR3_X2RL_T5 0 0 ;
  SIZE 16 BY 20 ;
  SYMMETRY X Y ;
  SITE CoreSite_T5 ;
  PIN VDD
    DIRECTION INOUT ;
    USE POWER ;
    PORT
      LAYER SD ;
        RECT 0 19.5 16 20.5 ;
        RECT 0.5 17.9 2.1 20.5 ;
    END
  END VDD
  PIN VSS
    DIRECTION INOUT ;
    USE GROUND ;
    PORT
      LAYER SD ;
        RECT 0 -0.5 16 0.5 ;
        RECT 13.55 4.95 14.925 6.55 ;
        RECT 13.925 -0.5 14.925 6.55 ;
        RECT 6.15 -0.5 7.75 1.5 ;
        RECT 0.5 1.875 1.9 3.475 ;
        RECT 0.5 -0.5 1.5 3.475 ;
    END
  END VSS
  PIN A1
    DIRECTION INPUT ;
    USE SIGNAL ;
    PORT
      LAYER MT1 ;
        RECT 0.5 8.5 3.5 11.5 ;
    END
  END A1
  PIN A2
    DIRECTION INPUT ;
    USE SIGNAL ;
    PORT
      LAYER MT1 ;
        RECT 12.5 12.5 15.5 15.5 ;
    END
  END A2
  PIN A3
    DIRECTION INPUT ;
    USE SIGNAL ;
    PORT
      LAYER MT1 ;
        RECT 8.5 0.5 11.5 3.5 ;
    END
  END A3
  PIN Y
    DIRECTION INPUT ;
    USE SIGNAL ;
    PORT
      LAYER MT1 ;
        RECT 4.5 4.5 7.5 7.5 ;
    END
  END Y
  OBS
    LAYER VIA1 ;
      RECT 13.25 13.25 14.75 14.75 ;
      RECT 9.25 1.25 10.75 2.75 ;
      RECT 5.25 5.25 6.75 6.75 ;
      RECT 1.25 9.25 2.75 10.75 ;
    LAYER GATE ;
      RECT 12.75 12.75 15.25 15.25 ;
      RECT 12.775 6.8 13.775 15.25 ;
      RECT 12.825 4.7 13.675 15.25 ;
      RECT 8.75 0.75 11.25 3.25 ;
      RECT 8 1.3 11.25 2.3 ;
      RECT 5.9 1.375 11.25 2.225 ;
      RECT 0.75 8.75 3.25 11.25 ;
      RECT 1.7 3.725 2.7 11.25 ;
      RECT 1.775 1.625 2.625 11.25 ;
      RECT 4.75 4.75 7.25 7.25 ;
    LAYER CONT ;
      RECT 5.5 5.5 6.5 6.5 ;
    LAYER SD ;
      RECT 5.275 4.75 6.875 14.7 ;
      RECT 4.75 4.75 7.25 7.25 ;
      RECT 11.95 4.95 12.95 6.55 ;
      RECT 4.75 5.05 12.95 6.45 ;
      RECT 4.775 2.475 5.775 7.25 ;
      RECT 2.5 2.475 7.75 3.475 ;
      RECT 6.15 2.1 7.75 3.475 ;
      RECT 2.5 1.875 3.5 3.475 ;
  END
END NOR3_X2RL_T5

MACRO NOR3_X4RL_T5
  CLASS CORE ;
  ORIGIN 0 0 ;
  FOREIGN NOR3_X4RL_T5 0 0 ;
  SIZE 12 BY 20 ;
  SYMMETRY X Y ;
  SITE CoreSite_T5 ;
  PIN VDD
    DIRECTION INOUT ;
    USE POWER ;
    PORT
      LAYER SD ;
        RECT 0 19.5 12 20.5 ;
        RECT 0.5 17.9 2.1 20.5 ;
    END
  END VDD
  PIN VSS
    DIRECTION INOUT ;
    USE GROUND ;
    PORT
      LAYER SD ;
        RECT 0 -0.5 12 0.5 ;
        RECT 9.775 5.925 11.325 7.525 ;
        RECT 10.325 -0.5 11.325 7.525 ;
        RECT 2.4 -0.5 4 1.5 ;
        RECT 0.5 5.925 2.35 7.525 ;
        RECT 0.5 -0.5 1.5 7.525 ;
    END
  END VSS
  PIN A1
    DIRECTION INPUT ;
    USE SIGNAL ;
    PORT
      LAYER MT1 ;
        RECT 0.5 8.5 3.5 11.5 ;
    END
  END A1
  PIN A2
    DIRECTION INPUT ;
    USE SIGNAL ;
    PORT
      LAYER MT1 ;
        RECT 8.5 12.5 11.5 15.5 ;
    END
  END A2
  PIN A3
    DIRECTION INPUT ;
    USE SIGNAL ;
    PORT
      LAYER MT1 ;
        RECT 4.5 0.5 7.5 3.5 ;
    END
  END A3
  PIN Y
    DIRECTION INPUT ;
    USE SIGNAL ;
    PORT
      LAYER MT1 ;
        RECT 4.5 8.5 7.5 11.5 ;
    END
  END Y
  OBS
    LAYER VIA1 ;
      RECT 9.25 13.25 10.75 14.75 ;
      RECT 5.25 1.25 6.75 2.75 ;
      RECT 5.25 9.25 6.75 10.75 ;
      RECT 1.25 9.25 2.75 10.75 ;
    LAYER GATE ;
      RECT 8.75 12.75 11.25 15.25 ;
      RECT 8.975 7.775 9.975 15.25 ;
      RECT 9.05 5.675 9.9 15.25 ;
      RECT 4.75 0.75 7.25 3.25 ;
      RECT 4.25 1.275 7.25 2.275 ;
      RECT 2.15 1.375 7.25 2.225 ;
      RECT 0.75 8.75 3.25 11.25 ;
      RECT 2.125 7.775 3.125 11.25 ;
      RECT 2.225 5.675 3.075 11.25 ;
      RECT 4.75 8.75 7.25 11.25 ;
    LAYER CONT ;
      RECT 5.5 9.5 6.5 10.5 ;
    LAYER SD ;
      RECT 5.025 6.025 6.625 14.7 ;
      RECT 4.75 8.75 7.25 11.25 ;
      RECT 8.175 5.925 9.175 7.525 ;
      RECT 2.95 5.925 3.95 7.525 ;
      RECT 2.95 6.025 9.175 7.425 ;
      RECT 5.425 3.625 6.425 14.7 ;
      RECT 2.6 3.625 6.425 4.7 ;
      RECT 2.6 2.1 4 4.7 ;
      RECT 2.4 2.1 4 3.1 ;
  END
END NOR3_X4RL_T5

MACRO NOR4_X1RL_T5
  CLASS CORE ;
  ORIGIN 0 0 ;
  FOREIGN NOR4_X1RL_T5 0 0 ;
  SIZE 20 BY 20 ;
  SYMMETRY X Y ;
  SITE CoreSite_T5 ;
  PIN VDD
    DIRECTION INOUT ;
    USE POWER ;
    PORT
      LAYER SD ;
        RECT 0 19.5 20 20.5 ;
        RECT 14.95 17.9 16.55 20.5 ;
    END
  END VDD
  PIN VSS
    DIRECTION INOUT ;
    USE GROUND ;
    PORT
      LAYER SD ;
        RECT 0 -0.5 20 0.5 ;
        RECT 17.55 5.55 19.175 7.15 ;
        RECT 18.175 -0.5 19.175 7.15 ;
        RECT 10.3 -0.5 11.9 1.5 ;
        RECT 4.025 1.7 6.025 3.3 ;
        RECT 4.025 -0.5 5.025 3.3 ;
        RECT 0.5 5 1.975 6.6 ;
        RECT 0.5 -0.5 1.5 6.6 ;
    END
  END VSS
  PIN A1
    DIRECTION INPUT ;
    USE SIGNAL ;
    PORT
      LAYER MT1 ;
        RECT 4.5 4.5 7.5 7.5 ;
    END
  END A1
  PIN A2
    DIRECTION INPUT ;
    USE SIGNAL ;
    PORT
      LAYER MT1 ;
        RECT 16.5 8.5 19.5 11.5 ;
    END
  END A2
  PIN A3
    DIRECTION INPUT ;
    USE SIGNAL ;
    PORT
      LAYER MT1 ;
        RECT 12.5 0.5 15.5 3.5 ;
    END
  END A3
  PIN A4
    DIRECTION INPUT ;
    USE SIGNAL ;
    PORT
      LAYER MT1 ;
        RECT 0.5 8.5 3.5 11.5 ;
    END
  END A4
  PIN Y
    DIRECTION INPUT ;
    USE SIGNAL ;
    PORT
      LAYER MT1 ;
        RECT 8.5 4.5 11.5 7.5 ;
    END
  END Y
  OBS
    LAYER VIA1 ;
      RECT 17.25 9.25 18.75 10.75 ;
      RECT 13.25 1.25 14.75 2.75 ;
      RECT 9.25 5.25 10.75 6.75 ;
      RECT 5.25 5.25 6.75 6.75 ;
      RECT 1.25 9.25 2.75 10.75 ;
    LAYER GATE ;
      RECT 16.75 8.75 19.25 11.25 ;
      RECT 16.75 7.4 17.75 11.25 ;
      RECT 16.825 5.3 17.675 11.25 ;
      RECT 12.75 0.75 15.25 3.25 ;
      RECT 12.15 1.275 15.25 2.275 ;
      RECT 10.05 1.375 15.25 2.225 ;
      RECT 4.75 4.75 7.25 7.25 ;
      RECT 5.8 3.55 6.8 7.25 ;
      RECT 5.9 1.45 6.75 7.25 ;
      RECT 0.75 8.75 3.25 11.25 ;
      RECT 1.775 6.85 2.775 11.25 ;
      RECT 1.85 4.75 2.7 11.25 ;
      RECT 8.75 4.75 11.25 7.25 ;
    LAYER CONT ;
      RECT 9.5 5.5 10.5 6.5 ;
    LAYER SD ;
      RECT 12.475 5.65 14.075 9.9 ;
      RECT 3.275 7.5 9.75 8.5 ;
      RECT 8.75 2.725 9.75 8.5 ;
      RECT 3.275 5.1 4.275 8.5 ;
      RECT 8.75 4.75 11.25 7.25 ;
      RECT 15.95 5.55 16.95 7.15 ;
      RECT 8.75 5.65 16.95 7.05 ;
      RECT 2.575 5 3.575 6.6 ;
      RECT 7.625 2.725 11.9 3.725 ;
      RECT 10.3 2.1 11.9 3.725 ;
      RECT 6.625 1.7 8.75 3.3 ;
  END
END NOR4_X1RL_T5

MACRO NOR4_X2RL_T5
  CLASS CORE ;
  ORIGIN 0 0 ;
  FOREIGN NOR4_X2RL_T5 0 0 ;
  SIZE 16 BY 20 ;
  SYMMETRY X Y ;
  SITE CoreSite_T5 ;
  PIN VDD
    DIRECTION INOUT ;
    USE POWER ;
    PORT
      LAYER SD ;
        RECT 0 19.5 16 20.5 ;
        RECT 13.9 17.9 15.5 20.5 ;
    END
  END VDD
  PIN VSS
    DIRECTION INOUT ;
    USE GROUND ;
    PORT
      LAYER SD ;
        RECT 0 -0.5 16 0.5 ;
        RECT 13.875 10.15 15.5 11.75 ;
        RECT 14.5 -0.5 15.5 11.75 ;
        RECT 12.05 -0.5 13.65 1.5 ;
        RECT 0.5 1.4 2.5 3 ;
        RECT 0.5 6.025 1.975 7.625 ;
        RECT 0.5 -0.5 1.5 7.625 ;
    END
  END VSS
  PIN A1
    DIRECTION INPUT ;
    USE SIGNAL ;
    PORT
      LAYER MT1 ;
        RECT 4.5 4.5 7.5 7.5 ;
    END
  END A1
  PIN A2
    DIRECTION INPUT ;
    USE SIGNAL ;
    PORT
      LAYER MT1 ;
        RECT 12.5 12.5 15.5 15.5 ;
    END
  END A2
  PIN A3
    DIRECTION INPUT ;
    USE SIGNAL ;
    PORT
      LAYER MT1 ;
        RECT 8.5 0.5 11.5 3.5 ;
    END
  END A3
  PIN A4
    DIRECTION INPUT ;
    USE SIGNAL ;
    PORT
      LAYER MT1 ;
        RECT 0.5 8.5 3.5 11.5 ;
    END
  END A4
  PIN Y
    DIRECTION INPUT ;
    USE SIGNAL ;
    PORT
      LAYER MT1 ;
        RECT 8.5 4.5 11.5 7.5 ;
    END
  END Y
  OBS
    LAYER VIA1 ;
      RECT 13.25 13.25 14.75 14.75 ;
      RECT 9.25 1.25 10.75 2.75 ;
      RECT 9.25 5.25 10.75 6.75 ;
      RECT 5.25 5.25 6.75 6.75 ;
      RECT 1.25 9.25 2.75 10.75 ;
    LAYER GATE ;
      RECT 12.75 12.75 15.25 15.25 ;
      RECT 13.075 12 14.075 15.25 ;
      RECT 13.15 9.9 14 15.25 ;
      RECT 8.75 0.75 11.25 3.25 ;
      RECT 8.75 1.3 11.8 2.3 ;
      RECT 8.75 1.375 13.9 2.225 ;
      RECT 4.75 3.775 7.25 7.25 ;
      RECT 2.3 3.775 7.25 4.775 ;
      RECT 2.3 3.25 3.3 4.775 ;
      RECT 2.375 1.15 3.225 4.775 ;
      RECT 0.75 8.75 3.25 11.25 ;
      RECT 1.775 7.875 2.775 11.25 ;
      RECT 1.85 5.775 2.7 11.25 ;
      RECT 8.75 4.75 11.25 7.25 ;
    LAYER CONT ;
      RECT 9.5 5.5 10.5 6.5 ;
    LAYER SD ;
      RECT 9.5 3.75 11 14.7 ;
      RECT 12.275 10.15 13.275 11.75 ;
      RECT 9.5 10.25 13.275 11.65 ;
      RECT 3.4 7.5 11 8.5 ;
      RECT 8.75 3.75 11 8.5 ;
      RECT 2.575 6.025 4.4 7.625 ;
      RECT 8.75 3.75 11.25 7.25 ;
      RECT 7.5 3.75 13.05 4.75 ;
      RECT 12.05 2.1 13.05 4.75 ;
      RECT 7.5 1.5 8.5 4.75 ;
      RECT 12.05 2.1 13.65 3.1 ;
      RECT 3.1 1.4 4.1 3 ;
      RECT 3.1 1.5 8.5 2.5 ;
  END
END NOR4_X2RL_T5

MACRO NOR4_X4RL_T5
  CLASS CORE ;
  ORIGIN 0 0 ;
  FOREIGN NOR4_X4RL_T5 0 0 ;
  SIZE 16 BY 20 ;
  SYMMETRY X Y ;
  SITE CoreSite_T5 ;
  PIN VDD
    DIRECTION INOUT ;
    USE POWER ;
    PORT
      LAYER SD ;
        RECT 0 19.5 16 20.5 ;
        RECT 0.6 17.9 2.1 20.5 ;
    END
  END VDD
  PIN VSS
    DIRECTION INOUT ;
    USE GROUND ;
    PORT
      LAYER SD ;
        RECT 0 -0.5 16 0.5 ;
        RECT 13.875 10.15 15.5 11.75 ;
        RECT 14.5 -0.5 15.5 11.75 ;
        RECT 12 -0.5 13.6 1.5 ;
        RECT 0.5 1.4 2.5 3 ;
        RECT 0.5 6.025 1.975 7.625 ;
        RECT 0.5 -0.5 1.5 7.625 ;
    END
  END VSS
  PIN A1
    DIRECTION INPUT ;
    USE SIGNAL ;
    PORT
      LAYER MT1 ;
        RECT 4.5 4.5 7.5 7.5 ;
    END
  END A1
  PIN A2
    DIRECTION INPUT ;
    USE SIGNAL ;
    PORT
      LAYER MT1 ;
        RECT 12.5 12.5 15.5 15.5 ;
    END
  END A2
  PIN A3
    DIRECTION INPUT ;
    USE SIGNAL ;
    PORT
      LAYER MT1 ;
        RECT 8.5 0.5 11.5 3.5 ;
    END
  END A3
  PIN A4
    DIRECTION INPUT ;
    USE SIGNAL ;
    PORT
      LAYER MT1 ;
        RECT 0.5 8.5 3.5 11.5 ;
    END
  END A4
  PIN Y
    DIRECTION INPUT ;
    USE SIGNAL ;
    PORT
      LAYER MT1 ;
        RECT 8.5 4.5 11.5 7.5 ;
    END
  END Y
  OBS
    LAYER VIA1 ;
      RECT 13.25 13.25 14.75 14.75 ;
      RECT 9.25 1.25 10.75 2.75 ;
      RECT 9.25 5.25 10.75 6.75 ;
      RECT 5.25 5.25 6.75 6.75 ;
      RECT 1.25 9.25 2.75 10.75 ;
    LAYER GATE ;
      RECT 12.75 12.75 15.25 15.25 ;
      RECT 13.075 12 14.075 15.25 ;
      RECT 13.15 9.9 14 15.25 ;
      RECT 8.75 0.75 11.25 3.25 ;
      RECT 8.75 1.3 11.75 2.3 ;
      RECT 8.75 1.375 13.85 2.225 ;
      RECT 4.75 3.775 7.25 7.25 ;
      RECT 2.3 3.775 7.25 4.775 ;
      RECT 2.3 3.25 3.3 4.775 ;
      RECT 2.375 1.15 3.225 4.775 ;
      RECT 0.75 8.75 3.25 11.25 ;
      RECT 1.775 7.875 2.775 11.25 ;
      RECT 1.85 5.775 2.7 11.25 ;
      RECT 8.75 4.75 11.25 7.25 ;
    LAYER CONT ;
      RECT 9.5 5.5 10.5 6.5 ;
    LAYER SD ;
      RECT 9.5 3.625 11 16.3 ;
      RECT 12.275 10.15 13.275 11.75 ;
      RECT 9.5 10.25 13.275 11.65 ;
      RECT 3.4 7.5 11 8.5 ;
      RECT 8.75 3.625 11 8.5 ;
      RECT 2.575 6.025 4.4 7.625 ;
      RECT 8.75 3.625 11.25 7.25 ;
      RECT 7.5 3.625 13.1 4.75 ;
      RECT 12 2.1 13.1 4.75 ;
      RECT 7.5 1.5 8.5 4.75 ;
      RECT 12 2.1 13.6 3.1 ;
      RECT 3.1 1.4 4.1 3 ;
      RECT 3.1 1.5 8.5 2.9 ;
  END
END NOR4_X4RL_T5

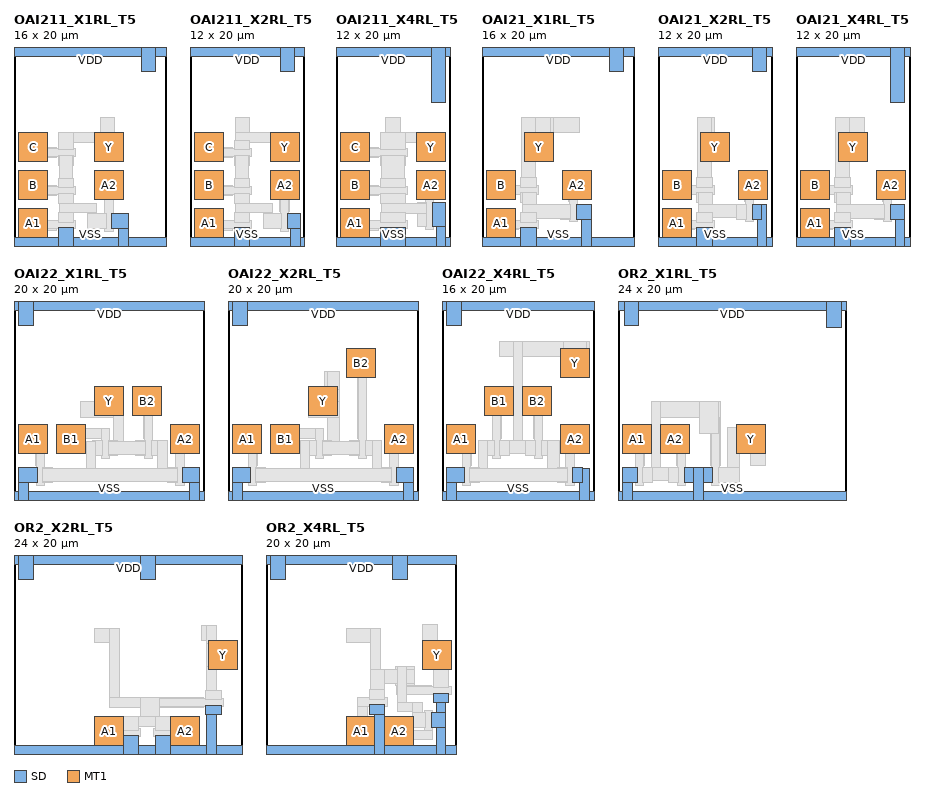
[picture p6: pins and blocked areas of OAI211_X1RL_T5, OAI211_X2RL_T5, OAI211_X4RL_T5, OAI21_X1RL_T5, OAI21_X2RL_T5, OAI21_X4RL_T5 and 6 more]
MACRO OAI211_X1RL_T5
  CLASS CORE ;
  ORIGIN 0 0 ;
  FOREIGN OAI211_X1RL_T5 0 0 ;
  SIZE 16 BY 20 ;
  SYMMETRY X Y ;
  SITE CoreSite_T5 ;
  PIN VDD
    DIRECTION INOUT ;
    USE POWER ;
    PORT
      LAYER SD ;
        RECT 0 19.5 16 20.5 ;
        RECT 13.425 17.9 14.925 20.5 ;
    END
  END VDD
  PIN VSS
    DIRECTION INOUT ;
    USE GROUND ;
    PORT
      LAYER SD ;
        RECT 0 -0.5 16 0.5 ;
        RECT 10.3 1.4 12.05 3 ;
        RECT 11.05 -0.5 12.05 3 ;
        RECT 4.675 -0.5 6.275 1.5 ;
    END
  END VSS
  PIN A1
    DIRECTION INPUT ;
    USE SIGNAL ;
    PORT
      LAYER MT1 ;
        RECT 0.5 0.5 3.5 3.5 ;
    END
  END A1
  PIN A2
    DIRECTION INPUT ;
    USE SIGNAL ;
    PORT
      LAYER MT1 ;
        RECT 8.5 4.5 11.5 7.5 ;
    END
  END A2
  PIN B
    DIRECTION INPUT ;
    USE SIGNAL ;
    PORT
      LAYER MT1 ;
        RECT 0.5 4.5 3.5 7.5 ;
    END
  END B
  PIN C
    DIRECTION INPUT ;
    USE SIGNAL ;
    PORT
      LAYER MT1 ;
        RECT 0.5 8.5 3.5 11.5 ;
    END
  END C
  PIN Y
    DIRECTION INPUT ;
    USE SIGNAL ;
    PORT
      LAYER MT1 ;
        RECT 8.5 8.5 11.5 11.5 ;
    END
  END Y
  OBS
    LAYER VIA1 ;
      RECT 9.25 5.25 10.75 6.75 ;
      RECT 9.25 9.25 10.75 10.75 ;
      RECT 1.25 1.25 2.75 2.75 ;
      RECT 1.25 5.25 2.75 6.75 ;
      RECT 1.25 9.25 2.75 10.75 ;
    LAYER GATE ;
      RECT 8.75 4.75 11.25 7.25 ;
      RECT 9.5 3.25 10.5 7.25 ;
      RECT 9.575 1.15 10.425 7.25 ;
      RECT 0.75 0.75 3.25 3.25 ;
      RECT 0.75 1.25 4.425 2.25 ;
      RECT 0.75 1.375 6.525 2.225 ;
      RECT 0.75 4.75 3.25 7.25 ;
      RECT 0.75 4.9 4.425 5.9 ;
      RECT 0.75 4.975 6.525 5.825 ;
      RECT 0.75 8.75 3.25 11.25 ;
      RECT 0.75 8.9 4.425 9.9 ;
      RECT 0.75 8.975 6.525 9.825 ;
      RECT 8.75 8.75 11.25 11.25 ;
    LAYER CONT ;
      RECT 9.5 9.5 10.5 10.5 ;
    LAYER SD ;
      RECT 9.1 8.75 10.6 13.1 ;
      RECT 4.675 10.5 10.6 11.5 ;
      RECT 8.75 8.75 11.25 11.25 ;
      RECT 4.675 9.7 6.275 11.5 ;
      RECT 4.675 4.1 6.275 5.1 ;
      RECT 7.7 1.4 8.7 4.1 ;
      RECT 4.775 3.1 8.7 4.1 ;
      RECT 4.675 2.1 6.275 3.1 ;
      RECT 7.7 1.4 9.7 3 ;
      RECT 4.675 8.1 6.275 9.1 ;
      RECT 4.775 5.7 6.175 9.1 ;
      RECT 4.675 5.7 6.275 6.7 ;
  END
END OAI211_X1RL_T5

MACRO OAI211_X2RL_T5
  CLASS CORE ;
  ORIGIN 0 0 ;
  FOREIGN OAI211_X2RL_T5 0 0 ;
  SIZE 12 BY 20 ;
  SYMMETRY X Y ;
  SITE CoreSite_T5 ;
  PIN VDD
    DIRECTION INOUT ;
    USE POWER ;
    PORT
      LAYER SD ;
        RECT 0 19.5 12 20.5 ;
        RECT 9.475 17.9 10.975 20.5 ;
    END
  END VDD
  PIN VSS
    DIRECTION INOUT ;
    USE GROUND ;
    PORT
      LAYER SD ;
        RECT 0 -0.5 12 0.5 ;
        RECT 10.225 1.4 11.6 3 ;
        RECT 10.6 -0.5 11.6 3 ;
        RECT 4.675 -0.5 6.275 1.5 ;
    END
  END VSS
  PIN A1
    DIRECTION INPUT ;
    USE SIGNAL ;
    PORT
      LAYER MT1 ;
        RECT 0.5 0.5 3.5 3.5 ;
    END
  END A1
  PIN A2
    DIRECTION INPUT ;
    USE SIGNAL ;
    PORT
      LAYER MT1 ;
        RECT 8.5 4.5 11.5 7.5 ;
    END
  END A2
  PIN B
    DIRECTION INPUT ;
    USE SIGNAL ;
    PORT
      LAYER MT1 ;
        RECT 0.5 4.5 3.5 7.5 ;
    END
  END B
  PIN C
    DIRECTION INPUT ;
    USE SIGNAL ;
    PORT
      LAYER MT1 ;
        RECT 0.5 8.5 3.5 11.5 ;
    END
  END C
  PIN Y
    DIRECTION INPUT ;
    USE SIGNAL ;
    PORT
      LAYER MT1 ;
        RECT 8.5 8.5 11.5 11.5 ;
    END
  END Y
  OBS
    LAYER VIA1 ;
      RECT 9.25 5.25 10.75 6.75 ;
      RECT 9.25 9.25 10.75 10.75 ;
      RECT 1.25 1.25 2.75 2.75 ;
      RECT 1.25 5.25 2.75 6.75 ;
      RECT 1.25 9.25 2.75 10.75 ;
    LAYER GATE ;
      RECT 8.75 4.75 11.25 7.25 ;
      RECT 9.425 3.25 10.425 7.25 ;
      RECT 9.5 1.15 10.35 7.25 ;
      RECT 0.75 0.75 3.25 3.25 ;
      RECT 0.75 1.25 4.425 2.25 ;
      RECT 0.75 1.375 6.525 2.225 ;
      RECT 0.75 4.75 3.25 7.25 ;
      RECT 0.75 4.9 4.425 5.9 ;
      RECT 0.75 4.975 6.525 5.825 ;
      RECT 0.75 8.75 3.25 11.25 ;
      RECT 0.75 8.9 4.425 9.9 ;
      RECT 0.75 8.975 6.525 9.825 ;
      RECT 8.75 8.75 11.25 11.25 ;
    LAYER CONT ;
      RECT 9.5 9.5 10.5 10.5 ;
    LAYER SD ;
      RECT 4.775 9.7 6.275 13.1 ;
      RECT 4.775 10.5 11.25 11.5 ;
      RECT 8.75 8.75 11.25 11.5 ;
      RECT 4.675 9.7 6.275 10.7 ;
      RECT 4.675 4.1 6.275 5.1 ;
      RECT 7.7 1.4 8.7 4.1 ;
      RECT 4.775 3.1 8.7 4.1 ;
      RECT 4.675 2.1 6.275 3.1 ;
      RECT 7.7 1.4 9.625 3 ;
      RECT 4.675 8.1 6.275 9.1 ;
      RECT 4.775 5.7 6.175 9.1 ;
      RECT 4.675 5.7 6.275 6.7 ;
  END
END OAI211_X2RL_T5

MACRO OAI211_X4RL_T5
  CLASS CORE ;
  ORIGIN 0 0 ;
  FOREIGN OAI211_X4RL_T5 0 0 ;
  SIZE 12 BY 20 ;
  SYMMETRY X Y ;
  SITE CoreSite_T5 ;
  PIN VDD
    DIRECTION INOUT ;
    USE POWER ;
    PORT
      LAYER SD ;
        RECT 0 19.5 12 20.5 ;
        RECT 10 14.7 11.5 20.5 ;
    END
  END VDD
  PIN VSS
    DIRECTION INOUT ;
    USE GROUND ;
    PORT
      LAYER SD ;
        RECT 0 -0.5 12 0.5 ;
        RECT 10.175 1.6 11.55 4.2 ;
        RECT 10.55 -0.5 11.55 4.2 ;
        RECT 4.675 -0.5 7.275 1.5 ;
    END
  END VSS
  PIN A1
    DIRECTION INPUT ;
    USE SIGNAL ;
    PORT
      LAYER MT1 ;
        RECT 0.5 0.5 3.5 3.5 ;
    END
  END A1
  PIN A2
    DIRECTION INPUT ;
    USE SIGNAL ;
    PORT
      LAYER MT1 ;
        RECT 8.5 4.5 11.5 7.5 ;
    END
  END A2
  PIN B
    DIRECTION INPUT ;
    USE SIGNAL ;
    PORT
      LAYER MT1 ;
        RECT 0.5 4.5 3.5 7.5 ;
    END
  END B
  PIN C
    DIRECTION INPUT ;
    USE SIGNAL ;
    PORT
      LAYER MT1 ;
        RECT 0.5 8.5 3.5 11.5 ;
    END
  END C
  PIN Y
    DIRECTION INPUT ;
    USE SIGNAL ;
    PORT
      LAYER MT1 ;
        RECT 8.5 8.5 11.5 11.5 ;
    END
  END Y
  OBS
    LAYER VIA1 ;
      RECT 9.25 5.25 10.75 6.75 ;
      RECT 9.25 9.25 10.75 10.75 ;
      RECT 1.25 1.25 2.75 2.75 ;
      RECT 1.25 5.25 2.75 6.75 ;
      RECT 1.25 9.25 2.75 10.75 ;
    LAYER GATE ;
      RECT 8.75 4.75 11.25 7.25 ;
      RECT 9.375 4.45 10.375 7.25 ;
      RECT 9.45 1.35 10.3 7.25 ;
      RECT 0.75 0.75 3.25 3.25 ;
      RECT 0.75 1.25 4.425 2.25 ;
      RECT 0.75 1.375 7.525 2.225 ;
      RECT 0.75 4.75 3.25 7.25 ;
      RECT 0.75 4.9 4.425 5.9 ;
      RECT 0.75 4.975 7.525 5.825 ;
      RECT 0.75 8.75 3.25 11.25 ;
      RECT 0.75 8.9 4.425 9.9 ;
      RECT 0.75 8.975 7.525 9.825 ;
      RECT 8.75 8.75 11.25 11.25 ;
    LAYER CONT ;
      RECT 9.5 9.5 10.5 10.5 ;
    LAYER SD ;
      RECT 5.25 9.7 6.75 13.1 ;
      RECT 4.675 10.5 10.6 11.5 ;
      RECT 8.75 8.75 11.25 11.25 ;
      RECT 4.675 9.7 7.275 11.5 ;
      RECT 4.675 4.1 7.275 5.1 ;
      RECT 8.575 1.6 9.575 4.2 ;
      RECT 4.775 3.05 9.575 4.1 ;
      RECT 4.675 2.1 7.275 3.1 ;
      RECT 4.675 8.1 7.275 9.1 ;
      RECT 4.775 5.7 7.175 9.1 ;
      RECT 4.675 5.7 7.275 6.7 ;
  END
END OAI211_X4RL_T5

MACRO OAI21_X1RL_T5
  CLASS CORE ;
  ORIGIN 0 0 ;
  FOREIGN OAI21_X1RL_T5 0 0 ;
  SIZE 16 BY 20 ;
  SYMMETRY X Y ;
  SITE CoreSite_T5 ;
  PIN VDD
    DIRECTION INOUT ;
    USE POWER ;
    PORT
      LAYER SD ;
        RECT 0 19.5 16 20.5 ;
        RECT 13.425 17.9 14.925 20.5 ;
    END
  END VDD
  PIN VSS
    DIRECTION INOUT ;
    USE GROUND ;
    PORT
      LAYER SD ;
        RECT 0 -0.5 16 0.5 ;
        RECT 9.9 2.4 11.525 4 ;
        RECT 10.525 -0.5 11.525 4 ;
        RECT 4.1 -0.5 5.7 1.5 ;
    END
  END VSS
  PIN A1
    DIRECTION INPUT ;
    USE SIGNAL ;
    PORT
      LAYER MT1 ;
        RECT 0.5 0.5 3.5 3.5 ;
    END
  END A1
  PIN A2
    DIRECTION INPUT ;
    USE SIGNAL ;
    PORT
      LAYER MT1 ;
        RECT 8.5 4.5 11.5 7.5 ;
    END
  END A2
  PIN B
    DIRECTION INPUT ;
    USE SIGNAL ;
    PORT
      LAYER MT1 ;
        RECT 0.5 4.5 3.5 7.5 ;
    END
  END B
  PIN Y
    DIRECTION INPUT ;
    USE SIGNAL ;
    PORT
      LAYER MT1 ;
        RECT 4.5 8.5 7.5 11.5 ;
    END
  END Y
  OBS
    LAYER VIA1 ;
      RECT 9.25 5.25 10.75 6.75 ;
      RECT 5.25 9.25 6.75 10.75 ;
      RECT 1.25 1.25 2.75 2.75 ;
      RECT 1.25 5.25 2.75 6.75 ;
    LAYER GATE ;
      RECT 8.75 4.75 11.25 7.25 ;
      RECT 9.1 4.25 10.1 7.25 ;
      RECT 9.175 2.15 10.025 7.25 ;
      RECT 0.75 0.75 3.25 3.25 ;
      RECT 0.75 1.3 3.85 2.3 ;
      RECT 0.75 1.375 5.95 2.225 ;
      RECT 0.75 4.75 3.25 7.25 ;
      RECT 0.75 4.975 3.85 5.975 ;
      RECT 0.75 5.05 5.95 5.9 ;
      RECT 4.75 8.75 7.25 11.25 ;
    LAYER CONT ;
      RECT 5.5 9.5 6.5 10.5 ;
    LAYER SD ;
      RECT 4.2 11.5 10.3 13.1 ;
      RECT 4.2 9.9 7.5 13.1 ;
      RECT 4.2 8.75 7.25 13.1 ;
      RECT 4.2 5.775 5.6 13.1 ;
      RECT 4.1 5.775 5.7 6.775 ;
      RECT 4.1 4.175 5.7 5.175 ;
      RECT 4.3 2.1 5.7 5.175 ;
      RECT 8.3 2.4 9.3 4 ;
      RECT 4.3 2.5 9.3 3.9 ;
      RECT 4.1 2.1 5.7 3.1 ;
  END
END OAI21_X1RL_T5

MACRO OAI21_X2RL_T5
  CLASS CORE ;
  ORIGIN 0 0 ;
  FOREIGN OAI21_X2RL_T5 0 0 ;
  SIZE 12 BY 20 ;
  SYMMETRY X Y ;
  SITE CoreSite_T5 ;
  PIN VDD
    DIRECTION INOUT ;
    USE POWER ;
    PORT
      LAYER SD ;
        RECT 0 19.5 12 20.5 ;
        RECT 9.95 17.9 11.45 20.5 ;
    END
  END VDD
  PIN VSS
    DIRECTION INOUT ;
    USE GROUND ;
    PORT
      LAYER SD ;
        RECT 0 -0.5 12 0.5 ;
        RECT 10.45 -0.5 11.45 3.9 ;
        RECT 9.9 2.4 10.9 4 ;
        RECT 4.1 -0.5 5.7 1.5 ;
    END
  END VSS
  PIN A1
    DIRECTION INPUT ;
    USE SIGNAL ;
    PORT
      LAYER MT1 ;
        RECT 0.5 0.5 3.5 3.5 ;
    END
  END A1
  PIN A2
    DIRECTION INPUT ;
    USE SIGNAL ;
    PORT
      LAYER MT1 ;
        RECT 8.5 4.5 11.5 7.5 ;
    END
  END A2
  PIN B
    DIRECTION INPUT ;
    USE SIGNAL ;
    PORT
      LAYER MT1 ;
        RECT 0.5 4.5 3.5 7.5 ;
    END
  END B
  PIN Y
    DIRECTION INPUT ;
    USE SIGNAL ;
    PORT
      LAYER MT1 ;
        RECT 4.5 8.5 7.5 11.5 ;
    END
  END Y
  OBS
    LAYER VIA1 ;
      RECT 9.25 5.25 10.75 6.75 ;
      RECT 5.25 9.25 6.75 10.75 ;
      RECT 1.25 1.25 2.75 2.75 ;
      RECT 1.25 5.25 2.75 6.75 ;
    LAYER GATE ;
      RECT 8.75 4.75 11.25 7.25 ;
      RECT 9.1 4.25 10.1 7.25 ;
      RECT 9.175 2.15 10.025 7.25 ;
      RECT 0.75 0.75 3.25 3.25 ;
      RECT 0.75 1.3 3.85 2.3 ;
      RECT 0.75 1.375 5.95 2.225 ;
      RECT 0.75 4.75 3.25 7.25 ;
      RECT 0.75 4.975 3.85 5.975 ;
      RECT 0.75 5.05 5.95 5.9 ;
      RECT 4.75 8.75 7.25 11.25 ;
    LAYER CONT ;
      RECT 5.5 9.5 6.5 10.5 ;
    LAYER SD ;
      RECT 4.1 4.175 5.7 5.175 ;
      RECT 4.3 2.1 5.7 5.175 ;
      RECT 4.3 2.6 9.3 4 ;
      RECT 8.3 2.4 9.3 4 ;
      RECT 4.1 2.1 5.7 3.1 ;
      RECT 4.2 8.75 5.95 13.1 ;
      RECT 4.2 8.75 7.25 11.25 ;
      RECT 4.2 5.775 5.6 13.1 ;
      RECT 4.1 5.775 5.7 6.775 ;
  END
END OAI21_X2RL_T5

MACRO OAI21_X4RL_T5
  CLASS CORE ;
  ORIGIN 0 0 ;
  FOREIGN OAI21_X4RL_T5 0 0 ;
  SIZE 12 BY 20 ;
  SYMMETRY X Y ;
  SITE CoreSite_T5 ;
  PIN VDD
    DIRECTION INOUT ;
    USE POWER ;
    PORT
      LAYER SD ;
        RECT 0 19.5 12 20.5 ;
        RECT 9.95 14.7 11.45 20.5 ;
    END
  END VDD
  PIN VSS
    DIRECTION INOUT ;
    USE GROUND ;
    PORT
      LAYER SD ;
        RECT 0 -0.5 12 0.5 ;
        RECT 9.9 2.4 11.45 4 ;
        RECT 10.45 -0.5 11.45 4 ;
        RECT 4.1 -0.5 5.7 1.5 ;
    END
  END VSS
  PIN A1
    DIRECTION INPUT ;
    USE SIGNAL ;
    PORT
      LAYER MT1 ;
        RECT 0.5 0.5 3.5 3.5 ;
    END
  END A1
  PIN A2
    DIRECTION INPUT ;
    USE SIGNAL ;
    PORT
      LAYER MT1 ;
        RECT 8.5 4.5 11.5 7.5 ;
    END
  END A2
  PIN B
    DIRECTION INPUT ;
    USE SIGNAL ;
    PORT
      LAYER MT1 ;
        RECT 0.5 4.5 3.5 7.5 ;
    END
  END B
  PIN Y
    DIRECTION INPUT ;
    USE SIGNAL ;
    PORT
      LAYER MT1 ;
        RECT 4.5 8.5 7.5 11.5 ;
    END
  END Y
  OBS
    LAYER VIA1 ;
      RECT 9.25 5.25 10.75 6.75 ;
      RECT 5.25 9.25 6.75 10.75 ;
      RECT 1.25 1.25 2.75 2.75 ;
      RECT 1.25 5.25 2.75 6.75 ;
    LAYER GATE ;
      RECT 8.75 4.75 11.25 7.25 ;
      RECT 9.1 4.25 10.1 7.25 ;
      RECT 9.175 2.15 10.025 7.25 ;
      RECT 0.75 0.75 3.25 3.25 ;
      RECT 0.75 1.3 3.85 2.3 ;
      RECT 0.75 1.375 5.95 2.225 ;
      RECT 0.75 4.75 3.25 7.25 ;
      RECT 0.75 4.975 3.85 5.975 ;
      RECT 0.75 5.05 5.95 5.9 ;
      RECT 4.75 8.75 7.25 11.25 ;
    LAYER CONT ;
      RECT 5.5 9.5 6.5 10.5 ;
    LAYER SD ;
      RECT 4.1 4.175 5.7 5.175 ;
      RECT 4.3 2.1 5.7 5.175 ;
      RECT 8.3 2.4 9.3 4 ;
      RECT 4.3 2.5 9.3 3.9 ;
      RECT 4.1 2.1 5.7 3.1 ;
      RECT 4.2 8.75 7.25 13.1 ;
      RECT 4.2 5.775 5.6 13.1 ;
      RECT 4.1 5.775 5.7 6.775 ;
  END
END OAI21_X4RL_T5

MACRO OAI22_X1RL_T5
  CLASS CORE ;
  ORIGIN 0 0 ;
  FOREIGN OAI22_X1RL_T5 0 0 ;
  SIZE 20 BY 20 ;
  SYMMETRY X Y ;
  SITE CoreSite_T5 ;
  PIN VDD
    DIRECTION INOUT ;
    USE POWER ;
    PORT
      LAYER SD ;
        RECT 0 19.5 20 20.5 ;
        RECT 0.5 17.9 2 20.5 ;
    END
  END VDD
  PIN VSS
    DIRECTION INOUT ;
    USE GROUND ;
    PORT
      LAYER SD ;
        RECT 0 -0.5 20 0.5 ;
        RECT 17.775 1.4 19.5 3 ;
        RECT 18.5 -0.5 19.5 3 ;
        RECT 0.5 1.4 2.45 3 ;
        RECT 0.5 -0.5 1.5 3 ;
    END
  END VSS
  PIN A1
    DIRECTION INPUT ;
    USE SIGNAL ;
    PORT
      LAYER MT1 ;
        RECT 0.5 4.5 3.5 7.5 ;
    END
  END A1
  PIN A2
    DIRECTION INPUT ;
    USE SIGNAL ;
    PORT
      LAYER MT1 ;
        RECT 16.5 4.5 19.5 7.5 ;
    END
  END A2
  PIN B1
    DIRECTION INPUT ;
    USE SIGNAL ;
    PORT
      LAYER MT1 ;
        RECT 4.5 4.5 7.5 7.5 ;
    END
  END B1
  PIN B2
    DIRECTION INPUT ;
    USE SIGNAL ;
    PORT
      LAYER MT1 ;
        RECT 12.5 8.5 15.5 11.5 ;
    END
  END B2
  PIN Y
    DIRECTION INPUT ;
    USE SIGNAL ;
    PORT
      LAYER MT1 ;
        RECT 8.5 8.5 11.5 11.5 ;
    END
  END Y
  OBS
    LAYER VIA1 ;
      RECT 17.25 5.25 18.75 6.75 ;
      RECT 13.25 9.25 14.75 10.75 ;
      RECT 9.25 9.25 10.75 10.75 ;
      RECT 5.25 5.25 6.75 6.75 ;
      RECT 1.25 5.25 2.75 6.75 ;
    LAYER GATE ;
      RECT 16.75 4.75 19.25 7.25 ;
      RECT 16.975 3.25 17.975 7.25 ;
      RECT 17.05 1.15 17.9 7.25 ;
      RECT 12.75 8.75 15.25 11.25 ;
      RECT 13.625 6.075 14.625 11.25 ;
      RECT 13.7 3.975 14.55 11.25 ;
      RECT 4.75 4.75 7.25 7.25 ;
      RECT 4.75 6.075 10.025 7.075 ;
      RECT 9.175 3.975 10.025 7.075 ;
      RECT 0.75 4.75 3.25 7.25 ;
      RECT 2.25 3.25 3.25 7.25 ;
      RECT 2.325 1.15 3.175 7.25 ;
      RECT 8.75 8.75 11.25 11.25 ;
    LAYER CONT ;
      RECT 9.5 9.5 10.5 10.5 ;
    LAYER SD ;
      RECT 14.425 4.225 16.175 5.825 ;
      RECT 8.3 4.225 9.3 5.825 ;
      RECT 7.625 1.5 8.625 5.725 ;
      RECT 15.15 1.5 16.175 5.825 ;
      RECT 16.175 1.4 17.175 3 ;
      RECT 3.05 1.4 4.05 3 ;
      RECT 3.05 1.5 17.175 2.9 ;
      RECT 8.75 8.3 11.25 11.25 ;
      RECT 7 8.3 11.5 9.9 ;
      RECT 10.5 4.325 11.5 9.9 ;
      RECT 12.825 4.225 13.825 5.825 ;
      RECT 9.9 4.225 10.9 5.825 ;
      RECT 9.9 4.325 13.825 5.725 ;
  END
END OAI22_X1RL_T5

MACRO OAI22_X2RL_T5
  CLASS CORE ;
  ORIGIN 0 0 ;
  FOREIGN OAI22_X2RL_T5 0 0 ;
  SIZE 20 BY 20 ;
  SYMMETRY X Y ;
  SITE CoreSite_T5 ;
  PIN VDD
    DIRECTION INOUT ;
    USE POWER ;
    PORT
      LAYER SD ;
        RECT 0 19.5 20 20.5 ;
        RECT 0.5 17.9 2 20.5 ;
    END
  END VDD
  PIN VSS
    DIRECTION INOUT ;
    USE GROUND ;
    PORT
      LAYER SD ;
        RECT 0 -0.5 20 0.5 ;
        RECT 17.775 1.4 19.5 3 ;
        RECT 18.5 -0.5 19.5 3 ;
        RECT 0.5 1.4 2.325 3 ;
        RECT 0.5 -0.5 1.5 3 ;
    END
  END VSS
  PIN A1
    DIRECTION INPUT ;
    USE SIGNAL ;
    PORT
      LAYER MT1 ;
        RECT 0.5 4.5 3.5 7.5 ;
    END
  END A1
  PIN A2
    DIRECTION INPUT ;
    USE SIGNAL ;
    PORT
      LAYER MT1 ;
        RECT 16.5 4.5 19.5 7.5 ;
    END
  END A2
  PIN B1
    DIRECTION INPUT ;
    USE SIGNAL ;
    PORT
      LAYER MT1 ;
        RECT 4.5 4.5 7.5 7.5 ;
    END
  END B1
  PIN B2
    DIRECTION INPUT ;
    USE SIGNAL ;
    PORT
      LAYER MT1 ;
        RECT 12.5 12.5 15.5 15.5 ;
    END
  END B2
  PIN Y
    DIRECTION INPUT ;
    USE SIGNAL ;
    PORT
      LAYER MT1 ;
        RECT 8.5 8.5 11.5 11.5 ;
    END
  END Y
  OBS
    LAYER VIA1 ;
      RECT 17.25 5.25 18.75 6.75 ;
      RECT 13.25 13.25 14.75 14.75 ;
      RECT 9.25 9.25 10.75 10.75 ;
      RECT 5.25 5.25 6.75 6.75 ;
      RECT 1.25 5.25 2.75 6.75 ;
    LAYER GATE ;
      RECT 16.75 4.75 19.25 7.25 ;
      RECT 16.975 3.25 17.975 7.25 ;
      RECT 17.05 1.15 17.9 7.25 ;
      RECT 12.75 12.75 15.25 15.25 ;
      RECT 13.625 6.075 14.625 15.25 ;
      RECT 13.7 3.975 14.55 15.25 ;
      RECT 4.75 4.75 7.25 7.25 ;
      RECT 4.75 6.075 10.025 7.075 ;
      RECT 9.175 3.975 10.025 7.075 ;
      RECT 0.75 4.75 3.25 7.25 ;
      RECT 2.125 3.25 3.125 7.25 ;
      RECT 2.2 1.15 3.05 7.25 ;
      RECT 8.75 8.75 11.25 11.25 ;
    LAYER CONT ;
      RECT 9.5 9.5 10.5 10.5 ;
    LAYER SD ;
      RECT 14.425 4.225 16.175 5.825 ;
      RECT 7.625 4.225 9.3 5.825 ;
      RECT 15.175 1.5 16.175 5.825 ;
      RECT 7.625 1.5 8.625 5.825 ;
      RECT 16.175 1.4 17.175 3 ;
      RECT 2.925 1.4 3.925 3 ;
      RECT 2.925 1.5 17.175 2.9 ;
      RECT 10.2 8.3 11.7 13.1 ;
      RECT 10.5 4.325 11.7 13.1 ;
      RECT 8.75 8.3 11.7 11.25 ;
      RECT 8.5 8.3 11.7 9.9 ;
      RECT 12.825 4.225 13.825 5.825 ;
      RECT 9.9 4.225 10.9 5.825 ;
      RECT 9.9 4.325 13.825 5.725 ;
  END
END OAI22_X2RL_T5

MACRO OAI22_X4RL_T5
  CLASS CORE ;
  ORIGIN 0 0 ;
  FOREIGN OAI22_X4RL_T5 0 0 ;
  SIZE 16 BY 20 ;
  SYMMETRY X Y ;
  SITE CoreSite_T5 ;
  PIN VDD
    DIRECTION INOUT ;
    USE POWER ;
    PORT
      LAYER SD ;
        RECT 0 19.5 16 20.5 ;
        RECT 0.5 17.9 2 20.5 ;
    END
  END VDD
  PIN VSS
    DIRECTION INOUT ;
    USE GROUND ;
    PORT
      LAYER SD ;
        RECT 0 -0.5 16 0.5 ;
        RECT 14.5 -0.5 15.5 2.9 ;
        RECT 13.775 1.4 14.775 3 ;
        RECT 0.5 1.4 2.325 3 ;
        RECT 0.5 -0.5 1.5 3 ;
    END
  END VSS
  PIN A1
    DIRECTION INPUT ;
    USE SIGNAL ;
    PORT
      LAYER MT1 ;
        RECT 0.5 4.5 3.5 7.5 ;
    END
  END A1
  PIN A2
    DIRECTION INPUT ;
    USE SIGNAL ;
    PORT
      LAYER MT1 ;
        RECT 12.5 4.5 15.5 7.5 ;
    END
  END A2
  PIN B1
    DIRECTION INPUT ;
    USE SIGNAL ;
    PORT
      LAYER MT1 ;
        RECT 4.5 8.5 7.5 11.5 ;
    END
  END B1
  PIN B2
    DIRECTION INPUT ;
    USE SIGNAL ;
    PORT
      LAYER MT1 ;
        RECT 8.5 8.5 11.5 11.5 ;
    END
  END B2
  PIN Y
    DIRECTION INPUT ;
    USE SIGNAL ;
    PORT
      LAYER MT1 ;
        RECT 12.5 12.5 15.5 15.5 ;
    END
  END Y
  OBS
    LAYER VIA1 ;
      RECT 13.25 5.25 14.75 6.75 ;
      RECT 13.25 13.25 14.75 14.75 ;
      RECT 9.25 9.25 10.75 10.75 ;
      RECT 5.25 9.25 6.75 10.75 ;
      RECT 1.25 5.25 2.75 6.75 ;
    LAYER GATE ;
      RECT 12.75 4.75 15.25 7.25 ;
      RECT 12.975 3.25 13.975 7.25 ;
      RECT 13.05 1.15 13.9 7.25 ;
      RECT 8.75 8.75 11.25 11.25 ;
      RECT 9.625 6.075 10.625 11.25 ;
      RECT 9.7 3.975 10.55 11.25 ;
      RECT 4.75 8.75 7.25 11.25 ;
      RECT 5.275 6.075 6.275 11.25 ;
      RECT 5.35 3.975 6.2 11.25 ;
      RECT 0.75 4.75 3.25 7.25 ;
      RECT 2.125 3.25 3.125 7.25 ;
      RECT 2.2 1.15 3.05 7.25 ;
      RECT 12.75 12.75 15.25 15.25 ;
    LAYER CONT ;
      RECT 13.5 13.5 14.5 14.5 ;
    LAYER SD ;
      RECT 6 14.7 15.5 16.3 ;
      RECT 12.75 12.75 15.25 16.3 ;
      RECT 7.5 4.425 8.5 16.3 ;
      RECT 6.075 4.425 9.825 5.825 ;
      RECT 8.825 4.225 9.825 5.825 ;
      RECT 6.075 4.225 7.075 5.825 ;
      RECT 10.425 4.225 12.325 5.825 ;
      RECT 3.8 4.225 5.475 5.825 ;
      RECT 11.15 1.5 12.325 5.825 ;
      RECT 3.8 1.5 4.8 5.825 ;
      RECT 12.175 1.4 13.175 3 ;
      RECT 2.925 1.4 3.925 3 ;
      RECT 2.925 1.5 13.175 2.9 ;
  END
END OAI22_X4RL_T5

MACRO OR2_X1RL_T5
  CLASS CORE ;
  ORIGIN 0 0 ;
  FOREIGN OR2_X1RL_T5 0 0 ;
  SIZE 24 BY 20 ;
  SYMMETRY X Y ;
  SITE CoreSite_T5 ;
  PIN VDD
    DIRECTION INOUT ;
    USE POWER ;
    PORT
      LAYER SD ;
        RECT 0 19.5 24 20.5 ;
        RECT 21.9 17.75 23.5 20.5 ;
        RECT 0.65 17.9 2.15 20.5 ;
    END
  END VDD
  PIN VSS
    DIRECTION INOUT ;
    USE GROUND ;
    PORT
      LAYER SD ;
        RECT 0 -0.5 24 0.5 ;
        RECT 6.95 1.4 9.95 3 ;
        RECT 7.95 -0.5 8.95 3 ;
        RECT 0.5 1.4 2 3 ;
        RECT 0.5 -0.5 1.5 3 ;
    END
  END VSS
  PIN A1
    DIRECTION INPUT ;
    USE SIGNAL ;
    PORT
      LAYER MT1 ;
        RECT 0.5 4.5 3.5 7.5 ;
    END
  END A1
  PIN A2
    DIRECTION INPUT ;
    USE SIGNAL ;
    PORT
      LAYER MT1 ;
        RECT 4.5 4.5 7.5 7.5 ;
    END
  END A2
  PIN Y
    DIRECTION INPUT ;
    USE SIGNAL ;
    PORT
      LAYER MT1 ;
        RECT 12.5 4.5 15.5 7.5 ;
    END
  END Y
  OBS
    LAYER VIA1 ;
      RECT 13.25 5.25 14.75 6.75 ;
      RECT 5.25 5.25 6.75 6.75 ;
      RECT 1.25 5.25 2.75 6.75 ;
    LAYER GATE ;
      RECT 8.55 6.575 10.75 8.575 ;
      RECT 9.75 3.25 10.75 8.575 ;
      RECT 9.825 1.15 10.675 8.575 ;
      RECT 4.75 4.75 7.25 7.25 ;
      RECT 6.15 3.25 7.15 7.25 ;
      RECT 6.225 1.15 7.075 7.25 ;
      RECT 0.75 4.75 3.25 7.25 ;
      RECT 1.8 3.25 2.8 7.25 ;
      RECT 1.875 1.15 2.725 7.25 ;
      RECT 12.75 4.75 15.25 7.25 ;
    LAYER CONT ;
      RECT 13.5 5.5 14.5 6.5 ;
      RECT 9.05 7.075 10.05 8.075 ;
    LAYER SD ;
      RECT 11.55 4.75 15.5 7.25 ;
      RECT 13.9 3.25 15.5 7.25 ;
      RECT 11.55 1.4 12.825 7.25 ;
      RECT 10.55 1.4 12.825 3 ;
      RECT 3.5 8.3 10.75 9.9 ;
      RECT 8.55 6.575 10.55 9.9 ;
      RECT 3.5 1.6 4.5 9.9 ;
      RECT 2.6 1.6 6.35 3 ;
      RECT 5.35 1.4 6.35 3 ;
      RECT 2.6 1.4 3.6 3 ;
  END
END OR2_X1RL_T5

MACRO OR2_X2RL_T5
  CLASS CORE ;
  ORIGIN 0 0 ;
  FOREIGN OR2_X2RL_T5 0 0 ;
  SIZE 24 BY 20 ;
  SYMMETRY X Y ;
  SITE CoreSite_T5 ;
  PIN VDD
    DIRECTION INOUT ;
    USE POWER ;
    PORT
      LAYER SD ;
        RECT 0 19.5 24 20.5 ;
        RECT 13.3 18 14.9 20.5 ;
        RECT 0.5 18 2.1 20.5 ;
    END
  END VDD
  PIN VSS
    DIRECTION INOUT ;
    USE GROUND ;
    PORT
      LAYER SD ;
        RECT 0 -0.5 24 0.5 ;
        RECT 20.2 3.7 21.8 4.7 ;
        RECT 20.3 -0.5 21.3 4.7 ;
        RECT 14.9 -0.5 16.5 1.5 ;
        RECT 11.5 -0.5 13.1 1.5 ;
    END
  END VSS
  PIN A1
    DIRECTION INPUT ;
    USE SIGNAL ;
    PORT
      LAYER MT1 ;
        RECT 8.5 0.5 11.5 3.5 ;
    END
  END A1
  PIN A2
    DIRECTION INPUT ;
    USE SIGNAL ;
    PORT
      LAYER MT1 ;
        RECT 16.5 0.5 19.5 3.5 ;
    END
  END A2
  PIN Y
    DIRECTION INPUT ;
    USE SIGNAL ;
    PORT
      LAYER MT1 ;
        RECT 20.5 8.5 23.5 11.5 ;
    END
  END Y
  OBS
    LAYER VIA1 ;
      RECT 21.25 9.25 22.75 10.75 ;
      RECT 17.25 1.25 18.75 2.75 ;
      RECT 9.25 1.25 10.75 2.75 ;
    LAYER GATE ;
      RECT 13.3 4.5 19.95 5.5 ;
      RECT 13.3 4.575 22.05 5.425 ;
      RECT 13.3 3.5 15.3 5.5 ;
      RECT 16.75 0.75 19.25 3.25 ;
      RECT 14.65 1.375 19.25 2.225 ;
      RECT 8.75 0.75 11.25 3.25 ;
      RECT 8.75 1.375 13.35 2.225 ;
      RECT 20.75 8.75 23.25 11.25 ;
    LAYER CONT ;
      RECT 21.5 9.5 22.5 10.5 ;
      RECT 13.8 4 14.8 5 ;
    LAYER SD ;
      RECT 19.7 11.55 21.3 13.1 ;
      RECT 20.3 5.3 21.3 13.1 ;
      RECT 20.3 8.75 23.25 11.25 ;
      RECT 20.2 5.3 21.8 6.3 ;
      RECT 8.5 11.3 11.1 12.8 ;
      RECT 10.1 4.5 11.1 12.8 ;
      RECT 10.1 4.5 15.3 5.5 ;
      RECT 13.3 2.5 15.3 5.5 ;
      RECT 11.5 2.5 16.5 3.5 ;
      RECT 14.9 2.1 16.5 3.5 ;
      RECT 11.5 2.1 13.1 3.5 ;
  END
END OR2_X2RL_T5

MACRO OR2_X4RL_T5
  CLASS CORE ;
  ORIGIN 0 0 ;
  FOREIGN OR2_X4RL_T5 0 0 ;
  SIZE 20 BY 20 ;
  SYMMETRY X Y ;
  SITE CoreSite_T5 ;
  PIN VDD
    DIRECTION INOUT ;
    USE POWER ;
    PORT
      LAYER SD ;
        RECT 0 19.5 20 20.5 ;
        RECT 13.3 18 14.9 20.5 ;
        RECT 0.5 18 2.1 20.5 ;
    END
  END VDD
  PIN VSS
    DIRECTION INOUT ;
    USE GROUND ;
    PORT
      LAYER SD ;
        RECT 0 -0.5 20 0.5 ;
        RECT 17.65 5 19.25 6 ;
        RECT 17.9 -0.5 18.9 6 ;
        RECT 17.425 2.35 18.9 3.95 ;
        RECT 10.9 3.75 12.5 4.75 ;
        RECT 11.45 -0.5 12.45 4.75 ;
    END
  END VSS
  PIN A1
    DIRECTION INPUT ;
    USE SIGNAL ;
    PORT
      LAYER MT1 ;
        RECT 8.5 0.5 11.5 3.5 ;
    END
  END A1
  PIN A2
    DIRECTION INPUT ;
    USE SIGNAL ;
    PORT
      LAYER MT1 ;
        RECT 12.5 0.5 15.5 3.5 ;
    END
  END A2
  PIN Y
    DIRECTION INPUT ;
    USE SIGNAL ;
    PORT
      LAYER MT1 ;
        RECT 16.5 8.5 19.5 11.5 ;
    END
  END Y
  OBS
    LAYER VIA1 ;
      RECT 17.25 9.25 18.75 10.75 ;
      RECT 13.2 1.25 14.7 2.75 ;
      RECT 9.2 1.25 10.7 2.75 ;
    LAYER GATE ;
      RECT 13.65 6.75 15.65 8.75 ;
      RECT 13.75 5.8 17.4 6.8 ;
      RECT 13.75 5.875 19.5 6.725 ;
      RECT 16.7 1.1 17.55 4.2 ;
      RECT 12.7 0.75 15.2 3.25 ;
      RECT 12.7 1.1 17.55 2.1 ;
      RECT 9.65 0.75 10.65 5.55 ;
      RECT 9.65 4.625 12.75 5.475 ;
      RECT 8.7 0.75 11.2 3.25 ;
      RECT 16.75 8.75 19.25 11.25 ;
    LAYER CONT ;
      RECT 17.5 9.5 18.5 10.5 ;
      RECT 14.15 7.25 15.15 8.25 ;
    LAYER SD ;
      RECT 16.5 8.75 18.1 13.2 ;
      RECT 17.65 6.6 19.25 11.25 ;
      RECT 8.5 11.3 12 12.8 ;
      RECT 11 5.35 12 12.8 ;
      RECT 13.65 6.75 15.65 8.75 ;
      RECT 11 6.95 15.65 8.45 ;
      RECT 11 5.35 12.5 8.45 ;
      RECT 13.8 4.05 14.8 8.75 ;
      RECT 10.9 5.35 12.5 6.35 ;
      RECT 13.8 4.05 16.45 5.05 ;
      RECT 15.45 2.35 16.45 5.05 ;
      RECT 15.45 2.35 16.825 3.95 ;
  END
END OR2_X4RL_T5

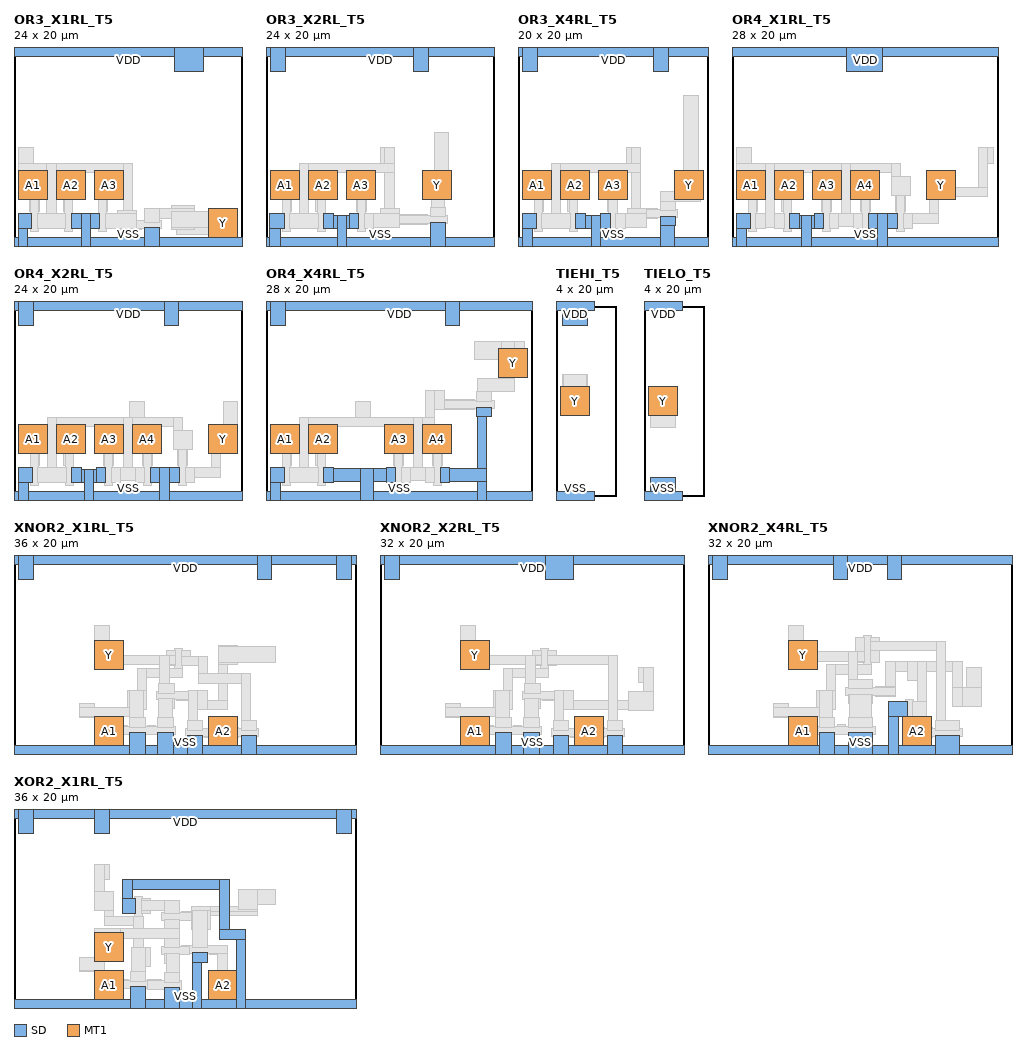
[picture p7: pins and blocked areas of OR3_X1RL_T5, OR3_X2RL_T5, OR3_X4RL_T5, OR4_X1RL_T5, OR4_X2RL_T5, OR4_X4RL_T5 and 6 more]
MACRO OR3_X1RL_T5
  CLASS CORE ;
  ORIGIN 0 0 ;
  FOREIGN OR3_X1RL_T5 0 0 ;
  SIZE 24 BY 20 ;
  SYMMETRY X Y ;
  SITE CoreSite_T5 ;
  PIN VDD
    DIRECTION INOUT ;
    USE POWER ;
    PORT
      LAYER SD ;
        RECT 0 19.5 24 20.5 ;
        RECT 16.9 17.9 19.9 20.5 ;
    END
  END VDD
  PIN VSS
    DIRECTION INOUT ;
    USE GROUND ;
    PORT
      LAYER SD ;
        RECT 0 -0.5 24 0.5 ;
        RECT 13.7 -0.5 15.3 1.5 ;
        RECT 6.05 1.4 9.05 3 ;
        RECT 7.1 -0.5 8.1 3 ;
        RECT 0.45 1.4 1.85 3 ;
        RECT 0.45 -0.5 1.45 3 ;
    END
  END VSS
  PIN A1
    DIRECTION INPUT ;
    USE SIGNAL ;
    PORT
      LAYER MT1 ;
        RECT 0.5 4.5 3.5 7.5 ;
    END
  END A1
  PIN A2
    DIRECTION INPUT ;
    USE SIGNAL ;
    PORT
      LAYER MT1 ;
        RECT 4.5 4.5 7.5 7.5 ;
    END
  END A2
  PIN A3
    DIRECTION INPUT ;
    USE SIGNAL ;
    PORT
      LAYER MT1 ;
        RECT 8.5 4.5 11.5 7.5 ;
    END
  END A3
  PIN Y
    DIRECTION INPUT ;
    USE SIGNAL ;
    PORT
      LAYER MT1 ;
        RECT 20.5 0.5 23.5 3.5 ;
    END
  END Y
  OBS
    LAYER VIA1 ;
      RECT 21.4 1.25 22.9 2.75 ;
      RECT 9.25 5.05 10.75 6.55 ;
      RECT 5.25 5.05 6.75 6.55 ;
      RECT 1.2 5.05 2.7 6.55 ;
    LAYER GATE ;
      RECT 16.55 1.3 19.05 3.8 ;
      RECT 20.9 0.75 23.4 3.25 ;
      RECT 17.1 0.75 23.4 1.75 ;
      RECT 10.9 1.3 12.9 3.3 ;
      RECT 10.9 1.3 13.45 2.3 ;
      RECT 10.9 1.375 15.55 2.225 ;
      RECT 8.75 4.55 11.25 7.05 ;
      RECT 8.85 3.25 9.85 7.05 ;
      RECT 8.925 1.15 9.775 7.05 ;
      RECT 4.75 4.55 7.25 7.05 ;
      RECT 5.2 3.25 6.2 7.05 ;
      RECT 5.325 1.15 6.175 7.05 ;
      RECT 0.7 4.55 3.2 7.05 ;
      RECT 1.65 3.25 2.65 7.05 ;
      RECT 1.725 1.15 2.575 7.05 ;
    LAYER CONT ;
      RECT 17.3 2.05 18.3 3.05 ;
      RECT 11.4 1.8 12.4 2.8 ;
    LAYER SD ;
      RECT 16.55 1.3 19.05 3.8 ;
      RECT 13.7 2.475 19.05 3.475 ;
      RECT 16.55 1.5 20.65 3.25 ;
      RECT 13.7 2.1 15.3 3.475 ;
      RECT 0.5 7.3 2 9.9 ;
      RECT 0.5 7.3 12.5 8.3 ;
      RECT 11.5 1.3 12.5 8.3 ;
      RECT 3.45 1.4 4.45 8.3 ;
      RECT 10.9 1.3 12.9 3.3 ;
      RECT 9.65 1.4 12.9 3 ;
      RECT 2.45 1.4 5.45 3 ;
  END
END OR3_X1RL_T5

MACRO OR3_X2RL_T5
  CLASS CORE ;
  ORIGIN 0 0 ;
  FOREIGN OR3_X2RL_T5 0 0 ;
  SIZE 24 BY 20 ;
  SYMMETRY X Y ;
  SITE CoreSite_T5 ;
  PIN VDD
    DIRECTION INOUT ;
    USE POWER ;
    PORT
      LAYER SD ;
        RECT 0 19.5 24 20.5 ;
        RECT 15.55 17.9 17.15 20.5 ;
        RECT 0.5 17.9 2 20.5 ;
    END
  END VDD
  PIN VSS
    DIRECTION INOUT ;
    USE GROUND ;
    PORT
      LAYER SD ;
        RECT 0 -0.5 24 0.5 ;
        RECT 17.3 -0.5 18.9 2.05 ;
        RECT 8.75 1.4 9.75 3 ;
        RECT 6.1 1.4 9.75 2.8 ;
        RECT 7.5 -0.5 8.5 2.8 ;
        RECT 6.1 1.4 7.1 3 ;
        RECT 0.4 1.4 1.9 3 ;
        RECT 0.4 -0.5 1.5 3 ;
    END
  END VSS
  PIN A1
    DIRECTION INPUT ;
    USE SIGNAL ;
    PORT
      LAYER MT1 ;
        RECT 0.5 4.5 3.5 7.5 ;
    END
  END A1
  PIN A2
    DIRECTION INPUT ;
    USE SIGNAL ;
    PORT
      LAYER MT1 ;
        RECT 4.5 4.5 7.5 7.5 ;
    END
  END A2
  PIN A3
    DIRECTION INPUT ;
    USE SIGNAL ;
    PORT
      LAYER MT1 ;
        RECT 8.5 4.5 11.5 7.5 ;
    END
  END A3
  PIN Y
    DIRECTION INPUT ;
    USE SIGNAL ;
    PORT
      LAYER MT1 ;
        RECT 16.5 4.5 19.5 7.5 ;
    END
  END Y
  OBS
    LAYER VIA1 ;
      RECT 17.25 5.25 18.75 6.75 ;
      RECT 9.25 5.05 10.75 6.55 ;
      RECT 5.25 5.05 6.75 6.55 ;
      RECT 1.25 5.25 2.75 6.75 ;
    LAYER GATE ;
      RECT 12 1.5 14 3.5 ;
      RECT 12 1.85 17.05 2.85 ;
      RECT 12 1.925 19.15 2.775 ;
      RECT 8.75 4.55 11.25 7.05 ;
      RECT 9.55 3.25 10.55 7.05 ;
      RECT 9.625 1.15 10.475 7.05 ;
      RECT 4.75 4.55 7.25 7.05 ;
      RECT 5.25 3.25 6.25 7.05 ;
      RECT 5.375 1.15 6.225 7.05 ;
      RECT 0.75 4.75 3.25 7.25 ;
      RECT 1.7 3.25 2.7 7.25 ;
      RECT 1.775 1.15 2.625 7.25 ;
      RECT 16.75 4.75 19.25 7.25 ;
    LAYER CONT ;
      RECT 17.5 5.5 18.5 6.5 ;
      RECT 12.5 2 13.5 3 ;
    LAYER SD ;
      RECT 17.75 4.75 19.25 11.5 ;
      RECT 16.75 4.75 19.25 7.25 ;
      RECT 17.4 2.65 18.8 7.25 ;
      RECT 17.3 2.65 18.9 3.65 ;
      RECT 12 7.3 13.5 9.9 ;
      RECT 12.5 1.5 13.5 9.9 ;
      RECT 3.5 7.3 13.5 8.3 ;
      RECT 3.5 1.4 4.5 8.3 ;
      RECT 12 1.5 14 3.5 ;
      RECT 10.35 1.5 14 3 ;
      RECT 2.5 1.4 5.5 3 ;
      RECT 10.35 1.4 11.35 3 ;
  END
END OR3_X2RL_T5

MACRO OR3_X4RL_T5
  CLASS CORE ;
  ORIGIN 0 0 ;
  FOREIGN OR3_X4RL_T5 0 0 ;
  SIZE 20 BY 20 ;
  SYMMETRY X Y ;
  SITE CoreSite_T5 ;
  PIN VDD
    DIRECTION INOUT ;
    USE POWER ;
    PORT
      LAYER SD ;
        RECT 0 19.5 20 20.5 ;
        RECT 14.25 18 15.85 20.5 ;
        RECT 0.5 17.9 2 20.5 ;
    END
  END VDD
  PIN VSS
    DIRECTION INOUT ;
    USE GROUND ;
    PORT
      LAYER SD ;
        RECT 0 -0.5 20 0.5 ;
        RECT 14.95 1.7 16.55 2.7 ;
        RECT 15.05 -0.5 16.45 2.7 ;
        RECT 8.7 1.4 9.7 3 ;
        RECT 7.7 -0.5 8.7 2.8 ;
        RECT 6.1 1.4 9.7 2.8 ;
        RECT 6.1 1.4 7.1 3 ;
        RECT 0.5 1.4 1.9 3 ;
        RECT 0.5 -0.5 1.5 3 ;
    END
  END VSS
  PIN A1
    DIRECTION INPUT ;
    USE SIGNAL ;
    PORT
      LAYER MT1 ;
        RECT 0.5 4.5 3.5 7.5 ;
    END
  END A1
  PIN A2
    DIRECTION INPUT ;
    USE SIGNAL ;
    PORT
      LAYER MT1 ;
        RECT 4.5 4.5 7.5 7.5 ;
    END
  END A2
  PIN A3
    DIRECTION INPUT ;
    USE SIGNAL ;
    PORT
      LAYER MT1 ;
        RECT 8.5 4.5 11.5 7.5 ;
    END
  END A3
  PIN Y
    DIRECTION INPUT ;
    USE SIGNAL ;
    PORT
      LAYER MT1 ;
        RECT 16.5 4.5 19.5 7.5 ;
    END
  END Y
  OBS
    LAYER VIA1 ;
      RECT 17.25 5.25 18.75 6.75 ;
      RECT 9.25 5.05 10.75 6.55 ;
      RECT 5.25 5.05 6.75 6.55 ;
      RECT 1.25 5.25 2.75 6.75 ;
    LAYER GATE ;
      RECT 11.55 2.5 14.7 3.5 ;
      RECT 11.55 2.575 16.8 3.425 ;
      RECT 11.55 1.5 13.55 3.5 ;
      RECT 8.75 4.55 11.25 7.05 ;
      RECT 9.45 3.25 10.45 7.05 ;
      RECT 9.575 1.15 10.425 7.05 ;
      RECT 4.75 4.55 7.25 7.05 ;
      RECT 5.25 3.25 6.25 7.05 ;
      RECT 5.375 1.15 6.225 7.05 ;
      RECT 0.75 4.75 3.25 7.25 ;
      RECT 1.7 3.25 2.7 7.25 ;
      RECT 1.775 1.15 2.625 7.25 ;
      RECT 16.75 4.75 19.25 7.25 ;
    LAYER CONT ;
      RECT 17.5 5.5 18.5 6.5 ;
      RECT 12.05 2 13.05 3 ;
    LAYER SD ;
      RECT 17.45 4.3 19.05 15.4 ;
      RECT 16.75 4.3 19.25 7.25 ;
      RECT 15.05 4.3 19.25 5.3 ;
      RECT 14.95 3.3 16.55 4.3 ;
      RECT 11.4 7.3 12.9 9.9 ;
      RECT 11.9 1.5 12.9 9.9 ;
      RECT 3.5 7.3 12.9 8.3 ;
      RECT 3.5 1.4 4.5 8.3 ;
      RECT 11.55 1.5 13.55 3.5 ;
      RECT 10.3 1.5 13.55 3 ;
      RECT 2.5 1.4 5.5 3 ;
      RECT 10.3 1.4 11.3 3 ;
  END
END OR3_X4RL_T5

MACRO OR4_X1RL_T5
  CLASS CORE ;
  ORIGIN 0 0 ;
  FOREIGN OR4_X1RL_T5 0 0 ;
  SIZE 28 BY 20 ;
  SYMMETRY X Y ;
  SITE CoreSite_T5 ;
  PIN VDD
    DIRECTION INOUT ;
    USE POWER ;
    PORT
      LAYER SD ;
        RECT 0 19.5 28 20.5 ;
        RECT 12.1 17.9 15.8 20.5 ;
    END
  END VDD
  PIN VSS
    DIRECTION INOUT ;
    USE GROUND ;
    PORT
      LAYER SD ;
        RECT 0 -0.5 28 0.5 ;
        RECT 14.35 1.4 17.4 3 ;
        RECT 15.35 -0.5 16.4 3 ;
        RECT 8.65 1.4 9.65 3 ;
        RECT 6.1 1.4 9.65 2.8 ;
        RECT 7.35 -0.5 8.35 2.8 ;
        RECT 6.1 1.4 7.1 3 ;
        RECT 0.5 1.4 1.9 3 ;
        RECT 0.5 -0.5 1.5 3 ;
    END
  END VSS
  PIN A1
    DIRECTION INPUT ;
    USE SIGNAL ;
    PORT
      LAYER MT1 ;
        RECT 0.5 4.5 3.5 7.5 ;
    END
  END A1
  PIN A2
    DIRECTION INPUT ;
    USE SIGNAL ;
    PORT
      LAYER MT1 ;
        RECT 4.5 4.5 7.5 7.5 ;
    END
  END A2
  PIN A3
    DIRECTION INPUT ;
    USE SIGNAL ;
    PORT
      LAYER MT1 ;
        RECT 8.5 4.5 11.5 7.5 ;
    END
  END A3
  PIN A4
    DIRECTION INPUT ;
    USE SIGNAL ;
    PORT
      LAYER MT1 ;
        RECT 12.5 4.5 15.5 7.5 ;
    END
  END A4
  PIN Y
    DIRECTION INPUT ;
    USE SIGNAL ;
    PORT
      LAYER MT1 ;
        RECT 20.5 4.5 23.5 7.5 ;
    END
  END Y
  OBS
    LAYER VIA1 ;
      RECT 21.25 5.25 22.75 6.75 ;
      RECT 13.25 5.05 14.75 6.55 ;
      RECT 9.25 5.05 10.75 6.55 ;
      RECT 5.25 5.05 6.75 6.55 ;
      RECT 1.25 5.05 2.75 6.55 ;
    LAYER GATE ;
      RECT 16.75 4.85 18.75 6.85 ;
      RECT 17.25 3.25 18.25 6.85 ;
      RECT 17.275 1.15 18.125 6.85 ;
      RECT 12.75 4.55 15.25 7.05 ;
      RECT 13.55 3.25 14.55 7.05 ;
      RECT 13.625 1.15 14.475 7.05 ;
      RECT 8.75 4.55 11.25 7.05 ;
      RECT 9.45 3.25 10.45 7.05 ;
      RECT 9.525 1.15 10.375 7.05 ;
      RECT 4.75 4.55 7.25 7.05 ;
      RECT 5.25 3.25 6.25 7.05 ;
      RECT 5.375 1.15 6.225 7.05 ;
      RECT 0.75 4.55 3.25 7.05 ;
      RECT 1.7 3.25 2.7 7.05 ;
      RECT 1.775 1.15 2.625 7.05 ;
      RECT 20.75 4.75 23.25 7.25 ;
    LAYER CONT ;
      RECT 21.5 5.5 22.5 6.5 ;
      RECT 17.25 5.35 18.25 6.35 ;
    LAYER SD ;
      RECT 25.9 8.3 27.5 9.9 ;
      RECT 25.9 4.75 26.9 9.9 ;
      RECT 20.75 4.75 23.25 7.25 ;
      RECT 20.75 4.75 26.9 5.75 ;
      RECT 20.75 2 21.75 7.25 ;
      RECT 18 2 21.75 3 ;
      RECT 18 1.4 19 3 ;
      RECT 0.5 7.3 2 9.9 ;
      RECT 0.5 7.3 17.75 8.3 ;
      RECT 16.75 4.85 17.75 8.3 ;
      RECT 11.5 1.6 12.5 8.3 ;
      RECT 3.5 1.5 4.5 8.3 ;
      RECT 16.75 4.85 18.75 6.85 ;
      RECT 10.25 1.6 13.75 3 ;
      RECT 12.75 1.4 13.75 3 ;
      RECT 4.5 1.4 5.5 3 ;
      RECT 10.25 1.4 11.25 3 ;
      RECT 2.5 1.4 3.5 3 ;
  END
END OR4_X1RL_T5

MACRO OR4_X2RL_T5
  CLASS CORE ;
  ORIGIN 0 0 ;
  FOREIGN OR4_X2RL_T5 0 0 ;
  SIZE 24 BY 20 ;
  SYMMETRY X Y ;
  SITE CoreSite_T5 ;
  PIN VDD
    DIRECTION INOUT ;
    USE POWER ;
    PORT
      LAYER SD ;
        RECT 0 19.5 24 20.5 ;
        RECT 15.85 17.9 17.35 20.5 ;
        RECT 0.5 17.9 2 20.5 ;
    END
  END VDD
  PIN VSS
    DIRECTION INOUT ;
    USE GROUND ;
    PORT
      LAYER SD ;
        RECT 0 -0.5 24 0.5 ;
        RECT 14.35 1.4 17.4 3 ;
        RECT 15.35 -0.5 16.4 3 ;
        RECT 8.65 1.4 9.65 3 ;
        RECT 6.1 1.4 9.65 2.8 ;
        RECT 7.4 -0.5 8.4 2.8 ;
        RECT 6.1 1.4 7.1 3 ;
        RECT 0.5 1.4 1.9 3 ;
        RECT 0.5 -0.5 1.5 3 ;
    END
  END VSS
  PIN A1
    DIRECTION INPUT ;
    USE SIGNAL ;
    PORT
      LAYER MT1 ;
        RECT 0.5 4.5 3.5 7.5 ;
    END
  END A1
  PIN A2
    DIRECTION INPUT ;
    USE SIGNAL ;
    PORT
      LAYER MT1 ;
        RECT 4.5 4.5 7.5 7.5 ;
    END
  END A2
  PIN A3
    DIRECTION INPUT ;
    USE SIGNAL ;
    PORT
      LAYER MT1 ;
        RECT 8.5 4.5 11.5 7.5 ;
    END
  END A3
  PIN A4
    DIRECTION INPUT ;
    USE SIGNAL ;
    PORT
      LAYER MT1 ;
        RECT 12.5 4.5 15.5 7.5 ;
    END
  END A4
  PIN Y
    DIRECTION INPUT ;
    USE SIGNAL ;
    PORT
      LAYER MT1 ;
        RECT 20.5 4.5 23.5 7.5 ;
    END
  END Y
  OBS
    LAYER VIA1 ;
      RECT 21.25 5.25 22.75 6.75 ;
      RECT 13.25 5.05 14.75 6.55 ;
      RECT 9.25 5.05 10.75 6.55 ;
      RECT 5.25 5.05 6.75 6.55 ;
      RECT 1.25 5.25 2.75 6.75 ;
    LAYER GATE ;
      RECT 16.75 4.85 18.75 6.85 ;
      RECT 17.25 3.25 18.25 6.85 ;
      RECT 17.275 1.15 18.125 6.85 ;
      RECT 12.75 4.55 15.25 7.05 ;
      RECT 13.55 3.25 14.55 7.05 ;
      RECT 13.625 1.15 14.475 7.05 ;
      RECT 8.75 4.55 11.25 7.05 ;
      RECT 9.45 3.25 10.45 7.05 ;
      RECT 9.525 1.15 10.375 7.05 ;
      RECT 4.75 4.55 7.25 7.05 ;
      RECT 5.25 3.25 6.25 7.05 ;
      RECT 5.375 1.15 6.225 7.05 ;
      RECT 0.75 4.75 3.25 7.25 ;
      RECT 1.7 3.25 2.7 7.25 ;
      RECT 1.775 1.15 2.625 7.25 ;
      RECT 20.75 4.75 23.25 7.25 ;
    LAYER CONT ;
      RECT 21.5 5.5 22.5 6.5 ;
      RECT 17.25 5.35 18.25 6.35 ;
    LAYER SD ;
      RECT 22 4.75 23.5 9.9 ;
      RECT 20.75 4.75 23.5 7.25 ;
      RECT 20.75 2 21.75 7.25 ;
      RECT 18 2 21.75 3 ;
      RECT 18 1.4 19 3 ;
      RECT 12.2 7.3 13.7 9.9 ;
      RECT 3.5 7.3 17.75 8.3 ;
      RECT 16.75 4.85 17.75 8.3 ;
      RECT 11.5 1.6 12.5 8.3 ;
      RECT 3.5 1.4 4.5 8.3 ;
      RECT 16.75 4.85 18.75 6.85 ;
      RECT 10.25 1.6 13.75 3 ;
      RECT 12.75 1.4 13.75 3 ;
      RECT 2.5 1.4 5.5 3 ;
      RECT 10.25 1.4 11.25 3 ;
  END
END OR4_X2RL_T5

MACRO OR4_X4RL_T5
  CLASS CORE ;
  ORIGIN 0 0 ;
  FOREIGN OR4_X4RL_T5 0 0 ;
  SIZE 28 BY 20 ;
  SYMMETRY X Y ;
  SITE CoreSite_T5 ;
  PIN VDD
    DIRECTION INOUT ;
    USE POWER ;
    PORT
      LAYER SD ;
        RECT 0 19.5 28 20.5 ;
        RECT 18.85 17.9 20.35 20.5 ;
        RECT 0.5 17.9 2 20.5 ;
    END
  END VDD
  PIN VSS
    DIRECTION INOUT ;
    USE GROUND ;
    PORT
      LAYER SD ;
        RECT 0 -0.5 28 0.5 ;
        RECT 22.15 8.35 23.75 9.35 ;
        RECT 22.25 -0.5 23.25 9.35 ;
        RECT 18.35 1.5 23.25 2.9 ;
        RECT 18.35 1.4 19.35 3 ;
        RECT 12.65 1.4 13.65 3 ;
        RECT 6.1 1.5 13.65 2.9 ;
        RECT 9.9 -0.5 11.3 2.9 ;
        RECT 6.1 1.4 7.1 3 ;
        RECT 0.5 1.4 1.9 3 ;
        RECT 0.5 -0.5 1.5 3 ;
    END
  END VSS
  PIN A1
    DIRECTION INPUT ;
    USE SIGNAL ;
    PORT
      LAYER MT1 ;
        RECT 0.5 4.5 3.5 7.5 ;
    END
  END A1
  PIN A2
    DIRECTION INPUT ;
    USE SIGNAL ;
    PORT
      LAYER MT1 ;
        RECT 4.5 4.5 7.5 7.5 ;
    END
  END A2
  PIN A3
    DIRECTION INPUT ;
    USE SIGNAL ;
    PORT
      LAYER MT1 ;
        RECT 12.5 4.5 15.5 7.5 ;
    END
  END A3
  PIN A4
    DIRECTION INPUT ;
    USE SIGNAL ;
    PORT
      LAYER MT1 ;
        RECT 16.5 4.5 19.5 7.5 ;
    END
  END A4
  PIN Y
    DIRECTION INPUT ;
    USE SIGNAL ;
    PORT
      LAYER MT1 ;
        RECT 24.5 12.5 27.5 15.5 ;
    END
  END Y
  OBS
    LAYER VIA1 ;
      RECT 25.25 13.25 26.75 14.75 ;
      RECT 17.25 5.05 18.75 6.55 ;
      RECT 13.25 5.05 14.75 6.55 ;
      RECT 5.25 5.05 6.75 6.55 ;
      RECT 1.25 5.25 2.75 6.75 ;
    LAYER GATE ;
      RECT 16.75 9.15 18.75 11.15 ;
      RECT 16.75 9.15 21.9 10.15 ;
      RECT 16.75 9.225 24 10.075 ;
      RECT 16.75 4.55 19.25 7.05 ;
      RECT 17.55 3.25 18.55 7.05 ;
      RECT 17.625 1.15 18.475 7.05 ;
      RECT 12.75 4.55 15.25 7.05 ;
      RECT 13.45 3.25 14.45 7.05 ;
      RECT 13.525 1.15 14.375 7.05 ;
      RECT 4.75 4.55 7.25 7.05 ;
      RECT 5.25 3.25 6.25 7.05 ;
      RECT 5.375 1.15 6.225 7.05 ;
      RECT 0.75 4.75 3.25 7.25 ;
      RECT 1.7 3.25 2.7 7.25 ;
      RECT 1.775 1.15 2.625 7.25 ;
      RECT 24.75 12.75 27.25 15.25 ;
    LAYER CONT ;
      RECT 25.5 13.5 26.5 14.5 ;
      RECT 17.25 9.65 18.25 10.65 ;
    LAYER SD ;
      RECT 21.95 14.4 27.25 16.3 ;
      RECT 24.75 12.75 27.25 16.3 ;
      RECT 24.75 10.95 26.15 16.3 ;
      RECT 22.25 10.95 26.15 12.35 ;
      RECT 22.15 9.95 23.75 10.95 ;
      RECT 16.75 9.15 18.75 11.15 ;
      RECT 9.45 7.3 10.95 9.9 ;
      RECT 16.75 7.3 17.75 11.15 ;
      RECT 3.5 7.3 17.75 8.3 ;
      RECT 15.5 1.6 16.5 8.3 ;
      RECT 3.5 1.4 4.5 8.3 ;
      RECT 14.25 1.6 17.75 3 ;
      RECT 16.75 1.4 17.75 3 ;
      RECT 2.5 1.4 5.5 3 ;
      RECT 14.25 1.4 15.25 3 ;
  END
END OR4_X4RL_T5

MACRO TIEHI_T5
  CLASS CORE ;
  ORIGIN 0 0 ;
  FOREIGN TIEHI_T5 0 0 ;
  SIZE 4 BY 20 ;
  SYMMETRY X Y ;
  SITE CoreSite_T5 ;
  PIN VDD
    DIRECTION INOUT ;
    USE POWER ;
    PORT
      LAYER SD ;
        RECT 0 19.5 4 20.5 ;
        RECT 0.7 18 3.3 20.5 ;
    END
  END VDD
  PIN VSS
    DIRECTION INOUT ;
    USE GROUND ;
    PORT
      LAYER SD ;
        RECT 0 -0.5 4 0.5 ;
    END
  END VSS
  PIN Y
    DIRECTION INPUT ;
    USE SIGNAL ;
    PORT
      LAYER MT1 ;
        RECT 0.5 8.5 3.5 11.5 ;
    END
  END Y
  OBS
    LAYER VIA1 ;
      RECT 1.25 9.25 2.75 10.75 ;
    LAYER GATE ;
      RECT 0.75 8.75 3.25 11.25 ;
    LAYER CONT ;
      RECT 1.5 9.5 2.5 10.5 ;
    LAYER SD ;
      RECT 0.7 11.3 3.3 12.8 ;
      RECT 0.75 8.75 3.25 12.8 ;
  END
END TIEHI_T5

MACRO TIELO_T5
  CLASS CORE ;
  ORIGIN 0 0 ;
  FOREIGN TIELO_T5 0 0 ;
  SIZE 4 BY 20 ;
  SYMMETRY X Y ;
  SITE CoreSite_T5 ;
  PIN VDD
    DIRECTION INOUT ;
    USE POWER ;
    PORT
      LAYER SD ;
        RECT 0 19.5 4 20.5 ;
    END
  END VDD
  PIN VSS
    DIRECTION INOUT ;
    USE GROUND ;
    PORT
      LAYER SD ;
        RECT 0 -0.5 4 0.5 ;
        RECT 0.7 -0.5 3.3 2 ;
    END
  END VSS
  PIN Y
    DIRECTION INPUT ;
    USE SIGNAL ;
    PORT
      LAYER MT1 ;
        RECT 0.5 8.5 3.5 11.5 ;
    END
  END Y
  OBS
    LAYER VIA1 ;
      RECT 1.25 9.25 2.75 10.75 ;
    LAYER GATE ;
      RECT 0.75 8.75 3.25 11.25 ;
    LAYER CONT ;
      RECT 1.5 9.5 2.5 10.5 ;
    LAYER SD ;
      RECT 0.75 7.2 3.25 11.25 ;
      RECT 0.7 7.2 3.3 8.7 ;
  END
END TIELO_T5

MACRO XNOR2_X1RL_T5
  CLASS CORE ;
  ORIGIN 0 0 ;
  FOREIGN XNOR2_X1RL_T5 0 0 ;
  SIZE 36 BY 20 ;
  SYMMETRY X Y ;
  SITE CoreSite_T5 ;
  PIN VDD
    DIRECTION INOUT ;
    USE POWER ;
    PORT
      LAYER SD ;
        RECT 0 19.5 36 20.5 ;
        RECT 33.9 17.9 35.5 20.5 ;
        RECT 25.6 17.9 27.1 20.5 ;
        RECT 0.5 17.9 2.1 20.5 ;
    END
  END VDD
  PIN VSS
    DIRECTION INOUT ;
    USE GROUND ;
    PORT
      LAYER SD ;
        RECT 0 -0.5 36 0.5 ;
        RECT 23.9 -0.5 25.5 1.5 ;
        RECT 18.25 -0.5 19.85 1.5 ;
        RECT 15.15 -0.5 16.75 1.8 ;
        RECT 12.2 -0.5 13.8 1.8 ;
    END
  END VSS
  PIN A1
    DIRECTION INPUT ;
    USE SIGNAL ;
    PORT
      LAYER MT1 ;
        RECT 8.5 0.5 11.5 3.5 ;
    END
  END A1
  PIN A2
    DIRECTION INPUT ;
    USE SIGNAL ;
    PORT
      LAYER MT1 ;
        RECT 20.5 0.5 23.5 3.5 ;
    END
  END A2
  PIN Y
    DIRECTION INPUT ;
    USE SIGNAL ;
    PORT
      LAYER MT1 ;
        RECT 8.5 8.5 11.5 11.5 ;
    END
  END Y
  OBS
    LAYER VIA1 ;
      RECT 21.25 1.25 22.75 2.75 ;
      RECT 9.25 1.25 10.75 2.75 ;
      RECT 9.25 9.25 10.75 10.75 ;
    LAYER GATE ;
      RECT 20.75 0.75 23.25 3.25 ;
      RECT 20.75 1.35 23.65 2.35 ;
      RECT 20.1 1.3 23.25 2.3 ;
      RECT 18 1.375 25.75 2.225 ;
      RECT 21.5 9.05 23.5 11.05 ;
      RECT 21.5 4.25 22.5 11.05 ;
      RECT 18.35 4.25 20.35 6.25 ;
      RECT 17.1 5.2 20.35 6.2 ;
      RECT 15 5.275 20.35 6.125 ;
      RECT 18.35 4.25 22.5 5.25 ;
      RECT 16.875 7.6 17.725 10.7 ;
      RECT 12.95 7.6 17.725 8.6 ;
      RECT 12.95 4.25 13.95 8.6 ;
      RECT 11.95 4.25 13.95 6.25 ;
      RECT 8.75 0.75 11.25 3.25 ;
      RECT 14.05 1.6 14.9 2.6 ;
      RECT 8.75 1.6 11.95 2.6 ;
      RECT 8.75 1.675 17 2.525 ;
      RECT 8.75 8.75 11.25 11.25 ;
    LAYER CONT ;
      RECT 22 9.55 23 10.55 ;
      RECT 18.85 4.75 19.85 5.75 ;
      RECT 12.45 4.75 13.45 5.75 ;
      RECT 9.5 9.5 10.5 10.5 ;
    LAYER SD ;
      RECT 21.5 9.05 23.5 11.05 ;
      RECT 21.5 9.25 27.5 10.85 ;
      RECT 17.6 8.85 18.6 10.45 ;
      RECT 17.6 8.85 20.4 9.85 ;
      RECT 19.4 7.05 20.4 9.85 ;
      RECT 19.4 7.05 24.9 8.05 ;
      RECT 23.9 2.1 24.9 8.05 ;
      RECT 23.9 2.1 25.5 3.1 ;
      RECT 18.35 4.25 20.35 6.25 ;
      RECT 18.35 2.1 19.35 6.25 ;
      RECT 18.25 2.1 19.85 3.1 ;
      RECT 8.5 8.5 10 13.1 ;
      RECT 8.5 8.5 11.5 11.5 ;
      RECT 16 8.85 17 10.45 ;
      RECT 8.5 8.95 17 9.95 ;
      RECT 15.35 6 16.35 9.95 ;
      RECT 15.25 6 16.85 7 ;
      RECT 15.25 4.4 16.85 5.4 ;
      RECT 15.25 2.4 16.65 5.4 ;
      RECT 15.15 2.4 16.75 3.4 ;
      RECT 11.95 4.25 13.95 6.25 ;
      RECT 6.9 3.4 8.5 4.9 ;
      RECT 6.9 3.5 13.6 4.5 ;
      RECT 12.2 2.4 13.6 6.25 ;
      RECT 12.2 2.4 13.8 3.4 ;
  END
END XNOR2_X1RL_T5

MACRO XNOR2_X2RL_T5
  CLASS CORE ;
  ORIGIN 0 0 ;
  FOREIGN XNOR2_X2RL_T5 0 0 ;
  SIZE 32 BY 20 ;
  SYMMETRY X Y ;
  SITE CoreSite_T5 ;
  PIN VDD
    DIRECTION INOUT ;
    USE POWER ;
    PORT
      LAYER SD ;
        RECT 0 19.5 32 20.5 ;
        RECT 17.4 17.9 20.4 20.5 ;
        RECT 0.5 17.9 2.1 20.5 ;
    END
  END VDD
  PIN VSS
    DIRECTION INOUT ;
    USE GROUND ;
    PORT
      LAYER SD ;
        RECT 0 -0.5 32 0.5 ;
        RECT 23.9 -0.5 25.5 1.5 ;
        RECT 18.25 -0.5 19.85 1.5 ;
        RECT 15.15 -0.5 16.75 1.8 ;
        RECT 12.2 -0.5 13.8 1.8 ;
    END
  END VSS
  PIN A1
    DIRECTION INPUT ;
    USE SIGNAL ;
    PORT
      LAYER MT1 ;
        RECT 8.5 0.5 11.5 3.5 ;
    END
  END A1
  PIN A2
    DIRECTION INPUT ;
    USE SIGNAL ;
    PORT
      LAYER MT1 ;
        RECT 20.5 0.5 23.5 3.5 ;
    END
  END A2
  PIN Y
    DIRECTION INPUT ;
    USE SIGNAL ;
    PORT
      LAYER MT1 ;
        RECT 8.5 8.5 11.5 11.5 ;
    END
  END Y
  OBS
    LAYER VIA1 ;
      RECT 21.25 1.25 22.75 2.75 ;
      RECT 9.25 1.25 10.75 2.75 ;
      RECT 9.25 9.25 10.75 10.75 ;
    LAYER GATE ;
      RECT 18.35 4.25 20.35 6.25 ;
      RECT 26.15 4.2 28.15 6.2 ;
      RECT 17.1 5.2 20.35 6.2 ;
      RECT 15 5.275 20.35 6.125 ;
      RECT 18.35 4.25 28.15 5.25 ;
      RECT 20.75 0.75 23.25 3.25 ;
      RECT 20.75 1.35 23.65 2.35 ;
      RECT 20.1 1.3 23.25 2.3 ;
      RECT 18 1.375 25.75 2.225 ;
      RECT 16.875 7.6 17.725 10.7 ;
      RECT 12.95 7.6 17.725 8.6 ;
      RECT 12.95 4.25 13.95 8.6 ;
      RECT 11.95 4.25 13.95 6.25 ;
      RECT 8.75 0.75 11.25 3.25 ;
      RECT 14.05 1.6 14.9 2.6 ;
      RECT 8.75 1.6 11.95 2.6 ;
      RECT 8.75 1.675 17 2.525 ;
      RECT 8.75 8.75 11.25 11.25 ;
    LAYER CONT ;
      RECT 26.65 4.7 27.65 5.7 ;
      RECT 18.85 4.75 19.85 5.75 ;
      RECT 12.45 4.75 13.45 5.75 ;
      RECT 9.5 9.5 10.5 10.5 ;
    LAYER SD ;
      RECT 27.2 7.15 28.8 8.65 ;
      RECT 27.75 4.2 28.8 8.65 ;
      RECT 26.15 4.2 28.8 6.2 ;
      RECT 17.6 8.85 18.6 10.45 ;
      RECT 17.6 8.95 25 9.95 ;
      RECT 24 2.1 25 9.95 ;
      RECT 23.9 2.1 25.5 3.1 ;
      RECT 18.35 4.25 20.35 6.25 ;
      RECT 18.35 2.1 19.35 6.25 ;
      RECT 18.25 2.1 19.85 3.1 ;
      RECT 8.5 8.5 10 13.1 ;
      RECT 8.5 8.5 11.5 11.5 ;
      RECT 16 8.85 17 10.45 ;
      RECT 8.5 8.95 17 9.95 ;
      RECT 15.35 6 16.35 9.95 ;
      RECT 15.25 6 16.85 7 ;
      RECT 15.25 4.4 16.85 5.4 ;
      RECT 15.25 2.4 16.65 5.4 ;
      RECT 15.15 2.4 16.75 3.4 ;
      RECT 11.95 4.25 13.95 6.25 ;
      RECT 6.9 3.4 8.5 4.9 ;
      RECT 6.9 3.5 13.6 4.5 ;
      RECT 12.2 2.4 13.6 6.25 ;
      RECT 12.2 2.4 13.8 3.4 ;
  END
END XNOR2_X2RL_T5

MACRO XNOR2_X4RL_T5
  CLASS CORE ;
  ORIGIN 0 0 ;
  FOREIGN XNOR2_X4RL_T5 0 0 ;
  SIZE 32 BY 20 ;
  SYMMETRY X Y ;
  SITE CoreSite_T5 ;
  PIN VDD
    DIRECTION INOUT ;
    USE POWER ;
    PORT
      LAYER SD ;
        RECT 0 19.5 32 20.5 ;
        RECT 18.9 17.9 20.4 20.5 ;
        RECT 13.2 17.9 14.7 20.5 ;
        RECT 0.5 17.9 2.1 20.5 ;
    END
  END VDD
  PIN VSS
    DIRECTION INOUT ;
    USE GROUND ;
    PORT
      LAYER SD ;
        RECT 0 -0.5 32 0.5 ;
        RECT 23.9 -0.5 26.5 1.5 ;
        RECT 19.05 3.5 20.95 5.1 ;
        RECT 19.05 -0.5 20.05 5.1 ;
        RECT 14.75 -0.5 17.35 1.8 ;
        RECT 11.75 -0.5 13.35 1.8 ;
    END
  END VSS
  PIN A1
    DIRECTION INPUT ;
    USE SIGNAL ;
    PORT
      LAYER MT1 ;
        RECT 8.5 0.5 11.5 3.5 ;
    END
  END A1
  PIN A2
    DIRECTION INPUT ;
    USE SIGNAL ;
    PORT
      LAYER MT1 ;
        RECT 20.5 0.5 23.5 3.5 ;
    END
  END A2
  PIN Y
    DIRECTION INPUT ;
    USE SIGNAL ;
    PORT
      LAYER MT1 ;
        RECT 8.5 8.5 11.5 11.5 ;
    END
  END Y
  OBS
    LAYER VIA1 ;
      RECT 21.25 1.25 22.75 2.75 ;
      RECT 9.25 1.25 10.75 2.75 ;
      RECT 9.25 9.25 10.75 10.75 ;
    LAYER GATE ;
      RECT 18.7 8.275 26.75 9.275 ;
      RECT 25.75 4.6 26.75 9.275 ;
      RECT 21 7.275 23 9.275 ;
      RECT 18.7 5.65 19.7 9.275 ;
      RECT 17.6 5.65 19.7 6.65 ;
      RECT 25.75 4.6 28.75 6.6 ;
      RECT 14.5 5.725 19.7 6.575 ;
      RECT 20.825 0.75 21.675 5.35 ;
      RECT 20.75 0.75 23.25 3.25 ;
      RECT 20.75 1.35 23.65 2.35 ;
      RECT 20.75 1.375 26.75 2.225 ;
      RECT 8.75 0.75 11.25 3.25 ;
      RECT 13.6 1.65 14.5 2.65 ;
      RECT 8.75 1.65 11.5 2.65 ;
      RECT 8.75 1.675 17.6 2.525 ;
      RECT 16.375 8 17.225 12.1 ;
      RECT 12.45 8 17.225 9 ;
      RECT 12.45 4.3 13.45 9 ;
      RECT 11.45 4.3 13.45 6.3 ;
      RECT 8.75 8.75 11.25 11.25 ;
    LAYER CONT ;
      RECT 27.25 5.1 28.25 6.1 ;
      RECT 21.5 7.775 22.5 8.775 ;
      RECT 11.95 4.8 12.95 5.8 ;
      RECT 9.5 9.5 10.5 10.5 ;
    LAYER SD ;
      RECT 27.2 4.6 28.8 8.7 ;
      RECT 26.75 4.6 28.8 6.6 ;
      RECT 17.1 9.25 18.1 11.85 ;
      RECT 17.1 10.425 25 11.425 ;
      RECT 24 2.1 25 11.425 ;
      RECT 23.9 2.1 26.5 3.1 ;
      RECT 21 7.275 23 9.275 ;
      RECT 22 3.5 23 9.275 ;
      RECT 21.55 3.5 23 5.1 ;
      RECT 14.75 4.85 17.35 5.85 ;
      RECT 14.85 2.4 17.25 5.85 ;
      RECT 14.75 2.4 17.35 3.4 ;
      RECT 8.5 8.5 10 13.1 ;
      RECT 15.5 9.25 16.5 11.85 ;
      RECT 8.5 8.5 11.5 11.5 ;
      RECT 8.5 9.35 16.5 10.35 ;
      RECT 14.75 6.45 15.75 10.35 ;
      RECT 14.75 6.45 17.35 7.45 ;
      RECT 11.45 4.3 13.45 6.3 ;
      RECT 6.9 3.4 8.5 4.9 ;
      RECT 6.9 3.5 13.15 4.5 ;
      RECT 11.75 2.4 13.15 6.3 ;
      RECT 11.75 2.4 13.35 3.4 ;
  END
END XNOR2_X4RL_T5

MACRO XOR2_X1RL_T5
  CLASS CORE ;
  ORIGIN 0 0 ;
  FOREIGN XOR2_X1RL_T5 0 0 ;
  SIZE 36 BY 20 ;
  SYMMETRY X Y ;
  SITE CoreSite_T5 ;
  PIN VDD
    DIRECTION INOUT ;
    USE POWER ;
    PORT
      LAYER SD ;
        RECT 0 19.5 36 20.5 ;
        RECT 33.9 17.9 35.5 20.5 ;
        RECT 8.5 17.9 10 20.5 ;
        RECT 0.5 17.9 2.1 20.5 ;
    END
  END VDD
  PIN VSS
    DIRECTION INOUT ;
    USE GROUND ;
    PORT
      LAYER SD ;
        RECT 0 -0.5 36 0.5 ;
        RECT 21.65 6.8 24.4 7.8 ;
        RECT 23.4 -0.5 24.4 7.8 ;
        RECT 11.425 12.1 22.65 13.1 ;
        RECT 21.65 6.8 22.65 13.1 ;
        RECT 18.775 4.4 20.375 5.4 ;
        RECT 18.775 -0.5 19.775 5.4 ;
        RECT 15.825 -0.5 17.425 1.7 ;
        RECT 12.25 -0.5 13.85 1.8 ;
        RECT 11.425 9.5 12.8 11.1 ;
        RECT 11.425 9.5 12.425 13.1 ;
    END
  END VSS
  PIN A1
    DIRECTION INPUT ;
    USE SIGNAL ;
    PORT
      LAYER MT1 ;
        RECT 8.5 0.5 11.5 3.5 ;
    END
  END A1
  PIN A2
    DIRECTION INPUT ;
    USE SIGNAL ;
    PORT
      LAYER MT1 ;
        RECT 20.5 0.5 23.5 3.5 ;
    END
  END A2
  PIN Y
    DIRECTION INPUT ;
    USE SIGNAL ;
    PORT
      LAYER MT1 ;
        RECT 8.5 4.5 11.5 7.5 ;
    END
  END Y
  OBS
    LAYER VIA1 ;
      RECT 21.15 1.25 22.65 2.75 ;
      RECT 9.25 1.25 10.75 2.75 ;
      RECT 9.25 5.25 10.75 6.75 ;
    LAYER GATE ;
      RECT 23.65 9.3 25.65 11.95 ;
      RECT 18.65 9.3 25.65 10.3 ;
      RECT 17.675 9.3 25.65 9.775 ;
      RECT 15.575 8.775 20.65 9.625 ;
      RECT 18.65 7.8 20.65 10.3 ;
      RECT 20.625 5.2 22.45 6.2 ;
      RECT 21.45 0.75 22.45 6.2 ;
      RECT 17.675 5.175 18.525 6.175 ;
      RECT 17.675 5.275 22.45 6.125 ;
      RECT 15.575 5.175 18.525 6.025 ;
      RECT 20.65 0.75 23.15 3.25 ;
      RECT 8.75 0.75 11.25 3.25 ;
      RECT 8.75 1.6 12 2.6 ;
      RECT 14.1 1.575 15.575 2.575 ;
      RECT 8.75 1.675 15.575 2.525 ;
      RECT 14.1 1.575 17.675 2.425 ;
      RECT 8.5 9.8 10.5 11.8 ;
      RECT 9.5 8.25 10.5 11.8 ;
      RECT 12.675 4 13.525 11.35 ;
      RECT 9.5 8.25 13.6 9.25 ;
      RECT 12.6 4 13.6 9.25 ;
      RECT 12.35 4 14.35 6 ;
      RECT 8.75 4.75 11.25 7.25 ;
    LAYER CONT ;
      RECT 24.15 10.45 25.15 11.45 ;
      RECT 19.15 8.3 20.15 9.3 ;
      RECT 12.85 4.5 13.85 5.5 ;
      RECT 9.5 5.5 10.5 6.5 ;
      RECT 9 10.3 10 11.3 ;
    LAYER SD ;
      RECT 23.65 10.5 27.5 12.1 ;
      RECT 23.65 9.95 25.65 12.1 ;
      RECT 18.65 7.8 20.65 9.8 ;
      RECT 18.775 6 20.375 9.8 ;
      RECT 15.825 4.3 17.425 5.3 ;
      RECT 16.025 2.3 17.425 5.3 ;
      RECT 15.825 2.3 17.425 3.3 ;
      RECT 15.825 5.9 17.425 8.9 ;
      RECT 8.5 6.9 17.425 7.9 ;
      RECT 8.5 4.75 11.25 7.9 ;
      RECT 6.9 3.4 8.5 4.9 ;
      RECT 6.9 3.5 9.5 4.9 ;
      RECT 13.4 9.5 14.4 11.1 ;
      RECT 13.4 9.875 17.425 10.875 ;
      RECT 15.825 9.5 17.425 10.875 ;
      RECT 12.35 4 14.35 6 ;
      RECT 12.35 2.4 13.85 6 ;
      RECT 12.25 2.4 13.85 3.4 ;
      RECT 8.5 13.1 10 14.7 ;
      RECT 8.5 9.8 9.5 14.7 ;
      RECT 8.5 9.8 10.5 11.8 ;
  END
END XOR2_X1RL_T5

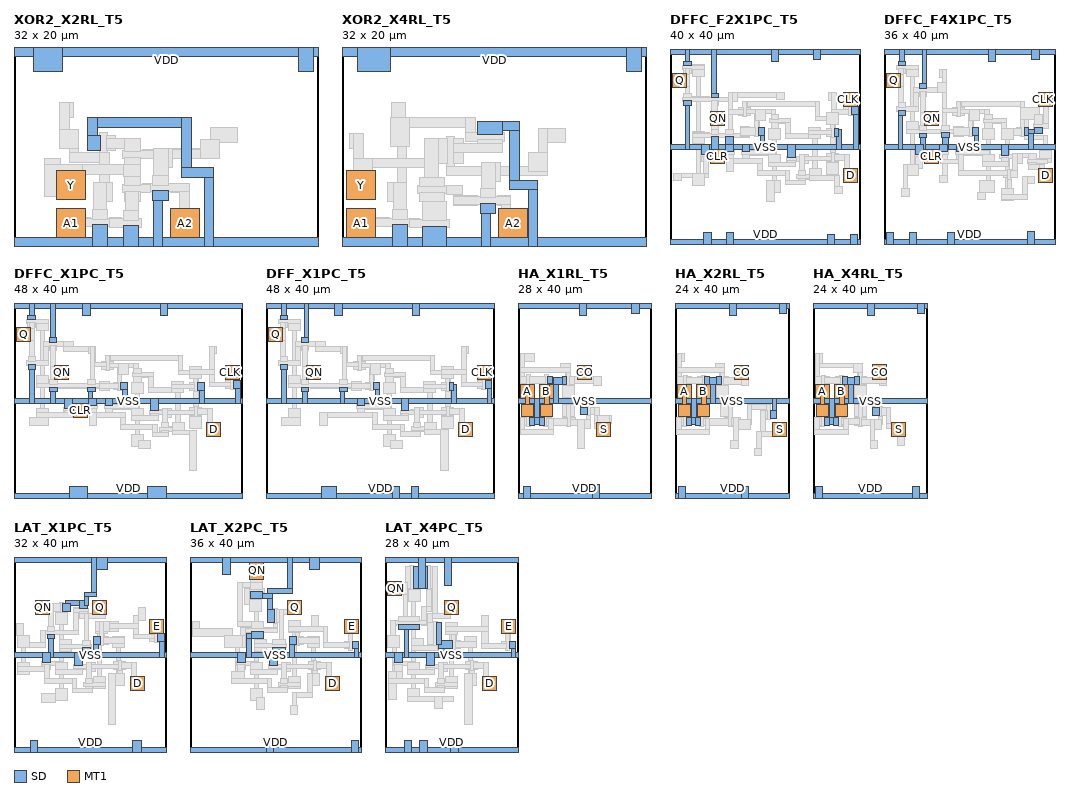
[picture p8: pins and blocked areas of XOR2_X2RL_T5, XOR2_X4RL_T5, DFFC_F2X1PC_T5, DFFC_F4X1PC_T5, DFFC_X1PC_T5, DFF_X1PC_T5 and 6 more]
MACRO XOR2_X2RL_T5
  CLASS CORE ;
  ORIGIN 0 0 ;
  FOREIGN XOR2_X2RL_T5 0 0 ;
  SIZE 32 BY 20 ;
  SYMMETRY X Y ;
  SITE CoreSite_T5 ;
  PIN VDD
    DIRECTION INOUT ;
    USE POWER ;
    PORT
      LAYER SD ;
        RECT 0 19.5 32 20.5 ;
        RECT 29.9 17.9 31.5 20.5 ;
        RECT 2.05 17.9 5.1 20.5 ;
    END
  END VDD
  PIN VSS
    DIRECTION INOUT ;
    USE GROUND ;
    PORT
      LAYER SD ;
        RECT 0 -0.5 32 0.5 ;
        RECT 17.65 6.8 21.025 7.8 ;
        RECT 20.025 -0.5 21.025 7.8 ;
        RECT 7.75 12.1 18.65 13.1 ;
        RECT 17.65 6.8 18.65 13.1 ;
        RECT 14.625 4.4 16.225 5.4 ;
        RECT 14.65 -0.5 15.65 5.4 ;
        RECT 11.55 -0.5 13.15 1.7 ;
        RECT 8.25 -0.5 9.85 1.8 ;
        RECT 7.75 9.65 9.125 11.25 ;
        RECT 7.75 9.65 8.75 13.1 ;
    END
  END VSS
  PIN A1
    DIRECTION INPUT ;
    USE SIGNAL ;
    PORT
      LAYER MT1 ;
        RECT 4.5 0.5 7.5 3.5 ;
    END
  END A1
  PIN A2
    DIRECTION INPUT ;
    USE SIGNAL ;
    PORT
      LAYER MT1 ;
        RECT 16.5 0.5 19.5 3.5 ;
    END
  END A2
  PIN Y
    DIRECTION INPUT ;
    USE SIGNAL ;
    PORT
      LAYER MT1 ;
        RECT 4.5 4.5 7.5 7.5 ;
    END
  END Y
  OBS
    LAYER VIA1 ;
      RECT 17.25 1.25 18.75 2.75 ;
      RECT 5.25 1.25 6.75 2.75 ;
      RECT 5.25 5.25 6.75 6.75 ;
    LAYER GATE ;
      RECT 19.65 8.8 21.65 10.8 ;
      RECT 14.65 8.8 21.65 9.8 ;
      RECT 13.525 8.8 21.65 9.775 ;
      RECT 11.425 8.775 16.65 9.625 ;
      RECT 14.65 7.8 16.65 9.8 ;
      RECT 16.475 5.2 18.45 6.2 ;
      RECT 17.45 0.75 18.45 6.2 ;
      RECT 13.525 5.175 14.375 6.175 ;
      RECT 13.525 5.275 18.45 6.125 ;
      RECT 11.425 5.175 14.375 6.025 ;
      RECT 16.75 0.75 19.25 3.25 ;
      RECT 4.75 0.75 7.25 3.25 ;
      RECT 4.75 1.6 8 2.6 ;
      RECT 10.1 1.575 11.3 2.575 ;
      RECT 4.75 1.675 11.3 2.525 ;
      RECT 10.1 1.575 13.4 2.425 ;
      RECT 4.8 9.8 6.8 11.8 ;
      RECT 5.8 8.4 6.8 11.8 ;
      RECT 9 8.4 9.85 11.5 ;
      RECT 5.8 8.4 10.025 9.4 ;
      RECT 9.025 4.25 10.025 9.4 ;
      RECT 8.35 4.25 10.35 6.25 ;
      RECT 4.75 4.75 7.25 7.25 ;
    LAYER CONT ;
      RECT 20.15 9.3 21.15 10.3 ;
      RECT 15.15 8.3 16.15 9.3 ;
      RECT 8.85 4.75 9.85 5.75 ;
      RECT 5.5 5.5 6.5 6.5 ;
      RECT 5.3 10.3 6.3 11.3 ;
    LAYER SD ;
      RECT 20.65 10.5 23.5 12.1 ;
      RECT 19.65 8.8 21.65 10.8 ;
      RECT 14.65 7.8 16.65 9.8 ;
      RECT 14.725 6 16.225 9.8 ;
      RECT 14.625 6 16.225 7 ;
      RECT 11.675 4.3 13.275 5.3 ;
      RECT 11.75 2.3 13.15 5.3 ;
      RECT 11.55 2.3 13.15 3.3 ;
      RECT 11.675 5.9 13.275 8.9 ;
      RECT 3.2 4.75 4.85 8.75 ;
      RECT 3.2 7.15 13.275 8.15 ;
      RECT 11.55 6.9 13.275 8.15 ;
      RECT 3.2 4.75 7.25 8.15 ;
      RECT 9.725 9.65 10.725 11.25 ;
      RECT 9.725 9.875 13.275 10.875 ;
      RECT 11.675 9.5 13.275 10.875 ;
      RECT 8.35 4.25 10.35 6.25 ;
      RECT 8.35 2.4 9.75 6.25 ;
      RECT 8.25 2.4 9.85 3.4 ;
      RECT 4.8 13.1 6.3 14.7 ;
      RECT 4.8 9.8 5.8 14.7 ;
      RECT 4.8 9.8 6.8 11.8 ;
  END
END XOR2_X2RL_T5

MACRO XOR2_X4RL_T5
  CLASS CORE ;
  ORIGIN 0 0 ;
  FOREIGN XOR2_X4RL_T5 0 0 ;
  SIZE 32 BY 20 ;
  SYMMETRY X Y ;
  SITE CoreSite_T5 ;
  PIN VDD
    DIRECTION INOUT ;
    USE POWER ;
    PORT
      LAYER SD ;
        RECT 0 19.5 32 20.5 ;
        RECT 29.9 17.9 31.5 20.5 ;
        RECT 1.6 17.9 5.1 20.5 ;
    END
  END VDD
  PIN VSS
    DIRECTION INOUT ;
    USE GROUND ;
    PORT
      LAYER SD ;
        RECT 0 -0.5 32 0.5 ;
        RECT 17.65 5.525 20.6 6.525 ;
        RECT 19.6 -0.5 20.6 6.525 ;
        RECT 14.25 11.725 18.65 12.725 ;
        RECT 17.65 5.525 18.65 12.725 ;
        RECT 14.25 11.35 16.85 12.725 ;
        RECT 14.55 3.05 16.15 4.05 ;
        RECT 14.65 -0.5 15.65 4.05 ;
        RECT 8.45 -0.5 11.05 1.625 ;
        RECT 5.3 -0.5 6.9 1.8 ;
    END
  END VSS
  PIN A1
    DIRECTION INPUT ;
    USE SIGNAL ;
    PORT
      LAYER MT1 ;
        RECT 0.5 0.5 3.5 3.5 ;
    END
  END A1
  PIN A2
    DIRECTION INPUT ;
    USE SIGNAL ;
    PORT
      LAYER MT1 ;
        RECT 16.5 0.5 19.5 3.5 ;
    END
  END A2
  PIN Y
    DIRECTION INPUT ;
    USE SIGNAL ;
    PORT
      LAYER MT1 ;
        RECT 0.5 4.5 3.5 7.5 ;
    END
  END Y
  OBS
    LAYER VIA1 ;
      RECT 17.25 1.25 18.75 2.75 ;
      RECT 1.25 1.25 2.75 2.75 ;
      RECT 1.25 5.25 2.75 6.75 ;
    LAYER GATE ;
      RECT 11.025 7 11.875 11.1 ;
      RECT 19.65 7 21.65 9.4 ;
      RECT 14.65 6.4 16.65 8.4 ;
      RECT 11.025 7 21.65 8 ;
      RECT 7.9 5.1 12.7 5.95 ;
      RECT 11.7 3.85 12.7 5.95 ;
      RECT 11 4.95 12.7 5.95 ;
      RECT 16.4 3.85 17.75 4.85 ;
      RECT 16.75 0.75 17.75 4.85 ;
      RECT 11.7 3.85 14.3 4.85 ;
      RECT 11.7 3.925 17.75 4.775 ;
      RECT 16.75 0.75 19.25 3.25 ;
      RECT 5.6 12.1 14 13.1 ;
      RECT 13 10.625 14 13.1 ;
      RECT 5.1 10.1 7.1 12.1 ;
      RECT 13 10.625 17.1 11.475 ;
      RECT 5.8 4.25 6.8 13.1 ;
      RECT 4.8 4.25 6.8 6.25 ;
      RECT 0.75 0.75 3.25 3.25 ;
      RECT 0.75 1.6 5.05 2.6 ;
      RECT 0.75 1.675 8.2 2.525 ;
      RECT 7.15 1.5 11.3 2.35 ;
      RECT 0.75 4.75 3.25 7.25 ;
    LAYER CONT ;
      RECT 20.15 7.9 21.15 8.9 ;
      RECT 15.15 6.9 16.15 7.9 ;
      RECT 5.6 10.6 6.6 11.6 ;
      RECT 5.3 4.75 6.3 5.75 ;
      RECT 1.5 5.5 2.5 6.5 ;
    LAYER SD ;
      RECT 20.65 10.5 23.5 12 ;
      RECT 20.65 7.4 21.65 12 ;
      RECT 19.65 7.4 21.65 9.4 ;
      RECT 11.75 8.25 12.75 10.85 ;
      RECT 14.25 9.375 16.85 10.75 ;
      RECT 11.75 9.375 16.85 10.375 ;
      RECT 14.65 6.4 16.65 8.4 ;
      RECT 14.65 4.65 16.15 8.4 ;
      RECT 14.55 4.65 16.15 5.65 ;
      RECT 0.75 9.85 2.25 11.45 ;
      RECT 1.25 4.75 2.25 11.45 ;
      RECT 8.65 8.25 11.15 10.85 ;
      RECT 1.25 7.825 10.15 8.825 ;
      RECT 8.65 5.825 10.15 10.85 ;
      RECT 1.25 4.75 3.25 8.825 ;
      RECT 0.75 4.75 3.25 7.25 ;
      RECT 8.15 5.825 10.75 6.825 ;
      RECT 8.15 4.225 10.75 5.225 ;
      RECT 8.45 2.225 11.05 4.225 ;
      RECT 5.2 10.1 6.7 14.7 ;
      RECT 5.1 10.1 7.1 13.1 ;
      RECT 4.8 4.25 6.8 6.25 ;
      RECT 5.4 2.4 6.8 6.25 ;
      RECT 5.3 2.4 6.9 3.4 ;
  END
END XOR2_X4RL_T5

MACRO DFFC_F2X1PC_T5
  CLASS CORE ;
  ORIGIN 0 0 ;
  FOREIGN DFFC_F2X1PC_T5 0 0 ;
  SIZE 40 BY 40 ;
  SYMMETRY X Y ;
  SITE DoubleHeightCoreSite_T5 ;
  PIN VDD
    DIRECTION INOUT ;
    USE POWER ;
    PORT
      LAYER SD ;
        RECT 0 -0.5 40 0.5 ;
        RECT 37.9 -0.5 39.5 1.6 ;
        RECT 33.1 -0.5 34.7 1.5 ;
        RECT 11.9 -0.5 13.4 2.1 ;
        RECT 7.15 -0.5 8.75 2.1 ;
        RECT 0 39.5 40 40.5 ;
        RECT 30.15 38.35 31.75 40.5 ;
        RECT 21.4 37.9 22.9 40.5 ;
        RECT 8.65 30.35 10.25 31.35 ;
        RECT 8.75 30.35 9.75 40.5 ;
        RECT 2.9 37.1 4.5 38.1 ;
        RECT 3.2 37.1 4.2 40.5 ;
    END
  END VDD
  PIN VSS
    DIRECTION INOUT ;
    USE GROUND ;
    PORT
      LAYER SD ;
        RECT 0 19.5 40 20.5 ;
        RECT 38.225 26.9 39.6 28.5 ;
        RECT 38.6 19.5 39.6 28.5 ;
        RECT 35 19.5 36 23.75 ;
        RECT 34.55 22.25 35.55 23.85 ;
        RECT 24.75 17.775 26.35 20.5 ;
        RECT 18.6 22.45 19.975 24.05 ;
        RECT 18.975 19.5 19.975 24.05 ;
        RECT 15.2 19.05 16.8 20.5 ;
        RECT 11.75 19.5 13.35 22.125 ;
        RECT 11.7 19.05 13.3 20.5 ;
        RECT 8.65 19.5 10.25 22.125 ;
        RECT 6.7 18.5 8.3 20.5 ;
        RECT 2.9 28.75 4.5 29.75 ;
        RECT 3.2 19.5 4.2 29.75 ;
    END
  END VSS
  PIN CLK
    DIRECTION INPUT ;
    USE SIGNAL ;
    PORT
      LAYER MT1 ;
        RECT 36.5 28.5 39.5 31.5 ;
    END
  END CLK
  PIN CLR
    DIRECTION INPUT ;
    USE SIGNAL ;
    PORT
      LAYER MT1 ;
        RECT 8.5 16.5 11.5 19.5 ;
    END
  END CLR
  PIN D
    DIRECTION INPUT ;
    USE SIGNAL ;
    PORT
      LAYER MT1 ;
        RECT 36.5 12.5 39.5 15.5 ;
    END
  END D
  PIN Q
    DIRECTION INPUT ;
    USE SIGNAL ;
    PORT
      LAYER MT1 ;
        RECT 0.5 32.5 3.5 35.5 ;
    END
  END Q
  PIN QN
    DIRECTION INPUT ;
    USE SIGNAL ;
    PORT
      LAYER MT1 ;
        RECT 8.5 24.5 11.5 27.5 ;
    END
  END QN
  OBS
    LAYER MT1 ;
      RECT 33 24.75 35.5 27.25 ;
      RECT 33.75 14.25 34.75 27.25 ;
      RECT 33 14.25 35.5 16.75 ;
      RECT 29.2 21.7 31.7 24.2 ;
      RECT 29.95 12.95 30.95 24.2 ;
      RECT 29.45 12.95 31.95 15.45 ;
      RECT 20.775 21.5 23.275 24 ;
      RECT 21.5 10.5 22.5 24 ;
      RECT 20.75 16 23.25 18.5 ;
      RECT 20.75 10.5 23.25 13 ;
      RECT 4.75 34.775 7.25 37.275 ;
      RECT 5.5 12 6.5 37.275 ;
      RECT 4.75 20.75 7.25 23.25 ;
      RECT 4.75 12 7.25 14.5 ;
    LAYER VIA1 ;
      RECT 37.25 13.25 38.75 14.75 ;
      RECT 37.25 29.25 38.75 30.75 ;
      RECT 33.5 14.75 35 16.25 ;
      RECT 33.5 25.25 35 26.75 ;
      RECT 29.95 13.45 31.45 14.95 ;
      RECT 29.7 22.2 31.2 23.7 ;
      RECT 21.275 22 22.775 23.5 ;
      RECT 21.25 11 22.75 12.5 ;
      RECT 21.25 16.5 22.75 18 ;
      RECT 9.25 17.25 10.75 18.75 ;
      RECT 9.25 25.25 10.75 26.75 ;
      RECT 5.25 12.5 6.75 14 ;
      RECT 5.25 21.25 6.75 22.75 ;
      RECT 5.25 35.275 6.75 36.775 ;
      RECT 1.25 33.25 2.75 34.75 ;
    LAYER GATE ;
      RECT 36.75 28.75 39.25 31.25 ;
      RECT 37.5 26.65 38.35 31.25 ;
      RECT 33.825 14.25 34.675 18.85 ;
      RECT 33 14.25 35.5 16.75 ;
      RECT 15.3 28.6 31.55 29.6 ;
      RECT 30.55 25.5 31.55 29.6 ;
      RECT 15.3 28.55 16.3 29.6 ;
      RECT 15.325 26.45 16.175 29.6 ;
      RECT 33 24.75 35.5 27.25 ;
      RECT 30.55 25.5 35.5 26.5 ;
      RECT 33.75 24.1 34.75 27.25 ;
      RECT 33.825 22 34.675 27.25 ;
      RECT 29.45 12.95 31.95 15.45 ;
      RECT 28.8 13.2 31.95 14.2 ;
      RECT 26.7 13.275 31.95 14.125 ;
      RECT 23.15 25.05 25.4 26.05 ;
      RECT 24.4 21.85 25.4 26.05 ;
      RECT 21.05 25.125 25.4 25.975 ;
      RECT 29.2 21.7 31.7 24.2 ;
      RECT 24.4 21.85 31.7 22.85 ;
      RECT 27.25 16.5 29.25 18.5 ;
      RECT 24.5 17.05 29.25 17.9 ;
      RECT 26.6 16.9 29.25 17.9 ;
      RECT 17.05 18.25 22.25 19.25 ;
      RECT 14.95 18.325 22.25 19.175 ;
      RECT 20.75 16 23.25 18.5 ;
      RECT 17.8 25.5 20.05 27.5 ;
      RECT 17.8 24.3 18.8 27.5 ;
      RECT 17.875 22.2 18.725 27.5 ;
      RECT 14.75 21.925 16.75 24.25 ;
      RECT 4.75 20.75 7.25 23.25 ;
      RECT 4.75 21.95 8.4 22.95 ;
      RECT 13.6 21.925 16.75 22.925 ;
      RECT 10.5 21.925 11.5 22.925 ;
      RECT 4.75 22 16.75 22.85 ;
      RECT 12.25 29.5 14.25 31.5 ;
      RECT 4.75 29.55 8.4 30.55 ;
      RECT 10.5 29.5 14.25 30.5 ;
      RECT 2.65 29.625 14.25 30.475 ;
      RECT 8.75 18.25 11.45 19.25 ;
      RECT 8.75 18.325 13.55 19.175 ;
      RECT 8.55 17.7 11.25 18.7 ;
      RECT 6.45 17.775 11.25 18.625 ;
      RECT 8.75 16.75 11.25 19.25 ;
      RECT 4.75 34.775 7.25 37.275 ;
      RECT 2.65 36.375 7.25 37.225 ;
      RECT 36.75 12.75 39.25 15.25 ;
      RECT 20.775 21.5 23.275 24 ;
      RECT 20.75 10.5 23.25 13 ;
      RECT 8.75 24.75 11.25 27.25 ;
      RECT 4.75 12 7.25 14.5 ;
      RECT 0.75 32.75 3.25 35.25 ;
    LAYER CONT ;
      RECT 37.5 13.5 38.5 14.5 ;
      RECT 33.75 25.5 34.75 26.5 ;
      RECT 30.2 13.7 31.2 14.7 ;
      RECT 29.95 22.45 30.95 23.45 ;
      RECT 27.75 17 28.75 18 ;
      RECT 21.525 22.25 22.525 23.25 ;
      RECT 21.5 11.25 22.5 12.25 ;
      RECT 21.5 16.75 22.5 17.75 ;
      RECT 18.55 26 19.55 27 ;
      RECT 15.25 22.75 16.25 23.75 ;
      RECT 12.75 30 13.75 31 ;
      RECT 9.5 25.5 10.5 26.5 ;
      RECT 5.5 12.75 6.5 13.75 ;
      RECT 1.5 33.5 2.5 34.5 ;
    LAYER SD ;
      RECT 34.55 17 35.55 18.6 ;
      RECT 34.55 17.1 37.75 18.5 ;
      RECT 36.75 12.75 37.75 18.5 ;
      RECT 36.75 12.75 39.25 15.25 ;
      RECT 33.35 29.85 34.95 31.45 ;
      RECT 33.95 24.75 34.95 31.45 ;
      RECT 36.625 26.9 37.625 28.5 ;
      RECT 33.95 26.9 37.625 27.9 ;
      RECT 33 24.75 35.5 27.25 ;
      RECT 29.45 12.95 31.95 15.45 ;
      RECT 29.45 12.95 35.7 13.95 ;
      RECT 34.7 10.2 35.7 13.95 ;
      RECT 34.7 10.2 36.3 11.75 ;
      RECT 32.95 17 33.95 18.6 ;
      RECT 27.25 16.5 29.25 18.5 ;
      RECT 27.25 17.1 33.95 18.1 ;
      RECT 27.25 14 28.25 18.5 ;
      RECT 26.95 14 28.55 15 ;
      RECT 29.2 21.7 31.7 24.2 ;
      RECT 32.95 22.25 33.95 23.85 ;
      RECT 29.2 22.55 33.95 23.55 ;
      RECT 15.2 16.5 16.8 18.45 ;
      RECT 11.7 17.45 13.3 18.45 ;
      RECT 18.5 14 19.5 17.5 ;
      RECT 11.8 16.5 19.5 17.5 ;
      RECT 11.8 14.9 13.4 17.5 ;
      RECT 18.5 14 25.25 15 ;
      RECT 24.25 12.025 25.25 15 ;
      RECT 26.95 12.4 28.55 13.4 ;
      RECT 24.25 12.025 28.45 13.025 ;
      RECT 20.75 15.8 23.25 18.5 ;
      RECT 24.75 15.8 26.35 17.175 ;
      RECT 20.75 15.8 26.35 16.8 ;
      RECT 12.25 30.5 24 31.5 ;
      RECT 22.5 29.9 24 31.5 ;
      RECT 12.25 29.5 14.25 31.5 ;
      RECT 12.25 22.725 13.25 31.5 ;
      RECT 14.45 26.7 15.45 28.3 ;
      RECT 12.25 26.8 15.45 27.8 ;
      RECT 11.75 22.725 13.35 23.725 ;
      RECT 21.3 21.5 22.9 25.25 ;
      RECT 20.775 21.5 23.275 24 ;
      RECT 20.3 10.5 23.25 13 ;
      RECT 20.3 8.6 21.9 13 ;
      RECT 16.05 26.7 17.05 28.3 ;
      RECT 16.05 27 22.3 28 ;
      RECT 21.3 25.85 22.3 28 ;
      RECT 18.05 25.5 20.05 28 ;
      RECT 21.3 25.85 22.9 26.85 ;
      RECT 14.75 22.25 16.75 24.25 ;
      RECT 14.75 22.45 18 24.05 ;
      RECT 8.65 28.75 10.25 29.75 ;
      RECT 8.75 22.725 9.9 29.75 ;
      RECT 8.75 24.75 11.25 27.25 ;
      RECT 8.75 22.725 10.25 27.25 ;
      RECT 8.65 22.725 10.25 23.725 ;
      RECT 6.7 16.9 8.3 17.9 ;
      RECT 7 13.5 8 17.9 ;
      RECT 0.75 13.5 8 14.5 ;
      RECT 4.75 12 7.25 14.5 ;
      RECT 0.75 12.9 2.35 14.5 ;
      RECT 2.9 35.5 4.5 36.5 ;
      RECT 2.9 32.75 4.2 36.5 ;
      RECT 3.2 30.35 4.2 36.5 ;
      RECT 0.75 32.75 4.2 35.25 ;
      RECT 2.9 30.35 4.5 31.35 ;
  END
END DFFC_F2X1PC_T5

MACRO DFFC_F4X1PC_T5
  CLASS CORE ;
  ORIGIN 0 0 ;
  FOREIGN DFFC_F4X1PC_T5 0 0 ;
  SIZE 36 BY 40 ;
  SYMMETRY X Y ;
  SITE DoubleHeightCoreSite_T5 ;
  PIN VDD
    DIRECTION INOUT ;
    USE POWER ;
    PORT
      LAYER SD ;
        RECT 0 -0.5 36 0.5 ;
        RECT 30.15 -0.5 31.75 2.25 ;
        RECT 13.3 -0.5 14.9 2 ;
        RECT 5.3 -0.5 6.9 2 ;
        RECT 0.5 -0.5 2.1 2.1 ;
        RECT 0 39.5 36 40.5 ;
        RECT 31.15 38.5 32.75 40.5 ;
        RECT 21.95 37.9 23.45 40.5 ;
        RECT 8.05 32.3 9.05 40.5 ;
        RECT 7.45 32.3 9.05 33.3 ;
        RECT 2.95 37.1 4.55 38.1 ;
        RECT 3.25 37.1 4.25 40.5 ;
    END
  END VDD
  PIN VSS
    DIRECTION INOUT ;
    USE GROUND ;
    PORT
      LAYER SD ;
        RECT 0 19.5 36 20.5 ;
        RECT 31.7 22.75 33.3 24.125 ;
        RECT 29.5 22.75 33.3 23.75 ;
        RECT 30.5 19.5 31.5 23.75 ;
        RECT 29.5 22.5 30.5 24.1 ;
        RECT 24.65 18.3 26.25 20.5 ;
        RECT 18.575 22.45 19.95 24.05 ;
        RECT 18.95 19.5 19.95 24.05 ;
        RECT 15.2 19.05 16.8 20.5 ;
        RECT 12.15 21.95 13.75 22.95 ;
        RECT 12.25 19.5 13.65 22.95 ;
        RECT 11.7 19.05 13.3 20.5 ;
        RECT 7.45 21.9 9.05 22.9 ;
        RECT 7.75 19.5 8.75 22.9 ;
        RECT 6.7 18.5 8.3 20.5 ;
        RECT 2.95 26.7 4.55 27.7 ;
        RECT 2.95 19.5 3.95 27.7 ;
    END
  END VSS
  PIN CLK
    DIRECTION INPUT ;
    USE SIGNAL ;
    PORT
      LAYER MT1 ;
        RECT 32.5 28.5 35.5 31.5 ;
    END
  END CLK
  PIN CLR
    DIRECTION INPUT ;
    USE SIGNAL ;
    PORT
      LAYER MT1 ;
        RECT 8.5 16.5 11.5 19.5 ;
    END
  END CLR
  PIN D
    DIRECTION INPUT ;
    USE SIGNAL ;
    PORT
      LAYER MT1 ;
        RECT 32.5 12.5 35.5 15.5 ;
    END
  END D
  PIN Q
    DIRECTION INPUT ;
    USE SIGNAL ;
    PORT
      LAYER MT1 ;
        RECT 0.5 32.5 3.5 35.5 ;
    END
  END Q
  PIN QN
    DIRECTION INPUT ;
    USE SIGNAL ;
    PORT
      LAYER MT1 ;
        RECT 8.5 24.5 11.5 27.5 ;
    END
  END QN
  OBS
    LAYER MT1 ;
      RECT 28.65 25.85 31.15 28.35 ;
      RECT 29.5 21.5 30.5 28.35 ;
      RECT 29.5 21.5 34.5 22.5 ;
      RECT 33.5 16.75 34.5 22.5 ;
      RECT 32.75 16.75 35.25 19.25 ;
      RECT 24.75 21.5 27.25 24 ;
      RECT 25.5 8.75 26.5 24 ;
      RECT 24.75 8.75 27.25 11.25 ;
      RECT 20.75 21.5 23.25 24 ;
      RECT 21.5 10.5 22.5 24 ;
      RECT 20.75 16 23.25 18.5 ;
      RECT 20.75 10.5 23.25 13 ;
      RECT 4.8 34.75 7.3 37.25 ;
      RECT 5.5 13.9 6.5 37.25 ;
      RECT 4.7 22.775 7.2 25.275 ;
      RECT 4.75 13.9 7.25 16.4 ;
    LAYER VIA1 ;
      RECT 33.25 13.25 34.75 14.75 ;
      RECT 33.25 17.25 34.75 18.75 ;
      RECT 33.25 29.25 34.75 30.75 ;
      RECT 29.15 26.35 30.65 27.85 ;
      RECT 25.25 9.25 26.75 10.75 ;
      RECT 25.25 22 26.75 23.5 ;
      RECT 21.25 11 22.75 12.5 ;
      RECT 21.25 16.5 22.75 18 ;
      RECT 21.25 22 22.75 23.5 ;
      RECT 9.25 17.25 10.75 18.75 ;
      RECT 9.25 25.25 10.75 26.75 ;
      RECT 5.3 35.25 6.8 36.75 ;
      RECT 5.25 14.4 6.75 15.9 ;
      RECT 5.2 23.275 6.7 24.775 ;
      RECT 1.25 33.25 2.75 34.75 ;
    LAYER GATE ;
      RECT 32.75 16.75 35.25 19.25 ;
      RECT 32.3 16.75 35.25 17.6 ;
      RECT 30.2 16.6 34.5 17.45 ;
      RECT 32.75 28.75 35.25 31.25 ;
      RECT 33.55 24 34.55 31.25 ;
      RECT 31.45 24 34.55 24.85 ;
      RECT 15.275 28.6 29.65 29.6 ;
      RECT 28.65 24.35 29.65 29.6 ;
      RECT 15.275 28.55 16.275 29.6 ;
      RECT 15.325 26.45 16.175 29.6 ;
      RECT 28.65 25.85 31.15 28.35 ;
      RECT 28.775 22.25 29.625 29.6 ;
      RECT 26.5 17.5 29.15 18.5 ;
      RECT 27.15 16.5 29.15 18.5 ;
      RECT 24.4 17.575 29.15 18.425 ;
      RECT 25.975 8.75 26.825 15.35 ;
      RECT 25.9 8.75 26.9 13.25 ;
      RECT 24.75 8.75 27.25 11.25 ;
      RECT 23.1 25.05 25.75 26.05 ;
      RECT 24.75 21.5 25.75 26.05 ;
      RECT 21 25.125 25.75 25.975 ;
      RECT 24.75 21.5 27.25 24 ;
      RECT 17.05 18.25 22.25 19.25 ;
      RECT 14.95 18.325 22.25 19.175 ;
      RECT 20.75 16 23.25 18.5 ;
      RECT 17.775 25.5 20 27.5 ;
      RECT 17.775 24.3 18.775 27.5 ;
      RECT 17.85 22.2 18.7 27.5 ;
      RECT 4.7 22.775 7.2 25.275 ;
      RECT 14.725 22.25 16.725 24.25 ;
      RECT 14 22.75 16.725 23.75 ;
      RECT 9.3 22.75 11.9 23.75 ;
      RECT 9.3 22.825 16.725 23.675 ;
      RECT 4.7 22.775 11.9 23.625 ;
      RECT 8.75 18.25 11.45 19.25 ;
      RECT 8.75 18.325 13.55 19.175 ;
      RECT 8.55 17.7 11.25 18.7 ;
      RECT 6.45 17.775 11.25 18.625 ;
      RECT 8.75 16.75 11.25 19.25 ;
      RECT 11.25 31.5 13.25 33.5 ;
      RECT 9.3 31.525 13.25 32.5 ;
      RECT 9.4 31.5 13.25 32.5 ;
      RECT 6.2 27.475 7.2 32.5 ;
      RECT 6.2 31.575 13.25 32.425 ;
      RECT 4.8 27.475 7.2 28.475 ;
      RECT 2.7 27.575 7.2 28.425 ;
      RECT 4.8 34.75 7.3 37.25 ;
      RECT 2.7 36.375 7.3 37.225 ;
      RECT 32.75 12.75 35.25 15.25 ;
      RECT 20.75 10.5 23.25 13 ;
      RECT 20.75 21.5 23.25 24 ;
      RECT 8.75 24.75 11.25 27.25 ;
      RECT 4.75 13.9 7.25 16.4 ;
      RECT 0.75 32.75 3.25 35.25 ;
    LAYER CONT ;
      RECT 33.5 13.5 34.5 14.5 ;
      RECT 29.4 26.6 30.4 27.6 ;
      RECT 27.65 17 28.65 18 ;
      RECT 25.5 9.5 26.5 10.5 ;
      RECT 25.5 22.25 26.5 23.25 ;
      RECT 21.5 11.25 22.5 12.25 ;
      RECT 21.5 16.75 22.5 17.75 ;
      RECT 21.5 22.25 22.5 23.25 ;
      RECT 18.5 26 19.5 27 ;
      RECT 15.225 22.75 16.225 23.75 ;
      RECT 11.75 32 12.75 33 ;
      RECT 9.5 25.5 10.5 26.5 ;
      RECT 5.5 14.65 6.5 15.65 ;
      RECT 1.5 33.5 2.5 34.5 ;
    LAYER SD ;
      RECT 30.45 15.35 32.05 16.725 ;
      RECT 30.45 15.35 33.75 16.35 ;
      RECT 32.75 12.75 33.75 16.35 ;
      RECT 32.75 12.75 35.25 15.25 ;
      RECT 31.15 25.85 32.75 28.4 ;
      RECT 28.65 25.85 32.75 28.35 ;
      RECT 31.7 24.725 33.3 26.85 ;
      RECT 27.15 17.7 32.05 18.7 ;
      RECT 30.45 17.325 32.05 18.7 ;
      RECT 27.15 16.5 29.15 18.7 ;
      RECT 27.15 13.5 28.15 18.7 ;
      RECT 26.7 13.5 28.15 15.1 ;
      RECT 29.15 12.35 31.75 13.85 ;
      RECT 29.15 8.95 30.15 13.85 ;
      RECT 24.75 8.75 27.25 11.25 ;
      RECT 24.75 8.95 30.15 9.95 ;
      RECT 27.9 22.5 28.9 24.1 ;
      RECT 24.75 22.5 28.9 24 ;
      RECT 24.75 21.5 27.25 24 ;
      RECT 20.75 16 23.25 18.5 ;
      RECT 24.65 16.7 26.25 17.7 ;
      RECT 20.75 16 26.15 17 ;
      RECT 15.2 17.45 16.8 18.45 ;
      RECT 11.7 17.45 13.3 18.45 ;
      RECT 12.3 12.5 13.3 18.45 ;
      RECT 11.8 16.45 16.7 17.45 ;
      RECT 15.7 14 16.7 18.45 ;
      RECT 25.1 13.5 26.1 15.1 ;
      RECT 15.7 14 26.1 15 ;
      RECT 11.7 12.5 13.3 14 ;
      RECT 20.1 10.5 23.25 13 ;
      RECT 19.7 9 21.3 10.5 ;
      RECT 21.25 21.5 22.85 25.25 ;
      RECT 20.75 21.5 23.25 24 ;
      RECT 16.05 26.7 17.05 28.3 ;
      RECT 16.05 27 22.25 28 ;
      RECT 21.25 25.85 22.25 28 ;
      RECT 18 25.5 20 28 ;
      RECT 21.25 25.85 22.85 26.85 ;
      RECT 14.725 22.25 16.725 24.25 ;
      RECT 14.725 22.45 17.975 24.05 ;
      RECT 11.75 34.7 13.25 36.3 ;
      RECT 12.25 23.55 13.25 36.3 ;
      RECT 11.25 31.5 13.25 33.5 ;
      RECT 14.45 26.7 15.45 28.3 ;
      RECT 12.25 27.2 15.45 28.2 ;
      RECT 12.15 23.55 13.75 24.55 ;
      RECT 7.45 30.7 9.05 31.7 ;
      RECT 7.75 23.5 8.75 31.7 ;
      RECT 7.75 24.75 11.25 27.25 ;
      RECT 7.75 23.5 9.05 27.25 ;
      RECT 7.45 23.5 9.05 24.5 ;
      RECT 6.7 16.9 8.3 17.9 ;
      RECT 6.7 15.4 8.2 17.9 ;
      RECT 4 13.9 7.25 16.4 ;
      RECT 4 9.5 5 16.4 ;
      RECT 3.7 9.5 5.3 11.3 ;
      RECT 2.95 35.5 4.55 36.5 ;
      RECT 2.95 32.75 4.15 36.5 ;
      RECT 3.15 28.3 4.15 36.5 ;
      RECT 0.75 32.75 4.15 35.25 ;
      RECT 2.95 28.3 4.55 29.3 ;
  END
END DFFC_F4X1PC_T5

MACRO DFFC_X1PC_T5
  CLASS CORE ;
  ORIGIN 0 0 ;
  FOREIGN DFFC_X1PC_T5 0 0 ;
  SIZE 48 BY 40 ;
  SYMMETRY X Y ;
  SITE DoubleHeightCoreSite_T5 ;
  PIN VDD
    DIRECTION INOUT ;
    USE POWER ;
    PORT
      LAYER SD ;
        RECT 0 -0.5 48 0.5 ;
        RECT 28.05 -0.5 32.2 2.1 ;
        RECT 11.75 -0.5 15.4 2.1 ;
        RECT 0 39.5 48 40.5 ;
        RECT 30.9 37.9 32.4 40.5 ;
        RECT 14.5 37.9 16 40.5 ;
        RECT 7.45 32.3 9.05 33.3 ;
        RECT 7.75 32.3 8.75 40.5 ;
        RECT 2.9 37.1 4.5 38.1 ;
        RECT 3.25 37.1 4.25 40.5 ;
    END
  END VDD
  PIN VSS
    DIRECTION INOUT ;
    USE GROUND ;
    PORT
      LAYER SD ;
        RECT 0 19.5 48 20.5 ;
        RECT 46.225 22.7 47.6 24.3 ;
        RECT 46.6 19.5 47.6 24.3 ;
        RECT 38.55 22.25 40 23.85 ;
        RECT 39 19.5 40 23.85 ;
        RECT 28.75 17.925 30.35 20.5 ;
        RECT 22.525 22.4 23.9 24 ;
        RECT 22.9 19.5 23.9 24 ;
        RECT 19.2 19.05 20.8 20.5 ;
        RECT 15.7 19.05 17.3 20.5 ;
        RECT 15.5 21.9 17.1 22.9 ;
        RECT 15.6 19.5 16.6 22.9 ;
        RECT 10.7 18.5 12.3 20.5 ;
        RECT 7.5 21.9 9.1 22.9 ;
        RECT 7.75 19.5 8.75 22.9 ;
        RECT 2.95 26.7 4.55 27.7 ;
        RECT 3.25 19.5 4.25 27.7 ;
    END
  END VSS
  PIN CLK
    DIRECTION INPUT ;
    USE SIGNAL ;
    PORT
      LAYER MT1 ;
        RECT 44.5 24.5 47.5 27.5 ;
    END
  END CLK
  PIN CLR
    DIRECTION INPUT ;
    USE SIGNAL ;
    PORT
      LAYER MT1 ;
        RECT 12.5 16.5 15.5 19.5 ;
    END
  END CLR
  PIN D
    DIRECTION INPUT ;
    USE SIGNAL ;
    PORT
      LAYER MT1 ;
        RECT 40.5 12.5 43.5 15.5 ;
    END
  END D
  PIN Q
    DIRECTION INPUT ;
    USE SIGNAL ;
    PORT
      LAYER MT1 ;
        RECT 0.5 32.5 3.5 35.5 ;
    END
  END Q
  PIN QN
    DIRECTION INPUT ;
    USE SIGNAL ;
    PORT
      LAYER MT1 ;
        RECT 8.5 24.5 11.5 27.5 ;
    END
  END QN
  OBS
    LAYER MT1 ;
      RECT 37 24.75 39.5 27.25 ;
      RECT 37.75 14.25 38.75 27.25 ;
      RECT 37 14.25 39.5 16.75 ;
      RECT 33.2 21.7 35.7 24.2 ;
      RECT 33.95 12.95 34.95 24.2 ;
      RECT 33.45 12.95 35.95 15.45 ;
      RECT 24.75 21.5 27.25 24 ;
      RECT 25.5 10.5 26.5 24 ;
      RECT 24.75 16 27.25 18.5 ;
      RECT 24.75 10.5 27.25 13 ;
      RECT 4.75 34.75 7.25 37.25 ;
      RECT 5.5 16 6.5 37.25 ;
      RECT 4.75 22.775 7.25 25.275 ;
      RECT 4.75 16 7.25 18.5 ;
    LAYER VIA1 ;
      RECT 45.25 25.25 46.75 26.75 ;
      RECT 41.25 13.25 42.75 14.75 ;
      RECT 37.5 14.75 39 16.25 ;
      RECT 37.5 25.25 39 26.75 ;
      RECT 33.95 13.45 35.45 14.95 ;
      RECT 33.7 22.2 35.2 23.7 ;
      RECT 25.25 11 26.75 12.5 ;
      RECT 25.25 16.5 26.75 18 ;
      RECT 25.25 22 26.75 23.5 ;
      RECT 13.25 17.25 14.75 18.75 ;
      RECT 9.25 25.25 10.75 26.75 ;
      RECT 5.25 16.5 6.75 18 ;
      RECT 5.25 23.275 6.75 24.775 ;
      RECT 5.25 35.25 6.75 36.75 ;
      RECT 1.25 33.25 2.75 34.75 ;
    LAYER GATE ;
      RECT 44.75 24.75 47.25 27.25 ;
      RECT 45.425 24.55 46.425 27.25 ;
      RECT 45.5 22.45 46.35 27.25 ;
      RECT 37.825 14.25 38.675 18.85 ;
      RECT 37 14.25 39.5 16.75 ;
      RECT 19.25 28.6 35.55 29.6 ;
      RECT 34.55 25.5 35.55 29.6 ;
      RECT 19.25 28.55 20.25 29.6 ;
      RECT 19.325 26.45 20.175 29.6 ;
      RECT 37 24.75 39.5 27.25 ;
      RECT 34.55 25.5 39.5 26.5 ;
      RECT 37.75 24.1 38.75 27.25 ;
      RECT 37.825 22 38.675 27.25 ;
      RECT 33.45 12.95 35.95 15.45 ;
      RECT 32.8 13.6 35.95 14.6 ;
      RECT 30.7 13.675 35.95 14.525 ;
      RECT 27.1 25.05 29.4 26.05 ;
      RECT 28.4 21.85 29.4 26.05 ;
      RECT 25 25.125 29.4 25.975 ;
      RECT 33.2 21.7 35.7 24.2 ;
      RECT 28.4 21.85 35.7 22.85 ;
      RECT 31.25 16.5 33.25 18.5 ;
      RECT 30.6 17.125 33.25 18.125 ;
      RECT 28.5 17.2 33.25 18.05 ;
      RECT 21.05 18.25 26.25 19.25 ;
      RECT 18.95 18.325 26.25 19.175 ;
      RECT 24.75 16 27.25 18.5 ;
      RECT 21.725 25.5 24 27.5 ;
      RECT 21.725 24.25 22.725 27.5 ;
      RECT 21.8 22.15 22.65 27.5 ;
      RECT 4.75 22.775 7.25 25.275 ;
      RECT 18 22.2 20 24.2 ;
      RECT 17.35 22.7 20 23.7 ;
      RECT 9.35 22.7 15.25 23.7 ;
      RECT 4.75 22.775 20 23.625 ;
      RECT 12.75 18.25 15.45 19.25 ;
      RECT 12.75 18.325 17.55 19.175 ;
      RECT 12.55 17.7 15.25 18.7 ;
      RECT 10.45 17.775 15.25 18.625 ;
      RECT 12.75 16.75 15.25 19.25 ;
      RECT 9.3 31.5 12.5 32.5 ;
      RECT 10.5 30.5 12.5 32.5 ;
      RECT 6.2 27.5 7.2 32.5 ;
      RECT 6.2 31.575 12.5 32.425 ;
      RECT 4.8 27.5 7.2 28.5 ;
      RECT 2.7 27.575 7.2 28.425 ;
      RECT 4.75 34.75 7.25 37.25 ;
      RECT 2.65 36.375 7.25 37.225 ;
      RECT 40.75 12.75 43.25 15.25 ;
      RECT 24.75 10.5 27.25 13 ;
      RECT 24.75 21.5 27.25 24 ;
      RECT 8.75 24.75 11.25 27.25 ;
      RECT 4.75 16 7.25 18.5 ;
      RECT 0.75 32.75 3.25 35.25 ;
    LAYER CONT ;
      RECT 41.5 13.5 42.5 14.5 ;
      RECT 37.75 25.5 38.75 26.5 ;
      RECT 34.2 13.7 35.2 14.7 ;
      RECT 33.95 22.45 34.95 23.45 ;
      RECT 31.75 17 32.75 18 ;
      RECT 25.5 11.25 26.5 12.25 ;
      RECT 25.5 16.75 26.5 17.75 ;
      RECT 25.5 22.25 26.5 23.25 ;
      RECT 22.5 26 23.5 27 ;
      RECT 18.5 22.7 19.5 23.7 ;
      RECT 11 31 12 32 ;
      RECT 9.5 25.5 10.5 26.5 ;
      RECT 5.5 16.75 6.5 17.75 ;
      RECT 1.5 33.5 2.5 34.5 ;
    LAYER SD ;
      RECT 41.15 29.9 42.65 31.5 ;
      RECT 41.25 23 42.25 31.5 ;
      RECT 37 24.75 39.5 27.25 ;
      RECT 37 25.6 42.25 26.6 ;
      RECT 44.625 22.7 45.625 24.3 ;
      RECT 41.25 23 45.625 24 ;
      RECT 38.55 17 39.55 18.6 ;
      RECT 38.55 17.1 41.75 18.5 ;
      RECT 40.75 12.75 41.75 18.5 ;
      RECT 40.75 12.75 43.25 15.25 ;
      RECT 33.45 12.85 35.95 15.45 ;
      RECT 33.45 12.85 38.4 13.85 ;
      RECT 36.9 5.3 38.4 13.85 ;
      RECT 36.95 17 37.95 18.6 ;
      RECT 31.25 16.5 33.25 18.5 ;
      RECT 31.25 17.1 37.95 18.1 ;
      RECT 31.25 14.4 32.25 18.5 ;
      RECT 30.95 14.4 32.55 15.4 ;
      RECT 33.2 21.7 35.7 24.2 ;
      RECT 36.95 22.25 37.95 23.85 ;
      RECT 33.2 22.55 37.95 23.55 ;
      RECT 19.2 16.5 20.8 18.45 ;
      RECT 15.7 17.45 17.3 18.45 ;
      RECT 22.5 14 23.5 17.5 ;
      RECT 15.8 16.5 23.5 17.5 ;
      RECT 15.8 14.9 17.4 17.5 ;
      RECT 22.5 14 30.15 15 ;
      RECT 29.15 12.425 30.15 15 ;
      RECT 30.95 12.425 32.55 13.8 ;
      RECT 29.15 12.425 32.55 13.425 ;
      RECT 24.75 15.95 27.25 18.5 ;
      RECT 28.75 15.95 30.35 17.325 ;
      RECT 24.75 15.95 30.35 16.95 ;
      RECT 24.75 10.5 27.25 13 ;
      RECT 26.25 10.1 28.75 11.7 ;
      RECT 25.25 21.5 26.85 25.25 ;
      RECT 24.75 21.5 27.25 24 ;
      RECT 20.05 26.7 21.05 28.3 ;
      RECT 20.05 27 26.25 28 ;
      RECT 25.25 25.85 26.25 28 ;
      RECT 22 25.5 24 28 ;
      RECT 25.25 25.85 26.85 26.85 ;
      RECT 18 22.2 20 24.2 ;
      RECT 20.925 22.4 21.925 24 ;
      RECT 18 22.7 21.925 23.7 ;
      RECT 10.5 30.5 12.5 32.5 ;
      RECT 10.5 30.5 17.1 31.5 ;
      RECT 16 27.2 17.1 31.5 ;
      RECT 15.6 29.9 17.1 31.5 ;
      RECT 18.45 26.7 19.45 28.3 ;
      RECT 16 27.2 19.45 28.2 ;
      RECT 16 23.5 17 31.5 ;
      RECT 15.5 23.5 17.1 24.5 ;
      RECT 4.75 14.9 7.25 18.5 ;
      RECT 10.7 16.525 12.3 17.9 ;
      RECT 4.75 16.525 12.3 17.525 ;
      RECT 3.25 14.9 7.25 16.5 ;
      RECT 7.45 30.7 9.05 31.7 ;
      RECT 7.75 23.5 8.75 31.7 ;
      RECT 7.75 24.75 11.25 27.25 ;
      RECT 7.75 23.5 9.1 27.25 ;
      RECT 7.5 23.5 9.1 24.5 ;
      RECT 2.9 35.5 4.5 36.5 ;
      RECT 2.9 32.75 4.25 36.5 ;
      RECT 3.2 28.3 4.25 36.5 ;
      RECT 0.75 32.75 4.25 35.25 ;
      RECT 2.95 28.3 4.55 29.3 ;
  END
END DFFC_X1PC_T5

MACRO DFF_X1PC_T5
  CLASS CORE ;
  ORIGIN 0 0 ;
  FOREIGN DFF_X1PC_T5 0 0 ;
  SIZE 48 BY 40 ;
  SYMMETRY X Y ;
  SITE DoubleHeightCoreSite_T5 ;
  PIN VDD
    DIRECTION INOUT ;
    USE POWER ;
    PORT
      LAYER SD ;
        RECT 0 -0.5 48 0.5 ;
        RECT 30.6 -0.5 32.2 2.1 ;
        RECT 26.55 -0.5 28.05 2.1 ;
        RECT 11.75 -0.5 14.85 2.1 ;
        RECT 0 39.5 48 40.5 ;
        RECT 30.9 37.9 32.4 40.5 ;
        RECT 14.5 37.9 16 40.5 ;
        RECT 8.05 32.3 9.05 40.5 ;
        RECT 7.45 32.3 9.05 33.3 ;
        RECT 2.95 37.1 4.55 38.1 ;
        RECT 3.25 37.1 4.25 40.5 ;
    END
  END VDD
  PIN VSS
    DIRECTION INOUT ;
    USE GROUND ;
    PORT
      LAYER SD ;
        RECT 0 19.5 48 20.5 ;
        RECT 46.175 22.7 47.55 24.3 ;
        RECT 46.55 19.5 47.55 24.3 ;
        RECT 39 19.5 40 23.55 ;
        RECT 38.55 22.25 39.55 23.85 ;
        RECT 28.5 17.925 30.1 20.5 ;
        RECT 22.6 22.4 23.975 24 ;
        RECT 22.975 19.5 23.975 24 ;
        RECT 19.2 19.05 20.8 20.5 ;
        RECT 15.5 21.9 17.1 22.9 ;
        RECT 15.6 19.5 16.6 22.9 ;
        RECT 7.45 21.9 9.05 22.9 ;
        RECT 7.75 19.5 8.75 22.9 ;
        RECT 2.95 26.7 4.55 27.7 ;
        RECT 3.25 19.5 4.25 27.7 ;
    END
  END VSS
  PIN CLK
    DIRECTION INPUT ;
    USE SIGNAL ;
    PORT
      LAYER MT1 ;
        RECT 44.5 24.5 47.5 27.5 ;
    END
  END CLK
  PIN D
    DIRECTION INPUT ;
    USE SIGNAL ;
    PORT
      LAYER MT1 ;
        RECT 40.5 12.5 43.5 15.5 ;
    END
  END D
  PIN Q
    DIRECTION INPUT ;
    USE SIGNAL ;
    PORT
      LAYER MT1 ;
        RECT 0.5 32.5 3.5 35.5 ;
    END
  END Q
  PIN QN
    DIRECTION INPUT ;
    USE SIGNAL ;
    PORT
      LAYER MT1 ;
        RECT 8.5 24.5 11.5 27.5 ;
    END
  END QN
  OBS
    LAYER MT1 ;
      RECT 37 24.75 39.5 27.25 ;
      RECT 37.75 14.25 38.75 27.25 ;
      RECT 37 14.25 39.5 16.75 ;
      RECT 33.2 21.7 35.7 24.2 ;
      RECT 33.95 12.95 34.95 24.2 ;
      RECT 33.45 12.95 35.95 15.45 ;
      RECT 24.8 21.5 27.3 24 ;
      RECT 25.5 10.5 26.5 24 ;
      RECT 24.75 16 27.25 18.5 ;
      RECT 24.75 10.5 27.25 13 ;
      RECT 4.8 34.75 7.3 37.25 ;
      RECT 5.5 16 6.5 37.25 ;
      RECT 4.7 22.775 7.2 25.275 ;
      RECT 4.75 16 7.25 18.5 ;
    LAYER VIA1 ;
      RECT 45.25 25.25 46.75 26.75 ;
      RECT 41.25 13.25 42.75 14.75 ;
      RECT 37.5 14.75 39 16.25 ;
      RECT 37.5 25.25 39 26.75 ;
      RECT 33.95 13.45 35.45 14.95 ;
      RECT 33.7 22.2 35.2 23.7 ;
      RECT 25.3 22 26.8 23.5 ;
      RECT 25.25 11 26.75 12.5 ;
      RECT 25.25 16.5 26.75 18 ;
      RECT 9.25 25.25 10.75 26.75 ;
      RECT 5.3 35.25 6.8 36.75 ;
      RECT 5.25 16.5 6.75 18 ;
      RECT 5.2 23.275 6.7 24.775 ;
      RECT 1.25 33.25 2.75 34.75 ;
    LAYER GATE ;
      RECT 44.75 24.75 47.25 27.25 ;
      RECT 45.375 24.55 46.375 27.25 ;
      RECT 45.45 22.45 46.3 27.25 ;
      RECT 37.825 14.25 38.675 18.85 ;
      RECT 37 14.25 39.5 16.75 ;
      RECT 19.25 28.6 35.55 29.6 ;
      RECT 34.55 25.5 35.55 29.6 ;
      RECT 19.25 28.55 20.25 29.6 ;
      RECT 19.325 26.45 20.175 29.6 ;
      RECT 37 24.75 39.5 27.25 ;
      RECT 34.55 25.5 39.5 26.5 ;
      RECT 37.75 24.1 38.75 27.25 ;
      RECT 37.825 22 38.675 27.25 ;
      RECT 33.45 12.95 35.95 15.45 ;
      RECT 32.8 13.625 35.95 14.625 ;
      RECT 30.7 13.75 35.95 14.6 ;
      RECT 27.1 25.05 29.4 26.05 ;
      RECT 28.4 21.85 29.4 26.05 ;
      RECT 25 25.125 29.4 25.975 ;
      RECT 33.2 21.7 35.7 24.2 ;
      RECT 28.4 21.85 35.7 22.85 ;
      RECT 31.25 16.575 33.25 18.575 ;
      RECT 30.35 17.125 33.25 18.125 ;
      RECT 28.25 17.2 33.25 18.05 ;
      RECT 21.05 18.25 26.25 19.25 ;
      RECT 18.95 18.325 26.25 19.175 ;
      RECT 24.75 16 27.25 18.5 ;
      RECT 21.8 25.5 24 27.5 ;
      RECT 21.8 24.25 22.8 27.5 ;
      RECT 21.875 22.15 22.725 27.5 ;
      RECT 4.7 22.775 7.2 25.275 ;
      RECT 18 22.2 20 24.2 ;
      RECT 17.35 22.7 20 23.7 ;
      RECT 9.3 22.7 15.25 23.7 ;
      RECT 4.7 22.775 20 23.625 ;
      RECT 6.2 27.5 7.2 32.525 ;
      RECT 9.3 31.5 12.5 32.5 ;
      RECT 10.5 30.5 12.5 32.5 ;
      RECT 6.2 31.575 12.5 32.425 ;
      RECT 4.8 27.5 7.2 28.5 ;
      RECT 2.7 27.575 7.2 28.425 ;
      RECT 4.8 34.75 7.3 37.25 ;
      RECT 2.7 36.375 7.3 37.225 ;
      RECT 40.75 12.75 43.25 15.25 ;
      RECT 24.8 21.5 27.3 24 ;
      RECT 24.75 10.5 27.25 13 ;
      RECT 8.75 24.75 11.25 27.25 ;
      RECT 4.75 16 7.25 18.5 ;
      RECT 0.75 32.75 3.25 35.25 ;
    LAYER CONT ;
      RECT 41.5 13.5 42.5 14.5 ;
      RECT 37.75 25.5 38.75 26.5 ;
      RECT 34.2 13.7 35.2 14.7 ;
      RECT 33.95 22.45 34.95 23.45 ;
      RECT 31.75 17.075 32.75 18.075 ;
      RECT 25.55 22.25 26.55 23.25 ;
      RECT 25.5 11.25 26.5 12.25 ;
      RECT 25.5 16.75 26.5 17.75 ;
      RECT 22.5 26 23.5 27 ;
      RECT 18.5 22.7 19.5 23.7 ;
      RECT 11 31 12 32 ;
      RECT 9.5 25.5 10.5 26.5 ;
      RECT 5.5 16.75 6.5 17.75 ;
      RECT 1.5 33.5 2.5 34.5 ;
    LAYER SD ;
      RECT 41.2 29.9 42.7 31.5 ;
      RECT 41.2 23 42.2 31.5 ;
      RECT 37 24.75 39.5 27.25 ;
      RECT 37 25.6 42.2 26.6 ;
      RECT 44.575 22.7 45.575 24.3 ;
      RECT 41.2 23 45.575 24 ;
      RECT 38.55 17 39.55 18.6 ;
      RECT 38.55 17.1 41.75 18.5 ;
      RECT 40.75 12.75 41.75 18.5 ;
      RECT 40.75 12.75 43.25 15.25 ;
      RECT 33.45 12.95 35.95 15.45 ;
      RECT 33.45 12.95 38.4 13.95 ;
      RECT 36.8 5.3 38.4 13.95 ;
      RECT 36.95 17 37.95 18.6 ;
      RECT 31.25 16.575 33.25 18.575 ;
      RECT 31.25 17.1 37.95 18.1 ;
      RECT 31.25 14.475 32.25 18.575 ;
      RECT 30.95 14.475 32.55 15.475 ;
      RECT 33.2 21.7 35.7 24.2 ;
      RECT 36.95 22.25 37.95 23.85 ;
      RECT 33.2 22.55 37.95 23.55 ;
      RECT 19.2 16.5 20.8 18.45 ;
      RECT 11.35 16.5 23.5 17.5 ;
      RECT 22.5 14 23.5 17.5 ;
      RECT 11.35 14.9 12.95 17.5 ;
      RECT 22.5 14 29.25 15 ;
      RECT 28.25 12.5 29.25 15 ;
      RECT 30.95 12.5 32.55 13.875 ;
      RECT 28.25 12.5 32.55 13.5 ;
      RECT 24.75 15.95 27.25 18.5 ;
      RECT 28.5 15.95 30.1 17.325 ;
      RECT 24.75 15.95 30.1 16.95 ;
      RECT 24.75 10.5 27.25 13 ;
      RECT 26.25 10.1 28.75 11.7 ;
      RECT 25.25 21.5 26.85 25.25 ;
      RECT 24.8 21.5 27.3 24 ;
      RECT 20.05 26.7 21.05 28.3 ;
      RECT 20.05 27 26.25 28 ;
      RECT 25.25 25.85 26.25 28 ;
      RECT 22 25.5 24 28 ;
      RECT 25.25 25.85 26.85 26.85 ;
      RECT 18 22.2 20 24.2 ;
      RECT 21 22.4 22 24 ;
      RECT 18 22.7 22 23.7 ;
      RECT 10.5 30.5 12.5 32.5 ;
      RECT 10.5 30.5 17.1 31.5 ;
      RECT 16 27.2 17.1 31.5 ;
      RECT 15.6 29.9 17.1 31.5 ;
      RECT 18.45 26.7 19.45 28.3 ;
      RECT 16 27.2 19.45 28.2 ;
      RECT 16 23.5 17 31.5 ;
      RECT 15.5 23.5 17.1 24.5 ;
      RECT 7.45 30.7 9.05 31.7 ;
      RECT 7.75 23.5 8.75 31.7 ;
      RECT 7.75 24.75 11.25 27.25 ;
      RECT 7.75 23.5 9.05 27.25 ;
      RECT 7.45 23.5 9.05 24.5 ;
      RECT 4.75 14.9 7.25 18.5 ;
      RECT 3.25 14.9 7.25 16.5 ;
      RECT 2.95 35.5 4.55 36.5 ;
      RECT 2.95 32.75 4.15 36.5 ;
      RECT 3.15 28.3 4.15 36.5 ;
      RECT 0.75 32.75 4.15 35.25 ;
      RECT 2.95 28.3 4.55 29.3 ;
  END
END DFF_X1PC_T5

MACRO HA_X1RL_T5
  CLASS CORE ;
  ORIGIN 0 0 ;
  FOREIGN HA_X1RL_T5 0 0 ;
  SIZE 28 BY 40 ;
  SYMMETRY X Y ;
  SITE DoubleHeightCoreSite_T5 ;
  PIN VDD
    DIRECTION INOUT ;
    USE POWER ;
    PORT
      LAYER SD ;
        RECT 0 -0.5 28 0.5 ;
        RECT 15.75 -0.5 17.25 2.45 ;
        RECT 1.1 -0.5 2.6 2.1 ;
        RECT 0 39.5 28 40.5 ;
        RECT 23.9 38.5 25.5 40.5 ;
        RECT 12.925 37.9 14.425 40.5 ;
    END
  END VDD
  PIN VSS
    DIRECTION INOUT ;
    USE GROUND ;
    PORT
      LAYER SD ;
        RECT 0 19.5 28 20.5 ;
        RECT 13.225 17.1 14.6 18.7 ;
        RECT 13.225 17.1 14.225 20.5 ;
        RECT 9.3 23.5 10.3 25.1 ;
        RECT 6.3 23.65 10.3 25.05 ;
        RECT 7.5 23.5 10.3 25.05 ;
        RECT 7.5 19.5 8.5 25.05 ;
        RECT 6.3 23.65 7.3 25.25 ;
        RECT 2.425 15.1 5.5 16.5 ;
        RECT 4.5 14.9 5.5 16.5 ;
        RECT 3.5 15.1 4.5 20.5 ;
        RECT 2.425 14.9 3.425 16.5 ;
    END
  END VSS
  PIN A
    DIRECTION INPUT ;
    USE SIGNAL ;
    PORT
      LAYER MT1 ;
        RECT 0.5 20.5 3.5 23.5 ;
        RECT 0.75 16.75 3.25 19.25 ;
        RECT 1.5 16.75 2.5 23.5 ;
    END
  END A
  PIN B
    DIRECTION INPUT ;
    USE SIGNAL ;
    PORT
      LAYER MT1 ;
        RECT 4.5 20.5 7.5 23.5 ;
        RECT 4.75 16.75 7.25 19.25 ;
        RECT 5.55 16.75 6.55 23.5 ;
    END
  END B
  PIN CO
    DIRECTION INPUT ;
    USE SIGNAL ;
    PORT
      LAYER MT1 ;
        RECT 12.5 24.5 15.5 27.5 ;
    END
  END CO
  PIN S
    DIRECTION INPUT ;
    USE SIGNAL ;
    PORT
      LAYER MT1 ;
        RECT 16.5 12.5 19.5 15.5 ;
    END
  END S
  OBS
    LAYER MT1 ;
      RECT 9.45 20.75 11.95 23.25 ;
      RECT 10.2 16.75 11.2 23.25 ;
      RECT 9.45 16.75 11.95 19.25 ;
    LAYER VIA1 ;
      RECT 17.25 13.25 18.75 14.75 ;
      RECT 13.25 25.25 14.75 26.75 ;
      RECT 9.95 17.25 11.45 18.75 ;
      RECT 9.95 21.25 11.45 22.75 ;
      RECT 5.25 17.25 6.75 18.75 ;
      RECT 5.25 21.25 6.75 22.75 ;
      RECT 1.25 17.25 2.75 18.75 ;
      RECT 1.25 21.25 2.75 22.75 ;
    LAYER GATE ;
      RECT 14.475 14.2 15.325 18.95 ;
      RECT 14.35 14.2 15.35 16.85 ;
      RECT 13.35 14.2 15.35 16.2 ;
      RECT 9.45 16.75 11.95 19.25 ;
      RECT 10.275 14.65 11.125 19.25 ;
      RECT 9.05 25.95 11.05 27.95 ;
      RECT 10.05 25.35 11.05 27.95 ;
      RECT 10.175 20.75 11.025 27.95 ;
      RECT 9.45 20.75 11.95 23.25 ;
      RECT 4.75 16.75 7.25 19.25 ;
      RECT 5.375 14.65 6.225 19.25 ;
      RECT 5.575 20.75 6.425 25.5 ;
      RECT 5.475 20.75 6.475 23.4 ;
      RECT 4.75 20.75 7.25 23.25 ;
      RECT 0.75 16.75 3.25 19.25 ;
      RECT 1.7 14.65 2.55 19.25 ;
      RECT 1.7 20.75 2.55 25.5 ;
      RECT 1.6 20.75 2.6 23.4 ;
      RECT 0.75 20.75 3.25 23.25 ;
      RECT 16.75 12.75 19.25 15.25 ;
      RECT 12.75 24.75 15.25 27.25 ;
    LAYER CONT ;
      RECT 17.5 13.5 18.5 14.5 ;
      RECT 13.85 14.7 14.85 15.7 ;
      RECT 13.5 25.5 14.5 26.5 ;
      RECT 9.55 26.45 10.55 27.45 ;
    LAYER SD ;
      RECT 15.2 17.1 17.15 18.7 ;
      RECT 16.15 14.25 17.15 18.7 ;
      RECT 16.15 15.25 19.75 16.85 ;
      RECT 16.75 12.75 19.25 16.85 ;
      RECT 12.75 23.7 15.25 27.25 ;
      RECT 10.9 23.7 17.5 25.1 ;
      RECT 15.9 23.25 17.5 25.1 ;
      RECT 10.9 23.5 11.9 25.1 ;
      RECT 11 14.9 12 16.5 ;
      RECT 11 14.9 15.35 16.2 ;
      RECT 12.6 14.2 15.35 16.2 ;
      RECT 12.6 10.1 14.1 16.2 ;
      RECT 0.45 28.3 3.425 29.9 ;
      RECT 0.45 23.65 1.45 29.9 ;
      RECT 9.05 25.95 11.05 27.95 ;
      RECT 0.45 26.05 11.05 27.05 ;
      RECT 0.45 23.65 1.825 25.25 ;
      RECT 9.4 14.9 10.4 16.5 ;
      RECT 6.1 14.9 7.1 16.5 ;
      RECT 0.45 14.9 1.825 16.5 ;
      RECT 6.1 14.9 10.4 16.3 ;
      RECT 6.475 12.9 7.475 16.3 ;
      RECT 0.45 12.9 1.45 16.5 ;
      RECT 0.45 12.9 7.475 13.9 ;
      RECT 4.7 23.65 5.7 25.25 ;
      RECT 2.425 23.65 3.425 25.25 ;
      RECT 2.425 23.75 5.7 25.15 ;
  END
END HA_X1RL_T5

MACRO HA_X2RL_T5
  CLASS CORE ;
  ORIGIN 0 0 ;
  FOREIGN HA_X2RL_T5 0 0 ;
  SIZE 24 BY 40 ;
  SYMMETRY X Y ;
  SITE DoubleHeightCoreSite_T5 ;
  PIN VDD
    DIRECTION INOUT ;
    USE POWER ;
    PORT
      LAYER SD ;
        RECT 0 -0.5 24 0.5 ;
        RECT 13.9 -0.5 15.4 2.1 ;
        RECT 0.7 -0.5 2.2 2.1 ;
        RECT 0 39.5 24 40.5 ;
        RECT 21.9 38.5 23.5 40.5 ;
        RECT 11.5 37.9 13 40.5 ;
    END
  END VDD
  PIN VSS
    DIRECTION INOUT ;
    USE GROUND ;
    PORT
      LAYER SD ;
        RECT 0 19.5 24 20.5 ;
        RECT 20.45 16.4 21.45 20.5 ;
        RECT 20.075 16.4 21.45 18 ;
        RECT 8.7 23.5 9.7 25.1 ;
        RECT 6.3 23.5 9.7 24.9 ;
        RECT 7.5 19.5 8.5 24.9 ;
        RECT 6.3 23.5 7.3 25.1 ;
        RECT 2.375 15.1 5.375 16.5 ;
        RECT 4.375 14.9 5.375 16.5 ;
        RECT 3.5 15.1 4.5 20.5 ;
        RECT 2.375 14.9 3.375 16.5 ;
    END
  END VSS
  PIN A
    DIRECTION INPUT ;
    USE SIGNAL ;
    PORT
      LAYER MT1 ;
        RECT 0.5 20.5 3.5 23.5 ;
        RECT 0.75 16.75 3.25 19.25 ;
        RECT 1.5 16.75 2.5 23.5 ;
    END
  END A
  PIN B
    DIRECTION INPUT ;
    USE SIGNAL ;
    PORT
      LAYER MT1 ;
        RECT 4.5 20.5 7.5 23.5 ;
        RECT 4.75 16.75 7.25 19.25 ;
        RECT 5.55 16.75 6.55 23.5 ;
    END
  END B
  PIN CO
    DIRECTION INPUT ;
    USE SIGNAL ;
    PORT
      LAYER MT1 ;
        RECT 12.5 24.5 15.5 27.5 ;
    END
  END CO
  PIN S
    DIRECTION INPUT ;
    USE SIGNAL ;
    PORT
      LAYER MT1 ;
        RECT 20.5 12.5 23.5 15.5 ;
    END
  END S
  OBS
    LAYER MT1 ;
      RECT 8.75 20.75 11.25 23.25 ;
      RECT 9.5 16.75 10.5 23.25 ;
      RECT 9.5 16.75 12 19.25 ;
    LAYER VIA1 ;
      RECT 21.25 13.25 22.75 14.75 ;
      RECT 13.25 25.25 14.75 26.75 ;
      RECT 10 17.25 11.5 18.75 ;
      RECT 9.25 21.25 10.75 22.75 ;
      RECT 5.25 17.25 6.75 18.75 ;
      RECT 5.25 21.25 6.75 22.75 ;
      RECT 1.25 17.25 2.75 18.75 ;
      RECT 1.25 21.25 2.75 22.75 ;
    LAYER GATE ;
      RECT 15.175 18.25 20.2 19.25 ;
      RECT 19.35 16.15 20.2 19.25 ;
      RECT 15.175 15.05 16.175 19.25 ;
      RECT 13.85 14.1 15.85 16.1 ;
      RECT 9.5 16.75 12.05 19.25 ;
      RECT 11.2 14.65 12.05 19.25 ;
      RECT 8.45 25.95 10.45 27.95 ;
      RECT 9.45 25.35 10.45 27.95 ;
      RECT 9.575 20.75 10.425 27.95 ;
      RECT 8.75 20.75 11.25 23.25 ;
      RECT 4.75 16.75 7.25 19.25 ;
      RECT 5.25 14.65 6.1 19.25 ;
      RECT 5.575 20.75 6.425 25.35 ;
      RECT 4.75 20.75 7.25 23.25 ;
      RECT 0.75 16.75 3.25 19.25 ;
      RECT 1.65 14.65 2.5 19.25 ;
      RECT 1.7 20.75 2.55 25.35 ;
      RECT 0.75 20.75 3.25 23.25 ;
      RECT 20.75 12.75 23.25 15.25 ;
      RECT 12.75 24.75 15.25 27.25 ;
    LAYER CONT ;
      RECT 21.5 13.5 22.5 14.5 ;
      RECT 14.35 14.6 15.35 15.6 ;
      RECT 13.5 25.5 14.5 26.5 ;
      RECT 8.95 26.45 9.95 27.45 ;
    LAYER SD ;
      RECT 18.1 16.4 19.475 18 ;
      RECT 18.1 12.55 19.1 18 ;
      RECT 20.75 12.55 23.25 15.25 ;
      RECT 17.2 12.55 23.25 13.55 ;
      RECT 17.2 8.5 18.2 13.55 ;
      RECT 16.7 8.5 18.2 10.1 ;
      RECT 11.925 14.9 13.85 16.5 ;
      RECT 12.4 14.1 15.85 16.1 ;
      RECT 12.4 10.1 13.4 16.5 ;
      RECT 11.65 10.1 13.4 11.7 ;
      RECT 12.75 23.55 15.25 27.25 ;
      RECT 10.3 23.5 11.3 25.1 ;
      RECT 10.3 23.55 15.5 24.95 ;
      RECT 13.9 23.2 15.5 24.95 ;
      RECT 10.325 14.9 11.325 16.5 ;
      RECT 5.975 14.9 6.975 16.5 ;
      RECT 0.4 14.9 1.775 16.5 ;
      RECT 5.975 14.9 11.325 16.3 ;
      RECT 6.35 13 7.35 16.3 ;
      RECT 0.4 13 1.4 16.5 ;
      RECT 0.4 13 7.35 14 ;
      RECT 0.45 28.3 2 29.9 ;
      RECT 0.45 23.5 1.45 29.9 ;
      RECT 8.45 25.95 10.45 27.95 ;
      RECT 0.45 25.95 10.45 26.95 ;
      RECT 0.45 23.5 1.825 25.1 ;
      RECT 4.7 23.5 5.7 25.1 ;
      RECT 2.425 23.5 3.425 25.1 ;
      RECT 2.425 23.6 5.7 25 ;
  END
END HA_X2RL_T5

MACRO HA_X4RL_T5
  CLASS CORE ;
  ORIGIN 0 0 ;
  FOREIGN HA_X4RL_T5 0 0 ;
  SIZE 24 BY 40 ;
  SYMMETRY X Y ;
  SITE DoubleHeightCoreSite_T5 ;
  PIN VDD
    DIRECTION INOUT ;
    USE POWER ;
    PORT
      LAYER SD ;
        RECT 0 -0.5 24 0.5 ;
        RECT 20.9 -0.5 22.5 2 ;
        RECT 0.5 -0.5 2 2.1 ;
        RECT 0 39.5 24 40.5 ;
        RECT 21.9 38.5 23.5 40.5 ;
        RECT 11.5 37.9 13 40.5 ;
    END
  END VDD
  PIN VSS
    DIRECTION INOUT ;
    USE GROUND ;
    PORT
      LAYER SD ;
        RECT 0 19.5 24 20.5 ;
        RECT 12.525 17 13.9 18.6 ;
        RECT 12.525 17 13.525 20.5 ;
        RECT 8.7 23.5 9.7 25.1 ;
        RECT 6.3 23.5 9.7 24.9 ;
        RECT 7.5 19.5 8.5 24.9 ;
        RECT 6.3 23.5 7.3 25.1 ;
        RECT 2.375 15.1 5.4 16.5 ;
        RECT 4.4 14.9 5.4 16.5 ;
        RECT 3.5 15.1 4.5 20.5 ;
        RECT 2.375 14.9 3.375 16.5 ;
    END
  END VSS
  PIN A
    DIRECTION INPUT ;
    USE SIGNAL ;
    PORT
      LAYER MT1 ;
        RECT 0.5 20.5 3.5 23.5 ;
        RECT 0.75 16.75 3.25 19.25 ;
        RECT 1.5 16.75 2.5 23.5 ;
    END
  END A
  PIN B
    DIRECTION INPUT ;
    USE SIGNAL ;
    PORT
      LAYER MT1 ;
        RECT 4.5 20.5 7.5 23.5 ;
        RECT 4.75 16.75 7.25 19.25 ;
        RECT 5.55 16.75 6.55 23.5 ;
    END
  END B
  PIN CO
    DIRECTION INPUT ;
    USE SIGNAL ;
    PORT
      LAYER MT1 ;
        RECT 12.5 24.5 15.5 27.6 ;
    END
  END CO
  PIN S
    DIRECTION INPUT ;
    USE SIGNAL ;
    PORT
      LAYER MT1 ;
        RECT 16.5 12.5 19.5 15.5 ;
    END
  END S
  OBS
    LAYER MT1 ;
      RECT 8.75 20.75 11.25 23.25 ;
      RECT 9.5 16.75 10.5 23.25 ;
      RECT 8.75 16.75 11.25 19.25 ;
    LAYER VIA1 ;
      RECT 17.25 13.25 18.75 14.75 ;
      RECT 13.25 25.6 14.75 27.1 ;
      RECT 9.25 17.25 10.75 18.75 ;
      RECT 9.25 21.25 10.75 22.75 ;
      RECT 5.25 17.25 6.75 18.75 ;
      RECT 5.25 21.25 6.75 22.75 ;
      RECT 1.25 17.25 2.75 18.75 ;
      RECT 1.25 21.25 2.75 22.75 ;
    LAYER GATE ;
      RECT 13.775 15.05 14.625 18.85 ;
      RECT 13.7 15.05 14.7 16.75 ;
      RECT 12.4 14.1 14.4 16.1 ;
      RECT 8.75 16.75 11.25 19.25 ;
      RECT 9.575 14.65 10.425 19.25 ;
      RECT 8.45 25.95 10.45 27.95 ;
      RECT 9.45 25.35 10.45 27.95 ;
      RECT 9.575 20.75 10.425 27.95 ;
      RECT 8.75 20.75 11.25 23.25 ;
      RECT 4.75 16.75 7.25 19.25 ;
      RECT 5.275 14.65 6.125 19.25 ;
      RECT 5.575 20.75 6.425 25.35 ;
      RECT 4.75 20.75 7.25 23.25 ;
      RECT 0.75 16.75 3.25 19.25 ;
      RECT 1.65 14.65 2.5 19.25 ;
      RECT 1.7 20.75 2.55 25.35 ;
      RECT 0.75 20.75 3.25 23.25 ;
      RECT 16.75 12.75 19.25 15.25 ;
      RECT 12.75 25.1 15.25 27.6 ;
    LAYER CONT ;
      RECT 17.5 13.5 18.5 14.5 ;
      RECT 13.5 25.85 14.5 26.85 ;
      RECT 12.9 14.6 13.9 15.6 ;
      RECT 8.95 26.45 9.95 27.45 ;
    LAYER SD ;
      RECT 14.5 17 16.4 18.6 ;
      RECT 15.4 14.25 16.4 18.6 ;
      RECT 15.4 14.25 19.25 15.25 ;
      RECT 16.75 12.75 19.25 15.25 ;
      RECT 17.7 10.7 19.3 12.75 ;
      RECT 12.75 23.6 15.25 27.6 ;
      RECT 10.3 23.5 11.3 25.1 ;
      RECT 13.9 23.2 15.5 25.05 ;
      RECT 10.3 23.6 15.5 25 ;
      RECT 10.3 14.9 11.3 16.5 ;
      RECT 10.3 14.9 14.4 16.1 ;
      RECT 12 14.1 14.4 16.1 ;
      RECT 12 10.1 13 16.1 ;
      RECT 12 10.1 13.5 11.7 ;
      RECT 0.45 26.95 2 29.9 ;
      RECT 0.45 26.95 10.45 27.95 ;
      RECT 8.45 25.95 10.45 27.95 ;
      RECT 0.45 23.5 1.45 29.9 ;
      RECT 0.45 23.5 1.825 25.1 ;
      RECT 8.7 14.9 9.7 16.5 ;
      RECT 6 14.9 7 16.5 ;
      RECT 0.4 14.9 1.775 16.5 ;
      RECT 6 15 9.7 16.4 ;
      RECT 6.375 13 7.375 16.4 ;
      RECT 0.4 13 1.4 16.5 ;
      RECT 0.4 13 7.375 14 ;
      RECT 4.7 23.5 5.7 25.1 ;
      RECT 2.425 23.5 3.425 25.1 ;
      RECT 2.425 23.6 5.7 25 ;
  END
END HA_X4RL_T5

MACRO LAT_X1PC_T5
  CLASS CORE ;
  ORIGIN 0 0 ;
  FOREIGN LAT_X1PC_T5 0 0 ;
  SIZE 32 BY 40 ;
  SYMMETRY X Y ;
  SITE DoubleHeightCoreSite_T5 ;
  PIN VDD
    DIRECTION INOUT ;
    USE POWER ;
    PORT
      LAYER SD ;
        RECT 0 -0.5 32 0.5 ;
        RECT 24.95 -0.5 26.75 2.1 ;
        RECT 3.55 -0.5 5.05 2.1 ;
        RECT 0 39.5 32 40.5 ;
        RECT 16.35 37.9 19.7 40.5 ;
        RECT 16.35 32.25 17.35 40.5 ;
        RECT 14.75 32.25 17.35 33.25 ;
        RECT 14.75 30.5 15.75 33.25 ;
        RECT 13.85 29.75 15.45 31.5 ;
        RECT 10.85 30.5 15.75 31.5 ;
        RECT 10.3 29.15 11.85 30.75 ;
    END
  END VDD
  PIN VSS
    DIRECTION INOUT ;
    USE GROUND ;
    PORT
      LAYER SD ;
        RECT 0 19.5 32 20.5 ;
        RECT 30.225 22.9 31.6 24.5 ;
        RECT 30.6 19.5 31.6 24.5 ;
        RECT 16.825 22.25 18.2 23.85 ;
        RECT 16.825 19.5 17.825 23.85 ;
        RECT 14.4 19.5 16 21.5 ;
        RECT 12.75 17.85 14.35 20.5 ;
        RECT 6.975 23.375 8.575 24.375 ;
        RECT 7.25 19.5 8.25 24.375 ;
        RECT 6 18.5 7.6 20.5 ;
    END
  END VSS
  PIN D
    DIRECTION INPUT ;
    USE SIGNAL ;
    PORT
      LAYER MT1 ;
        RECT 24.5 12.5 27.5 15.5 ;
    END
  END D
  PIN E
    DIRECTION INPUT ;
    USE SIGNAL ;
    PORT
      LAYER MT1 ;
        RECT 28.5 24.5 31.5 27.5 ;
    END
  END E
  PIN Q
    DIRECTION INPUT ;
    USE SIGNAL ;
    PORT
      LAYER MT1 ;
        RECT 16.5 28.5 19.5 31.5 ;
    END
  END Q
  PIN QN
    DIRECTION INPUT ;
    USE SIGNAL ;
    PORT
      LAYER MT1 ;
        RECT 4.5 28.5 7.5 31.5 ;
    END
  END QN
  OBS
    LAYER MT1 ;
      RECT 20.75 21.5 23.25 24 ;
      RECT 21.5 13.6 22.5 24 ;
      RECT 20.75 13.6 23.25 16.1 ;
      RECT 17.25 24.575 19.75 27.075 ;
      RECT 17.5 13 18.5 27.075 ;
      RECT 16.8 13 19.3 15.5 ;
      RECT 8.75 26.4 11.25 28.9 ;
      RECT 9.5 10.5 10.5 28.9 ;
      RECT 9.5 20.75 12 23.25 ;
      RECT 8.75 16 11.25 18.5 ;
      RECT 8.75 10.5 11.25 13 ;
      RECT 0.75 21.55 3.25 24.05 ;
      RECT 1.5 16 2.5 24.05 ;
      RECT 0.75 16 3.25 18.5 ;
    LAYER VIA1 ;
      RECT 29.25 25.25 30.75 26.75 ;
      RECT 25.25 13.25 26.75 14.75 ;
      RECT 21.25 14.1 22.75 15.6 ;
      RECT 21.25 22 22.75 23.5 ;
      RECT 17.75 25.075 19.25 26.575 ;
      RECT 17.3 13.5 18.8 15 ;
      RECT 17.25 29.25 18.75 30.75 ;
      RECT 10 21.25 11.5 22.75 ;
      RECT 9.25 11 10.75 12.5 ;
      RECT 9.25 16.5 10.75 18 ;
      RECT 9.25 26.9 10.75 28.4 ;
      RECT 5.25 29.25 6.75 30.75 ;
      RECT 1.25 16.5 2.75 18 ;
      RECT 1.25 22.05 2.75 23.55 ;
    LAYER GATE ;
      RECT 28.75 24.75 31.25 27.25 ;
      RECT 29.5 22.65 30.35 27.25 ;
      RECT 21.825 13.6 22.675 18.85 ;
      RECT 21.75 13.6 22.75 16.75 ;
      RECT 20.75 13.6 23.25 16.1 ;
      RECT 18 24.1 19 27.1 ;
      RECT 17.25 24.575 19.75 27.075 ;
      RECT 17.25 25 22.025 27 ;
      RECT 18.075 22 18.925 27.1 ;
      RECT 16.8 13 19.3 15.5 ;
      RECT 14.7 13.275 19.3 14.125 ;
      RECT 15.25 16.5 17.25 18.5 ;
      RECT 14.6 17.05 17.25 18.05 ;
      RECT 12.5 17.125 17.25 17.975 ;
      RECT 9.5 20.75 12 23.25 ;
      RECT 9.5 21.3 14.15 22.3 ;
      RECT 9.5 21.375 16.25 22.225 ;
      RECT 12.6 24.25 13.6 29.95 ;
      RECT 12.6 29.025 15.7 29.875 ;
      RECT 8.825 24.25 13.6 25.25 ;
      RECT 5.625 24.25 13.6 25.1 ;
      RECT 5.625 24.1 6.725 25.1 ;
      RECT 5.625 21.55 6.625 25.1 ;
      RECT 0.75 21.55 3.25 24.05 ;
      RECT 0.75 21.55 6.625 22.55 ;
      RECT 7.85 17.7 10.5 18.7 ;
      RECT 5.75 17.775 10.5 18.625 ;
      RECT 8.75 16 11.25 18.5 ;
      RECT 9.575 26.4 10.425 31 ;
      RECT 8.75 26.4 11.25 28.9 ;
      RECT 24.75 12.75 27.25 15.25 ;
      RECT 20.75 21.5 23.25 24 ;
      RECT 16.75 28.75 19.25 31.25 ;
      RECT 8.75 10.5 11.25 13 ;
      RECT 4.75 28.75 7.25 31.25 ;
      RECT 0.75 16 3.25 18.5 ;
    LAYER CONT ;
      RECT 25.5 13.5 26.5 14.5 ;
      RECT 21.5 14.35 22.5 15.35 ;
      RECT 21.5 22.25 22.5 23.25 ;
      RECT 20.525 25.5 21.525 26.5 ;
      RECT 17.5 29.5 18.5 30.5 ;
      RECT 15.75 17 16.75 18 ;
      RECT 9.5 11.25 10.5 12.25 ;
      RECT 9.5 16.75 10.5 17.75 ;
      RECT 5.5 29.5 6.5 30.5 ;
      RECT 1.5 16.75 2.5 17.75 ;
      RECT 1.5 22.3 2.5 23.3 ;
    LAYER SD ;
      RECT 26.2 27.3 27.7 29.9 ;
      RECT 25.25 23.4 26.25 28.3 ;
      RECT 20.025 25 22.025 27 ;
      RECT 20.025 25.6 26.25 26.6 ;
      RECT 28.625 22.9 29.625 24.5 ;
      RECT 25.25 23.4 29.625 24.4 ;
      RECT 22.55 17 23.55 18.6 ;
      RECT 22.55 17.1 25.75 18.5 ;
      RECT 24.75 12.75 25.75 18.5 ;
      RECT 24.75 12.75 27.25 15.25 ;
      RECT 19.8 13.6 23.25 16.1 ;
      RECT 19.8 5.3 21.4 16.1 ;
      RECT 20.75 21.5 23.25 24 ;
      RECT 18.8 22.25 19.8 23.85 ;
      RECT 18.8 22.35 23.25 23.75 ;
      RECT 20.95 17 21.95 18.6 ;
      RECT 15.25 16.5 17.25 18.5 ;
      RECT 15.25 17.1 21.95 18.1 ;
      RECT 15.25 14 16.25 18.5 ;
      RECT 14.95 14 16.55 15 ;
      RECT 16.75 27.775 19.25 31.25 ;
      RECT 13.85 27.775 15.45 29.15 ;
      RECT 13.85 27.775 19.25 28.775 ;
      RECT 14.75 22.1 15.75 28.775 ;
      RECT 14.4 22.1 16 23.1 ;
      RECT 0.75 16 3.25 18.5 ;
      RECT 6 16.9 7.6 17.9 ;
      RECT 0.75 16.5 7.5 17.5 ;
      RECT 6.5 14 7.5 17.9 ;
      RECT 6.5 14 13.25 15 ;
      RECT 12.25 12.025 13.25 15 ;
      RECT 14.95 12.025 16.55 13.4 ;
      RECT 12.25 12.025 16.55 13.025 ;
      RECT 8.75 15.875 11.25 18.5 ;
      RECT 12.75 15.875 14.35 17.25 ;
      RECT 8.75 15.875 14.35 16.875 ;
      RECT 8.75 10.5 11.25 13 ;
      RECT 5.85 10.1 8.75 11.925 ;
      RECT 4.75 28.75 7.25 31.25 ;
      RECT 4.75 29.15 9.7 30.75 ;
      RECT 7.25 24.975 8.275 30.75 ;
      RECT 6.975 24.975 8.575 25.975 ;
      RECT 0.5 24.05 2 26.7 ;
      RECT 0.75 21.55 3.25 24.05 ;
  END
END LAT_X1PC_T5

MACRO LAT_X2PC_T5
  CLASS CORE ;
  ORIGIN 0 0 ;
  FOREIGN LAT_X2PC_T5 0 0 ;
  SIZE 36 BY 40 ;
  SYMMETRY X Y ;
  SITE DoubleHeightCoreSite_T5 ;
  PIN VDD
    DIRECTION INOUT ;
    USE POWER ;
    PORT
      LAYER SD ;
        RECT 0 -0.5 36 0.5 ;
        RECT 33.9 -0.5 35.5 2.1 ;
        RECT 16.1 -0.5 17.6 2.1 ;
        RECT 0 39.5 36 40.5 ;
        RECT 25.15 37.9 27.35 40.5 ;
        RECT 20.5 32.9 21.5 40.5 ;
        RECT 16.325 32.9 21.5 33.9 ;
        RECT 16.325 26.9 17.7 29.5 ;
        RECT 12.75 31.9 17.375 32.9 ;
        RECT 16.325 26.9 17.325 33.9 ;
        RECT 12.75 31.9 15.35 33.275 ;
        RECT 6.9 36.95 8.5 40.5 ;
    END
  END VDD
  PIN VSS
    DIRECTION INOUT ;
    USE GROUND ;
    PORT
      LAYER SD ;
        RECT 0 19.5 36 20.5 ;
        RECT 34.175 21.3 35.55 22.9 ;
        RECT 34.55 19.5 35.55 22.9 ;
        RECT 20.95 22.25 22.325 23.85 ;
        RECT 20.95 19.5 21.95 23.85 ;
        RECT 17.4 19.5 20 21.625 ;
        RECT 16.75 17.825 18.35 20.5 ;
        RECT 12.9 23.5 15.5 24.9 ;
        RECT 11.85 23.5 15.5 24.5 ;
        RECT 11.85 19.5 12.85 24.5 ;
        RECT 10 18.5 11.6 20.5 ;
    END
  END VSS
  PIN D
    DIRECTION INPUT ;
    USE SIGNAL ;
    PORT
      LAYER MT1 ;
        RECT 28.5 12.5 31.5 15.5 ;
    END
  END D
  PIN E
    DIRECTION INPUT ;
    USE SIGNAL ;
    PORT
      LAYER MT1 ;
        RECT 32.5 24.5 35.5 27.5 ;
    END
  END E
  PIN Q
    DIRECTION INPUT ;
    USE SIGNAL ;
    PORT
      LAYER MT1 ;
        RECT 20.5 28.5 23.5 31.5 ;
    END
  END Q
  PIN QN
    DIRECTION INPUT ;
    USE SIGNAL ;
    PORT
      LAYER MT1 ;
        RECT 12.5 36 15.5 39.5 ;
    END
  END QN
  OBS
    LAYER MT1 ;
      RECT 24.75 21.5 27.25 24 ;
      RECT 25.5 13.6 26.5 24 ;
      RECT 24.75 13.6 27.25 16.1 ;
      RECT 20.75 24.75 23.25 27.25 ;
      RECT 21.5 13 22.5 27.25 ;
      RECT 20.8 13 23.3 15.5 ;
      RECT 12.5 29.15 15 31.65 ;
      RECT 13.5 10.5 14.5 31.65 ;
      RECT 13.5 20.75 16 23.25 ;
      RECT 12.75 16 15.25 18.5 ;
      RECT 12.75 10.5 15.25 13 ;
      RECT 8.5 21.55 11 24.05 ;
      RECT 9.5 14 10.5 24.05 ;
      RECT 8.75 14 11.25 16.5 ;
    LAYER VIA1 ;
      RECT 33.25 25.25 34.75 26.75 ;
      RECT 29.25 13.25 30.75 14.75 ;
      RECT 25.25 14.1 26.75 15.6 ;
      RECT 25.25 22 26.75 23.5 ;
      RECT 21.3 13.5 22.8 15 ;
      RECT 21.25 25.25 22.75 26.75 ;
      RECT 21.25 29.25 22.75 30.75 ;
      RECT 14 21.25 15.5 22.75 ;
      RECT 13.25 11 14.75 12.5 ;
      RECT 13.25 16.5 14.75 18 ;
      RECT 13.25 36.5 14.75 38 ;
      RECT 13 29.65 14.5 31.15 ;
      RECT 9.25 14.5 10.75 16 ;
      RECT 9 22.05 10.5 23.55 ;
    LAYER GATE ;
      RECT 32.75 24.75 35.25 27.25 ;
      RECT 33.3 23.15 34.3 27.25 ;
      RECT 33.45 21.05 34.3 27.25 ;
      RECT 25.825 13.6 26.675 18.85 ;
      RECT 25.75 13.6 26.75 16.75 ;
      RECT 24.75 13.6 27.25 16.1 ;
      RECT 20.8 13 23.3 15.5 ;
      RECT 18.7 13.35 23.3 14.2 ;
      RECT 20.75 24.75 23.25 27.25 ;
      RECT 22.125 24.1 23.125 27.25 ;
      RECT 22.2 22 23.05 27.25 ;
      RECT 19.25 16.5 21.25 18.5 ;
      RECT 18.6 17.025 21.25 18.025 ;
      RECT 16.5 17.1 21.25 17.95 ;
      RECT 13.5 20.75 16 23.25 ;
      RECT 13.5 21.5 17.15 22.5 ;
      RECT 13.5 21.5 20.25 22.35 ;
      RECT 17.575 24.75 18.425 29.75 ;
      RECT 17.5 24.75 18.5 26.65 ;
      RECT 15.75 24.75 18.5 25.75 ;
      RECT 10.6 24.75 12.65 25.75 ;
      RECT 10.6 24.775 18.5 25.625 ;
      RECT 10.6 21.55 11.6 25.75 ;
      RECT 8.5 21.55 11.6 24.05 ;
      RECT 11.5 33.15 15.6 34 ;
      RECT 11.5 30.65 12.5 34 ;
      RECT 12.5 29.15 15 31.65 ;
      RECT 11.85 17.7 14.5 18.7 ;
      RECT 9.75 17.775 14.5 18.625 ;
      RECT 12.75 16 15.25 18.5 ;
      RECT 28.75 12.75 31.25 15.25 ;
      RECT 24.75 21.5 27.25 24 ;
      RECT 20.75 28.75 23.25 31.25 ;
      RECT 12.75 10.5 15.25 13 ;
      RECT 12.75 36 15.25 38.5 ;
      RECT 8.75 14 11.25 16.5 ;
    LAYER CONT ;
      RECT 29.5 13.5 30.5 14.5 ;
      RECT 25.5 14.35 26.5 15.35 ;
      RECT 25.5 22.25 26.5 23.25 ;
      RECT 21.5 25.5 22.5 26.5 ;
      RECT 21.5 29.5 22.5 30.5 ;
      RECT 19.75 17 20.75 18 ;
      RECT 13.5 11.25 14.5 12.25 ;
      RECT 13.5 16.75 14.5 17.75 ;
      RECT 13.5 36.75 14.5 37.75 ;
      RECT 9.5 14.75 10.5 15.75 ;
      RECT 9.25 22.3 10.25 23.3 ;
    LAYER SD ;
      RECT 25.55 25 27.05 28.3 ;
      RECT 20.75 24.75 23.25 27.25 ;
      RECT 20.75 25 29.05 26 ;
      RECT 28.05 21.6 29.05 26 ;
      RECT 32.575 21.3 33.575 22.9 ;
      RECT 28.05 21.6 33.575 22.7 ;
      RECT 26.55 17 27.55 18.6 ;
      RECT 26.55 17.1 29.75 18.5 ;
      RECT 28.75 12.75 29.75 18.5 ;
      RECT 28.75 12.75 31.25 15.25 ;
      RECT 24.75 13.6 27.25 16.1 ;
      RECT 24.75 11.15 25.75 16.1 ;
      RECT 21.475 11.15 25.75 12.15 ;
      RECT 21.475 7.4 22.475 12.15 ;
      RECT 21.1 7.4 22.7 9.3 ;
      RECT 24.75 21.5 27.25 24 ;
      RECT 22.925 22.25 23.925 23.85 ;
      RECT 22.925 22.35 27.25 23.75 ;
      RECT 24.95 17 25.95 18.6 ;
      RECT 19.25 16.5 21.25 18.5 ;
      RECT 19.25 17.1 25.95 18.1 ;
      RECT 19.25 14.075 20.25 18.5 ;
      RECT 18.95 14.075 20.55 15.075 ;
      RECT 20.75 28.75 23.25 31.25 ;
      RECT 18.3 28.5 22.5 29.5 ;
      RECT 18.3 26.9 19.75 29.5 ;
      RECT 18.75 22.225 19.75 29.5 ;
      RECT 17.4 22.225 20 23.225 ;
      RECT 10 16.9 11.6 17.9 ;
      RECT 10 14 11.5 17.9 ;
      RECT 8.75 14 11.5 16.5 ;
      RECT 8.75 14 17.25 15 ;
      RECT 16.25 12.1 17.25 15 ;
      RECT 18.95 12.1 20.55 13.475 ;
      RECT 16.25 12.1 20.55 13.1 ;
      RECT 12.75 15.85 15.25 18.5 ;
      RECT 16.75 15.85 18.35 17.225 ;
      RECT 12.75 15.85 18.35 16.85 ;
      RECT 12.75 10.5 15.25 13 ;
      RECT 14.1 8.5 15.6 11.15 ;
      RECT 12.75 33.875 15.25 38.5 ;
      RECT 9.975 34.25 15.35 35.25 ;
      RECT 12.75 33.875 15.35 35.25 ;
      RECT 9.975 26 10.975 35.25 ;
      RECT 9.975 26 15.5 27 ;
      RECT 12.9 25.5 15.5 27 ;
      RECT 0.5 23.95 2.1 26.95 ;
      RECT 0.5 23.95 8.85 25.55 ;
      RECT 7.25 21.55 11 24.05 ;
  END
END LAT_X2PC_T5

MACRO LAT_X4PC_T5
  CLASS CORE ;
  ORIGIN 0 0 ;
  FOREIGN LAT_X4PC_T5 0 0 ;
  SIZE 28 BY 40 ;
  SYMMETRY X Y ;
  SITE DoubleHeightCoreSite_T5 ;
  PIN VDD
    DIRECTION INOUT ;
    USE POWER ;
    PORT
      LAYER SD ;
        RECT 0 -0.5 28 0.5 ;
        RECT 13.8 -0.5 15.4 2.1 ;
        RECT 7.3 -0.5 8.9 2 ;
        RECT 4 -0.5 5.6 2 ;
        RECT 0 39.5 28 40.5 ;
        RECT 12.45 34.7 13.95 40.5 ;
        RECT 5.95 34 8.95 38.6 ;
        RECT 6.95 34 8.45 40.5 ;
    END
  END VDD
  PIN VSS
    DIRECTION INOUT ;
    USE GROUND ;
    PORT
      LAYER SD ;
        RECT 0 19.5 28 20.5 ;
        RECT 26.175 21.3 27.55 22.9 ;
        RECT 26.55 19.5 27.55 22.9 ;
        RECT 11.25 21.4 14.2 23 ;
        RECT 11.25 19.5 13.2 23.15 ;
        RECT 10.875 22.25 11.875 26.85 ;
        RECT 8.75 17.875 10.35 20.5 ;
        RECT 2.75 25.45 7.35 26.45 ;
        RECT 4 19.5 5 26.45 ;
        RECT 2 18.5 3.6 20.5 ;
    END
  END VSS
  PIN D
    DIRECTION INPUT ;
    USE SIGNAL ;
    PORT
      LAYER MT1 ;
        RECT 20.5 12.5 23.5 15.5 ;
    END
  END D
  PIN E
    DIRECTION INPUT ;
    USE SIGNAL ;
    PORT
      LAYER MT1 ;
        RECT 24.5 24.5 27.5 27.5 ;
    END
  END E
  PIN Q
    DIRECTION INPUT ;
    USE SIGNAL ;
    PORT
      LAYER MT1 ;
        RECT 12.5 28.5 15.5 31.5 ;
    END
  END Q
  PIN QN
    DIRECTION INPUT ;
    USE SIGNAL ;
    PORT
      LAYER MT1 ;
        RECT 0.5 32.5 3.5 35.5 ;
    END
  END QN
  OBS
    LAYER MT1 ;
      RECT 16.75 21.5 19.25 24 ;
      RECT 17.5 13.6 18.5 24 ;
      RECT 16.75 13.6 19.25 16.1 ;
      RECT 12.75 24.25 15.25 26.75 ;
      RECT 13.5 13 14.5 26.75 ;
      RECT 12.8 13 15.3 15.5 ;
      RECT 5.05 31.25 7.55 33.75 ;
      RECT 5.5 10.5 6.5 33.75 ;
      RECT 5.5 21.05 8 23.55 ;
      RECT 4.75 16 7.25 18.5 ;
      RECT 4.75 10.5 7.25 13 ;
      RECT 0.5 21.55 3 24.05 ;
      RECT 1.5 14 2.5 24.05 ;
      RECT 0.75 14 3.25 16.5 ;
    LAYER VIA1 ;
      RECT 25.25 25.25 26.75 26.75 ;
      RECT 21.25 13.25 22.75 14.75 ;
      RECT 17.25 14.1 18.75 15.6 ;
      RECT 17.25 22 18.75 23.5 ;
      RECT 13.3 13.5 14.8 15 ;
      RECT 13.25 24.75 14.75 26.25 ;
      RECT 13.25 29.25 14.75 30.75 ;
      RECT 6 21.55 7.5 23.05 ;
      RECT 5.55 31.75 7.05 33.25 ;
      RECT 5.25 11 6.75 12.5 ;
      RECT 5.25 16.5 6.75 18 ;
      RECT 1.25 14.5 2.75 16 ;
      RECT 1.25 33.25 2.75 34.75 ;
      RECT 1 22.05 2.5 23.55 ;
    LAYER GATE ;
      RECT 24.75 24.75 27.25 27.25 ;
      RECT 25.375 23.15 26.375 27.25 ;
      RECT 25.45 21.05 26.3 27.25 ;
      RECT 17.825 13.6 18.675 18.85 ;
      RECT 17.75 13.6 18.75 16.75 ;
      RECT 16.75 13.6 19.25 16.1 ;
      RECT 12.8 13 15.3 15.5 ;
      RECT 10.7 13.35 15.3 14.2 ;
      RECT 12.75 24.25 15.25 26.75 ;
      RECT 14 23.25 15 26.75 ;
      RECT 14.075 21.15 14.925 26.75 ;
      RECT 11.25 16.5 13.25 18.5 ;
      RECT 10.6 17.075 13.25 18.075 ;
      RECT 8.5 17.15 13.25 18 ;
      RECT 10.15 21 11 27.1 ;
      RECT 5.5 21 8 23.55 ;
      RECT 5.5 21 11 22 ;
      RECT 8.825 29.25 9.675 38.85 ;
      RECT 8.75 29.25 9.75 33.75 ;
      RECT 7.65 29.25 9.75 30.25 ;
      RECT 7.65 26.225 8.65 30.25 ;
      RECT 1.2 26.275 2.5 27.275 ;
      RECT 7.6 26.225 8.65 27.225 ;
      RECT 1.2 26.325 8.65 27.175 ;
      RECT 1.2 21.55 2.2 27.275 ;
      RECT 0.5 21.55 3 24.05 ;
      RECT 5.225 31.25 6.075 38.85 ;
      RECT 5.05 31.25 7.55 33.75 ;
      RECT 3.85 17.7 6.5 18.7 ;
      RECT 1.75 17.775 6.5 18.625 ;
      RECT 4.75 16 7.25 18.5 ;
      RECT 20.75 12.75 23.25 15.25 ;
      RECT 16.75 21.5 19.25 24 ;
      RECT 12.75 28.75 15.25 31.25 ;
      RECT 4.75 10.5 7.25 13 ;
      RECT 0.75 14 3.25 16.5 ;
      RECT 0.75 32.75 3.25 35.25 ;
    LAYER CONT ;
      RECT 21.5 13.5 22.5 14.5 ;
      RECT 17.5 14.35 18.5 15.35 ;
      RECT 17.5 22.25 18.5 23.25 ;
      RECT 13.5 25 14.5 26 ;
      RECT 13.5 29.5 14.5 30.5 ;
      RECT 11.75 17 12.75 18 ;
      RECT 5.5 11.25 6.5 12.25 ;
      RECT 5.5 16.75 6.5 17.75 ;
      RECT 1.5 14.75 2.5 15.75 ;
      RECT 1.5 33.5 2.5 34.5 ;
      RECT 1.25 22.3 2.25 23.3 ;
    LAYER SD ;
      RECT 20.35 21.4 21.85 28.3 ;
      RECT 12.75 24.25 15.25 26.75 ;
      RECT 12.75 25 21.85 26 ;
      RECT 24.575 21.3 25.575 22.9 ;
      RECT 20.35 21.4 25.575 22.4 ;
      RECT 18.55 17 19.55 18.6 ;
      RECT 18.55 17.1 21.75 18.5 ;
      RECT 20.75 12.75 21.75 18.5 ;
      RECT 20.75 12.75 23.25 15.25 ;
      RECT 16.75 13.6 19.25 16.1 ;
      RECT 16.8 5.3 18.4 16.1 ;
      RECT 16.75 21.5 19.25 24 ;
      RECT 14.8 21.4 15.8 23 ;
      RECT 14.8 21.5 19.25 22.9 ;
      RECT 16.95 17 17.95 18.6 ;
      RECT 11.25 16.5 13.25 18.5 ;
      RECT 11.25 17.1 17.95 18.1 ;
      RECT 11.25 14.075 12.25 18.5 ;
      RECT 10.95 14.075 12.55 15.075 ;
      RECT 9.55 34 11 38.6 ;
      RECT 10 27.75 11 38.6 ;
      RECT 12.75 28.75 15.25 31.25 ;
      RECT 8.9 27.75 13.75 28.75 ;
      RECT 8.9 22.25 9.9 28.75 ;
      RECT 8.9 22.25 10.275 26.85 ;
      RECT 4.75 10.2 7.25 13 ;
      RECT 4.75 10.2 14.35 11.2 ;
      RECT 10.5 8.7 12.1 11.2 ;
      RECT 2 14 3.6 17.9 ;
      RECT 0.75 14 3.6 16.5 ;
      RECT 0.8 10.7 2.4 16.5 ;
      RECT 0.75 14 9.25 15 ;
      RECT 8.25 12.1 9.25 15 ;
      RECT 10.95 12.1 12.55 13.475 ;
      RECT 8.25 12.1 12.55 13.1 ;
      RECT 4.75 15.9 7.25 18.5 ;
      RECT 8.75 15.9 10.35 17.275 ;
      RECT 4.75 15.9 10.35 16.9 ;
      RECT 4.35 34 5.35 38.6 ;
      RECT 3.8 27.05 4.8 35.25 ;
      RECT 0.75 32.75 4.8 35.25 ;
      RECT 2.75 27.05 7.35 28.05 ;
      RECT 0.5 21.55 3 24.05 ;
  END
END LAT_X4PC_T5

END LIBRARY
